VERSION 5.8 ;
BUSBITCHARS "[]" ;
DIVIDERCHAR "/" ;
UNITS
    DATABASE MICRONS 1000 ;
END UNITS

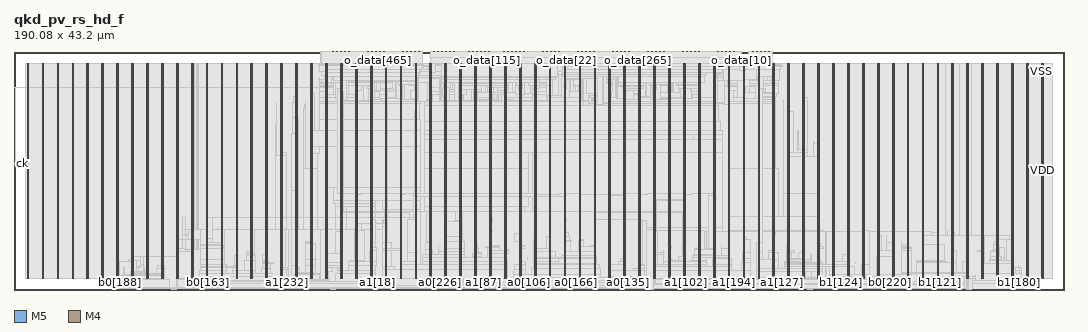
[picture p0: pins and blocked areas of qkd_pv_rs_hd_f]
MACRO qkd_pv_rs_hd_f
  FOREIGN qkd_pv_rs_hd_f 0 0 ;
  CLASS BLOCK ;
  SIZE 190.08 BY 43.2 ;
  PIN a0[0]
    DIRECTION INPUT ;
    USE SIGNAL ;
    PORT
      LAYER M5 ;
        RECT  96.336 0 96.36 0.084 ;
    END
  END a0[0]
  PIN a0[100]
    DIRECTION INPUT ;
    USE SIGNAL ;
    PORT
      LAYER M5 ;
        RECT  92.304 0 92.328 0.084 ;
    END
  END a0[100]
  PIN a0[101]
    DIRECTION INPUT ;
    USE SIGNAL ;
    PORT
      LAYER M5 ;
        RECT  92.448 0 92.472 0.084 ;
    END
  END a0[101]
  PIN a0[102]
    DIRECTION INPUT ;
    USE SIGNAL ;
    PORT
      LAYER M5 ;
        RECT  92.592 0 92.616 0.084 ;
    END
  END a0[102]
  PIN a0[103]
    DIRECTION INPUT ;
    USE SIGNAL ;
    PORT
      LAYER M5 ;
        RECT  92.736 0 92.76 0.084 ;
    END
  END a0[103]
  PIN a0[104]
    DIRECTION INPUT ;
    USE SIGNAL ;
    PORT
      LAYER M5 ;
        RECT  92.88 0 92.904 0.084 ;
    END
  END a0[104]
  PIN a0[105]
    DIRECTION INPUT ;
    USE SIGNAL ;
    PORT
      LAYER M5 ;
        RECT  93.024 0 93.048 0.084 ;
    END
  END a0[105]
  PIN a0[106]
    DIRECTION INPUT ;
    USE SIGNAL ;
    PORT
      LAYER M5 ;
        RECT  93.168 0 93.192 0.084 ;
    END
  END a0[106]
  PIN a0[107]
    DIRECTION INPUT ;
    USE SIGNAL ;
    PORT
      LAYER M5 ;
        RECT  93.312 0 93.336 0.084 ;
    END
  END a0[107]
  PIN a0[108]
    DIRECTION INPUT ;
    USE SIGNAL ;
    PORT
      LAYER M5 ;
        RECT  93.456 0 93.48 0.084 ;
    END
  END a0[108]
  PIN a0[109]
    DIRECTION INPUT ;
    USE SIGNAL ;
    PORT
      LAYER M5 ;
        RECT  93.6 0 93.624 0.084 ;
    END
  END a0[109]
  PIN a0[10]
    DIRECTION INPUT ;
    USE SIGNAL ;
    PORT
      LAYER M5 ;
        RECT  97.776 0 97.8 0.084 ;
    END
  END a0[10]
  PIN a0[110]
    DIRECTION INPUT ;
    USE SIGNAL ;
    PORT
      LAYER M5 ;
        RECT  93.744 0 93.768 0.084 ;
    END
  END a0[110]
  PIN a0[111]
    DIRECTION INPUT ;
    USE SIGNAL ;
    PORT
      LAYER M5 ;
        RECT  93.888 0 93.912 0.084 ;
    END
  END a0[111]
  PIN a0[112]
    DIRECTION INPUT ;
    USE SIGNAL ;
    PORT
      LAYER M5 ;
        RECT  94.032 0 94.056 0.084 ;
    END
  END a0[112]
  PIN a0[113]
    DIRECTION INPUT ;
    USE SIGNAL ;
    PORT
      LAYER M5 ;
        RECT  94.176 0 94.2 0.084 ;
    END
  END a0[113]
  PIN a0[114]
    DIRECTION INPUT ;
    USE SIGNAL ;
    PORT
      LAYER M5 ;
        RECT  94.32 0 94.344 0.084 ;
    END
  END a0[114]
  PIN a0[115]
    DIRECTION INPUT ;
    USE SIGNAL ;
    PORT
      LAYER M5 ;
        RECT  94.464 0 94.488 0.084 ;
    END
  END a0[115]
  PIN a0[116]
    DIRECTION INPUT ;
    USE SIGNAL ;
    PORT
      LAYER M5 ;
        RECT  94.608 0 94.632 0.084 ;
    END
  END a0[116]
  PIN a0[117]
    DIRECTION INPUT ;
    USE SIGNAL ;
    PORT
      LAYER M5 ;
        RECT  94.752 0 94.776 0.084 ;
    END
  END a0[117]
  PIN a0[118]
    DIRECTION INPUT ;
    USE SIGNAL ;
    PORT
      LAYER M5 ;
        RECT  94.896 0 94.92 0.084 ;
    END
  END a0[118]
  PIN a0[119]
    DIRECTION INPUT ;
    USE SIGNAL ;
    PORT
      LAYER M5 ;
        RECT  95.04 0 95.064 0.084 ;
    END
  END a0[119]
  PIN a0[11]
    DIRECTION INPUT ;
    USE SIGNAL ;
    PORT
      LAYER M5 ;
        RECT  97.92 0 97.944 0.084 ;
    END
  END a0[11]
  PIN a0[120]
    DIRECTION INPUT ;
    USE SIGNAL ;
    PORT
      LAYER M5 ;
        RECT  95.184 0 95.208 0.084 ;
    END
  END a0[120]
  PIN a0[121]
    DIRECTION INPUT ;
    USE SIGNAL ;
    PORT
      LAYER M5 ;
        RECT  95.328 0 95.352 0.084 ;
    END
  END a0[121]
  PIN a0[122]
    DIRECTION INPUT ;
    USE SIGNAL ;
    PORT
      LAYER M5 ;
        RECT  95.472 0 95.496 0.084 ;
    END
  END a0[122]
  PIN a0[123]
    DIRECTION INPUT ;
    USE SIGNAL ;
    PORT
      LAYER M5 ;
        RECT  95.616 0 95.64 0.084 ;
    END
  END a0[123]
  PIN a0[124]
    DIRECTION INPUT ;
    USE SIGNAL ;
    PORT
      LAYER M5 ;
        RECT  95.76 0 95.784 0.084 ;
    END
  END a0[124]
  PIN a0[125]
    DIRECTION INPUT ;
    USE SIGNAL ;
    PORT
      LAYER M5 ;
        RECT  95.904 0 95.928 0.084 ;
    END
  END a0[125]
  PIN a0[126]
    DIRECTION INPUT ;
    USE SIGNAL ;
    PORT
      LAYER M5 ;
        RECT  96.048 0 96.072 0.084 ;
    END
  END a0[126]
  PIN a0[127]
    DIRECTION INPUT ;
    USE SIGNAL ;
    PORT
      LAYER M5 ;
        RECT  96.192 0 96.216 0.084 ;
    END
  END a0[127]
  PIN a0[128]
    DIRECTION INPUT ;
    USE SIGNAL ;
    PORT
      LAYER M5 ;
        RECT  110.16 0 110.184 0.084 ;
    END
  END a0[128]
  PIN a0[129]
    DIRECTION INPUT ;
    USE SIGNAL ;
    PORT
      LAYER M5 ;
        RECT  110.304 0 110.328 0.084 ;
    END
  END a0[129]
  PIN a0[12]
    DIRECTION INPUT ;
    USE SIGNAL ;
    PORT
      LAYER M5 ;
        RECT  98.064 0 98.088 0.084 ;
    END
  END a0[12]
  PIN a0[130]
    DIRECTION INPUT ;
    USE SIGNAL ;
    PORT
      LAYER M5 ;
        RECT  110.448 0 110.472 0.084 ;
    END
  END a0[130]
  PIN a0[131]
    DIRECTION INPUT ;
    USE SIGNAL ;
    PORT
      LAYER M5 ;
        RECT  110.592 0 110.616 0.084 ;
    END
  END a0[131]
  PIN a0[132]
    DIRECTION INPUT ;
    USE SIGNAL ;
    PORT
      LAYER M5 ;
        RECT  110.736 0 110.76 0.084 ;
    END
  END a0[132]
  PIN a0[133]
    DIRECTION INPUT ;
    USE SIGNAL ;
    PORT
      LAYER M5 ;
        RECT  110.88 0 110.904 0.084 ;
    END
  END a0[133]
  PIN a0[134]
    DIRECTION INPUT ;
    USE SIGNAL ;
    PORT
      LAYER M5 ;
        RECT  111.024 0 111.048 0.084 ;
    END
  END a0[134]
  PIN a0[135]
    DIRECTION INPUT ;
    USE SIGNAL ;
    PORT
      LAYER M5 ;
        RECT  111.168 0 111.192 0.084 ;
    END
  END a0[135]
  PIN a0[136]
    DIRECTION INPUT ;
    USE SIGNAL ;
    PORT
      LAYER M5 ;
        RECT  111.312 0 111.336 0.084 ;
    END
  END a0[136]
  PIN a0[137]
    DIRECTION INPUT ;
    USE SIGNAL ;
    PORT
      LAYER M5 ;
        RECT  111.456 0 111.48 0.084 ;
    END
  END a0[137]
  PIN a0[138]
    DIRECTION INPUT ;
    USE SIGNAL ;
    PORT
      LAYER M5 ;
        RECT  111.6 0 111.624 0.084 ;
    END
  END a0[138]
  PIN a0[139]
    DIRECTION INPUT ;
    USE SIGNAL ;
    PORT
      LAYER M5 ;
        RECT  111.744 0 111.768 0.084 ;
    END
  END a0[139]
  PIN a0[13]
    DIRECTION INPUT ;
    USE SIGNAL ;
    PORT
      LAYER M5 ;
        RECT  98.208 0 98.232 0.084 ;
    END
  END a0[13]
  PIN a0[140]
    DIRECTION INPUT ;
    USE SIGNAL ;
    PORT
      LAYER M5 ;
        RECT  111.888 0 111.912 0.084 ;
    END
  END a0[140]
  PIN a0[141]
    DIRECTION INPUT ;
    USE SIGNAL ;
    PORT
      LAYER M5 ;
        RECT  112.032 0 112.056 0.084 ;
    END
  END a0[141]
  PIN a0[142]
    DIRECTION INPUT ;
    USE SIGNAL ;
    PORT
      LAYER M5 ;
        RECT  112.176 0 112.2 0.084 ;
    END
  END a0[142]
  PIN a0[143]
    DIRECTION INPUT ;
    USE SIGNAL ;
    PORT
      LAYER M5 ;
        RECT  112.32 0 112.344 0.084 ;
    END
  END a0[143]
  PIN a0[144]
    DIRECTION INPUT ;
    USE SIGNAL ;
    PORT
      LAYER M5 ;
        RECT  112.464 0 112.488 0.084 ;
    END
  END a0[144]
  PIN a0[145]
    DIRECTION INPUT ;
    USE SIGNAL ;
    PORT
      LAYER M5 ;
        RECT  112.608 0 112.632 0.084 ;
    END
  END a0[145]
  PIN a0[146]
    DIRECTION INPUT ;
    USE SIGNAL ;
    PORT
      LAYER M5 ;
        RECT  112.752 0 112.776 0.084 ;
    END
  END a0[146]
  PIN a0[147]
    DIRECTION INPUT ;
    USE SIGNAL ;
    PORT
      LAYER M5 ;
        RECT  112.896 0 112.92 0.084 ;
    END
  END a0[147]
  PIN a0[148]
    DIRECTION INPUT ;
    USE SIGNAL ;
    PORT
      LAYER M5 ;
        RECT  113.04 0 113.064 0.084 ;
    END
  END a0[148]
  PIN a0[149]
    DIRECTION INPUT ;
    USE SIGNAL ;
    PORT
      LAYER M5 ;
        RECT  113.184 0 113.208 0.084 ;
    END
  END a0[149]
  PIN a0[14]
    DIRECTION INPUT ;
    USE SIGNAL ;
    PORT
      LAYER M5 ;
        RECT  98.352 0 98.376 0.084 ;
    END
  END a0[14]
  PIN a0[150]
    DIRECTION INPUT ;
    USE SIGNAL ;
    PORT
      LAYER M5 ;
        RECT  113.328 0 113.352 0.084 ;
    END
  END a0[150]
  PIN a0[151]
    DIRECTION INPUT ;
    USE SIGNAL ;
    PORT
      LAYER M5 ;
        RECT  113.472 0 113.496 0.084 ;
    END
  END a0[151]
  PIN a0[152]
    DIRECTION INPUT ;
    USE SIGNAL ;
    PORT
      LAYER M5 ;
        RECT  113.616 0 113.64 0.084 ;
    END
  END a0[152]
  PIN a0[153]
    DIRECTION INPUT ;
    USE SIGNAL ;
    PORT
      LAYER M5 ;
        RECT  113.76 0 113.784 0.084 ;
    END
  END a0[153]
  PIN a0[154]
    DIRECTION INPUT ;
    USE SIGNAL ;
    PORT
      LAYER M5 ;
        RECT  113.904 0 113.928 0.084 ;
    END
  END a0[154]
  PIN a0[155]
    DIRECTION INPUT ;
    USE SIGNAL ;
    PORT
      LAYER M5 ;
        RECT  114.048 0 114.072 0.084 ;
    END
  END a0[155]
  PIN a0[156]
    DIRECTION INPUT ;
    USE SIGNAL ;
    PORT
      LAYER M5 ;
        RECT  114.192 0 114.216 0.084 ;
    END
  END a0[156]
  PIN a0[157]
    DIRECTION INPUT ;
    USE SIGNAL ;
    PORT
      LAYER M5 ;
        RECT  114.336 0 114.36 0.084 ;
    END
  END a0[157]
  PIN a0[158]
    DIRECTION INPUT ;
    USE SIGNAL ;
    PORT
      LAYER M5 ;
        RECT  114.48 0 114.504 0.084 ;
    END
  END a0[158]
  PIN a0[159]
    DIRECTION INPUT ;
    USE SIGNAL ;
    PORT
      LAYER M5 ;
        RECT  114.624 0 114.648 0.084 ;
    END
  END a0[159]
  PIN a0[15]
    DIRECTION INPUT ;
    USE SIGNAL ;
    PORT
      LAYER M5 ;
        RECT  98.496 0 98.52 0.084 ;
    END
  END a0[15]
  PIN a0[160]
    DIRECTION INPUT ;
    USE SIGNAL ;
    PORT
      LAYER M5 ;
        RECT  100.944 0 100.968 0.084 ;
    END
  END a0[160]
  PIN a0[161]
    DIRECTION INPUT ;
    USE SIGNAL ;
    PORT
      LAYER M5 ;
        RECT  101.088 0 101.112 0.084 ;
    END
  END a0[161]
  PIN a0[162]
    DIRECTION INPUT ;
    USE SIGNAL ;
    PORT
      LAYER M5 ;
        RECT  101.232 0 101.256 0.084 ;
    END
  END a0[162]
  PIN a0[163]
    DIRECTION INPUT ;
    USE SIGNAL ;
    PORT
      LAYER M5 ;
        RECT  101.376 0 101.4 0.084 ;
    END
  END a0[163]
  PIN a0[164]
    DIRECTION INPUT ;
    USE SIGNAL ;
    PORT
      LAYER M5 ;
        RECT  101.52 0 101.544 0.084 ;
    END
  END a0[164]
  PIN a0[165]
    DIRECTION INPUT ;
    USE SIGNAL ;
    PORT
      LAYER M5 ;
        RECT  101.664 0 101.688 0.084 ;
    END
  END a0[165]
  PIN a0[166]
    DIRECTION INPUT ;
    USE SIGNAL ;
    PORT
      LAYER M5 ;
        RECT  101.808 0 101.832 0.084 ;
    END
  END a0[166]
  PIN a0[167]
    DIRECTION INPUT ;
    USE SIGNAL ;
    PORT
      LAYER M5 ;
        RECT  101.952 0 101.976 0.084 ;
    END
  END a0[167]
  PIN a0[168]
    DIRECTION INPUT ;
    USE SIGNAL ;
    PORT
      LAYER M5 ;
        RECT  102.096 0 102.12 0.084 ;
    END
  END a0[168]
  PIN a0[169]
    DIRECTION INPUT ;
    USE SIGNAL ;
    PORT
      LAYER M5 ;
        RECT  102.24 0 102.264 0.084 ;
    END
  END a0[169]
  PIN a0[16]
    DIRECTION INPUT ;
    USE SIGNAL ;
    PORT
      LAYER M5 ;
        RECT  98.64 0 98.664 0.084 ;
    END
  END a0[16]
  PIN a0[170]
    DIRECTION INPUT ;
    USE SIGNAL ;
    PORT
      LAYER M5 ;
        RECT  102.384 0 102.408 0.084 ;
    END
  END a0[170]
  PIN a0[171]
    DIRECTION INPUT ;
    USE SIGNAL ;
    PORT
      LAYER M5 ;
        RECT  102.528 0 102.552 0.084 ;
    END
  END a0[171]
  PIN a0[172]
    DIRECTION INPUT ;
    USE SIGNAL ;
    PORT
      LAYER M5 ;
        RECT  102.672 0 102.696 0.084 ;
    END
  END a0[172]
  PIN a0[173]
    DIRECTION INPUT ;
    USE SIGNAL ;
    PORT
      LAYER M5 ;
        RECT  102.816 0 102.84 0.084 ;
    END
  END a0[173]
  PIN a0[174]
    DIRECTION INPUT ;
    USE SIGNAL ;
    PORT
      LAYER M5 ;
        RECT  102.96 0 102.984 0.084 ;
    END
  END a0[174]
  PIN a0[175]
    DIRECTION INPUT ;
    USE SIGNAL ;
    PORT
      LAYER M5 ;
        RECT  103.104 0 103.128 0.084 ;
    END
  END a0[175]
  PIN a0[176]
    DIRECTION INPUT ;
    USE SIGNAL ;
    PORT
      LAYER M5 ;
        RECT  103.248 0 103.272 0.084 ;
    END
  END a0[176]
  PIN a0[177]
    DIRECTION INPUT ;
    USE SIGNAL ;
    PORT
      LAYER M5 ;
        RECT  103.392 0 103.416 0.084 ;
    END
  END a0[177]
  PIN a0[178]
    DIRECTION INPUT ;
    USE SIGNAL ;
    PORT
      LAYER M5 ;
        RECT  103.536 0 103.56 0.084 ;
    END
  END a0[178]
  PIN a0[179]
    DIRECTION INPUT ;
    USE SIGNAL ;
    PORT
      LAYER M5 ;
        RECT  103.68 0 103.704 0.084 ;
    END
  END a0[179]
  PIN a0[17]
    DIRECTION INPUT ;
    USE SIGNAL ;
    PORT
      LAYER M5 ;
        RECT  98.784 0 98.808 0.084 ;
    END
  END a0[17]
  PIN a0[180]
    DIRECTION INPUT ;
    USE SIGNAL ;
    PORT
      LAYER M5 ;
        RECT  103.824 0 103.848 0.084 ;
    END
  END a0[180]
  PIN a0[181]
    DIRECTION INPUT ;
    USE SIGNAL ;
    PORT
      LAYER M5 ;
        RECT  103.968 0 103.992 0.084 ;
    END
  END a0[181]
  PIN a0[182]
    DIRECTION INPUT ;
    USE SIGNAL ;
    PORT
      LAYER M5 ;
        RECT  104.112 0 104.136 0.084 ;
    END
  END a0[182]
  PIN a0[183]
    DIRECTION INPUT ;
    USE SIGNAL ;
    PORT
      LAYER M5 ;
        RECT  104.256 0 104.28 0.084 ;
    END
  END a0[183]
  PIN a0[184]
    DIRECTION INPUT ;
    USE SIGNAL ;
    PORT
      LAYER M5 ;
        RECT  104.4 0 104.424 0.084 ;
    END
  END a0[184]
  PIN a0[185]
    DIRECTION INPUT ;
    USE SIGNAL ;
    PORT
      LAYER M5 ;
        RECT  104.544 0 104.568 0.084 ;
    END
  END a0[185]
  PIN a0[186]
    DIRECTION INPUT ;
    USE SIGNAL ;
    PORT
      LAYER M5 ;
        RECT  104.688 0 104.712 0.084 ;
    END
  END a0[186]
  PIN a0[187]
    DIRECTION INPUT ;
    USE SIGNAL ;
    PORT
      LAYER M5 ;
        RECT  104.832 0 104.856 0.084 ;
    END
  END a0[187]
  PIN a0[188]
    DIRECTION INPUT ;
    USE SIGNAL ;
    PORT
      LAYER M5 ;
        RECT  104.976 0 105 0.084 ;
    END
  END a0[188]
  PIN a0[189]
    DIRECTION INPUT ;
    USE SIGNAL ;
    PORT
      LAYER M5 ;
        RECT  105.12 0 105.144 0.084 ;
    END
  END a0[189]
  PIN a0[18]
    DIRECTION INPUT ;
    USE SIGNAL ;
    PORT
      LAYER M5 ;
        RECT  98.928 0 98.952 0.084 ;
    END
  END a0[18]
  PIN a0[190]
    DIRECTION INPUT ;
    USE SIGNAL ;
    PORT
      LAYER M5 ;
        RECT  105.264 0 105.288 0.084 ;
    END
  END a0[190]
  PIN a0[191]
    DIRECTION INPUT ;
    USE SIGNAL ;
    PORT
      LAYER M5 ;
        RECT  105.408 0 105.432 0.084 ;
    END
  END a0[191]
  PIN a0[192]
    DIRECTION INPUT ;
    USE SIGNAL ;
    PORT
      LAYER M5 ;
        RECT  58.32 0 58.344 0.084 ;
    END
  END a0[192]
  PIN a0[193]
    DIRECTION INPUT ;
    USE SIGNAL ;
    PORT
      LAYER M5 ;
        RECT  58.464 0 58.488 0.084 ;
    END
  END a0[193]
  PIN a0[194]
    DIRECTION INPUT ;
    USE SIGNAL ;
    PORT
      LAYER M5 ;
        RECT  58.608 0 58.632 0.084 ;
    END
  END a0[194]
  PIN a0[195]
    DIRECTION INPUT ;
    USE SIGNAL ;
    PORT
      LAYER M5 ;
        RECT  58.752 0 58.776 0.084 ;
    END
  END a0[195]
  PIN a0[196]
    DIRECTION INPUT ;
    USE SIGNAL ;
    PORT
      LAYER M5 ;
        RECT  58.896 0 58.92 0.084 ;
    END
  END a0[196]
  PIN a0[197]
    DIRECTION INPUT ;
    USE SIGNAL ;
    PORT
      LAYER M5 ;
        RECT  59.04 0 59.064 0.084 ;
    END
  END a0[197]
  PIN a0[198]
    DIRECTION INPUT ;
    USE SIGNAL ;
    PORT
      LAYER M5 ;
        RECT  59.184 0 59.208 0.084 ;
    END
  END a0[198]
  PIN a0[199]
    DIRECTION INPUT ;
    USE SIGNAL ;
    PORT
      LAYER M5 ;
        RECT  59.328 0 59.352 0.084 ;
    END
  END a0[199]
  PIN a0[19]
    DIRECTION INPUT ;
    USE SIGNAL ;
    PORT
      LAYER M5 ;
        RECT  99.072 0 99.096 0.084 ;
    END
  END a0[19]
  PIN a0[1]
    DIRECTION INPUT ;
    USE SIGNAL ;
    PORT
      LAYER M5 ;
        RECT  96.48 0 96.504 0.084 ;
    END
  END a0[1]
  PIN a0[200]
    DIRECTION INPUT ;
    USE SIGNAL ;
    PORT
      LAYER M5 ;
        RECT  59.472 0 59.496 0.084 ;
    END
  END a0[200]
  PIN a0[201]
    DIRECTION INPUT ;
    USE SIGNAL ;
    PORT
      LAYER M5 ;
        RECT  59.616 0 59.64 0.084 ;
    END
  END a0[201]
  PIN a0[202]
    DIRECTION INPUT ;
    USE SIGNAL ;
    PORT
      LAYER M5 ;
        RECT  59.76 0 59.784 0.084 ;
    END
  END a0[202]
  PIN a0[203]
    DIRECTION INPUT ;
    USE SIGNAL ;
    PORT
      LAYER M5 ;
        RECT  59.904 0 59.928 0.084 ;
    END
  END a0[203]
  PIN a0[204]
    DIRECTION INPUT ;
    USE SIGNAL ;
    PORT
      LAYER M5 ;
        RECT  60.048 0 60.072 0.084 ;
    END
  END a0[204]
  PIN a0[205]
    DIRECTION INPUT ;
    USE SIGNAL ;
    PORT
      LAYER M5 ;
        RECT  60.192 0 60.216 0.084 ;
    END
  END a0[205]
  PIN a0[206]
    DIRECTION INPUT ;
    USE SIGNAL ;
    PORT
      LAYER M5 ;
        RECT  60.336 0 60.36 0.084 ;
    END
  END a0[206]
  PIN a0[207]
    DIRECTION INPUT ;
    USE SIGNAL ;
    PORT
      LAYER M5 ;
        RECT  60.48 0 60.504 0.084 ;
    END
  END a0[207]
  PIN a0[208]
    DIRECTION INPUT ;
    USE SIGNAL ;
    PORT
      LAYER M5 ;
        RECT  60.624 0 60.648 0.084 ;
    END
  END a0[208]
  PIN a0[209]
    DIRECTION INPUT ;
    USE SIGNAL ;
    PORT
      LAYER M5 ;
        RECT  60.768 0 60.792 0.084 ;
    END
  END a0[209]
  PIN a0[20]
    DIRECTION INPUT ;
    USE SIGNAL ;
    PORT
      LAYER M5 ;
        RECT  99.216 0 99.24 0.084 ;
    END
  END a0[20]
  PIN a0[210]
    DIRECTION INPUT ;
    USE SIGNAL ;
    PORT
      LAYER M5 ;
        RECT  60.912 0 60.936 0.084 ;
    END
  END a0[210]
  PIN a0[211]
    DIRECTION INPUT ;
    USE SIGNAL ;
    PORT
      LAYER M5 ;
        RECT  61.056 0 61.08 0.084 ;
    END
  END a0[211]
  PIN a0[212]
    DIRECTION INPUT ;
    USE SIGNAL ;
    PORT
      LAYER M5 ;
        RECT  61.2 0 61.224 0.084 ;
    END
  END a0[212]
  PIN a0[213]
    DIRECTION INPUT ;
    USE SIGNAL ;
    PORT
      LAYER M5 ;
        RECT  61.344 0 61.368 0.084 ;
    END
  END a0[213]
  PIN a0[214]
    DIRECTION INPUT ;
    USE SIGNAL ;
    PORT
      LAYER M5 ;
        RECT  61.488 0 61.512 0.084 ;
    END
  END a0[214]
  PIN a0[215]
    DIRECTION INPUT ;
    USE SIGNAL ;
    PORT
      LAYER M5 ;
        RECT  61.632 0 61.656 0.084 ;
    END
  END a0[215]
  PIN a0[216]
    DIRECTION INPUT ;
    USE SIGNAL ;
    PORT
      LAYER M5 ;
        RECT  61.776 0 61.8 0.084 ;
    END
  END a0[216]
  PIN a0[217]
    DIRECTION INPUT ;
    USE SIGNAL ;
    PORT
      LAYER M5 ;
        RECT  61.92 0 61.944 0.084 ;
    END
  END a0[217]
  PIN a0[218]
    DIRECTION INPUT ;
    USE SIGNAL ;
    PORT
      LAYER M5 ;
        RECT  62.064 0 62.088 0.084 ;
    END
  END a0[218]
  PIN a0[219]
    DIRECTION INPUT ;
    USE SIGNAL ;
    PORT
      LAYER M5 ;
        RECT  62.208 0 62.232 0.084 ;
    END
  END a0[219]
  PIN a0[21]
    DIRECTION INPUT ;
    USE SIGNAL ;
    PORT
      LAYER M5 ;
        RECT  99.36 0 99.384 0.084 ;
    END
  END a0[21]
  PIN a0[220]
    DIRECTION INPUT ;
    USE SIGNAL ;
    PORT
      LAYER M5 ;
        RECT  62.352 0 62.376 0.084 ;
    END
  END a0[220]
  PIN a0[221]
    DIRECTION INPUT ;
    USE SIGNAL ;
    PORT
      LAYER M5 ;
        RECT  62.496 0 62.52 0.084 ;
    END
  END a0[221]
  PIN a0[222]
    DIRECTION INPUT ;
    USE SIGNAL ;
    PORT
      LAYER M5 ;
        RECT  62.64 0 62.664 0.084 ;
    END
  END a0[222]
  PIN a0[223]
    DIRECTION INPUT ;
    USE SIGNAL ;
    PORT
      LAYER M5 ;
        RECT  62.784 0 62.808 0.084 ;
    END
  END a0[223]
  PIN a0[224]
    DIRECTION INPUT ;
    USE SIGNAL ;
    PORT
      LAYER M5 ;
        RECT  76.752 0 76.776 0.084 ;
    END
  END a0[224]
  PIN a0[225]
    DIRECTION INPUT ;
    USE SIGNAL ;
    PORT
      LAYER M5 ;
        RECT  76.896 0 76.92 0.084 ;
    END
  END a0[225]
  PIN a0[226]
    DIRECTION INPUT ;
    USE SIGNAL ;
    PORT
      LAYER M5 ;
        RECT  77.04 0 77.064 0.084 ;
    END
  END a0[226]
  PIN a0[227]
    DIRECTION INPUT ;
    USE SIGNAL ;
    PORT
      LAYER M5 ;
        RECT  77.184 0 77.208 0.084 ;
    END
  END a0[227]
  PIN a0[228]
    DIRECTION INPUT ;
    USE SIGNAL ;
    PORT
      LAYER M5 ;
        RECT  77.328 0 77.352 0.084 ;
    END
  END a0[228]
  PIN a0[229]
    DIRECTION INPUT ;
    USE SIGNAL ;
    PORT
      LAYER M5 ;
        RECT  77.472 0 77.496 0.084 ;
    END
  END a0[229]
  PIN a0[22]
    DIRECTION INPUT ;
    USE SIGNAL ;
    PORT
      LAYER M5 ;
        RECT  99.504 0 99.528 0.084 ;
    END
  END a0[22]
  PIN a0[230]
    DIRECTION INPUT ;
    USE SIGNAL ;
    PORT
      LAYER M5 ;
        RECT  77.616 0 77.64 0.084 ;
    END
  END a0[230]
  PIN a0[231]
    DIRECTION INPUT ;
    USE SIGNAL ;
    PORT
      LAYER M5 ;
        RECT  77.76 0 77.784 0.084 ;
    END
  END a0[231]
  PIN a0[232]
    DIRECTION INPUT ;
    USE SIGNAL ;
    PORT
      LAYER M5 ;
        RECT  77.904 0 77.928 0.084 ;
    END
  END a0[232]
  PIN a0[233]
    DIRECTION INPUT ;
    USE SIGNAL ;
    PORT
      LAYER M5 ;
        RECT  78.048 0 78.072 0.084 ;
    END
  END a0[233]
  PIN a0[234]
    DIRECTION INPUT ;
    USE SIGNAL ;
    PORT
      LAYER M5 ;
        RECT  78.192 0 78.216 0.084 ;
    END
  END a0[234]
  PIN a0[235]
    DIRECTION INPUT ;
    USE SIGNAL ;
    PORT
      LAYER M5 ;
        RECT  78.336 0 78.36 0.084 ;
    END
  END a0[235]
  PIN a0[236]
    DIRECTION INPUT ;
    USE SIGNAL ;
    PORT
      LAYER M5 ;
        RECT  78.48 0 78.504 0.084 ;
    END
  END a0[236]
  PIN a0[237]
    DIRECTION INPUT ;
    USE SIGNAL ;
    PORT
      LAYER M5 ;
        RECT  78.624 0 78.648 0.084 ;
    END
  END a0[237]
  PIN a0[238]
    DIRECTION INPUT ;
    USE SIGNAL ;
    PORT
      LAYER M5 ;
        RECT  78.768 0 78.792 0.084 ;
    END
  END a0[238]
  PIN a0[239]
    DIRECTION INPUT ;
    USE SIGNAL ;
    PORT
      LAYER M5 ;
        RECT  78.912 0 78.936 0.084 ;
    END
  END a0[239]
  PIN a0[23]
    DIRECTION INPUT ;
    USE SIGNAL ;
    PORT
      LAYER M5 ;
        RECT  99.648 0 99.672 0.084 ;
    END
  END a0[23]
  PIN a0[240]
    DIRECTION INPUT ;
    USE SIGNAL ;
    PORT
      LAYER M5 ;
        RECT  79.056 0 79.08 0.084 ;
    END
  END a0[240]
  PIN a0[241]
    DIRECTION INPUT ;
    USE SIGNAL ;
    PORT
      LAYER M5 ;
        RECT  79.2 0 79.224 0.084 ;
    END
  END a0[241]
  PIN a0[242]
    DIRECTION INPUT ;
    USE SIGNAL ;
    PORT
      LAYER M5 ;
        RECT  79.344 0 79.368 0.084 ;
    END
  END a0[242]
  PIN a0[243]
    DIRECTION INPUT ;
    USE SIGNAL ;
    PORT
      LAYER M5 ;
        RECT  79.488 0 79.512 0.084 ;
    END
  END a0[243]
  PIN a0[244]
    DIRECTION INPUT ;
    USE SIGNAL ;
    PORT
      LAYER M5 ;
        RECT  79.632 0 79.656 0.084 ;
    END
  END a0[244]
  PIN a0[245]
    DIRECTION INPUT ;
    USE SIGNAL ;
    PORT
      LAYER M5 ;
        RECT  79.776 0 79.8 0.084 ;
    END
  END a0[245]
  PIN a0[246]
    DIRECTION INPUT ;
    USE SIGNAL ;
    PORT
      LAYER M5 ;
        RECT  79.92 0 79.944 0.084 ;
    END
  END a0[246]
  PIN a0[247]
    DIRECTION INPUT ;
    USE SIGNAL ;
    PORT
      LAYER M5 ;
        RECT  80.064 0 80.088 0.084 ;
    END
  END a0[247]
  PIN a0[248]
    DIRECTION INPUT ;
    USE SIGNAL ;
    PORT
      LAYER M5 ;
        RECT  80.208 0 80.232 0.084 ;
    END
  END a0[248]
  PIN a0[249]
    DIRECTION INPUT ;
    USE SIGNAL ;
    PORT
      LAYER M5 ;
        RECT  80.352 0 80.376 0.084 ;
    END
  END a0[249]
  PIN a0[24]
    DIRECTION INPUT ;
    USE SIGNAL ;
    PORT
      LAYER M5 ;
        RECT  99.792 0 99.816 0.084 ;
    END
  END a0[24]
  PIN a0[250]
    DIRECTION INPUT ;
    USE SIGNAL ;
    PORT
      LAYER M5 ;
        RECT  80.496 0 80.52 0.084 ;
    END
  END a0[250]
  PIN a0[251]
    DIRECTION INPUT ;
    USE SIGNAL ;
    PORT
      LAYER M5 ;
        RECT  80.64 0 80.664 0.084 ;
    END
  END a0[251]
  PIN a0[252]
    DIRECTION INPUT ;
    USE SIGNAL ;
    PORT
      LAYER M5 ;
        RECT  80.784 0 80.808 0.084 ;
    END
  END a0[252]
  PIN a0[253]
    DIRECTION INPUT ;
    USE SIGNAL ;
    PORT
      LAYER M5 ;
        RECT  80.928 0 80.952 0.084 ;
    END
  END a0[253]
  PIN a0[254]
    DIRECTION INPUT ;
    USE SIGNAL ;
    PORT
      LAYER M5 ;
        RECT  81.072 0 81.096 0.084 ;
    END
  END a0[254]
  PIN a0[255]
    DIRECTION INPUT ;
    USE SIGNAL ;
    PORT
      LAYER M5 ;
        RECT  81.216 0 81.24 0.084 ;
    END
  END a0[255]
  PIN a0[256]
    DIRECTION INPUT ;
    USE SIGNAL ;
    PORT
      LAYER M5 ;
        RECT  72.144 0 72.168 0.084 ;
    END
  END a0[256]
  PIN a0[257]
    DIRECTION INPUT ;
    USE SIGNAL ;
    PORT
      LAYER M5 ;
        RECT  72.288 0 72.312 0.084 ;
    END
  END a0[257]
  PIN a0[25]
    DIRECTION INPUT ;
    USE SIGNAL ;
    PORT
      LAYER M5 ;
        RECT  99.936 0 99.96 0.084 ;
    END
  END a0[25]
  PIN a0[26]
    DIRECTION INPUT ;
    USE SIGNAL ;
    PORT
      LAYER M5 ;
        RECT  100.08 0 100.104 0.084 ;
    END
  END a0[26]
  PIN a0[27]
    DIRECTION INPUT ;
    USE SIGNAL ;
    PORT
      LAYER M5 ;
        RECT  100.224 0 100.248 0.084 ;
    END
  END a0[27]
  PIN a0[28]
    DIRECTION INPUT ;
    USE SIGNAL ;
    PORT
      LAYER M5 ;
        RECT  100.368 0 100.392 0.084 ;
    END
  END a0[28]
  PIN a0[29]
    DIRECTION INPUT ;
    USE SIGNAL ;
    PORT
      LAYER M5 ;
        RECT  100.512 0 100.536 0.084 ;
    END
  END a0[29]
  PIN a0[2]
    DIRECTION INPUT ;
    USE SIGNAL ;
    PORT
      LAYER M5 ;
        RECT  96.624 0 96.648 0.084 ;
    END
  END a0[2]
  PIN a0[30]
    DIRECTION INPUT ;
    USE SIGNAL ;
    PORT
      LAYER M5 ;
        RECT  100.656 0 100.68 0.084 ;
    END
  END a0[30]
  PIN a0[31]
    DIRECTION INPUT ;
    USE SIGNAL ;
    PORT
      LAYER M5 ;
        RECT  100.8 0 100.824 0.084 ;
    END
  END a0[31]
  PIN a0[32]
    DIRECTION INPUT ;
    USE SIGNAL ;
    PORT
      LAYER M5 ;
        RECT  105.552 0 105.576 0.084 ;
    END
  END a0[32]
  PIN a0[33]
    DIRECTION INPUT ;
    USE SIGNAL ;
    PORT
      LAYER M5 ;
        RECT  105.696 0 105.72 0.084 ;
    END
  END a0[33]
  PIN a0[34]
    DIRECTION INPUT ;
    USE SIGNAL ;
    PORT
      LAYER M5 ;
        RECT  105.84 0 105.864 0.084 ;
    END
  END a0[34]
  PIN a0[35]
    DIRECTION INPUT ;
    USE SIGNAL ;
    PORT
      LAYER M5 ;
        RECT  105.984 0 106.008 0.084 ;
    END
  END a0[35]
  PIN a0[36]
    DIRECTION INPUT ;
    USE SIGNAL ;
    PORT
      LAYER M5 ;
        RECT  106.128 0 106.152 0.084 ;
    END
  END a0[36]
  PIN a0[37]
    DIRECTION INPUT ;
    USE SIGNAL ;
    PORT
      LAYER M5 ;
        RECT  106.272 0 106.296 0.084 ;
    END
  END a0[37]
  PIN a0[38]
    DIRECTION INPUT ;
    USE SIGNAL ;
    PORT
      LAYER M5 ;
        RECT  106.416 0 106.44 0.084 ;
    END
  END a0[38]
  PIN a0[39]
    DIRECTION INPUT ;
    USE SIGNAL ;
    PORT
      LAYER M5 ;
        RECT  106.56 0 106.584 0.084 ;
    END
  END a0[39]
  PIN a0[3]
    DIRECTION INPUT ;
    USE SIGNAL ;
    PORT
      LAYER M5 ;
        RECT  96.768 0 96.792 0.084 ;
    END
  END a0[3]
  PIN a0[40]
    DIRECTION INPUT ;
    USE SIGNAL ;
    PORT
      LAYER M5 ;
        RECT  106.704 0 106.728 0.084 ;
    END
  END a0[40]
  PIN a0[41]
    DIRECTION INPUT ;
    USE SIGNAL ;
    PORT
      LAYER M5 ;
        RECT  106.848 0 106.872 0.084 ;
    END
  END a0[41]
  PIN a0[42]
    DIRECTION INPUT ;
    USE SIGNAL ;
    PORT
      LAYER M5 ;
        RECT  106.992 0 107.016 0.084 ;
    END
  END a0[42]
  PIN a0[43]
    DIRECTION INPUT ;
    USE SIGNAL ;
    PORT
      LAYER M5 ;
        RECT  107.136 0 107.16 0.084 ;
    END
  END a0[43]
  PIN a0[44]
    DIRECTION INPUT ;
    USE SIGNAL ;
    PORT
      LAYER M5 ;
        RECT  107.28 0 107.304 0.084 ;
    END
  END a0[44]
  PIN a0[45]
    DIRECTION INPUT ;
    USE SIGNAL ;
    PORT
      LAYER M5 ;
        RECT  107.424 0 107.448 0.084 ;
    END
  END a0[45]
  PIN a0[46]
    DIRECTION INPUT ;
    USE SIGNAL ;
    PORT
      LAYER M5 ;
        RECT  107.568 0 107.592 0.084 ;
    END
  END a0[46]
  PIN a0[47]
    DIRECTION INPUT ;
    USE SIGNAL ;
    PORT
      LAYER M5 ;
        RECT  107.712 0 107.736 0.084 ;
    END
  END a0[47]
  PIN a0[48]
    DIRECTION INPUT ;
    USE SIGNAL ;
    PORT
      LAYER M5 ;
        RECT  107.856 0 107.88 0.084 ;
    END
  END a0[48]
  PIN a0[49]
    DIRECTION INPUT ;
    USE SIGNAL ;
    PORT
      LAYER M5 ;
        RECT  108 0 108.024 0.084 ;
    END
  END a0[49]
  PIN a0[4]
    DIRECTION INPUT ;
    USE SIGNAL ;
    PORT
      LAYER M5 ;
        RECT  96.912 0 96.936 0.084 ;
    END
  END a0[4]
  PIN a0[50]
    DIRECTION INPUT ;
    USE SIGNAL ;
    PORT
      LAYER M5 ;
        RECT  108.144 0 108.168 0.084 ;
    END
  END a0[50]
  PIN a0[51]
    DIRECTION INPUT ;
    USE SIGNAL ;
    PORT
      LAYER M5 ;
        RECT  108.288 0 108.312 0.084 ;
    END
  END a0[51]
  PIN a0[52]
    DIRECTION INPUT ;
    USE SIGNAL ;
    PORT
      LAYER M5 ;
        RECT  108.432 0 108.456 0.084 ;
    END
  END a0[52]
  PIN a0[53]
    DIRECTION INPUT ;
    USE SIGNAL ;
    PORT
      LAYER M5 ;
        RECT  108.576 0 108.6 0.084 ;
    END
  END a0[53]
  PIN a0[54]
    DIRECTION INPUT ;
    USE SIGNAL ;
    PORT
      LAYER M5 ;
        RECT  108.72 0 108.744 0.084 ;
    END
  END a0[54]
  PIN a0[55]
    DIRECTION INPUT ;
    USE SIGNAL ;
    PORT
      LAYER M5 ;
        RECT  108.864 0 108.888 0.084 ;
    END
  END a0[55]
  PIN a0[56]
    DIRECTION INPUT ;
    USE SIGNAL ;
    PORT
      LAYER M5 ;
        RECT  109.008 0 109.032 0.084 ;
    END
  END a0[56]
  PIN a0[57]
    DIRECTION INPUT ;
    USE SIGNAL ;
    PORT
      LAYER M5 ;
        RECT  109.152 0 109.176 0.084 ;
    END
  END a0[57]
  PIN a0[58]
    DIRECTION INPUT ;
    USE SIGNAL ;
    PORT
      LAYER M5 ;
        RECT  109.296 0 109.32 0.084 ;
    END
  END a0[58]
  PIN a0[59]
    DIRECTION INPUT ;
    USE SIGNAL ;
    PORT
      LAYER M5 ;
        RECT  109.44 0 109.464 0.084 ;
    END
  END a0[59]
  PIN a0[5]
    DIRECTION INPUT ;
    USE SIGNAL ;
    PORT
      LAYER M5 ;
        RECT  97.056 0 97.08 0.084 ;
    END
  END a0[5]
  PIN a0[60]
    DIRECTION INPUT ;
    USE SIGNAL ;
    PORT
      LAYER M5 ;
        RECT  109.584 0 109.608 0.084 ;
    END
  END a0[60]
  PIN a0[61]
    DIRECTION INPUT ;
    USE SIGNAL ;
    PORT
      LAYER M5 ;
        RECT  109.728 0 109.752 0.084 ;
    END
  END a0[61]
  PIN a0[62]
    DIRECTION INPUT ;
    USE SIGNAL ;
    PORT
      LAYER M5 ;
        RECT  109.872 0 109.896 0.084 ;
    END
  END a0[62]
  PIN a0[63]
    DIRECTION INPUT ;
    USE SIGNAL ;
    PORT
      LAYER M5 ;
        RECT  110.016 0 110.04 0.084 ;
    END
  END a0[63]
  PIN a0[64]
    DIRECTION INPUT ;
    USE SIGNAL ;
    PORT
      LAYER M5 ;
        RECT  87.12 0 87.144 0.084 ;
    END
  END a0[64]
  PIN a0[65]
    DIRECTION INPUT ;
    USE SIGNAL ;
    PORT
      LAYER M5 ;
        RECT  87.264 0 87.288 0.084 ;
    END
  END a0[65]
  PIN a0[66]
    DIRECTION INPUT ;
    USE SIGNAL ;
    PORT
      LAYER M5 ;
        RECT  87.408 0 87.432 0.084 ;
    END
  END a0[66]
  PIN a0[67]
    DIRECTION INPUT ;
    USE SIGNAL ;
    PORT
      LAYER M5 ;
        RECT  87.552 0 87.576 0.084 ;
    END
  END a0[67]
  PIN a0[68]
    DIRECTION INPUT ;
    USE SIGNAL ;
    PORT
      LAYER M5 ;
        RECT  87.696 0 87.72 0.084 ;
    END
  END a0[68]
  PIN a0[69]
    DIRECTION INPUT ;
    USE SIGNAL ;
    PORT
      LAYER M5 ;
        RECT  87.84 0 87.864 0.084 ;
    END
  END a0[69]
  PIN a0[6]
    DIRECTION INPUT ;
    USE SIGNAL ;
    PORT
      LAYER M5 ;
        RECT  97.2 0 97.224 0.084 ;
    END
  END a0[6]
  PIN a0[70]
    DIRECTION INPUT ;
    USE SIGNAL ;
    PORT
      LAYER M5 ;
        RECT  87.984 0 88.008 0.084 ;
    END
  END a0[70]
  PIN a0[71]
    DIRECTION INPUT ;
    USE SIGNAL ;
    PORT
      LAYER M5 ;
        RECT  88.128 0 88.152 0.084 ;
    END
  END a0[71]
  PIN a0[72]
    DIRECTION INPUT ;
    USE SIGNAL ;
    PORT
      LAYER M5 ;
        RECT  88.272 0 88.296 0.084 ;
    END
  END a0[72]
  PIN a0[73]
    DIRECTION INPUT ;
    USE SIGNAL ;
    PORT
      LAYER M5 ;
        RECT  88.416 0 88.44 0.084 ;
    END
  END a0[73]
  PIN a0[74]
    DIRECTION INPUT ;
    USE SIGNAL ;
    PORT
      LAYER M5 ;
        RECT  88.56 0 88.584 0.084 ;
    END
  END a0[74]
  PIN a0[75]
    DIRECTION INPUT ;
    USE SIGNAL ;
    PORT
      LAYER M5 ;
        RECT  88.704 0 88.728 0.084 ;
    END
  END a0[75]
  PIN a0[76]
    DIRECTION INPUT ;
    USE SIGNAL ;
    PORT
      LAYER M5 ;
        RECT  88.848 0 88.872 0.084 ;
    END
  END a0[76]
  PIN a0[77]
    DIRECTION INPUT ;
    USE SIGNAL ;
    PORT
      LAYER M5 ;
        RECT  88.992 0 89.016 0.084 ;
    END
  END a0[77]
  PIN a0[78]
    DIRECTION INPUT ;
    USE SIGNAL ;
    PORT
      LAYER M5 ;
        RECT  89.136 0 89.16 0.084 ;
    END
  END a0[78]
  PIN a0[79]
    DIRECTION INPUT ;
    USE SIGNAL ;
    PORT
      LAYER M5 ;
        RECT  89.28 0 89.304 0.084 ;
    END
  END a0[79]
  PIN a0[7]
    DIRECTION INPUT ;
    USE SIGNAL ;
    PORT
      LAYER M5 ;
        RECT  97.344 0 97.368 0.084 ;
    END
  END a0[7]
  PIN a0[80]
    DIRECTION INPUT ;
    USE SIGNAL ;
    PORT
      LAYER M5 ;
        RECT  89.424 0 89.448 0.084 ;
    END
  END a0[80]
  PIN a0[81]
    DIRECTION INPUT ;
    USE SIGNAL ;
    PORT
      LAYER M5 ;
        RECT  89.568 0 89.592 0.084 ;
    END
  END a0[81]
  PIN a0[82]
    DIRECTION INPUT ;
    USE SIGNAL ;
    PORT
      LAYER M5 ;
        RECT  89.712 0 89.736 0.084 ;
    END
  END a0[82]
  PIN a0[83]
    DIRECTION INPUT ;
    USE SIGNAL ;
    PORT
      LAYER M5 ;
        RECT  89.856 0 89.88 0.084 ;
    END
  END a0[83]
  PIN a0[84]
    DIRECTION INPUT ;
    USE SIGNAL ;
    PORT
      LAYER M5 ;
        RECT  90 0 90.024 0.084 ;
    END
  END a0[84]
  PIN a0[85]
    DIRECTION INPUT ;
    USE SIGNAL ;
    PORT
      LAYER M5 ;
        RECT  90.144 0 90.168 0.084 ;
    END
  END a0[85]
  PIN a0[86]
    DIRECTION INPUT ;
    USE SIGNAL ;
    PORT
      LAYER M5 ;
        RECT  90.288 0 90.312 0.084 ;
    END
  END a0[86]
  PIN a0[87]
    DIRECTION INPUT ;
    USE SIGNAL ;
    PORT
      LAYER M5 ;
        RECT  90.432 0 90.456 0.084 ;
    END
  END a0[87]
  PIN a0[88]
    DIRECTION INPUT ;
    USE SIGNAL ;
    PORT
      LAYER M5 ;
        RECT  90.576 0 90.6 0.084 ;
    END
  END a0[88]
  PIN a0[89]
    DIRECTION INPUT ;
    USE SIGNAL ;
    PORT
      LAYER M5 ;
        RECT  90.72 0 90.744 0.084 ;
    END
  END a0[89]
  PIN a0[8]
    DIRECTION INPUT ;
    USE SIGNAL ;
    PORT
      LAYER M5 ;
        RECT  97.488 0 97.512 0.084 ;
    END
  END a0[8]
  PIN a0[90]
    DIRECTION INPUT ;
    USE SIGNAL ;
    PORT
      LAYER M5 ;
        RECT  90.864 0 90.888 0.084 ;
    END
  END a0[90]
  PIN a0[91]
    DIRECTION INPUT ;
    USE SIGNAL ;
    PORT
      LAYER M5 ;
        RECT  91.008 0 91.032 0.084 ;
    END
  END a0[91]
  PIN a0[92]
    DIRECTION INPUT ;
    USE SIGNAL ;
    PORT
      LAYER M5 ;
        RECT  91.152 0 91.176 0.084 ;
    END
  END a0[92]
  PIN a0[93]
    DIRECTION INPUT ;
    USE SIGNAL ;
    PORT
      LAYER M5 ;
        RECT  91.296 0 91.32 0.084 ;
    END
  END a0[93]
  PIN a0[94]
    DIRECTION INPUT ;
    USE SIGNAL ;
    PORT
      LAYER M5 ;
        RECT  91.44 0 91.464 0.084 ;
    END
  END a0[94]
  PIN a0[95]
    DIRECTION INPUT ;
    USE SIGNAL ;
    PORT
      LAYER M5 ;
        RECT  91.584 0 91.608 0.084 ;
    END
  END a0[95]
  PIN a0[96]
    DIRECTION INPUT ;
    USE SIGNAL ;
    PORT
      LAYER M5 ;
        RECT  91.728 0 91.752 0.084 ;
    END
  END a0[96]
  PIN a0[97]
    DIRECTION INPUT ;
    USE SIGNAL ;
    PORT
      LAYER M5 ;
        RECT  91.872 0 91.896 0.084 ;
    END
  END a0[97]
  PIN a0[98]
    DIRECTION INPUT ;
    USE SIGNAL ;
    PORT
      LAYER M5 ;
        RECT  92.016 0 92.04 0.084 ;
    END
  END a0[98]
  PIN a0[99]
    DIRECTION INPUT ;
    USE SIGNAL ;
    PORT
      LAYER M5 ;
        RECT  92.16 0 92.184 0.084 ;
    END
  END a0[99]
  PIN a0[9]
    DIRECTION INPUT ;
    USE SIGNAL ;
    PORT
      LAYER M5 ;
        RECT  97.632 0 97.656 0.084 ;
    END
  END a0[9]
  PIN a0t
    DIRECTION INPUT ;
    USE SIGNAL ;
    PORT
      LAYER M5 ;
        RECT  72.432 0 72.456 0.084 ;
    END
  END a0t
  PIN a0v[0]
    DIRECTION INPUT ;
    USE SIGNAL ;
    PORT
      LAYER M5 ;
        RECT  72.576 0 72.6 0.084 ;
    END
  END a0v[0]
  PIN a0v[10]
    DIRECTION INPUT ;
    USE SIGNAL ;
    PORT
      LAYER M5 ;
        RECT  74.016 0 74.04 0.084 ;
    END
  END a0v[10]
  PIN a0v[11]
    DIRECTION INPUT ;
    USE SIGNAL ;
    PORT
      LAYER M5 ;
        RECT  74.16 0 74.184 0.084 ;
    END
  END a0v[11]
  PIN a0v[12]
    DIRECTION INPUT ;
    USE SIGNAL ;
    PORT
      LAYER M5 ;
        RECT  74.304 0 74.328 0.084 ;
    END
  END a0v[12]
  PIN a0v[13]
    DIRECTION INPUT ;
    USE SIGNAL ;
    PORT
      LAYER M5 ;
        RECT  74.448 0 74.472 0.084 ;
    END
  END a0v[13]
  PIN a0v[14]
    DIRECTION INPUT ;
    USE SIGNAL ;
    PORT
      LAYER M5 ;
        RECT  74.592 0 74.616 0.084 ;
    END
  END a0v[14]
  PIN a0v[15]
    DIRECTION INPUT ;
    USE SIGNAL ;
    PORT
      LAYER M5 ;
        RECT  74.736 0 74.76 0.084 ;
    END
  END a0v[15]
  PIN a0v[16]
    DIRECTION INPUT ;
    USE SIGNAL ;
    PORT
      LAYER M5 ;
        RECT  74.88 0 74.904 0.084 ;
    END
  END a0v[16]
  PIN a0v[17]
    DIRECTION INPUT ;
    USE SIGNAL ;
    PORT
      LAYER M5 ;
        RECT  75.024 0 75.048 0.084 ;
    END
  END a0v[17]
  PIN a0v[18]
    DIRECTION INPUT ;
    USE SIGNAL ;
    PORT
      LAYER M5 ;
        RECT  75.168 0 75.192 0.084 ;
    END
  END a0v[18]
  PIN a0v[19]
    DIRECTION INPUT ;
    USE SIGNAL ;
    PORT
      LAYER M5 ;
        RECT  75.312 0 75.336 0.084 ;
    END
  END a0v[19]
  PIN a0v[1]
    DIRECTION INPUT ;
    USE SIGNAL ;
    PORT
      LAYER M5 ;
        RECT  72.72 0 72.744 0.084 ;
    END
  END a0v[1]
  PIN a0v[20]
    DIRECTION INPUT ;
    USE SIGNAL ;
    PORT
      LAYER M5 ;
        RECT  75.456 0 75.48 0.084 ;
    END
  END a0v[20]
  PIN a0v[21]
    DIRECTION INPUT ;
    USE SIGNAL ;
    PORT
      LAYER M5 ;
        RECT  75.6 0 75.624 0.084 ;
    END
  END a0v[21]
  PIN a0v[22]
    DIRECTION INPUT ;
    USE SIGNAL ;
    PORT
      LAYER M5 ;
        RECT  75.744 0 75.768 0.084 ;
    END
  END a0v[22]
  PIN a0v[23]
    DIRECTION INPUT ;
    USE SIGNAL ;
    PORT
      LAYER M5 ;
        RECT  75.888 0 75.912 0.084 ;
    END
  END a0v[23]
  PIN a0v[24]
    DIRECTION INPUT ;
    USE SIGNAL ;
    PORT
      LAYER M5 ;
        RECT  76.032 0 76.056 0.084 ;
    END
  END a0v[24]
  PIN a0v[25]
    DIRECTION INPUT ;
    USE SIGNAL ;
    PORT
      LAYER M5 ;
        RECT  76.176 0 76.2 0.084 ;
    END
  END a0v[25]
  PIN a0v[26]
    DIRECTION INPUT ;
    USE SIGNAL ;
    PORT
      LAYER M5 ;
        RECT  76.32 0 76.344 0.084 ;
    END
  END a0v[26]
  PIN a0v[27]
    DIRECTION INPUT ;
    USE SIGNAL ;
    PORT
      LAYER M5 ;
        RECT  76.464 0 76.488 0.084 ;
    END
  END a0v[27]
  PIN a0v[28]
    DIRECTION INPUT ;
    USE SIGNAL ;
    PORT
      LAYER M5 ;
        RECT  76.608 0 76.632 0.084 ;
    END
  END a0v[28]
  PIN a0v[29]
    DIRECTION INPUT ;
    USE SIGNAL ;
    PORT
      LAYER M5 ;
        RECT  62.928 0 62.952 0.084 ;
    END
  END a0v[29]
  PIN a0v[2]
    DIRECTION INPUT ;
    USE SIGNAL ;
    PORT
      LAYER M5 ;
        RECT  72.864 0 72.888 0.084 ;
    END
  END a0v[2]
  PIN a0v[30]
    DIRECTION INPUT ;
    USE SIGNAL ;
    PORT
      LAYER M5 ;
        RECT  63.072 0 63.096 0.084 ;
    END
  END a0v[30]
  PIN a0v[3]
    DIRECTION INPUT ;
    USE SIGNAL ;
    PORT
      LAYER M5 ;
        RECT  73.008 0 73.032 0.084 ;
    END
  END a0v[3]
  PIN a0v[4]
    DIRECTION INPUT ;
    USE SIGNAL ;
    PORT
      LAYER M5 ;
        RECT  73.152 0 73.176 0.084 ;
    END
  END a0v[4]
  PIN a0v[5]
    DIRECTION INPUT ;
    USE SIGNAL ;
    PORT
      LAYER M5 ;
        RECT  73.296 0 73.32 0.084 ;
    END
  END a0v[5]
  PIN a0v[6]
    DIRECTION INPUT ;
    USE SIGNAL ;
    PORT
      LAYER M5 ;
        RECT  73.44 0 73.464 0.084 ;
    END
  END a0v[6]
  PIN a0v[7]
    DIRECTION INPUT ;
    USE SIGNAL ;
    PORT
      LAYER M5 ;
        RECT  73.584 0 73.608 0.084 ;
    END
  END a0v[7]
  PIN a0v[8]
    DIRECTION INPUT ;
    USE SIGNAL ;
    PORT
      LAYER M5 ;
        RECT  73.728 0 73.752 0.084 ;
    END
  END a0v[8]
  PIN a0v[9]
    DIRECTION INPUT ;
    USE SIGNAL ;
    PORT
      LAYER M5 ;
        RECT  73.872 0 73.896 0.084 ;
    END
  END a0v[9]
  PIN a1[0]
    DIRECTION INPUT ;
    USE SIGNAL ;
    PORT
      LAYER M5 ;
        RECT  63.216 0 63.24 0.084 ;
    END
  END a1[0]
  PIN a1[100]
    DIRECTION INPUT ;
    USE SIGNAL ;
    PORT
      LAYER M5 ;
        RECT  121.392 0 121.416 0.084 ;
    END
  END a1[100]
  PIN a1[101]
    DIRECTION INPUT ;
    USE SIGNAL ;
    PORT
      LAYER M5 ;
        RECT  121.536 0 121.56 0.084 ;
    END
  END a1[101]
  PIN a1[102]
    DIRECTION INPUT ;
    USE SIGNAL ;
    PORT
      LAYER M5 ;
        RECT  121.68 0 121.704 0.084 ;
    END
  END a1[102]
  PIN a1[103]
    DIRECTION INPUT ;
    USE SIGNAL ;
    PORT
      LAYER M5 ;
        RECT  121.824 0 121.848 0.084 ;
    END
  END a1[103]
  PIN a1[104]
    DIRECTION INPUT ;
    USE SIGNAL ;
    PORT
      LAYER M5 ;
        RECT  121.968 0 121.992 0.084 ;
    END
  END a1[104]
  PIN a1[105]
    DIRECTION INPUT ;
    USE SIGNAL ;
    PORT
      LAYER M5 ;
        RECT  122.112 0 122.136 0.084 ;
    END
  END a1[105]
  PIN a1[106]
    DIRECTION INPUT ;
    USE SIGNAL ;
    PORT
      LAYER M5 ;
        RECT  122.256 0 122.28 0.084 ;
    END
  END a1[106]
  PIN a1[107]
    DIRECTION INPUT ;
    USE SIGNAL ;
    PORT
      LAYER M5 ;
        RECT  122.4 0 122.424 0.084 ;
    END
  END a1[107]
  PIN a1[108]
    DIRECTION INPUT ;
    USE SIGNAL ;
    PORT
      LAYER M5 ;
        RECT  122.544 0 122.568 0.084 ;
    END
  END a1[108]
  PIN a1[109]
    DIRECTION INPUT ;
    USE SIGNAL ;
    PORT
      LAYER M5 ;
        RECT  122.688 0 122.712 0.084 ;
    END
  END a1[109]
  PIN a1[10]
    DIRECTION INPUT ;
    USE SIGNAL ;
    PORT
      LAYER M5 ;
        RECT  64.656 0 64.68 0.084 ;
    END
  END a1[10]
  PIN a1[110]
    DIRECTION INPUT ;
    USE SIGNAL ;
    PORT
      LAYER M5 ;
        RECT  122.832 0 122.856 0.084 ;
    END
  END a1[110]
  PIN a1[111]
    DIRECTION INPUT ;
    USE SIGNAL ;
    PORT
      LAYER M5 ;
        RECT  122.976 0 123 0.084 ;
    END
  END a1[111]
  PIN a1[112]
    DIRECTION INPUT ;
    USE SIGNAL ;
    PORT
      LAYER M5 ;
        RECT  123.12 0 123.144 0.084 ;
    END
  END a1[112]
  PIN a1[113]
    DIRECTION INPUT ;
    USE SIGNAL ;
    PORT
      LAYER M5 ;
        RECT  123.264 0 123.288 0.084 ;
    END
  END a1[113]
  PIN a1[114]
    DIRECTION INPUT ;
    USE SIGNAL ;
    PORT
      LAYER M5 ;
        RECT  123.408 0 123.432 0.084 ;
    END
  END a1[114]
  PIN a1[115]
    DIRECTION INPUT ;
    USE SIGNAL ;
    PORT
      LAYER M5 ;
        RECT  123.552 0 123.576 0.084 ;
    END
  END a1[115]
  PIN a1[116]
    DIRECTION INPUT ;
    USE SIGNAL ;
    PORT
      LAYER M5 ;
        RECT  123.696 0 123.72 0.084 ;
    END
  END a1[116]
  PIN a1[117]
    DIRECTION INPUT ;
    USE SIGNAL ;
    PORT
      LAYER M5 ;
        RECT  123.84 0 123.864 0.084 ;
    END
  END a1[117]
  PIN a1[118]
    DIRECTION INPUT ;
    USE SIGNAL ;
    PORT
      LAYER M5 ;
        RECT  123.984 0 124.008 0.084 ;
    END
  END a1[118]
  PIN a1[119]
    DIRECTION INPUT ;
    USE SIGNAL ;
    PORT
      LAYER M5 ;
        RECT  124.128 0 124.152 0.084 ;
    END
  END a1[119]
  PIN a1[11]
    DIRECTION INPUT ;
    USE SIGNAL ;
    PORT
      LAYER M5 ;
        RECT  64.8 0 64.824 0.084 ;
    END
  END a1[11]
  PIN a1[120]
    DIRECTION INPUT ;
    USE SIGNAL ;
    PORT
      LAYER M5 ;
        RECT  124.272 0 124.296 0.084 ;
    END
  END a1[120]
  PIN a1[121]
    DIRECTION INPUT ;
    USE SIGNAL ;
    PORT
      LAYER M5 ;
        RECT  124.416 0 124.44 0.084 ;
    END
  END a1[121]
  PIN a1[122]
    DIRECTION INPUT ;
    USE SIGNAL ;
    PORT
      LAYER M5 ;
        RECT  124.56 0 124.584 0.084 ;
    END
  END a1[122]
  PIN a1[123]
    DIRECTION INPUT ;
    USE SIGNAL ;
    PORT
      LAYER M5 ;
        RECT  124.704 0 124.728 0.084 ;
    END
  END a1[123]
  PIN a1[124]
    DIRECTION INPUT ;
    USE SIGNAL ;
    PORT
      LAYER M5 ;
        RECT  124.848 0 124.872 0.084 ;
    END
  END a1[124]
  PIN a1[125]
    DIRECTION INPUT ;
    USE SIGNAL ;
    PORT
      LAYER M5 ;
        RECT  124.992 0 125.016 0.084 ;
    END
  END a1[125]
  PIN a1[126]
    DIRECTION INPUT ;
    USE SIGNAL ;
    PORT
      LAYER M5 ;
        RECT  138.96 0 138.984 0.084 ;
    END
  END a1[126]
  PIN a1[127]
    DIRECTION INPUT ;
    USE SIGNAL ;
    PORT
      LAYER M5 ;
        RECT  139.104 0 139.128 0.084 ;
    END
  END a1[127]
  PIN a1[128]
    DIRECTION INPUT ;
    USE SIGNAL ;
    PORT
      LAYER M5 ;
        RECT  139.248 0 139.272 0.084 ;
    END
  END a1[128]
  PIN a1[129]
    DIRECTION INPUT ;
    USE SIGNAL ;
    PORT
      LAYER M5 ;
        RECT  139.392 0 139.416 0.084 ;
    END
  END a1[129]
  PIN a1[12]
    DIRECTION INPUT ;
    USE SIGNAL ;
    PORT
      LAYER M5 ;
        RECT  64.944 0 64.968 0.084 ;
    END
  END a1[12]
  PIN a1[130]
    DIRECTION INPUT ;
    USE SIGNAL ;
    PORT
      LAYER M5 ;
        RECT  139.536 0 139.56 0.084 ;
    END
  END a1[130]
  PIN a1[131]
    DIRECTION INPUT ;
    USE SIGNAL ;
    PORT
      LAYER M5 ;
        RECT  139.68 0 139.704 0.084 ;
    END
  END a1[131]
  PIN a1[132]
    DIRECTION INPUT ;
    USE SIGNAL ;
    PORT
      LAYER M5 ;
        RECT  139.824 0 139.848 0.084 ;
    END
  END a1[132]
  PIN a1[133]
    DIRECTION INPUT ;
    USE SIGNAL ;
    PORT
      LAYER M5 ;
        RECT  139.968 0 139.992 0.084 ;
    END
  END a1[133]
  PIN a1[134]
    DIRECTION INPUT ;
    USE SIGNAL ;
    PORT
      LAYER M5 ;
        RECT  140.112 0 140.136 0.084 ;
    END
  END a1[134]
  PIN a1[135]
    DIRECTION INPUT ;
    USE SIGNAL ;
    PORT
      LAYER M5 ;
        RECT  140.256 0 140.28 0.084 ;
    END
  END a1[135]
  PIN a1[136]
    DIRECTION INPUT ;
    USE SIGNAL ;
    PORT
      LAYER M5 ;
        RECT  140.4 0 140.424 0.084 ;
    END
  END a1[136]
  PIN a1[137]
    DIRECTION INPUT ;
    USE SIGNAL ;
    PORT
      LAYER M5 ;
        RECT  140.544 0 140.568 0.084 ;
    END
  END a1[137]
  PIN a1[138]
    DIRECTION INPUT ;
    USE SIGNAL ;
    PORT
      LAYER M5 ;
        RECT  140.688 0 140.712 0.084 ;
    END
  END a1[138]
  PIN a1[139]
    DIRECTION INPUT ;
    USE SIGNAL ;
    PORT
      LAYER M5 ;
        RECT  140.832 0 140.856 0.084 ;
    END
  END a1[139]
  PIN a1[13]
    DIRECTION INPUT ;
    USE SIGNAL ;
    PORT
      LAYER M5 ;
        RECT  65.088 0 65.112 0.084 ;
    END
  END a1[13]
  PIN a1[140]
    DIRECTION INPUT ;
    USE SIGNAL ;
    PORT
      LAYER M5 ;
        RECT  140.976 0 141 0.084 ;
    END
  END a1[140]
  PIN a1[141]
    DIRECTION INPUT ;
    USE SIGNAL ;
    PORT
      LAYER M5 ;
        RECT  141.12 0 141.144 0.084 ;
    END
  END a1[141]
  PIN a1[142]
    DIRECTION INPUT ;
    USE SIGNAL ;
    PORT
      LAYER M5 ;
        RECT  141.264 0 141.288 0.084 ;
    END
  END a1[142]
  PIN a1[143]
    DIRECTION INPUT ;
    USE SIGNAL ;
    PORT
      LAYER M5 ;
        RECT  141.408 0 141.432 0.084 ;
    END
  END a1[143]
  PIN a1[144]
    DIRECTION INPUT ;
    USE SIGNAL ;
    PORT
      LAYER M5 ;
        RECT  141.552 0 141.576 0.084 ;
    END
  END a1[144]
  PIN a1[145]
    DIRECTION INPUT ;
    USE SIGNAL ;
    PORT
      LAYER M5 ;
        RECT  141.696 0 141.72 0.084 ;
    END
  END a1[145]
  PIN a1[146]
    DIRECTION INPUT ;
    USE SIGNAL ;
    PORT
      LAYER M5 ;
        RECT  141.84 0 141.864 0.084 ;
    END
  END a1[146]
  PIN a1[147]
    DIRECTION INPUT ;
    USE SIGNAL ;
    PORT
      LAYER M5 ;
        RECT  141.984 0 142.008 0.084 ;
    END
  END a1[147]
  PIN a1[148]
    DIRECTION INPUT ;
    USE SIGNAL ;
    PORT
      LAYER M5 ;
        RECT  142.128 0 142.152 0.084 ;
    END
  END a1[148]
  PIN a1[149]
    DIRECTION INPUT ;
    USE SIGNAL ;
    PORT
      LAYER M5 ;
        RECT  142.272 0 142.296 0.084 ;
    END
  END a1[149]
  PIN a1[14]
    DIRECTION INPUT ;
    USE SIGNAL ;
    PORT
      LAYER M5 ;
        RECT  65.232 0 65.256 0.084 ;
    END
  END a1[14]
  PIN a1[150]
    DIRECTION INPUT ;
    USE SIGNAL ;
    PORT
      LAYER M5 ;
        RECT  142.416 0 142.44 0.084 ;
    END
  END a1[150]
  PIN a1[151]
    DIRECTION INPUT ;
    USE SIGNAL ;
    PORT
      LAYER M5 ;
        RECT  142.56 0 142.584 0.084 ;
    END
  END a1[151]
  PIN a1[152]
    DIRECTION INPUT ;
    USE SIGNAL ;
    PORT
      LAYER M5 ;
        RECT  142.704 0 142.728 0.084 ;
    END
  END a1[152]
  PIN a1[153]
    DIRECTION INPUT ;
    USE SIGNAL ;
    PORT
      LAYER M5 ;
        RECT  142.848 0 142.872 0.084 ;
    END
  END a1[153]
  PIN a1[154]
    DIRECTION INPUT ;
    USE SIGNAL ;
    PORT
      LAYER M5 ;
        RECT  142.992 0 143.016 0.084 ;
    END
  END a1[154]
  PIN a1[155]
    DIRECTION INPUT ;
    USE SIGNAL ;
    PORT
      LAYER M5 ;
        RECT  143.136 0 143.16 0.084 ;
    END
  END a1[155]
  PIN a1[156]
    DIRECTION INPUT ;
    USE SIGNAL ;
    PORT
      LAYER M5 ;
        RECT  143.28 0 143.304 0.084 ;
    END
  END a1[156]
  PIN a1[157]
    DIRECTION INPUT ;
    USE SIGNAL ;
    PORT
      LAYER M5 ;
        RECT  143.424 0 143.448 0.084 ;
    END
  END a1[157]
  PIN a1[158]
    DIRECTION INPUT ;
    USE SIGNAL ;
    PORT
      LAYER M5 ;
        RECT  125.136 0 125.16 0.084 ;
    END
  END a1[158]
  PIN a1[159]
    DIRECTION INPUT ;
    USE SIGNAL ;
    PORT
      LAYER M5 ;
        RECT  125.28 0 125.304 0.084 ;
    END
  END a1[159]
  PIN a1[15]
    DIRECTION INPUT ;
    USE SIGNAL ;
    PORT
      LAYER M5 ;
        RECT  65.376 0 65.4 0.084 ;
    END
  END a1[15]
  PIN a1[160]
    DIRECTION INPUT ;
    USE SIGNAL ;
    PORT
      LAYER M5 ;
        RECT  125.424 0 125.448 0.084 ;
    END
  END a1[160]
  PIN a1[161]
    DIRECTION INPUT ;
    USE SIGNAL ;
    PORT
      LAYER M5 ;
        RECT  125.568 0 125.592 0.084 ;
    END
  END a1[161]
  PIN a1[162]
    DIRECTION INPUT ;
    USE SIGNAL ;
    PORT
      LAYER M5 ;
        RECT  125.712 0 125.736 0.084 ;
    END
  END a1[162]
  PIN a1[163]
    DIRECTION INPUT ;
    USE SIGNAL ;
    PORT
      LAYER M5 ;
        RECT  125.856 0 125.88 0.084 ;
    END
  END a1[163]
  PIN a1[164]
    DIRECTION INPUT ;
    USE SIGNAL ;
    PORT
      LAYER M5 ;
        RECT  126 0 126.024 0.084 ;
    END
  END a1[164]
  PIN a1[165]
    DIRECTION INPUT ;
    USE SIGNAL ;
    PORT
      LAYER M5 ;
        RECT  126.144 0 126.168 0.084 ;
    END
  END a1[165]
  PIN a1[166]
    DIRECTION INPUT ;
    USE SIGNAL ;
    PORT
      LAYER M5 ;
        RECT  126.288 0 126.312 0.084 ;
    END
  END a1[166]
  PIN a1[167]
    DIRECTION INPUT ;
    USE SIGNAL ;
    PORT
      LAYER M5 ;
        RECT  126.432 0 126.456 0.084 ;
    END
  END a1[167]
  PIN a1[168]
    DIRECTION INPUT ;
    USE SIGNAL ;
    PORT
      LAYER M5 ;
        RECT  126.576 0 126.6 0.084 ;
    END
  END a1[168]
  PIN a1[169]
    DIRECTION INPUT ;
    USE SIGNAL ;
    PORT
      LAYER M5 ;
        RECT  126.72 0 126.744 0.084 ;
    END
  END a1[169]
  PIN a1[16]
    DIRECTION INPUT ;
    USE SIGNAL ;
    PORT
      LAYER M5 ;
        RECT  65.52 0 65.544 0.084 ;
    END
  END a1[16]
  PIN a1[170]
    DIRECTION INPUT ;
    USE SIGNAL ;
    PORT
      LAYER M5 ;
        RECT  126.864 0 126.888 0.084 ;
    END
  END a1[170]
  PIN a1[171]
    DIRECTION INPUT ;
    USE SIGNAL ;
    PORT
      LAYER M5 ;
        RECT  127.008 0 127.032 0.084 ;
    END
  END a1[171]
  PIN a1[172]
    DIRECTION INPUT ;
    USE SIGNAL ;
    PORT
      LAYER M5 ;
        RECT  127.152 0 127.176 0.084 ;
    END
  END a1[172]
  PIN a1[173]
    DIRECTION INPUT ;
    USE SIGNAL ;
    PORT
      LAYER M5 ;
        RECT  127.296 0 127.32 0.084 ;
    END
  END a1[173]
  PIN a1[174]
    DIRECTION INPUT ;
    USE SIGNAL ;
    PORT
      LAYER M5 ;
        RECT  127.44 0 127.464 0.084 ;
    END
  END a1[174]
  PIN a1[175]
    DIRECTION INPUT ;
    USE SIGNAL ;
    PORT
      LAYER M5 ;
        RECT  127.584 0 127.608 0.084 ;
    END
  END a1[175]
  PIN a1[176]
    DIRECTION INPUT ;
    USE SIGNAL ;
    PORT
      LAYER M5 ;
        RECT  127.728 0 127.752 0.084 ;
    END
  END a1[176]
  PIN a1[177]
    DIRECTION INPUT ;
    USE SIGNAL ;
    PORT
      LAYER M5 ;
        RECT  127.872 0 127.896 0.084 ;
    END
  END a1[177]
  PIN a1[178]
    DIRECTION INPUT ;
    USE SIGNAL ;
    PORT
      LAYER M5 ;
        RECT  128.016 0 128.04 0.084 ;
    END
  END a1[178]
  PIN a1[179]
    DIRECTION INPUT ;
    USE SIGNAL ;
    PORT
      LAYER M5 ;
        RECT  128.16 0 128.184 0.084 ;
    END
  END a1[179]
  PIN a1[17]
    DIRECTION INPUT ;
    USE SIGNAL ;
    PORT
      LAYER M5 ;
        RECT  65.664 0 65.688 0.084 ;
    END
  END a1[17]
  PIN a1[180]
    DIRECTION INPUT ;
    USE SIGNAL ;
    PORT
      LAYER M5 ;
        RECT  128.304 0 128.328 0.084 ;
    END
  END a1[180]
  PIN a1[181]
    DIRECTION INPUT ;
    USE SIGNAL ;
    PORT
      LAYER M5 ;
        RECT  128.448 0 128.472 0.084 ;
    END
  END a1[181]
  PIN a1[182]
    DIRECTION INPUT ;
    USE SIGNAL ;
    PORT
      LAYER M5 ;
        RECT  128.592 0 128.616 0.084 ;
    END
  END a1[182]
  PIN a1[183]
    DIRECTION INPUT ;
    USE SIGNAL ;
    PORT
      LAYER M5 ;
        RECT  128.736 0 128.76 0.084 ;
    END
  END a1[183]
  PIN a1[184]
    DIRECTION INPUT ;
    USE SIGNAL ;
    PORT
      LAYER M5 ;
        RECT  128.88 0 128.904 0.084 ;
    END
  END a1[184]
  PIN a1[185]
    DIRECTION INPUT ;
    USE SIGNAL ;
    PORT
      LAYER M5 ;
        RECT  129.024 0 129.048 0.084 ;
    END
  END a1[185]
  PIN a1[186]
    DIRECTION INPUT ;
    USE SIGNAL ;
    PORT
      LAYER M5 ;
        RECT  129.168 0 129.192 0.084 ;
    END
  END a1[186]
  PIN a1[187]
    DIRECTION INPUT ;
    USE SIGNAL ;
    PORT
      LAYER M5 ;
        RECT  129.312 0 129.336 0.084 ;
    END
  END a1[187]
  PIN a1[188]
    DIRECTION INPUT ;
    USE SIGNAL ;
    PORT
      LAYER M5 ;
        RECT  129.456 0 129.48 0.084 ;
    END
  END a1[188]
  PIN a1[189]
    DIRECTION INPUT ;
    USE SIGNAL ;
    PORT
      LAYER M5 ;
        RECT  129.6 0 129.624 0.084 ;
    END
  END a1[189]
  PIN a1[18]
    DIRECTION INPUT ;
    USE SIGNAL ;
    PORT
      LAYER M5 ;
        RECT  65.808 0 65.832 0.084 ;
    END
  END a1[18]
  PIN a1[190]
    DIRECTION INPUT ;
    USE SIGNAL ;
    PORT
      LAYER M5 ;
        RECT  129.744 0 129.768 0.084 ;
    END
  END a1[190]
  PIN a1[191]
    DIRECTION INPUT ;
    USE SIGNAL ;
    PORT
      LAYER M5 ;
        RECT  129.888 0 129.912 0.084 ;
    END
  END a1[191]
  PIN a1[192]
    DIRECTION INPUT ;
    USE SIGNAL ;
    PORT
      LAYER M5 ;
        RECT  130.032 0 130.056 0.084 ;
    END
  END a1[192]
  PIN a1[193]
    DIRECTION INPUT ;
    USE SIGNAL ;
    PORT
      LAYER M5 ;
        RECT  130.176 0 130.2 0.084 ;
    END
  END a1[193]
  PIN a1[194]
    DIRECTION INPUT ;
    USE SIGNAL ;
    PORT
      LAYER M5 ;
        RECT  130.32 0 130.344 0.084 ;
    END
  END a1[194]
  PIN a1[195]
    DIRECTION INPUT ;
    USE SIGNAL ;
    PORT
      LAYER M5 ;
        RECT  130.464 0 130.488 0.084 ;
    END
  END a1[195]
  PIN a1[196]
    DIRECTION INPUT ;
    USE SIGNAL ;
    PORT
      LAYER M5 ;
        RECT  130.608 0 130.632 0.084 ;
    END
  END a1[196]
  PIN a1[197]
    DIRECTION INPUT ;
    USE SIGNAL ;
    PORT
      LAYER M5 ;
        RECT  130.752 0 130.776 0.084 ;
    END
  END a1[197]
  PIN a1[198]
    DIRECTION INPUT ;
    USE SIGNAL ;
    PORT
      LAYER M5 ;
        RECT  130.896 0 130.92 0.084 ;
    END
  END a1[198]
  PIN a1[199]
    DIRECTION INPUT ;
    USE SIGNAL ;
    PORT
      LAYER M5 ;
        RECT  131.04 0 131.064 0.084 ;
    END
  END a1[199]
  PIN a1[19]
    DIRECTION INPUT ;
    USE SIGNAL ;
    PORT
      LAYER M5 ;
        RECT  65.952 0 65.976 0.084 ;
    END
  END a1[19]
  PIN a1[1]
    DIRECTION INPUT ;
    USE SIGNAL ;
    PORT
      LAYER M5 ;
        RECT  63.36 0 63.384 0.084 ;
    END
  END a1[1]
  PIN a1[200]
    DIRECTION INPUT ;
    USE SIGNAL ;
    PORT
      LAYER M5 ;
        RECT  131.184 0 131.208 0.084 ;
    END
  END a1[200]
  PIN a1[201]
    DIRECTION INPUT ;
    USE SIGNAL ;
    PORT
      LAYER M5 ;
        RECT  131.328 0 131.352 0.084 ;
    END
  END a1[201]
  PIN a1[202]
    DIRECTION INPUT ;
    USE SIGNAL ;
    PORT
      LAYER M5 ;
        RECT  131.472 0 131.496 0.084 ;
    END
  END a1[202]
  PIN a1[203]
    DIRECTION INPUT ;
    USE SIGNAL ;
    PORT
      LAYER M5 ;
        RECT  131.616 0 131.64 0.084 ;
    END
  END a1[203]
  PIN a1[204]
    DIRECTION INPUT ;
    USE SIGNAL ;
    PORT
      LAYER M5 ;
        RECT  131.76 0 131.784 0.084 ;
    END
  END a1[204]
  PIN a1[205]
    DIRECTION INPUT ;
    USE SIGNAL ;
    PORT
      LAYER M5 ;
        RECT  131.904 0 131.928 0.084 ;
    END
  END a1[205]
  PIN a1[206]
    DIRECTION INPUT ;
    USE SIGNAL ;
    PORT
      LAYER M5 ;
        RECT  132.048 0 132.072 0.084 ;
    END
  END a1[206]
  PIN a1[207]
    DIRECTION INPUT ;
    USE SIGNAL ;
    PORT
      LAYER M5 ;
        RECT  132.192 0 132.216 0.084 ;
    END
  END a1[207]
  PIN a1[208]
    DIRECTION INPUT ;
    USE SIGNAL ;
    PORT
      LAYER M5 ;
        RECT  132.336 0 132.36 0.084 ;
    END
  END a1[208]
  PIN a1[209]
    DIRECTION INPUT ;
    USE SIGNAL ;
    PORT
      LAYER M5 ;
        RECT  132.48 0 132.504 0.084 ;
    END
  END a1[209]
  PIN a1[20]
    DIRECTION INPUT ;
    USE SIGNAL ;
    PORT
      LAYER M5 ;
        RECT  66.096 0 66.12 0.084 ;
    END
  END a1[20]
  PIN a1[210]
    DIRECTION INPUT ;
    USE SIGNAL ;
    PORT
      LAYER M5 ;
        RECT  132.624 0 132.648 0.084 ;
    END
  END a1[210]
  PIN a1[211]
    DIRECTION INPUT ;
    USE SIGNAL ;
    PORT
      LAYER M5 ;
        RECT  132.768 0 132.792 0.084 ;
    END
  END a1[211]
  PIN a1[212]
    DIRECTION INPUT ;
    USE SIGNAL ;
    PORT
      LAYER M5 ;
        RECT  132.912 0 132.936 0.084 ;
    END
  END a1[212]
  PIN a1[213]
    DIRECTION INPUT ;
    USE SIGNAL ;
    PORT
      LAYER M5 ;
        RECT  133.056 0 133.08 0.084 ;
    END
  END a1[213]
  PIN a1[214]
    DIRECTION INPUT ;
    USE SIGNAL ;
    PORT
      LAYER M5 ;
        RECT  133.2 0 133.224 0.084 ;
    END
  END a1[214]
  PIN a1[215]
    DIRECTION INPUT ;
    USE SIGNAL ;
    PORT
      LAYER M5 ;
        RECT  133.344 0 133.368 0.084 ;
    END
  END a1[215]
  PIN a1[216]
    DIRECTION INPUT ;
    USE SIGNAL ;
    PORT
      LAYER M5 ;
        RECT  133.488 0 133.512 0.084 ;
    END
  END a1[216]
  PIN a1[217]
    DIRECTION INPUT ;
    USE SIGNAL ;
    PORT
      LAYER M5 ;
        RECT  133.632 0 133.656 0.084 ;
    END
  END a1[217]
  PIN a1[218]
    DIRECTION INPUT ;
    USE SIGNAL ;
    PORT
      LAYER M5 ;
        RECT  133.776 0 133.8 0.084 ;
    END
  END a1[218]
  PIN a1[219]
    DIRECTION INPUT ;
    USE SIGNAL ;
    PORT
      LAYER M5 ;
        RECT  133.92 0 133.944 0.084 ;
    END
  END a1[219]
  PIN a1[21]
    DIRECTION INPUT ;
    USE SIGNAL ;
    PORT
      LAYER M5 ;
        RECT  66.24 0 66.264 0.084 ;
    END
  END a1[21]
  PIN a1[220]
    DIRECTION INPUT ;
    USE SIGNAL ;
    PORT
      LAYER M5 ;
        RECT  134.064 0 134.088 0.084 ;
    END
  END a1[220]
  PIN a1[221]
    DIRECTION INPUT ;
    USE SIGNAL ;
    PORT
      LAYER M5 ;
        RECT  134.208 0 134.232 0.084 ;
    END
  END a1[221]
  PIN a1[222]
    DIRECTION INPUT ;
    USE SIGNAL ;
    PORT
      LAYER M5 ;
        RECT  47.952 0 47.976 0.084 ;
    END
  END a1[222]
  PIN a1[223]
    DIRECTION INPUT ;
    USE SIGNAL ;
    PORT
      LAYER M5 ;
        RECT  48.096 0 48.12 0.084 ;
    END
  END a1[223]
  PIN a1[224]
    DIRECTION INPUT ;
    USE SIGNAL ;
    PORT
      LAYER M5 ;
        RECT  48.24 0 48.264 0.084 ;
    END
  END a1[224]
  PIN a1[225]
    DIRECTION INPUT ;
    USE SIGNAL ;
    PORT
      LAYER M5 ;
        RECT  48.384 0 48.408 0.084 ;
    END
  END a1[225]
  PIN a1[226]
    DIRECTION INPUT ;
    USE SIGNAL ;
    PORT
      LAYER M5 ;
        RECT  48.528 0 48.552 0.084 ;
    END
  END a1[226]
  PIN a1[227]
    DIRECTION INPUT ;
    USE SIGNAL ;
    PORT
      LAYER M5 ;
        RECT  48.672 0 48.696 0.084 ;
    END
  END a1[227]
  PIN a1[228]
    DIRECTION INPUT ;
    USE SIGNAL ;
    PORT
      LAYER M5 ;
        RECT  48.816 0 48.84 0.084 ;
    END
  END a1[228]
  PIN a1[229]
    DIRECTION INPUT ;
    USE SIGNAL ;
    PORT
      LAYER M5 ;
        RECT  48.96 0 48.984 0.084 ;
    END
  END a1[229]
  PIN a1[22]
    DIRECTION INPUT ;
    USE SIGNAL ;
    PORT
      LAYER M5 ;
        RECT  66.384 0 66.408 0.084 ;
    END
  END a1[22]
  PIN a1[230]
    DIRECTION INPUT ;
    USE SIGNAL ;
    PORT
      LAYER M5 ;
        RECT  49.104 0 49.128 0.084 ;
    END
  END a1[230]
  PIN a1[231]
    DIRECTION INPUT ;
    USE SIGNAL ;
    PORT
      LAYER M5 ;
        RECT  49.248 0 49.272 0.084 ;
    END
  END a1[231]
  PIN a1[232]
    DIRECTION INPUT ;
    USE SIGNAL ;
    PORT
      LAYER M5 ;
        RECT  49.392 0 49.416 0.084 ;
    END
  END a1[232]
  PIN a1[233]
    DIRECTION INPUT ;
    USE SIGNAL ;
    PORT
      LAYER M5 ;
        RECT  49.536 0 49.56 0.084 ;
    END
  END a1[233]
  PIN a1[234]
    DIRECTION INPUT ;
    USE SIGNAL ;
    PORT
      LAYER M5 ;
        RECT  49.68 0 49.704 0.084 ;
    END
  END a1[234]
  PIN a1[235]
    DIRECTION INPUT ;
    USE SIGNAL ;
    PORT
      LAYER M5 ;
        RECT  49.824 0 49.848 0.084 ;
    END
  END a1[235]
  PIN a1[236]
    DIRECTION INPUT ;
    USE SIGNAL ;
    PORT
      LAYER M5 ;
        RECT  49.968 0 49.992 0.084 ;
    END
  END a1[236]
  PIN a1[237]
    DIRECTION INPUT ;
    USE SIGNAL ;
    PORT
      LAYER M5 ;
        RECT  50.112 0 50.136 0.084 ;
    END
  END a1[237]
  PIN a1[238]
    DIRECTION INPUT ;
    USE SIGNAL ;
    PORT
      LAYER M5 ;
        RECT  50.256 0 50.28 0.084 ;
    END
  END a1[238]
  PIN a1[239]
    DIRECTION INPUT ;
    USE SIGNAL ;
    PORT
      LAYER M5 ;
        RECT  50.4 0 50.424 0.084 ;
    END
  END a1[239]
  PIN a1[23]
    DIRECTION INPUT ;
    USE SIGNAL ;
    PORT
      LAYER M5 ;
        RECT  66.528 0 66.552 0.084 ;
    END
  END a1[23]
  PIN a1[240]
    DIRECTION INPUT ;
    USE SIGNAL ;
    PORT
      LAYER M5 ;
        RECT  50.544 0 50.568 0.084 ;
    END
  END a1[240]
  PIN a1[241]
    DIRECTION INPUT ;
    USE SIGNAL ;
    PORT
      LAYER M5 ;
        RECT  50.688 0 50.712 0.084 ;
    END
  END a1[241]
  PIN a1[242]
    DIRECTION INPUT ;
    USE SIGNAL ;
    PORT
      LAYER M5 ;
        RECT  50.832 0 50.856 0.084 ;
    END
  END a1[242]
  PIN a1[243]
    DIRECTION INPUT ;
    USE SIGNAL ;
    PORT
      LAYER M5 ;
        RECT  50.976 0 51 0.084 ;
    END
  END a1[243]
  PIN a1[244]
    DIRECTION INPUT ;
    USE SIGNAL ;
    PORT
      LAYER M5 ;
        RECT  51.12 0 51.144 0.084 ;
    END
  END a1[244]
  PIN a1[245]
    DIRECTION INPUT ;
    USE SIGNAL ;
    PORT
      LAYER M5 ;
        RECT  51.264 0 51.288 0.084 ;
    END
  END a1[245]
  PIN a1[246]
    DIRECTION INPUT ;
    USE SIGNAL ;
    PORT
      LAYER M5 ;
        RECT  51.408 0 51.432 0.084 ;
    END
  END a1[246]
  PIN a1[247]
    DIRECTION INPUT ;
    USE SIGNAL ;
    PORT
      LAYER M5 ;
        RECT  51.552 0 51.576 0.084 ;
    END
  END a1[247]
  PIN a1[248]
    DIRECTION INPUT ;
    USE SIGNAL ;
    PORT
      LAYER M5 ;
        RECT  51.696 0 51.72 0.084 ;
    END
  END a1[248]
  PIN a1[249]
    DIRECTION INPUT ;
    USE SIGNAL ;
    PORT
      LAYER M5 ;
        RECT  51.84 0 51.864 0.084 ;
    END
  END a1[249]
  PIN a1[24]
    DIRECTION INPUT ;
    USE SIGNAL ;
    PORT
      LAYER M5 ;
        RECT  66.672 0 66.696 0.084 ;
    END
  END a1[24]
  PIN a1[250]
    DIRECTION INPUT ;
    USE SIGNAL ;
    PORT
      LAYER M5 ;
        RECT  51.984 0 52.008 0.084 ;
    END
  END a1[250]
  PIN a1[251]
    DIRECTION INPUT ;
    USE SIGNAL ;
    PORT
      LAYER M5 ;
        RECT  52.128 0 52.152 0.084 ;
    END
  END a1[251]
  PIN a1[252]
    DIRECTION INPUT ;
    USE SIGNAL ;
    PORT
      LAYER M5 ;
        RECT  52.272 0 52.296 0.084 ;
    END
  END a1[252]
  PIN a1[253]
    DIRECTION INPUT ;
    USE SIGNAL ;
    PORT
      LAYER M5 ;
        RECT  52.416 0 52.44 0.084 ;
    END
  END a1[253]
  PIN a1[254]
    DIRECTION INPUT ;
    USE SIGNAL ;
    PORT
      LAYER M5 ;
        RECT  115.92 0 115.944 0.084 ;
    END
  END a1[254]
  PIN a1[255]
    DIRECTION INPUT ;
    USE SIGNAL ;
    PORT
      LAYER M5 ;
        RECT  116.064 0 116.088 0.084 ;
    END
  END a1[255]
  PIN a1[256]
    DIRECTION INPUT ;
    USE SIGNAL ;
    PORT
      LAYER M5 ;
        RECT  116.208 0 116.232 0.084 ;
    END
  END a1[256]
  PIN a1[257]
    DIRECTION INPUT ;
    USE SIGNAL ;
    PORT
      LAYER M5 ;
        RECT  116.352 0 116.376 0.084 ;
    END
  END a1[257]
  PIN a1[25]
    DIRECTION INPUT ;
    USE SIGNAL ;
    PORT
      LAYER M5 ;
        RECT  66.816 0 66.84 0.084 ;
    END
  END a1[25]
  PIN a1[26]
    DIRECTION INPUT ;
    USE SIGNAL ;
    PORT
      LAYER M5 ;
        RECT  66.96 0 66.984 0.084 ;
    END
  END a1[26]
  PIN a1[27]
    DIRECTION INPUT ;
    USE SIGNAL ;
    PORT
      LAYER M5 ;
        RECT  67.104 0 67.128 0.084 ;
    END
  END a1[27]
  PIN a1[28]
    DIRECTION INPUT ;
    USE SIGNAL ;
    PORT
      LAYER M5 ;
        RECT  67.248 0 67.272 0.084 ;
    END
  END a1[28]
  PIN a1[29]
    DIRECTION INPUT ;
    USE SIGNAL ;
    PORT
      LAYER M5 ;
        RECT  67.392 0 67.416 0.084 ;
    END
  END a1[29]
  PIN a1[2]
    DIRECTION INPUT ;
    USE SIGNAL ;
    PORT
      LAYER M5 ;
        RECT  63.504 0 63.528 0.084 ;
    END
  END a1[2]
  PIN a1[30]
    DIRECTION INPUT ;
    USE SIGNAL ;
    PORT
      LAYER M5 ;
        RECT  67.536 0 67.56 0.084 ;
    END
  END a1[30]
  PIN a1[31]
    DIRECTION INPUT ;
    USE SIGNAL ;
    PORT
      LAYER M5 ;
        RECT  67.68 0 67.704 0.084 ;
    END
  END a1[31]
  PIN a1[32]
    DIRECTION INPUT ;
    USE SIGNAL ;
    PORT
      LAYER M5 ;
        RECT  67.824 0 67.848 0.084 ;
    END
  END a1[32]
  PIN a1[33]
    DIRECTION INPUT ;
    USE SIGNAL ;
    PORT
      LAYER M5 ;
        RECT  67.968 0 67.992 0.084 ;
    END
  END a1[33]
  PIN a1[34]
    DIRECTION INPUT ;
    USE SIGNAL ;
    PORT
      LAYER M5 ;
        RECT  68.112 0 68.136 0.084 ;
    END
  END a1[34]
  PIN a1[35]
    DIRECTION INPUT ;
    USE SIGNAL ;
    PORT
      LAYER M5 ;
        RECT  68.256 0 68.28 0.084 ;
    END
  END a1[35]
  PIN a1[36]
    DIRECTION INPUT ;
    USE SIGNAL ;
    PORT
      LAYER M5 ;
        RECT  68.4 0 68.424 0.084 ;
    END
  END a1[36]
  PIN a1[37]
    DIRECTION INPUT ;
    USE SIGNAL ;
    PORT
      LAYER M5 ;
        RECT  68.544 0 68.568 0.084 ;
    END
  END a1[37]
  PIN a1[38]
    DIRECTION INPUT ;
    USE SIGNAL ;
    PORT
      LAYER M5 ;
        RECT  68.688 0 68.712 0.084 ;
    END
  END a1[38]
  PIN a1[39]
    DIRECTION INPUT ;
    USE SIGNAL ;
    PORT
      LAYER M5 ;
        RECT  68.832 0 68.856 0.084 ;
    END
  END a1[39]
  PIN a1[3]
    DIRECTION INPUT ;
    USE SIGNAL ;
    PORT
      LAYER M5 ;
        RECT  63.648 0 63.672 0.084 ;
    END
  END a1[3]
  PIN a1[40]
    DIRECTION INPUT ;
    USE SIGNAL ;
    PORT
      LAYER M5 ;
        RECT  68.976 0 69 0.084 ;
    END
  END a1[40]
  PIN a1[41]
    DIRECTION INPUT ;
    USE SIGNAL ;
    PORT
      LAYER M5 ;
        RECT  69.12 0 69.144 0.084 ;
    END
  END a1[41]
  PIN a1[42]
    DIRECTION INPUT ;
    USE SIGNAL ;
    PORT
      LAYER M5 ;
        RECT  69.264 0 69.288 0.084 ;
    END
  END a1[42]
  PIN a1[43]
    DIRECTION INPUT ;
    USE SIGNAL ;
    PORT
      LAYER M5 ;
        RECT  69.408 0 69.432 0.084 ;
    END
  END a1[43]
  PIN a1[44]
    DIRECTION INPUT ;
    USE SIGNAL ;
    PORT
      LAYER M5 ;
        RECT  69.552 0 69.576 0.084 ;
    END
  END a1[44]
  PIN a1[45]
    DIRECTION INPUT ;
    USE SIGNAL ;
    PORT
      LAYER M5 ;
        RECT  69.696 0 69.72 0.084 ;
    END
  END a1[45]
  PIN a1[46]
    DIRECTION INPUT ;
    USE SIGNAL ;
    PORT
      LAYER M5 ;
        RECT  69.84 0 69.864 0.084 ;
    END
  END a1[46]
  PIN a1[47]
    DIRECTION INPUT ;
    USE SIGNAL ;
    PORT
      LAYER M5 ;
        RECT  69.984 0 70.008 0.084 ;
    END
  END a1[47]
  PIN a1[48]
    DIRECTION INPUT ;
    USE SIGNAL ;
    PORT
      LAYER M5 ;
        RECT  70.128 0 70.152 0.084 ;
    END
  END a1[48]
  PIN a1[49]
    DIRECTION INPUT ;
    USE SIGNAL ;
    PORT
      LAYER M5 ;
        RECT  70.272 0 70.296 0.084 ;
    END
  END a1[49]
  PIN a1[4]
    DIRECTION INPUT ;
    USE SIGNAL ;
    PORT
      LAYER M5 ;
        RECT  63.792 0 63.816 0.084 ;
    END
  END a1[4]
  PIN a1[50]
    DIRECTION INPUT ;
    USE SIGNAL ;
    PORT
      LAYER M5 ;
        RECT  70.416 0 70.44 0.084 ;
    END
  END a1[50]
  PIN a1[51]
    DIRECTION INPUT ;
    USE SIGNAL ;
    PORT
      LAYER M5 ;
        RECT  70.56 0 70.584 0.084 ;
    END
  END a1[51]
  PIN a1[52]
    DIRECTION INPUT ;
    USE SIGNAL ;
    PORT
      LAYER M5 ;
        RECT  70.704 0 70.728 0.084 ;
    END
  END a1[52]
  PIN a1[53]
    DIRECTION INPUT ;
    USE SIGNAL ;
    PORT
      LAYER M5 ;
        RECT  70.848 0 70.872 0.084 ;
    END
  END a1[53]
  PIN a1[54]
    DIRECTION INPUT ;
    USE SIGNAL ;
    PORT
      LAYER M5 ;
        RECT  70.992 0 71.016 0.084 ;
    END
  END a1[54]
  PIN a1[55]
    DIRECTION INPUT ;
    USE SIGNAL ;
    PORT
      LAYER M5 ;
        RECT  71.136 0 71.16 0.084 ;
    END
  END a1[55]
  PIN a1[56]
    DIRECTION INPUT ;
    USE SIGNAL ;
    PORT
      LAYER M5 ;
        RECT  71.28 0 71.304 0.084 ;
    END
  END a1[56]
  PIN a1[57]
    DIRECTION INPUT ;
    USE SIGNAL ;
    PORT
      LAYER M5 ;
        RECT  71.424 0 71.448 0.084 ;
    END
  END a1[57]
  PIN a1[58]
    DIRECTION INPUT ;
    USE SIGNAL ;
    PORT
      LAYER M5 ;
        RECT  71.568 0 71.592 0.084 ;
    END
  END a1[58]
  PIN a1[59]
    DIRECTION INPUT ;
    USE SIGNAL ;
    PORT
      LAYER M5 ;
        RECT  71.712 0 71.736 0.084 ;
    END
  END a1[59]
  PIN a1[5]
    DIRECTION INPUT ;
    USE SIGNAL ;
    PORT
      LAYER M5 ;
        RECT  63.936 0 63.96 0.084 ;
    END
  END a1[5]
  PIN a1[60]
    DIRECTION INPUT ;
    USE SIGNAL ;
    PORT
      LAYER M5 ;
        RECT  71.856 0 71.88 0.084 ;
    END
  END a1[60]
  PIN a1[61]
    DIRECTION INPUT ;
    USE SIGNAL ;
    PORT
      LAYER M5 ;
        RECT  72 0 72.024 0.084 ;
    END
  END a1[61]
  PIN a1[62]
    DIRECTION INPUT ;
    USE SIGNAL ;
    PORT
      LAYER M5 ;
        RECT  81.36 0 81.384 0.084 ;
    END
  END a1[62]
  PIN a1[63]
    DIRECTION INPUT ;
    USE SIGNAL ;
    PORT
      LAYER M5 ;
        RECT  81.504 0 81.528 0.084 ;
    END
  END a1[63]
  PIN a1[64]
    DIRECTION INPUT ;
    USE SIGNAL ;
    PORT
      LAYER M5 ;
        RECT  81.648 0 81.672 0.084 ;
    END
  END a1[64]
  PIN a1[65]
    DIRECTION INPUT ;
    USE SIGNAL ;
    PORT
      LAYER M5 ;
        RECT  81.792 0 81.816 0.084 ;
    END
  END a1[65]
  PIN a1[66]
    DIRECTION INPUT ;
    USE SIGNAL ;
    PORT
      LAYER M5 ;
        RECT  81.936 0 81.96 0.084 ;
    END
  END a1[66]
  PIN a1[67]
    DIRECTION INPUT ;
    USE SIGNAL ;
    PORT
      LAYER M5 ;
        RECT  82.08 0 82.104 0.084 ;
    END
  END a1[67]
  PIN a1[68]
    DIRECTION INPUT ;
    USE SIGNAL ;
    PORT
      LAYER M5 ;
        RECT  82.224 0 82.248 0.084 ;
    END
  END a1[68]
  PIN a1[69]
    DIRECTION INPUT ;
    USE SIGNAL ;
    PORT
      LAYER M5 ;
        RECT  82.368 0 82.392 0.084 ;
    END
  END a1[69]
  PIN a1[6]
    DIRECTION INPUT ;
    USE SIGNAL ;
    PORT
      LAYER M5 ;
        RECT  64.08 0 64.104 0.084 ;
    END
  END a1[6]
  PIN a1[70]
    DIRECTION INPUT ;
    USE SIGNAL ;
    PORT
      LAYER M5 ;
        RECT  82.512 0 82.536 0.084 ;
    END
  END a1[70]
  PIN a1[71]
    DIRECTION INPUT ;
    USE SIGNAL ;
    PORT
      LAYER M5 ;
        RECT  82.656 0 82.68 0.084 ;
    END
  END a1[71]
  PIN a1[72]
    DIRECTION INPUT ;
    USE SIGNAL ;
    PORT
      LAYER M5 ;
        RECT  82.8 0 82.824 0.084 ;
    END
  END a1[72]
  PIN a1[73]
    DIRECTION INPUT ;
    USE SIGNAL ;
    PORT
      LAYER M5 ;
        RECT  82.944 0 82.968 0.084 ;
    END
  END a1[73]
  PIN a1[74]
    DIRECTION INPUT ;
    USE SIGNAL ;
    PORT
      LAYER M5 ;
        RECT  83.088 0 83.112 0.084 ;
    END
  END a1[74]
  PIN a1[75]
    DIRECTION INPUT ;
    USE SIGNAL ;
    PORT
      LAYER M5 ;
        RECT  83.232 0 83.256 0.084 ;
    END
  END a1[75]
  PIN a1[76]
    DIRECTION INPUT ;
    USE SIGNAL ;
    PORT
      LAYER M5 ;
        RECT  83.376 0 83.4 0.084 ;
    END
  END a1[76]
  PIN a1[77]
    DIRECTION INPUT ;
    USE SIGNAL ;
    PORT
      LAYER M5 ;
        RECT  83.52 0 83.544 0.084 ;
    END
  END a1[77]
  PIN a1[78]
    DIRECTION INPUT ;
    USE SIGNAL ;
    PORT
      LAYER M5 ;
        RECT  83.664 0 83.688 0.084 ;
    END
  END a1[78]
  PIN a1[79]
    DIRECTION INPUT ;
    USE SIGNAL ;
    PORT
      LAYER M5 ;
        RECT  83.808 0 83.832 0.084 ;
    END
  END a1[79]
  PIN a1[7]
    DIRECTION INPUT ;
    USE SIGNAL ;
    PORT
      LAYER M5 ;
        RECT  64.224 0 64.248 0.084 ;
    END
  END a1[7]
  PIN a1[80]
    DIRECTION INPUT ;
    USE SIGNAL ;
    PORT
      LAYER M5 ;
        RECT  83.952 0 83.976 0.084 ;
    END
  END a1[80]
  PIN a1[81]
    DIRECTION INPUT ;
    USE SIGNAL ;
    PORT
      LAYER M5 ;
        RECT  84.096 0 84.12 0.084 ;
    END
  END a1[81]
  PIN a1[82]
    DIRECTION INPUT ;
    USE SIGNAL ;
    PORT
      LAYER M5 ;
        RECT  84.24 0 84.264 0.084 ;
    END
  END a1[82]
  PIN a1[83]
    DIRECTION INPUT ;
    USE SIGNAL ;
    PORT
      LAYER M5 ;
        RECT  84.384 0 84.408 0.084 ;
    END
  END a1[83]
  PIN a1[84]
    DIRECTION INPUT ;
    USE SIGNAL ;
    PORT
      LAYER M5 ;
        RECT  84.528 0 84.552 0.084 ;
    END
  END a1[84]
  PIN a1[85]
    DIRECTION INPUT ;
    USE SIGNAL ;
    PORT
      LAYER M5 ;
        RECT  84.672 0 84.696 0.084 ;
    END
  END a1[85]
  PIN a1[86]
    DIRECTION INPUT ;
    USE SIGNAL ;
    PORT
      LAYER M5 ;
        RECT  84.816 0 84.84 0.084 ;
    END
  END a1[86]
  PIN a1[87]
    DIRECTION INPUT ;
    USE SIGNAL ;
    PORT
      LAYER M5 ;
        RECT  84.96 0 84.984 0.084 ;
    END
  END a1[87]
  PIN a1[88]
    DIRECTION INPUT ;
    USE SIGNAL ;
    PORT
      LAYER M5 ;
        RECT  85.104 0 85.128 0.084 ;
    END
  END a1[88]
  PIN a1[89]
    DIRECTION INPUT ;
    USE SIGNAL ;
    PORT
      LAYER M5 ;
        RECT  85.248 0 85.272 0.084 ;
    END
  END a1[89]
  PIN a1[8]
    DIRECTION INPUT ;
    USE SIGNAL ;
    PORT
      LAYER M5 ;
        RECT  64.368 0 64.392 0.084 ;
    END
  END a1[8]
  PIN a1[90]
    DIRECTION INPUT ;
    USE SIGNAL ;
    PORT
      LAYER M5 ;
        RECT  85.392 0 85.416 0.084 ;
    END
  END a1[90]
  PIN a1[91]
    DIRECTION INPUT ;
    USE SIGNAL ;
    PORT
      LAYER M5 ;
        RECT  85.536 0 85.56 0.084 ;
    END
  END a1[91]
  PIN a1[92]
    DIRECTION INPUT ;
    USE SIGNAL ;
    PORT
      LAYER M5 ;
        RECT  85.68 0 85.704 0.084 ;
    END
  END a1[92]
  PIN a1[93]
    DIRECTION INPUT ;
    USE SIGNAL ;
    PORT
      LAYER M5 ;
        RECT  85.824 0 85.848 0.084 ;
    END
  END a1[93]
  PIN a1[94]
    DIRECTION INPUT ;
    USE SIGNAL ;
    PORT
      LAYER M5 ;
        RECT  120.528 0 120.552 0.084 ;
    END
  END a1[94]
  PIN a1[95]
    DIRECTION INPUT ;
    USE SIGNAL ;
    PORT
      LAYER M5 ;
        RECT  120.672 0 120.696 0.084 ;
    END
  END a1[95]
  PIN a1[96]
    DIRECTION INPUT ;
    USE SIGNAL ;
    PORT
      LAYER M5 ;
        RECT  120.816 0 120.84 0.084 ;
    END
  END a1[96]
  PIN a1[97]
    DIRECTION INPUT ;
    USE SIGNAL ;
    PORT
      LAYER M5 ;
        RECT  120.96 0 120.984 0.084 ;
    END
  END a1[97]
  PIN a1[98]
    DIRECTION INPUT ;
    USE SIGNAL ;
    PORT
      LAYER M5 ;
        RECT  121.104 0 121.128 0.084 ;
    END
  END a1[98]
  PIN a1[99]
    DIRECTION INPUT ;
    USE SIGNAL ;
    PORT
      LAYER M5 ;
        RECT  121.248 0 121.272 0.084 ;
    END
  END a1[99]
  PIN a1[9]
    DIRECTION INPUT ;
    USE SIGNAL ;
    PORT
      LAYER M5 ;
        RECT  64.512 0 64.536 0.084 ;
    END
  END a1[9]
  PIN a1t
    DIRECTION INPUT ;
    USE SIGNAL ;
    PORT
      LAYER M5 ;
        RECT  116.496 0 116.52 0.084 ;
    END
  END a1t
  PIN a1v[0]
    DIRECTION INPUT ;
    USE SIGNAL ;
    PORT
      LAYER M5 ;
        RECT  116.64 0 116.664 0.084 ;
    END
  END a1v[0]
  PIN a1v[10]
    DIRECTION INPUT ;
    USE SIGNAL ;
    PORT
      LAYER M5 ;
        RECT  118.08 0 118.104 0.084 ;
    END
  END a1v[10]
  PIN a1v[11]
    DIRECTION INPUT ;
    USE SIGNAL ;
    PORT
      LAYER M5 ;
        RECT  118.224 0 118.248 0.084 ;
    END
  END a1v[11]
  PIN a1v[12]
    DIRECTION INPUT ;
    USE SIGNAL ;
    PORT
      LAYER M5 ;
        RECT  118.368 0 118.392 0.084 ;
    END
  END a1v[12]
  PIN a1v[13]
    DIRECTION INPUT ;
    USE SIGNAL ;
    PORT
      LAYER M5 ;
        RECT  118.512 0 118.536 0.084 ;
    END
  END a1v[13]
  PIN a1v[14]
    DIRECTION INPUT ;
    USE SIGNAL ;
    PORT
      LAYER M5 ;
        RECT  118.656 0 118.68 0.084 ;
    END
  END a1v[14]
  PIN a1v[15]
    DIRECTION INPUT ;
    USE SIGNAL ;
    PORT
      LAYER M5 ;
        RECT  118.8 0 118.824 0.084 ;
    END
  END a1v[15]
  PIN a1v[16]
    DIRECTION INPUT ;
    USE SIGNAL ;
    PORT
      LAYER M5 ;
        RECT  118.944 0 118.968 0.084 ;
    END
  END a1v[16]
  PIN a1v[17]
    DIRECTION INPUT ;
    USE SIGNAL ;
    PORT
      LAYER M5 ;
        RECT  119.088 0 119.112 0.084 ;
    END
  END a1v[17]
  PIN a1v[18]
    DIRECTION INPUT ;
    USE SIGNAL ;
    PORT
      LAYER M5 ;
        RECT  119.232 0 119.256 0.084 ;
    END
  END a1v[18]
  PIN a1v[19]
    DIRECTION INPUT ;
    USE SIGNAL ;
    PORT
      LAYER M5 ;
        RECT  119.376 0 119.4 0.084 ;
    END
  END a1v[19]
  PIN a1v[1]
    DIRECTION INPUT ;
    USE SIGNAL ;
    PORT
      LAYER M5 ;
        RECT  116.784 0 116.808 0.084 ;
    END
  END a1v[1]
  PIN a1v[20]
    DIRECTION INPUT ;
    USE SIGNAL ;
    PORT
      LAYER M5 ;
        RECT  119.52 0 119.544 0.084 ;
    END
  END a1v[20]
  PIN a1v[21]
    DIRECTION INPUT ;
    USE SIGNAL ;
    PORT
      LAYER M5 ;
        RECT  119.664 0 119.688 0.084 ;
    END
  END a1v[21]
  PIN a1v[22]
    DIRECTION INPUT ;
    USE SIGNAL ;
    PORT
      LAYER M5 ;
        RECT  119.808 0 119.832 0.084 ;
    END
  END a1v[22]
  PIN a1v[23]
    DIRECTION INPUT ;
    USE SIGNAL ;
    PORT
      LAYER M5 ;
        RECT  119.952 0 119.976 0.084 ;
    END
  END a1v[23]
  PIN a1v[24]
    DIRECTION INPUT ;
    USE SIGNAL ;
    PORT
      LAYER M5 ;
        RECT  120.096 0 120.12 0.084 ;
    END
  END a1v[24]
  PIN a1v[25]
    DIRECTION INPUT ;
    USE SIGNAL ;
    PORT
      LAYER M5 ;
        RECT  120.24 0 120.264 0.084 ;
    END
  END a1v[25]
  PIN a1v[26]
    DIRECTION INPUT ;
    USE SIGNAL ;
    PORT
      LAYER M5 ;
        RECT  120.384 0 120.408 0.084 ;
    END
  END a1v[26]
  PIN a1v[27]
    DIRECTION INPUT ;
    USE SIGNAL ;
    PORT
      LAYER M5 ;
        RECT  134.352 0 134.376 0.084 ;
    END
  END a1v[27]
  PIN a1v[28]
    DIRECTION INPUT ;
    USE SIGNAL ;
    PORT
      LAYER M5 ;
        RECT  134.496 0 134.52 0.084 ;
    END
  END a1v[28]
  PIN a1v[29]
    DIRECTION INPUT ;
    USE SIGNAL ;
    PORT
      LAYER M5 ;
        RECT  134.64 0 134.664 0.084 ;
    END
  END a1v[29]
  PIN a1v[2]
    DIRECTION INPUT ;
    USE SIGNAL ;
    PORT
      LAYER M5 ;
        RECT  116.928 0 116.952 0.084 ;
    END
  END a1v[2]
  PIN a1v[30]
    DIRECTION INPUT ;
    USE SIGNAL ;
    PORT
      LAYER M5 ;
        RECT  134.784 0 134.808 0.084 ;
    END
  END a1v[30]
  PIN a1v[3]
    DIRECTION INPUT ;
    USE SIGNAL ;
    PORT
      LAYER M5 ;
        RECT  117.072 0 117.096 0.084 ;
    END
  END a1v[3]
  PIN a1v[4]
    DIRECTION INPUT ;
    USE SIGNAL ;
    PORT
      LAYER M5 ;
        RECT  117.216 0 117.24 0.084 ;
    END
  END a1v[4]
  PIN a1v[5]
    DIRECTION INPUT ;
    USE SIGNAL ;
    PORT
      LAYER M5 ;
        RECT  117.36 0 117.384 0.084 ;
    END
  END a1v[5]
  PIN a1v[6]
    DIRECTION INPUT ;
    USE SIGNAL ;
    PORT
      LAYER M5 ;
        RECT  117.504 0 117.528 0.084 ;
    END
  END a1v[6]
  PIN a1v[7]
    DIRECTION INPUT ;
    USE SIGNAL ;
    PORT
      LAYER M5 ;
        RECT  117.648 0 117.672 0.084 ;
    END
  END a1v[7]
  PIN a1v[8]
    DIRECTION INPUT ;
    USE SIGNAL ;
    PORT
      LAYER M5 ;
        RECT  117.792 0 117.816 0.084 ;
    END
  END a1v[8]
  PIN a1v[9]
    DIRECTION INPUT ;
    USE SIGNAL ;
    PORT
      LAYER M5 ;
        RECT  117.936 0 117.96 0.084 ;
    END
  END a1v[9]
  PIN b0[0]
    DIRECTION INPUT ;
    USE SIGNAL ;
    PORT
      LAYER M5 ;
        RECT  134.928 0 134.952 0.084 ;
    END
  END b0[0]
  PIN b0[100]
    DIRECTION INPUT ;
    USE SIGNAL ;
    PORT
      LAYER M5 ;
        RECT  39.888 0 39.912 0.084 ;
    END
  END b0[100]
  PIN b0[101]
    DIRECTION INPUT ;
    USE SIGNAL ;
    PORT
      LAYER M5 ;
        RECT  40.032 0 40.056 0.084 ;
    END
  END b0[101]
  PIN b0[102]
    DIRECTION INPUT ;
    USE SIGNAL ;
    PORT
      LAYER M5 ;
        RECT  40.176 0 40.2 0.084 ;
    END
  END b0[102]
  PIN b0[103]
    DIRECTION INPUT ;
    USE SIGNAL ;
    PORT
      LAYER M5 ;
        RECT  40.32 0 40.344 0.084 ;
    END
  END b0[103]
  PIN b0[104]
    DIRECTION INPUT ;
    USE SIGNAL ;
    PORT
      LAYER M5 ;
        RECT  40.464 0 40.488 0.084 ;
    END
  END b0[104]
  PIN b0[105]
    DIRECTION INPUT ;
    USE SIGNAL ;
    PORT
      LAYER M5 ;
        RECT  40.608 0 40.632 0.084 ;
    END
  END b0[105]
  PIN b0[106]
    DIRECTION INPUT ;
    USE SIGNAL ;
    PORT
      LAYER M5 ;
        RECT  40.752 0 40.776 0.084 ;
    END
  END b0[106]
  PIN b0[107]
    DIRECTION INPUT ;
    USE SIGNAL ;
    PORT
      LAYER M5 ;
        RECT  40.896 0 40.92 0.084 ;
    END
  END b0[107]
  PIN b0[108]
    DIRECTION INPUT ;
    USE SIGNAL ;
    PORT
      LAYER M5 ;
        RECT  41.04 0 41.064 0.084 ;
    END
  END b0[108]
  PIN b0[109]
    DIRECTION INPUT ;
    USE SIGNAL ;
    PORT
      LAYER M5 ;
        RECT  41.184 0 41.208 0.084 ;
    END
  END b0[109]
  PIN b0[10]
    DIRECTION INPUT ;
    USE SIGNAL ;
    PORT
      LAYER M5 ;
        RECT  136.368 0 136.392 0.084 ;
    END
  END b0[10]
  PIN b0[110]
    DIRECTION INPUT ;
    USE SIGNAL ;
    PORT
      LAYER M5 ;
        RECT  41.328 0 41.352 0.084 ;
    END
  END b0[110]
  PIN b0[111]
    DIRECTION INPUT ;
    USE SIGNAL ;
    PORT
      LAYER M5 ;
        RECT  41.472 0 41.496 0.084 ;
    END
  END b0[111]
  PIN b0[112]
    DIRECTION INPUT ;
    USE SIGNAL ;
    PORT
      LAYER M5 ;
        RECT  41.616 0 41.64 0.084 ;
    END
  END b0[112]
  PIN b0[113]
    DIRECTION INPUT ;
    USE SIGNAL ;
    PORT
      LAYER M5 ;
        RECT  41.76 0 41.784 0.084 ;
    END
  END b0[113]
  PIN b0[114]
    DIRECTION INPUT ;
    USE SIGNAL ;
    PORT
      LAYER M5 ;
        RECT  41.904 0 41.928 0.084 ;
    END
  END b0[114]
  PIN b0[115]
    DIRECTION INPUT ;
    USE SIGNAL ;
    PORT
      LAYER M5 ;
        RECT  42.048 0 42.072 0.084 ;
    END
  END b0[115]
  PIN b0[116]
    DIRECTION INPUT ;
    USE SIGNAL ;
    PORT
      LAYER M5 ;
        RECT  42.192 0 42.216 0.084 ;
    END
  END b0[116]
  PIN b0[117]
    DIRECTION INPUT ;
    USE SIGNAL ;
    PORT
      LAYER M5 ;
        RECT  42.336 0 42.36 0.084 ;
    END
  END b0[117]
  PIN b0[118]
    DIRECTION INPUT ;
    USE SIGNAL ;
    PORT
      LAYER M5 ;
        RECT  42.48 0 42.504 0.084 ;
    END
  END b0[118]
  PIN b0[119]
    DIRECTION INPUT ;
    USE SIGNAL ;
    PORT
      LAYER M5 ;
        RECT  42.624 0 42.648 0.084 ;
    END
  END b0[119]
  PIN b0[11]
    DIRECTION INPUT ;
    USE SIGNAL ;
    PORT
      LAYER M5 ;
        RECT  136.512 0 136.536 0.084 ;
    END
  END b0[11]
  PIN b0[120]
    DIRECTION INPUT ;
    USE SIGNAL ;
    PORT
      LAYER M5 ;
        RECT  42.768 0 42.792 0.084 ;
    END
  END b0[120]
  PIN b0[121]
    DIRECTION INPUT ;
    USE SIGNAL ;
    PORT
      LAYER M5 ;
        RECT  42.912 0 42.936 0.084 ;
    END
  END b0[121]
  PIN b0[122]
    DIRECTION INPUT ;
    USE SIGNAL ;
    PORT
      LAYER M5 ;
        RECT  43.056 0 43.08 0.084 ;
    END
  END b0[122]
  PIN b0[123]
    DIRECTION INPUT ;
    USE SIGNAL ;
    PORT
      LAYER M5 ;
        RECT  43.2 0 43.224 0.084 ;
    END
  END b0[123]
  PIN b0[124]
    DIRECTION INPUT ;
    USE SIGNAL ;
    PORT
      LAYER M5 ;
        RECT  52.56 0 52.584 0.084 ;
    END
  END b0[124]
  PIN b0[125]
    DIRECTION INPUT ;
    USE SIGNAL ;
    PORT
      LAYER M5 ;
        RECT  52.704 0 52.728 0.084 ;
    END
  END b0[125]
  PIN b0[126]
    DIRECTION INPUT ;
    USE SIGNAL ;
    PORT
      LAYER M5 ;
        RECT  52.848 0 52.872 0.084 ;
    END
  END b0[126]
  PIN b0[127]
    DIRECTION INPUT ;
    USE SIGNAL ;
    PORT
      LAYER M5 ;
        RECT  52.992 0 53.016 0.084 ;
    END
  END b0[127]
  PIN b0[128]
    DIRECTION INPUT ;
    USE SIGNAL ;
    PORT
      LAYER M5 ;
        RECT  53.136 0 53.16 0.084 ;
    END
  END b0[128]
  PIN b0[129]
    DIRECTION INPUT ;
    USE SIGNAL ;
    PORT
      LAYER M5 ;
        RECT  53.28 0 53.304 0.084 ;
    END
  END b0[129]
  PIN b0[12]
    DIRECTION INPUT ;
    USE SIGNAL ;
    PORT
      LAYER M5 ;
        RECT  136.656 0 136.68 0.084 ;
    END
  END b0[12]
  PIN b0[130]
    DIRECTION INPUT ;
    USE SIGNAL ;
    PORT
      LAYER M5 ;
        RECT  53.424 0 53.448 0.084 ;
    END
  END b0[130]
  PIN b0[131]
    DIRECTION INPUT ;
    USE SIGNAL ;
    PORT
      LAYER M5 ;
        RECT  53.568 0 53.592 0.084 ;
    END
  END b0[131]
  PIN b0[132]
    DIRECTION INPUT ;
    USE SIGNAL ;
    PORT
      LAYER M5 ;
        RECT  53.712 0 53.736 0.084 ;
    END
  END b0[132]
  PIN b0[133]
    DIRECTION INPUT ;
    USE SIGNAL ;
    PORT
      LAYER M5 ;
        RECT  53.856 0 53.88 0.084 ;
    END
  END b0[133]
  PIN b0[134]
    DIRECTION INPUT ;
    USE SIGNAL ;
    PORT
      LAYER M5 ;
        RECT  54 0 54.024 0.084 ;
    END
  END b0[134]
  PIN b0[135]
    DIRECTION INPUT ;
    USE SIGNAL ;
    PORT
      LAYER M5 ;
        RECT  54.144 0 54.168 0.084 ;
    END
  END b0[135]
  PIN b0[136]
    DIRECTION INPUT ;
    USE SIGNAL ;
    PORT
      LAYER M5 ;
        RECT  54.288 0 54.312 0.084 ;
    END
  END b0[136]
  PIN b0[137]
    DIRECTION INPUT ;
    USE SIGNAL ;
    PORT
      LAYER M5 ;
        RECT  54.432 0 54.456 0.084 ;
    END
  END b0[137]
  PIN b0[138]
    DIRECTION INPUT ;
    USE SIGNAL ;
    PORT
      LAYER M5 ;
        RECT  54.576 0 54.6 0.084 ;
    END
  END b0[138]
  PIN b0[139]
    DIRECTION INPUT ;
    USE SIGNAL ;
    PORT
      LAYER M5 ;
        RECT  54.72 0 54.744 0.084 ;
    END
  END b0[139]
  PIN b0[13]
    DIRECTION INPUT ;
    USE SIGNAL ;
    PORT
      LAYER M5 ;
        RECT  136.8 0 136.824 0.084 ;
    END
  END b0[13]
  PIN b0[140]
    DIRECTION INPUT ;
    USE SIGNAL ;
    PORT
      LAYER M5 ;
        RECT  54.864 0 54.888 0.084 ;
    END
  END b0[140]
  PIN b0[141]
    DIRECTION INPUT ;
    USE SIGNAL ;
    PORT
      LAYER M5 ;
        RECT  55.008 0 55.032 0.084 ;
    END
  END b0[141]
  PIN b0[142]
    DIRECTION INPUT ;
    USE SIGNAL ;
    PORT
      LAYER M5 ;
        RECT  55.152 0 55.176 0.084 ;
    END
  END b0[142]
  PIN b0[143]
    DIRECTION INPUT ;
    USE SIGNAL ;
    PORT
      LAYER M5 ;
        RECT  55.296 0 55.32 0.084 ;
    END
  END b0[143]
  PIN b0[144]
    DIRECTION INPUT ;
    USE SIGNAL ;
    PORT
      LAYER M5 ;
        RECT  55.44 0 55.464 0.084 ;
    END
  END b0[144]
  PIN b0[145]
    DIRECTION INPUT ;
    USE SIGNAL ;
    PORT
      LAYER M5 ;
        RECT  55.584 0 55.608 0.084 ;
    END
  END b0[145]
  PIN b0[146]
    DIRECTION INPUT ;
    USE SIGNAL ;
    PORT
      LAYER M5 ;
        RECT  55.728 0 55.752 0.084 ;
    END
  END b0[146]
  PIN b0[147]
    DIRECTION INPUT ;
    USE SIGNAL ;
    PORT
      LAYER M5 ;
        RECT  55.872 0 55.896 0.084 ;
    END
  END b0[147]
  PIN b0[148]
    DIRECTION INPUT ;
    USE SIGNAL ;
    PORT
      LAYER M5 ;
        RECT  56.016 0 56.04 0.084 ;
    END
  END b0[148]
  PIN b0[149]
    DIRECTION INPUT ;
    USE SIGNAL ;
    PORT
      LAYER M5 ;
        RECT  56.16 0 56.184 0.084 ;
    END
  END b0[149]
  PIN b0[14]
    DIRECTION INPUT ;
    USE SIGNAL ;
    PORT
      LAYER M5 ;
        RECT  136.944 0 136.968 0.084 ;
    END
  END b0[14]
  PIN b0[150]
    DIRECTION INPUT ;
    USE SIGNAL ;
    PORT
      LAYER M5 ;
        RECT  56.304 0 56.328 0.084 ;
    END
  END b0[150]
  PIN b0[151]
    DIRECTION INPUT ;
    USE SIGNAL ;
    PORT
      LAYER M5 ;
        RECT  56.448 0 56.472 0.084 ;
    END
  END b0[151]
  PIN b0[152]
    DIRECTION INPUT ;
    USE SIGNAL ;
    PORT
      LAYER M5 ;
        RECT  56.592 0 56.616 0.084 ;
    END
  END b0[152]
  PIN b0[153]
    DIRECTION INPUT ;
    USE SIGNAL ;
    PORT
      LAYER M5 ;
        RECT  56.736 0 56.76 0.084 ;
    END
  END b0[153]
  PIN b0[154]
    DIRECTION INPUT ;
    USE SIGNAL ;
    PORT
      LAYER M5 ;
        RECT  56.88 0 56.904 0.084 ;
    END
  END b0[154]
  PIN b0[155]
    DIRECTION INPUT ;
    USE SIGNAL ;
    PORT
      LAYER M5 ;
        RECT  57.024 0 57.048 0.084 ;
    END
  END b0[155]
  PIN b0[156]
    DIRECTION INPUT ;
    USE SIGNAL ;
    PORT
      LAYER M5 ;
        RECT  34.128 0 34.152 0.084 ;
    END
  END b0[156]
  PIN b0[157]
    DIRECTION INPUT ;
    USE SIGNAL ;
    PORT
      LAYER M5 ;
        RECT  34.272 0 34.296 0.084 ;
    END
  END b0[157]
  PIN b0[158]
    DIRECTION INPUT ;
    USE SIGNAL ;
    PORT
      LAYER M5 ;
        RECT  34.416 0 34.44 0.084 ;
    END
  END b0[158]
  PIN b0[159]
    DIRECTION INPUT ;
    USE SIGNAL ;
    PORT
      LAYER M5 ;
        RECT  34.56 0 34.584 0.084 ;
    END
  END b0[159]
  PIN b0[15]
    DIRECTION INPUT ;
    USE SIGNAL ;
    PORT
      LAYER M5 ;
        RECT  137.088 0 137.112 0.084 ;
    END
  END b0[15]
  PIN b0[160]
    DIRECTION INPUT ;
    USE SIGNAL ;
    PORT
      LAYER M5 ;
        RECT  34.704 0 34.728 0.084 ;
    END
  END b0[160]
  PIN b0[161]
    DIRECTION INPUT ;
    USE SIGNAL ;
    PORT
      LAYER M5 ;
        RECT  34.848 0 34.872 0.084 ;
    END
  END b0[161]
  PIN b0[162]
    DIRECTION INPUT ;
    USE SIGNAL ;
    PORT
      LAYER M5 ;
        RECT  34.992 0 35.016 0.084 ;
    END
  END b0[162]
  PIN b0[163]
    DIRECTION INPUT ;
    USE SIGNAL ;
    PORT
      LAYER M5 ;
        RECT  35.136 0 35.16 0.084 ;
    END
  END b0[163]
  PIN b0[164]
    DIRECTION INPUT ;
    USE SIGNAL ;
    PORT
      LAYER M5 ;
        RECT  35.28 0 35.304 0.084 ;
    END
  END b0[164]
  PIN b0[165]
    DIRECTION INPUT ;
    USE SIGNAL ;
    PORT
      LAYER M5 ;
        RECT  35.424 0 35.448 0.084 ;
    END
  END b0[165]
  PIN b0[166]
    DIRECTION INPUT ;
    USE SIGNAL ;
    PORT
      LAYER M5 ;
        RECT  35.568 0 35.592 0.084 ;
    END
  END b0[166]
  PIN b0[167]
    DIRECTION INPUT ;
    USE SIGNAL ;
    PORT
      LAYER M5 ;
        RECT  35.712 0 35.736 0.084 ;
    END
  END b0[167]
  PIN b0[168]
    DIRECTION INPUT ;
    USE SIGNAL ;
    PORT
      LAYER M5 ;
        RECT  35.856 0 35.88 0.084 ;
    END
  END b0[168]
  PIN b0[169]
    DIRECTION INPUT ;
    USE SIGNAL ;
    PORT
      LAYER M5 ;
        RECT  36 0 36.024 0.084 ;
    END
  END b0[169]
  PIN b0[16]
    DIRECTION INPUT ;
    USE SIGNAL ;
    PORT
      LAYER M5 ;
        RECT  137.232 0 137.256 0.084 ;
    END
  END b0[16]
  PIN b0[170]
    DIRECTION INPUT ;
    USE SIGNAL ;
    PORT
      LAYER M5 ;
        RECT  36.144 0 36.168 0.084 ;
    END
  END b0[170]
  PIN b0[171]
    DIRECTION INPUT ;
    USE SIGNAL ;
    PORT
      LAYER M5 ;
        RECT  36.288 0 36.312 0.084 ;
    END
  END b0[171]
  PIN b0[172]
    DIRECTION INPUT ;
    USE SIGNAL ;
    PORT
      LAYER M5 ;
        RECT  36.432 0 36.456 0.084 ;
    END
  END b0[172]
  PIN b0[173]
    DIRECTION INPUT ;
    USE SIGNAL ;
    PORT
      LAYER M5 ;
        RECT  36.576 0 36.6 0.084 ;
    END
  END b0[173]
  PIN b0[174]
    DIRECTION INPUT ;
    USE SIGNAL ;
    PORT
      LAYER M5 ;
        RECT  36.72 0 36.744 0.084 ;
    END
  END b0[174]
  PIN b0[175]
    DIRECTION INPUT ;
    USE SIGNAL ;
    PORT
      LAYER M5 ;
        RECT  36.864 0 36.888 0.084 ;
    END
  END b0[175]
  PIN b0[176]
    DIRECTION INPUT ;
    USE SIGNAL ;
    PORT
      LAYER M5 ;
        RECT  37.008 0 37.032 0.084 ;
    END
  END b0[176]
  PIN b0[177]
    DIRECTION INPUT ;
    USE SIGNAL ;
    PORT
      LAYER M5 ;
        RECT  37.152 0 37.176 0.084 ;
    END
  END b0[177]
  PIN b0[178]
    DIRECTION INPUT ;
    USE SIGNAL ;
    PORT
      LAYER M5 ;
        RECT  37.296 0 37.32 0.084 ;
    END
  END b0[178]
  PIN b0[179]
    DIRECTION INPUT ;
    USE SIGNAL ;
    PORT
      LAYER M5 ;
        RECT  37.44 0 37.464 0.084 ;
    END
  END b0[179]
  PIN b0[17]
    DIRECTION INPUT ;
    USE SIGNAL ;
    PORT
      LAYER M5 ;
        RECT  137.376 0 137.4 0.084 ;
    END
  END b0[17]
  PIN b0[180]
    DIRECTION INPUT ;
    USE SIGNAL ;
    PORT
      LAYER M5 ;
        RECT  37.584 0 37.608 0.084 ;
    END
  END b0[180]
  PIN b0[181]
    DIRECTION INPUT ;
    USE SIGNAL ;
    PORT
      LAYER M5 ;
        RECT  37.728 0 37.752 0.084 ;
    END
  END b0[181]
  PIN b0[182]
    DIRECTION INPUT ;
    USE SIGNAL ;
    PORT
      LAYER M5 ;
        RECT  37.872 0 37.896 0.084 ;
    END
  END b0[182]
  PIN b0[183]
    DIRECTION INPUT ;
    USE SIGNAL ;
    PORT
      LAYER M5 ;
        RECT  38.016 0 38.04 0.084 ;
    END
  END b0[183]
  PIN b0[184]
    DIRECTION INPUT ;
    USE SIGNAL ;
    PORT
      LAYER M5 ;
        RECT  38.16 0 38.184 0.084 ;
    END
  END b0[184]
  PIN b0[185]
    DIRECTION INPUT ;
    USE SIGNAL ;
    PORT
      LAYER M5 ;
        RECT  38.304 0 38.328 0.084 ;
    END
  END b0[185]
  PIN b0[186]
    DIRECTION INPUT ;
    USE SIGNAL ;
    PORT
      LAYER M5 ;
        RECT  38.448 0 38.472 0.084 ;
    END
  END b0[186]
  PIN b0[187]
    DIRECTION INPUT ;
    USE SIGNAL ;
    PORT
      LAYER M5 ;
        RECT  38.592 0 38.616 0.084 ;
    END
  END b0[187]
  PIN b0[188]
    DIRECTION INPUT ;
    USE SIGNAL ;
    PORT
      LAYER M5 ;
        RECT  19.152 0 19.176 0.084 ;
    END
  END b0[188]
  PIN b0[189]
    DIRECTION INPUT ;
    USE SIGNAL ;
    PORT
      LAYER M5 ;
        RECT  19.296 0 19.32 0.084 ;
    END
  END b0[189]
  PIN b0[18]
    DIRECTION INPUT ;
    USE SIGNAL ;
    PORT
      LAYER M5 ;
        RECT  137.52 0 137.544 0.084 ;
    END
  END b0[18]
  PIN b0[190]
    DIRECTION INPUT ;
    USE SIGNAL ;
    PORT
      LAYER M5 ;
        RECT  19.44 0 19.464 0.084 ;
    END
  END b0[190]
  PIN b0[191]
    DIRECTION INPUT ;
    USE SIGNAL ;
    PORT
      LAYER M5 ;
        RECT  19.584 0 19.608 0.084 ;
    END
  END b0[191]
  PIN b0[192]
    DIRECTION INPUT ;
    USE SIGNAL ;
    PORT
      LAYER M5 ;
        RECT  19.728 0 19.752 0.084 ;
    END
  END b0[192]
  PIN b0[193]
    DIRECTION INPUT ;
    USE SIGNAL ;
    PORT
      LAYER M5 ;
        RECT  19.872 0 19.896 0.084 ;
    END
  END b0[193]
  PIN b0[194]
    DIRECTION INPUT ;
    USE SIGNAL ;
    PORT
      LAYER M5 ;
        RECT  20.016 0 20.04 0.084 ;
    END
  END b0[194]
  PIN b0[195]
    DIRECTION INPUT ;
    USE SIGNAL ;
    PORT
      LAYER M5 ;
        RECT  20.16 0 20.184 0.084 ;
    END
  END b0[195]
  PIN b0[196]
    DIRECTION INPUT ;
    USE SIGNAL ;
    PORT
      LAYER M5 ;
        RECT  20.304 0 20.328 0.084 ;
    END
  END b0[196]
  PIN b0[197]
    DIRECTION INPUT ;
    USE SIGNAL ;
    PORT
      LAYER M5 ;
        RECT  20.448 0 20.472 0.084 ;
    END
  END b0[197]
  PIN b0[198]
    DIRECTION INPUT ;
    USE SIGNAL ;
    PORT
      LAYER M5 ;
        RECT  20.592 0 20.616 0.084 ;
    END
  END b0[198]
  PIN b0[199]
    DIRECTION INPUT ;
    USE SIGNAL ;
    PORT
      LAYER M5 ;
        RECT  20.736 0 20.76 0.084 ;
    END
  END b0[199]
  PIN b0[19]
    DIRECTION INPUT ;
    USE SIGNAL ;
    PORT
      LAYER M5 ;
        RECT  137.664 0 137.688 0.084 ;
    END
  END b0[19]
  PIN b0[1]
    DIRECTION INPUT ;
    USE SIGNAL ;
    PORT
      LAYER M5 ;
        RECT  135.072 0 135.096 0.084 ;
    END
  END b0[1]
  PIN b0[200]
    DIRECTION INPUT ;
    USE SIGNAL ;
    PORT
      LAYER M5 ;
        RECT  20.88 0 20.904 0.084 ;
    END
  END b0[200]
  PIN b0[201]
    DIRECTION INPUT ;
    USE SIGNAL ;
    PORT
      LAYER M5 ;
        RECT  21.024 0 21.048 0.084 ;
    END
  END b0[201]
  PIN b0[202]
    DIRECTION INPUT ;
    USE SIGNAL ;
    PORT
      LAYER M5 ;
        RECT  21.168 0 21.192 0.084 ;
    END
  END b0[202]
  PIN b0[203]
    DIRECTION INPUT ;
    USE SIGNAL ;
    PORT
      LAYER M5 ;
        RECT  21.312 0 21.336 0.084 ;
    END
  END b0[203]
  PIN b0[204]
    DIRECTION INPUT ;
    USE SIGNAL ;
    PORT
      LAYER M5 ;
        RECT  21.456 0 21.48 0.084 ;
    END
  END b0[204]
  PIN b0[205]
    DIRECTION INPUT ;
    USE SIGNAL ;
    PORT
      LAYER M5 ;
        RECT  21.6 0 21.624 0.084 ;
    END
  END b0[205]
  PIN b0[206]
    DIRECTION INPUT ;
    USE SIGNAL ;
    PORT
      LAYER M5 ;
        RECT  21.744 0 21.768 0.084 ;
    END
  END b0[206]
  PIN b0[207]
    DIRECTION INPUT ;
    USE SIGNAL ;
    PORT
      LAYER M5 ;
        RECT  21.888 0 21.912 0.084 ;
    END
  END b0[207]
  PIN b0[208]
    DIRECTION INPUT ;
    USE SIGNAL ;
    PORT
      LAYER M5 ;
        RECT  22.032 0 22.056 0.084 ;
    END
  END b0[208]
  PIN b0[209]
    DIRECTION INPUT ;
    USE SIGNAL ;
    PORT
      LAYER M5 ;
        RECT  22.176 0 22.2 0.084 ;
    END
  END b0[209]
  PIN b0[20]
    DIRECTION INPUT ;
    USE SIGNAL ;
    PORT
      LAYER M5 ;
        RECT  137.808 0 137.832 0.084 ;
    END
  END b0[20]
  PIN b0[210]
    DIRECTION INPUT ;
    USE SIGNAL ;
    PORT
      LAYER M5 ;
        RECT  22.32 0 22.344 0.084 ;
    END
  END b0[210]
  PIN b0[211]
    DIRECTION INPUT ;
    USE SIGNAL ;
    PORT
      LAYER M5 ;
        RECT  22.464 0 22.488 0.084 ;
    END
  END b0[211]
  PIN b0[212]
    DIRECTION INPUT ;
    USE SIGNAL ;
    PORT
      LAYER M5 ;
        RECT  22.608 0 22.632 0.084 ;
    END
  END b0[212]
  PIN b0[213]
    DIRECTION INPUT ;
    USE SIGNAL ;
    PORT
      LAYER M5 ;
        RECT  22.752 0 22.776 0.084 ;
    END
  END b0[213]
  PIN b0[214]
    DIRECTION INPUT ;
    USE SIGNAL ;
    PORT
      LAYER M5 ;
        RECT  22.896 0 22.92 0.084 ;
    END
  END b0[214]
  PIN b0[215]
    DIRECTION INPUT ;
    USE SIGNAL ;
    PORT
      LAYER M5 ;
        RECT  23.04 0 23.064 0.084 ;
    END
  END b0[215]
  PIN b0[216]
    DIRECTION INPUT ;
    USE SIGNAL ;
    PORT
      LAYER M5 ;
        RECT  23.184 0 23.208 0.084 ;
    END
  END b0[216]
  PIN b0[217]
    DIRECTION INPUT ;
    USE SIGNAL ;
    PORT
      LAYER M5 ;
        RECT  23.328 0 23.352 0.084 ;
    END
  END b0[217]
  PIN b0[218]
    DIRECTION INPUT ;
    USE SIGNAL ;
    PORT
      LAYER M5 ;
        RECT  23.472 0 23.496 0.084 ;
    END
  END b0[218]
  PIN b0[219]
    DIRECTION INPUT ;
    USE SIGNAL ;
    PORT
      LAYER M5 ;
        RECT  23.616 0 23.64 0.084 ;
    END
  END b0[219]
  PIN b0[21]
    DIRECTION INPUT ;
    USE SIGNAL ;
    PORT
      LAYER M5 ;
        RECT  137.952 0 137.976 0.084 ;
    END
  END b0[21]
  PIN b0[220]
    DIRECTION INPUT ;
    USE SIGNAL ;
    PORT
      LAYER M5 ;
        RECT  158.544 0 158.568 0.084 ;
    END
  END b0[220]
  PIN b0[221]
    DIRECTION INPUT ;
    USE SIGNAL ;
    PORT
      LAYER M5 ;
        RECT  158.688 0 158.712 0.084 ;
    END
  END b0[221]
  PIN b0[222]
    DIRECTION INPUT ;
    USE SIGNAL ;
    PORT
      LAYER M5 ;
        RECT  158.832 0 158.856 0.084 ;
    END
  END b0[222]
  PIN b0[223]
    DIRECTION INPUT ;
    USE SIGNAL ;
    PORT
      LAYER M5 ;
        RECT  158.976 0 159 0.084 ;
    END
  END b0[223]
  PIN b0[224]
    DIRECTION INPUT ;
    USE SIGNAL ;
    PORT
      LAYER M5 ;
        RECT  159.12 0 159.144 0.084 ;
    END
  END b0[224]
  PIN b0[225]
    DIRECTION INPUT ;
    USE SIGNAL ;
    PORT
      LAYER M5 ;
        RECT  159.264 0 159.288 0.084 ;
    END
  END b0[225]
  PIN b0[226]
    DIRECTION INPUT ;
    USE SIGNAL ;
    PORT
      LAYER M5 ;
        RECT  159.408 0 159.432 0.084 ;
    END
  END b0[226]
  PIN b0[227]
    DIRECTION INPUT ;
    USE SIGNAL ;
    PORT
      LAYER M5 ;
        RECT  159.552 0 159.576 0.084 ;
    END
  END b0[227]
  PIN b0[228]
    DIRECTION INPUT ;
    USE SIGNAL ;
    PORT
      LAYER M5 ;
        RECT  159.696 0 159.72 0.084 ;
    END
  END b0[228]
  PIN b0[229]
    DIRECTION INPUT ;
    USE SIGNAL ;
    PORT
      LAYER M5 ;
        RECT  159.84 0 159.864 0.084 ;
    END
  END b0[229]
  PIN b0[22]
    DIRECTION INPUT ;
    USE SIGNAL ;
    PORT
      LAYER M5 ;
        RECT  138.096 0 138.12 0.084 ;
    END
  END b0[22]
  PIN b0[230]
    DIRECTION INPUT ;
    USE SIGNAL ;
    PORT
      LAYER M5 ;
        RECT  159.984 0 160.008 0.084 ;
    END
  END b0[230]
  PIN b0[231]
    DIRECTION INPUT ;
    USE SIGNAL ;
    PORT
      LAYER M5 ;
        RECT  160.128 0 160.152 0.084 ;
    END
  END b0[231]
  PIN b0[232]
    DIRECTION INPUT ;
    USE SIGNAL ;
    PORT
      LAYER M5 ;
        RECT  160.272 0 160.296 0.084 ;
    END
  END b0[232]
  PIN b0[233]
    DIRECTION INPUT ;
    USE SIGNAL ;
    PORT
      LAYER M5 ;
        RECT  160.416 0 160.44 0.084 ;
    END
  END b0[233]
  PIN b0[234]
    DIRECTION INPUT ;
    USE SIGNAL ;
    PORT
      LAYER M5 ;
        RECT  160.56 0 160.584 0.084 ;
    END
  END b0[234]
  PIN b0[235]
    DIRECTION INPUT ;
    USE SIGNAL ;
    PORT
      LAYER M5 ;
        RECT  160.704 0 160.728 0.084 ;
    END
  END b0[235]
  PIN b0[236]
    DIRECTION INPUT ;
    USE SIGNAL ;
    PORT
      LAYER M5 ;
        RECT  160.848 0 160.872 0.084 ;
    END
  END b0[236]
  PIN b0[237]
    DIRECTION INPUT ;
    USE SIGNAL ;
    PORT
      LAYER M5 ;
        RECT  160.992 0 161.016 0.084 ;
    END
  END b0[237]
  PIN b0[238]
    DIRECTION INPUT ;
    USE SIGNAL ;
    PORT
      LAYER M5 ;
        RECT  161.136 0 161.16 0.084 ;
    END
  END b0[238]
  PIN b0[239]
    DIRECTION INPUT ;
    USE SIGNAL ;
    PORT
      LAYER M5 ;
        RECT  161.28 0 161.304 0.084 ;
    END
  END b0[239]
  PIN b0[23]
    DIRECTION INPUT ;
    USE SIGNAL ;
    PORT
      LAYER M5 ;
        RECT  138.24 0 138.264 0.084 ;
    END
  END b0[23]
  PIN b0[240]
    DIRECTION INPUT ;
    USE SIGNAL ;
    PORT
      LAYER M5 ;
        RECT  161.424 0 161.448 0.084 ;
    END
  END b0[240]
  PIN b0[241]
    DIRECTION INPUT ;
    USE SIGNAL ;
    PORT
      LAYER M5 ;
        RECT  161.568 0 161.592 0.084 ;
    END
  END b0[241]
  PIN b0[242]
    DIRECTION INPUT ;
    USE SIGNAL ;
    PORT
      LAYER M5 ;
        RECT  161.712 0 161.736 0.084 ;
    END
  END b0[242]
  PIN b0[243]
    DIRECTION INPUT ;
    USE SIGNAL ;
    PORT
      LAYER M5 ;
        RECT  161.856 0 161.88 0.084 ;
    END
  END b0[243]
  PIN b0[244]
    DIRECTION INPUT ;
    USE SIGNAL ;
    PORT
      LAYER M5 ;
        RECT  162 0 162.024 0.084 ;
    END
  END b0[244]
  PIN b0[245]
    DIRECTION INPUT ;
    USE SIGNAL ;
    PORT
      LAYER M5 ;
        RECT  162.144 0 162.168 0.084 ;
    END
  END b0[245]
  PIN b0[246]
    DIRECTION INPUT ;
    USE SIGNAL ;
    PORT
      LAYER M5 ;
        RECT  162.288 0 162.312 0.084 ;
    END
  END b0[246]
  PIN b0[247]
    DIRECTION INPUT ;
    USE SIGNAL ;
    PORT
      LAYER M5 ;
        RECT  162.432 0 162.456 0.084 ;
    END
  END b0[247]
  PIN b0[248]
    DIRECTION INPUT ;
    USE SIGNAL ;
    PORT
      LAYER M5 ;
        RECT  162.576 0 162.6 0.084 ;
    END
  END b0[248]
  PIN b0[249]
    DIRECTION INPUT ;
    USE SIGNAL ;
    PORT
      LAYER M5 ;
        RECT  162.72 0 162.744 0.084 ;
    END
  END b0[249]
  PIN b0[24]
    DIRECTION INPUT ;
    USE SIGNAL ;
    PORT
      LAYER M5 ;
        RECT  138.384 0 138.408 0.084 ;
    END
  END b0[24]
  PIN b0[250]
    DIRECTION INPUT ;
    USE SIGNAL ;
    PORT
      LAYER M5 ;
        RECT  162.864 0 162.888 0.084 ;
    END
  END b0[250]
  PIN b0[251]
    DIRECTION INPUT ;
    USE SIGNAL ;
    PORT
      LAYER M5 ;
        RECT  163.008 0 163.032 0.084 ;
    END
  END b0[251]
  PIN b0[252]
    DIRECTION INPUT ;
    USE SIGNAL ;
    PORT
      LAYER M5 ;
        RECT  167.76 0 167.784 0.084 ;
    END
  END b0[252]
  PIN b0[253]
    DIRECTION INPUT ;
    USE SIGNAL ;
    PORT
      LAYER M5 ;
        RECT  167.904 0 167.928 0.084 ;
    END
  END b0[253]
  PIN b0[254]
    DIRECTION INPUT ;
    USE SIGNAL ;
    PORT
      LAYER M5 ;
        RECT  168.048 0 168.072 0.084 ;
    END
  END b0[254]
  PIN b0[255]
    DIRECTION INPUT ;
    USE SIGNAL ;
    PORT
      LAYER M5 ;
        RECT  168.192 0 168.216 0.084 ;
    END
  END b0[255]
  PIN b0[256]
    DIRECTION INPUT ;
    USE SIGNAL ;
    PORT
      LAYER M5 ;
        RECT  168.336 0 168.36 0.084 ;
    END
  END b0[256]
  PIN b0[257]
    DIRECTION INPUT ;
    USE SIGNAL ;
    PORT
      LAYER M5 ;
        RECT  168.48 0 168.504 0.084 ;
    END
  END b0[257]
  PIN b0[25]
    DIRECTION INPUT ;
    USE SIGNAL ;
    PORT
      LAYER M5 ;
        RECT  138.528 0 138.552 0.084 ;
    END
  END b0[25]
  PIN b0[26]
    DIRECTION INPUT ;
    USE SIGNAL ;
    PORT
      LAYER M5 ;
        RECT  138.672 0 138.696 0.084 ;
    END
  END b0[26]
  PIN b0[27]
    DIRECTION INPUT ;
    USE SIGNAL ;
    PORT
      LAYER M5 ;
        RECT  138.816 0 138.84 0.084 ;
    END
  END b0[27]
  PIN b0[28]
    DIRECTION INPUT ;
    USE SIGNAL ;
    PORT
      LAYER M5 ;
        RECT  29.52 0 29.544 0.084 ;
    END
  END b0[28]
  PIN b0[29]
    DIRECTION INPUT ;
    USE SIGNAL ;
    PORT
      LAYER M5 ;
        RECT  29.664 0 29.688 0.084 ;
    END
  END b0[29]
  PIN b0[2]
    DIRECTION INPUT ;
    USE SIGNAL ;
    PORT
      LAYER M5 ;
        RECT  135.216 0 135.24 0.084 ;
    END
  END b0[2]
  PIN b0[30]
    DIRECTION INPUT ;
    USE SIGNAL ;
    PORT
      LAYER M5 ;
        RECT  29.808 0 29.832 0.084 ;
    END
  END b0[30]
  PIN b0[31]
    DIRECTION INPUT ;
    USE SIGNAL ;
    PORT
      LAYER M5 ;
        RECT  29.952 0 29.976 0.084 ;
    END
  END b0[31]
  PIN b0[32]
    DIRECTION INPUT ;
    USE SIGNAL ;
    PORT
      LAYER M5 ;
        RECT  30.096 0 30.12 0.084 ;
    END
  END b0[32]
  PIN b0[33]
    DIRECTION INPUT ;
    USE SIGNAL ;
    PORT
      LAYER M5 ;
        RECT  30.24 0 30.264 0.084 ;
    END
  END b0[33]
  PIN b0[34]
    DIRECTION INPUT ;
    USE SIGNAL ;
    PORT
      LAYER M5 ;
        RECT  30.384 0 30.408 0.084 ;
    END
  END b0[34]
  PIN b0[35]
    DIRECTION INPUT ;
    USE SIGNAL ;
    PORT
      LAYER M5 ;
        RECT  30.528 0 30.552 0.084 ;
    END
  END b0[35]
  PIN b0[36]
    DIRECTION INPUT ;
    USE SIGNAL ;
    PORT
      LAYER M5 ;
        RECT  30.672 0 30.696 0.084 ;
    END
  END b0[36]
  PIN b0[37]
    DIRECTION INPUT ;
    USE SIGNAL ;
    PORT
      LAYER M5 ;
        RECT  30.816 0 30.84 0.084 ;
    END
  END b0[37]
  PIN b0[38]
    DIRECTION INPUT ;
    USE SIGNAL ;
    PORT
      LAYER M5 ;
        RECT  30.96 0 30.984 0.084 ;
    END
  END b0[38]
  PIN b0[39]
    DIRECTION INPUT ;
    USE SIGNAL ;
    PORT
      LAYER M5 ;
        RECT  31.104 0 31.128 0.084 ;
    END
  END b0[39]
  PIN b0[3]
    DIRECTION INPUT ;
    USE SIGNAL ;
    PORT
      LAYER M5 ;
        RECT  135.36 0 135.384 0.084 ;
    END
  END b0[3]
  PIN b0[40]
    DIRECTION INPUT ;
    USE SIGNAL ;
    PORT
      LAYER M5 ;
        RECT  31.248 0 31.272 0.084 ;
    END
  END b0[40]
  PIN b0[41]
    DIRECTION INPUT ;
    USE SIGNAL ;
    PORT
      LAYER M5 ;
        RECT  31.392 0 31.416 0.084 ;
    END
  END b0[41]
  PIN b0[42]
    DIRECTION INPUT ;
    USE SIGNAL ;
    PORT
      LAYER M5 ;
        RECT  31.536 0 31.56 0.084 ;
    END
  END b0[42]
  PIN b0[43]
    DIRECTION INPUT ;
    USE SIGNAL ;
    PORT
      LAYER M5 ;
        RECT  31.68 0 31.704 0.084 ;
    END
  END b0[43]
  PIN b0[44]
    DIRECTION INPUT ;
    USE SIGNAL ;
    PORT
      LAYER M5 ;
        RECT  31.824 0 31.848 0.084 ;
    END
  END b0[44]
  PIN b0[45]
    DIRECTION INPUT ;
    USE SIGNAL ;
    PORT
      LAYER M5 ;
        RECT  31.968 0 31.992 0.084 ;
    END
  END b0[45]
  PIN b0[46]
    DIRECTION INPUT ;
    USE SIGNAL ;
    PORT
      LAYER M5 ;
        RECT  32.112 0 32.136 0.084 ;
    END
  END b0[46]
  PIN b0[47]
    DIRECTION INPUT ;
    USE SIGNAL ;
    PORT
      LAYER M5 ;
        RECT  32.256 0 32.28 0.084 ;
    END
  END b0[47]
  PIN b0[48]
    DIRECTION INPUT ;
    USE SIGNAL ;
    PORT
      LAYER M5 ;
        RECT  32.4 0 32.424 0.084 ;
    END
  END b0[48]
  PIN b0[49]
    DIRECTION INPUT ;
    USE SIGNAL ;
    PORT
      LAYER M5 ;
        RECT  32.544 0 32.568 0.084 ;
    END
  END b0[49]
  PIN b0[4]
    DIRECTION INPUT ;
    USE SIGNAL ;
    PORT
      LAYER M5 ;
        RECT  135.504 0 135.528 0.084 ;
    END
  END b0[4]
  PIN b0[50]
    DIRECTION INPUT ;
    USE SIGNAL ;
    PORT
      LAYER M5 ;
        RECT  32.688 0 32.712 0.084 ;
    END
  END b0[50]
  PIN b0[51]
    DIRECTION INPUT ;
    USE SIGNAL ;
    PORT
      LAYER M5 ;
        RECT  32.832 0 32.856 0.084 ;
    END
  END b0[51]
  PIN b0[52]
    DIRECTION INPUT ;
    USE SIGNAL ;
    PORT
      LAYER M5 ;
        RECT  32.976 0 33 0.084 ;
    END
  END b0[52]
  PIN b0[53]
    DIRECTION INPUT ;
    USE SIGNAL ;
    PORT
      LAYER M5 ;
        RECT  33.12 0 33.144 0.084 ;
    END
  END b0[53]
  PIN b0[54]
    DIRECTION INPUT ;
    USE SIGNAL ;
    PORT
      LAYER M5 ;
        RECT  33.264 0 33.288 0.084 ;
    END
  END b0[54]
  PIN b0[55]
    DIRECTION INPUT ;
    USE SIGNAL ;
    PORT
      LAYER M5 ;
        RECT  33.408 0 33.432 0.084 ;
    END
  END b0[55]
  PIN b0[56]
    DIRECTION INPUT ;
    USE SIGNAL ;
    PORT
      LAYER M5 ;
        RECT  33.552 0 33.576 0.084 ;
    END
  END b0[56]
  PIN b0[57]
    DIRECTION INPUT ;
    USE SIGNAL ;
    PORT
      LAYER M5 ;
        RECT  33.696 0 33.72 0.084 ;
    END
  END b0[57]
  PIN b0[58]
    DIRECTION INPUT ;
    USE SIGNAL ;
    PORT
      LAYER M5 ;
        RECT  33.84 0 33.864 0.084 ;
    END
  END b0[58]
  PIN b0[59]
    DIRECTION INPUT ;
    USE SIGNAL ;
    PORT
      LAYER M5 ;
        RECT  33.984 0 34.008 0.084 ;
    END
  END b0[59]
  PIN b0[5]
    DIRECTION INPUT ;
    USE SIGNAL ;
    PORT
      LAYER M5 ;
        RECT  135.648 0 135.672 0.084 ;
    END
  END b0[5]
  PIN b0[60]
    DIRECTION INPUT ;
    USE SIGNAL ;
    PORT
      LAYER M5 ;
        RECT  43.344 0 43.368 0.084 ;
    END
  END b0[60]
  PIN b0[61]
    DIRECTION INPUT ;
    USE SIGNAL ;
    PORT
      LAYER M5 ;
        RECT  43.488 0 43.512 0.084 ;
    END
  END b0[61]
  PIN b0[62]
    DIRECTION INPUT ;
    USE SIGNAL ;
    PORT
      LAYER M5 ;
        RECT  43.632 0 43.656 0.084 ;
    END
  END b0[62]
  PIN b0[63]
    DIRECTION INPUT ;
    USE SIGNAL ;
    PORT
      LAYER M5 ;
        RECT  43.776 0 43.8 0.084 ;
    END
  END b0[63]
  PIN b0[64]
    DIRECTION INPUT ;
    USE SIGNAL ;
    PORT
      LAYER M5 ;
        RECT  43.92 0 43.944 0.084 ;
    END
  END b0[64]
  PIN b0[65]
    DIRECTION INPUT ;
    USE SIGNAL ;
    PORT
      LAYER M5 ;
        RECT  44.064 0 44.088 0.084 ;
    END
  END b0[65]
  PIN b0[66]
    DIRECTION INPUT ;
    USE SIGNAL ;
    PORT
      LAYER M5 ;
        RECT  44.208 0 44.232 0.084 ;
    END
  END b0[66]
  PIN b0[67]
    DIRECTION INPUT ;
    USE SIGNAL ;
    PORT
      LAYER M5 ;
        RECT  44.352 0 44.376 0.084 ;
    END
  END b0[67]
  PIN b0[68]
    DIRECTION INPUT ;
    USE SIGNAL ;
    PORT
      LAYER M5 ;
        RECT  44.496 0 44.52 0.084 ;
    END
  END b0[68]
  PIN b0[69]
    DIRECTION INPUT ;
    USE SIGNAL ;
    PORT
      LAYER M5 ;
        RECT  44.64 0 44.664 0.084 ;
    END
  END b0[69]
  PIN b0[6]
    DIRECTION INPUT ;
    USE SIGNAL ;
    PORT
      LAYER M5 ;
        RECT  135.792 0 135.816 0.084 ;
    END
  END b0[6]
  PIN b0[70]
    DIRECTION INPUT ;
    USE SIGNAL ;
    PORT
      LAYER M5 ;
        RECT  44.784 0 44.808 0.084 ;
    END
  END b0[70]
  PIN b0[71]
    DIRECTION INPUT ;
    USE SIGNAL ;
    PORT
      LAYER M5 ;
        RECT  44.928 0 44.952 0.084 ;
    END
  END b0[71]
  PIN b0[72]
    DIRECTION INPUT ;
    USE SIGNAL ;
    PORT
      LAYER M5 ;
        RECT  45.072 0 45.096 0.084 ;
    END
  END b0[72]
  PIN b0[73]
    DIRECTION INPUT ;
    USE SIGNAL ;
    PORT
      LAYER M5 ;
        RECT  45.216 0 45.24 0.084 ;
    END
  END b0[73]
  PIN b0[74]
    DIRECTION INPUT ;
    USE SIGNAL ;
    PORT
      LAYER M5 ;
        RECT  45.36 0 45.384 0.084 ;
    END
  END b0[74]
  PIN b0[75]
    DIRECTION INPUT ;
    USE SIGNAL ;
    PORT
      LAYER M5 ;
        RECT  45.504 0 45.528 0.084 ;
    END
  END b0[75]
  PIN b0[76]
    DIRECTION INPUT ;
    USE SIGNAL ;
    PORT
      LAYER M5 ;
        RECT  45.648 0 45.672 0.084 ;
    END
  END b0[76]
  PIN b0[77]
    DIRECTION INPUT ;
    USE SIGNAL ;
    PORT
      LAYER M5 ;
        RECT  45.792 0 45.816 0.084 ;
    END
  END b0[77]
  PIN b0[78]
    DIRECTION INPUT ;
    USE SIGNAL ;
    PORT
      LAYER M5 ;
        RECT  45.936 0 45.96 0.084 ;
    END
  END b0[78]
  PIN b0[79]
    DIRECTION INPUT ;
    USE SIGNAL ;
    PORT
      LAYER M5 ;
        RECT  46.08 0 46.104 0.084 ;
    END
  END b0[79]
  PIN b0[7]
    DIRECTION INPUT ;
    USE SIGNAL ;
    PORT
      LAYER M5 ;
        RECT  135.936 0 135.96 0.084 ;
    END
  END b0[7]
  PIN b0[80]
    DIRECTION INPUT ;
    USE SIGNAL ;
    PORT
      LAYER M5 ;
        RECT  46.224 0 46.248 0.084 ;
    END
  END b0[80]
  PIN b0[81]
    DIRECTION INPUT ;
    USE SIGNAL ;
    PORT
      LAYER M5 ;
        RECT  46.368 0 46.392 0.084 ;
    END
  END b0[81]
  PIN b0[82]
    DIRECTION INPUT ;
    USE SIGNAL ;
    PORT
      LAYER M5 ;
        RECT  46.512 0 46.536 0.084 ;
    END
  END b0[82]
  PIN b0[83]
    DIRECTION INPUT ;
    USE SIGNAL ;
    PORT
      LAYER M5 ;
        RECT  46.656 0 46.68 0.084 ;
    END
  END b0[83]
  PIN b0[84]
    DIRECTION INPUT ;
    USE SIGNAL ;
    PORT
      LAYER M5 ;
        RECT  46.8 0 46.824 0.084 ;
    END
  END b0[84]
  PIN b0[85]
    DIRECTION INPUT ;
    USE SIGNAL ;
    PORT
      LAYER M5 ;
        RECT  46.944 0 46.968 0.084 ;
    END
  END b0[85]
  PIN b0[86]
    DIRECTION INPUT ;
    USE SIGNAL ;
    PORT
      LAYER M5 ;
        RECT  47.088 0 47.112 0.084 ;
    END
  END b0[86]
  PIN b0[87]
    DIRECTION INPUT ;
    USE SIGNAL ;
    PORT
      LAYER M5 ;
        RECT  47.232 0 47.256 0.084 ;
    END
  END b0[87]
  PIN b0[88]
    DIRECTION INPUT ;
    USE SIGNAL ;
    PORT
      LAYER M5 ;
        RECT  47.376 0 47.4 0.084 ;
    END
  END b0[88]
  PIN b0[89]
    DIRECTION INPUT ;
    USE SIGNAL ;
    PORT
      LAYER M5 ;
        RECT  47.52 0 47.544 0.084 ;
    END
  END b0[89]
  PIN b0[8]
    DIRECTION INPUT ;
    USE SIGNAL ;
    PORT
      LAYER M5 ;
        RECT  136.08 0 136.104 0.084 ;
    END
  END b0[8]
  PIN b0[90]
    DIRECTION INPUT ;
    USE SIGNAL ;
    PORT
      LAYER M5 ;
        RECT  47.664 0 47.688 0.084 ;
    END
  END b0[90]
  PIN b0[91]
    DIRECTION INPUT ;
    USE SIGNAL ;
    PORT
      LAYER M5 ;
        RECT  47.808 0 47.832 0.084 ;
    END
  END b0[91]
  PIN b0[92]
    DIRECTION INPUT ;
    USE SIGNAL ;
    PORT
      LAYER M5 ;
        RECT  38.736 0 38.76 0.084 ;
    END
  END b0[92]
  PIN b0[93]
    DIRECTION INPUT ;
    USE SIGNAL ;
    PORT
      LAYER M5 ;
        RECT  38.88 0 38.904 0.084 ;
    END
  END b0[93]
  PIN b0[94]
    DIRECTION INPUT ;
    USE SIGNAL ;
    PORT
      LAYER M5 ;
        RECT  39.024 0 39.048 0.084 ;
    END
  END b0[94]
  PIN b0[95]
    DIRECTION INPUT ;
    USE SIGNAL ;
    PORT
      LAYER M5 ;
        RECT  39.168 0 39.192 0.084 ;
    END
  END b0[95]
  PIN b0[96]
    DIRECTION INPUT ;
    USE SIGNAL ;
    PORT
      LAYER M5 ;
        RECT  39.312 0 39.336 0.084 ;
    END
  END b0[96]
  PIN b0[97]
    DIRECTION INPUT ;
    USE SIGNAL ;
    PORT
      LAYER M5 ;
        RECT  39.456 0 39.48 0.084 ;
    END
  END b0[97]
  PIN b0[98]
    DIRECTION INPUT ;
    USE SIGNAL ;
    PORT
      LAYER M5 ;
        RECT  39.6 0 39.624 0.084 ;
    END
  END b0[98]
  PIN b0[99]
    DIRECTION INPUT ;
    USE SIGNAL ;
    PORT
      LAYER M5 ;
        RECT  39.744 0 39.768 0.084 ;
    END
  END b0[99]
  PIN b0[9]
    DIRECTION INPUT ;
    USE SIGNAL ;
    PORT
      LAYER M5 ;
        RECT  136.224 0 136.248 0.084 ;
    END
  END b0[9]
  PIN b1[0]
    DIRECTION INPUT ;
    USE SIGNAL ;
    PORT
      LAYER M5 ;
        RECT  168.624 0 168.648 0.084 ;
    END
  END b1[0]
  PIN b1[100]
    DIRECTION INPUT ;
    USE SIGNAL ;
    PORT
      LAYER M5 ;
        RECT  164.592 0 164.616 0.084 ;
    END
  END b1[100]
  PIN b1[101]
    DIRECTION INPUT ;
    USE SIGNAL ;
    PORT
      LAYER M5 ;
        RECT  164.736 0 164.76 0.084 ;
    END
  END b1[101]
  PIN b1[102]
    DIRECTION INPUT ;
    USE SIGNAL ;
    PORT
      LAYER M5 ;
        RECT  164.88 0 164.904 0.084 ;
    END
  END b1[102]
  PIN b1[103]
    DIRECTION INPUT ;
    USE SIGNAL ;
    PORT
      LAYER M5 ;
        RECT  165.024 0 165.048 0.084 ;
    END
  END b1[103]
  PIN b1[104]
    DIRECTION INPUT ;
    USE SIGNAL ;
    PORT
      LAYER M5 ;
        RECT  165.168 0 165.192 0.084 ;
    END
  END b1[104]
  PIN b1[105]
    DIRECTION INPUT ;
    USE SIGNAL ;
    PORT
      LAYER M5 ;
        RECT  165.312 0 165.336 0.084 ;
    END
  END b1[105]
  PIN b1[106]
    DIRECTION INPUT ;
    USE SIGNAL ;
    PORT
      LAYER M5 ;
        RECT  165.456 0 165.48 0.084 ;
    END
  END b1[106]
  PIN b1[107]
    DIRECTION INPUT ;
    USE SIGNAL ;
    PORT
      LAYER M5 ;
        RECT  165.6 0 165.624 0.084 ;
    END
  END b1[107]
  PIN b1[108]
    DIRECTION INPUT ;
    USE SIGNAL ;
    PORT
      LAYER M5 ;
        RECT  165.744 0 165.768 0.084 ;
    END
  END b1[108]
  PIN b1[109]
    DIRECTION INPUT ;
    USE SIGNAL ;
    PORT
      LAYER M5 ;
        RECT  165.888 0 165.912 0.084 ;
    END
  END b1[109]
  PIN b1[10]
    DIRECTION INPUT ;
    USE SIGNAL ;
    PORT
      LAYER M5 ;
        RECT  170.064 0 170.088 0.084 ;
    END
  END b1[10]
  PIN b1[110]
    DIRECTION INPUT ;
    USE SIGNAL ;
    PORT
      LAYER M5 ;
        RECT  166.032 0 166.056 0.084 ;
    END
  END b1[110]
  PIN b1[111]
    DIRECTION INPUT ;
    USE SIGNAL ;
    PORT
      LAYER M5 ;
        RECT  166.176 0 166.2 0.084 ;
    END
  END b1[111]
  PIN b1[112]
    DIRECTION INPUT ;
    USE SIGNAL ;
    PORT
      LAYER M5 ;
        RECT  166.32 0 166.344 0.084 ;
    END
  END b1[112]
  PIN b1[113]
    DIRECTION INPUT ;
    USE SIGNAL ;
    PORT
      LAYER M5 ;
        RECT  166.464 0 166.488 0.084 ;
    END
  END b1[113]
  PIN b1[114]
    DIRECTION INPUT ;
    USE SIGNAL ;
    PORT
      LAYER M5 ;
        RECT  166.608 0 166.632 0.084 ;
    END
  END b1[114]
  PIN b1[115]
    DIRECTION INPUT ;
    USE SIGNAL ;
    PORT
      LAYER M5 ;
        RECT  166.752 0 166.776 0.084 ;
    END
  END b1[115]
  PIN b1[116]
    DIRECTION INPUT ;
    USE SIGNAL ;
    PORT
      LAYER M5 ;
        RECT  166.896 0 166.92 0.084 ;
    END
  END b1[116]
  PIN b1[117]
    DIRECTION INPUT ;
    USE SIGNAL ;
    PORT
      LAYER M5 ;
        RECT  167.04 0 167.064 0.084 ;
    END
  END b1[117]
  PIN b1[118]
    DIRECTION INPUT ;
    USE SIGNAL ;
    PORT
      LAYER M5 ;
        RECT  167.184 0 167.208 0.084 ;
    END
  END b1[118]
  PIN b1[119]
    DIRECTION INPUT ;
    USE SIGNAL ;
    PORT
      LAYER M5 ;
        RECT  167.328 0 167.352 0.084 ;
    END
  END b1[119]
  PIN b1[11]
    DIRECTION INPUT ;
    USE SIGNAL ;
    PORT
      LAYER M5 ;
        RECT  170.208 0 170.232 0.084 ;
    END
  END b1[11]
  PIN b1[120]
    DIRECTION INPUT ;
    USE SIGNAL ;
    PORT
      LAYER M5 ;
        RECT  167.472 0 167.496 0.084 ;
    END
  END b1[120]
  PIN b1[121]
    DIRECTION INPUT ;
    USE SIGNAL ;
    PORT
      LAYER M5 ;
        RECT  167.616 0 167.64 0.084 ;
    END
  END b1[121]
  PIN b1[122]
    DIRECTION INPUT ;
    USE SIGNAL ;
    PORT
      LAYER M5 ;
        RECT  149.328 0 149.352 0.084 ;
    END
  END b1[122]
  PIN b1[123]
    DIRECTION INPUT ;
    USE SIGNAL ;
    PORT
      LAYER M5 ;
        RECT  149.472 0 149.496 0.084 ;
    END
  END b1[123]
  PIN b1[124]
    DIRECTION INPUT ;
    USE SIGNAL ;
    PORT
      LAYER M5 ;
        RECT  149.616 0 149.64 0.084 ;
    END
  END b1[124]
  PIN b1[125]
    DIRECTION INPUT ;
    USE SIGNAL ;
    PORT
      LAYER M5 ;
        RECT  149.76 0 149.784 0.084 ;
    END
  END b1[125]
  PIN b1[126]
    DIRECTION INPUT ;
    USE SIGNAL ;
    PORT
      LAYER M5 ;
        RECT  149.904 0 149.928 0.084 ;
    END
  END b1[126]
  PIN b1[127]
    DIRECTION INPUT ;
    USE SIGNAL ;
    PORT
      LAYER M5 ;
        RECT  150.048 0 150.072 0.084 ;
    END
  END b1[127]
  PIN b1[128]
    DIRECTION INPUT ;
    USE SIGNAL ;
    PORT
      LAYER M5 ;
        RECT  150.192 0 150.216 0.084 ;
    END
  END b1[128]
  PIN b1[129]
    DIRECTION INPUT ;
    USE SIGNAL ;
    PORT
      LAYER M5 ;
        RECT  150.336 0 150.36 0.084 ;
    END
  END b1[129]
  PIN b1[12]
    DIRECTION INPUT ;
    USE SIGNAL ;
    PORT
      LAYER M5 ;
        RECT  170.352 0 170.376 0.084 ;
    END
  END b1[12]
  PIN b1[130]
    DIRECTION INPUT ;
    USE SIGNAL ;
    PORT
      LAYER M5 ;
        RECT  150.48 0 150.504 0.084 ;
    END
  END b1[130]
  PIN b1[131]
    DIRECTION INPUT ;
    USE SIGNAL ;
    PORT
      LAYER M5 ;
        RECT  150.624 0 150.648 0.084 ;
    END
  END b1[131]
  PIN b1[132]
    DIRECTION INPUT ;
    USE SIGNAL ;
    PORT
      LAYER M5 ;
        RECT  150.768 0 150.792 0.084 ;
    END
  END b1[132]
  PIN b1[133]
    DIRECTION INPUT ;
    USE SIGNAL ;
    PORT
      LAYER M5 ;
        RECT  150.912 0 150.936 0.084 ;
    END
  END b1[133]
  PIN b1[134]
    DIRECTION INPUT ;
    USE SIGNAL ;
    PORT
      LAYER M5 ;
        RECT  151.056 0 151.08 0.084 ;
    END
  END b1[134]
  PIN b1[135]
    DIRECTION INPUT ;
    USE SIGNAL ;
    PORT
      LAYER M5 ;
        RECT  151.2 0 151.224 0.084 ;
    END
  END b1[135]
  PIN b1[136]
    DIRECTION INPUT ;
    USE SIGNAL ;
    PORT
      LAYER M5 ;
        RECT  151.344 0 151.368 0.084 ;
    END
  END b1[136]
  PIN b1[137]
    DIRECTION INPUT ;
    USE SIGNAL ;
    PORT
      LAYER M5 ;
        RECT  151.488 0 151.512 0.084 ;
    END
  END b1[137]
  PIN b1[138]
    DIRECTION INPUT ;
    USE SIGNAL ;
    PORT
      LAYER M5 ;
        RECT  151.632 0 151.656 0.084 ;
    END
  END b1[138]
  PIN b1[139]
    DIRECTION INPUT ;
    USE SIGNAL ;
    PORT
      LAYER M5 ;
        RECT  151.776 0 151.8 0.084 ;
    END
  END b1[139]
  PIN b1[13]
    DIRECTION INPUT ;
    USE SIGNAL ;
    PORT
      LAYER M5 ;
        RECT  170.496 0 170.52 0.084 ;
    END
  END b1[13]
  PIN b1[140]
    DIRECTION INPUT ;
    USE SIGNAL ;
    PORT
      LAYER M5 ;
        RECT  151.92 0 151.944 0.084 ;
    END
  END b1[140]
  PIN b1[141]
    DIRECTION INPUT ;
    USE SIGNAL ;
    PORT
      LAYER M5 ;
        RECT  152.064 0 152.088 0.084 ;
    END
  END b1[141]
  PIN b1[142]
    DIRECTION INPUT ;
    USE SIGNAL ;
    PORT
      LAYER M5 ;
        RECT  152.208 0 152.232 0.084 ;
    END
  END b1[142]
  PIN b1[143]
    DIRECTION INPUT ;
    USE SIGNAL ;
    PORT
      LAYER M5 ;
        RECT  152.352 0 152.376 0.084 ;
    END
  END b1[143]
  PIN b1[144]
    DIRECTION INPUT ;
    USE SIGNAL ;
    PORT
      LAYER M5 ;
        RECT  152.496 0 152.52 0.084 ;
    END
  END b1[144]
  PIN b1[145]
    DIRECTION INPUT ;
    USE SIGNAL ;
    PORT
      LAYER M5 ;
        RECT  152.64 0 152.664 0.084 ;
    END
  END b1[145]
  PIN b1[146]
    DIRECTION INPUT ;
    USE SIGNAL ;
    PORT
      LAYER M5 ;
        RECT  152.784 0 152.808 0.084 ;
    END
  END b1[146]
  PIN b1[147]
    DIRECTION INPUT ;
    USE SIGNAL ;
    PORT
      LAYER M5 ;
        RECT  152.928 0 152.952 0.084 ;
    END
  END b1[147]
  PIN b1[148]
    DIRECTION INPUT ;
    USE SIGNAL ;
    PORT
      LAYER M5 ;
        RECT  153.072 0 153.096 0.084 ;
    END
  END b1[148]
  PIN b1[149]
    DIRECTION INPUT ;
    USE SIGNAL ;
    PORT
      LAYER M5 ;
        RECT  153.216 0 153.24 0.084 ;
    END
  END b1[149]
  PIN b1[14]
    DIRECTION INPUT ;
    USE SIGNAL ;
    PORT
      LAYER M5 ;
        RECT  170.64 0 170.664 0.084 ;
    END
  END b1[14]
  PIN b1[150]
    DIRECTION INPUT ;
    USE SIGNAL ;
    PORT
      LAYER M5 ;
        RECT  153.36 0 153.384 0.084 ;
    END
  END b1[150]
  PIN b1[151]
    DIRECTION INPUT ;
    USE SIGNAL ;
    PORT
      LAYER M5 ;
        RECT  153.504 0 153.528 0.084 ;
    END
  END b1[151]
  PIN b1[152]
    DIRECTION INPUT ;
    USE SIGNAL ;
    PORT
      LAYER M5 ;
        RECT  153.648 0 153.672 0.084 ;
    END
  END b1[152]
  PIN b1[153]
    DIRECTION INPUT ;
    USE SIGNAL ;
    PORT
      LAYER M5 ;
        RECT  153.792 0 153.816 0.084 ;
    END
  END b1[153]
  PIN b1[154]
    DIRECTION INPUT ;
    USE SIGNAL ;
    PORT
      LAYER M5 ;
        RECT  178.128 0 178.152 0.084 ;
    END
  END b1[154]
  PIN b1[155]
    DIRECTION INPUT ;
    USE SIGNAL ;
    PORT
      LAYER M5 ;
        RECT  178.272 0 178.296 0.084 ;
    END
  END b1[155]
  PIN b1[156]
    DIRECTION INPUT ;
    USE SIGNAL ;
    PORT
      LAYER M5 ;
        RECT  178.416 0 178.44 0.084 ;
    END
  END b1[156]
  PIN b1[157]
    DIRECTION INPUT ;
    USE SIGNAL ;
    PORT
      LAYER M5 ;
        RECT  178.56 0 178.584 0.084 ;
    END
  END b1[157]
  PIN b1[158]
    DIRECTION INPUT ;
    USE SIGNAL ;
    PORT
      LAYER M5 ;
        RECT  178.704 0 178.728 0.084 ;
    END
  END b1[158]
  PIN b1[159]
    DIRECTION INPUT ;
    USE SIGNAL ;
    PORT
      LAYER M5 ;
        RECT  178.848 0 178.872 0.084 ;
    END
  END b1[159]
  PIN b1[15]
    DIRECTION INPUT ;
    USE SIGNAL ;
    PORT
      LAYER M5 ;
        RECT  170.784 0 170.808 0.084 ;
    END
  END b1[15]
  PIN b1[160]
    DIRECTION INPUT ;
    USE SIGNAL ;
    PORT
      LAYER M5 ;
        RECT  178.992 0 179.016 0.084 ;
    END
  END b1[160]
  PIN b1[161]
    DIRECTION INPUT ;
    USE SIGNAL ;
    PORT
      LAYER M5 ;
        RECT  179.136 0 179.16 0.084 ;
    END
  END b1[161]
  PIN b1[162]
    DIRECTION INPUT ;
    USE SIGNAL ;
    PORT
      LAYER M5 ;
        RECT  179.28 0 179.304 0.084 ;
    END
  END b1[162]
  PIN b1[163]
    DIRECTION INPUT ;
    USE SIGNAL ;
    PORT
      LAYER M5 ;
        RECT  179.424 0 179.448 0.084 ;
    END
  END b1[163]
  PIN b1[164]
    DIRECTION INPUT ;
    USE SIGNAL ;
    PORT
      LAYER M5 ;
        RECT  179.568 0 179.592 0.084 ;
    END
  END b1[164]
  PIN b1[165]
    DIRECTION INPUT ;
    USE SIGNAL ;
    PORT
      LAYER M5 ;
        RECT  179.712 0 179.736 0.084 ;
    END
  END b1[165]
  PIN b1[166]
    DIRECTION INPUT ;
    USE SIGNAL ;
    PORT
      LAYER M5 ;
        RECT  179.856 0 179.88 0.084 ;
    END
  END b1[166]
  PIN b1[167]
    DIRECTION INPUT ;
    USE SIGNAL ;
    PORT
      LAYER M5 ;
        RECT  180 0 180.024 0.084 ;
    END
  END b1[167]
  PIN b1[168]
    DIRECTION INPUT ;
    USE SIGNAL ;
    PORT
      LAYER M5 ;
        RECT  180.144 0 180.168 0.084 ;
    END
  END b1[168]
  PIN b1[169]
    DIRECTION INPUT ;
    USE SIGNAL ;
    PORT
      LAYER M5 ;
        RECT  180.288 0 180.312 0.084 ;
    END
  END b1[169]
  PIN b1[16]
    DIRECTION INPUT ;
    USE SIGNAL ;
    PORT
      LAYER M5 ;
        RECT  170.928 0 170.952 0.084 ;
    END
  END b1[16]
  PIN b1[170]
    DIRECTION INPUT ;
    USE SIGNAL ;
    PORT
      LAYER M5 ;
        RECT  180.432 0 180.456 0.084 ;
    END
  END b1[170]
  PIN b1[171]
    DIRECTION INPUT ;
    USE SIGNAL ;
    PORT
      LAYER M5 ;
        RECT  180.576 0 180.6 0.084 ;
    END
  END b1[171]
  PIN b1[172]
    DIRECTION INPUT ;
    USE SIGNAL ;
    PORT
      LAYER M5 ;
        RECT  180.72 0 180.744 0.084 ;
    END
  END b1[172]
  PIN b1[173]
    DIRECTION INPUT ;
    USE SIGNAL ;
    PORT
      LAYER M5 ;
        RECT  180.864 0 180.888 0.084 ;
    END
  END b1[173]
  PIN b1[174]
    DIRECTION INPUT ;
    USE SIGNAL ;
    PORT
      LAYER M5 ;
        RECT  181.008 0 181.032 0.084 ;
    END
  END b1[174]
  PIN b1[175]
    DIRECTION INPUT ;
    USE SIGNAL ;
    PORT
      LAYER M5 ;
        RECT  181.152 0 181.176 0.084 ;
    END
  END b1[175]
  PIN b1[176]
    DIRECTION INPUT ;
    USE SIGNAL ;
    PORT
      LAYER M5 ;
        RECT  181.296 0 181.32 0.084 ;
    END
  END b1[176]
  PIN b1[177]
    DIRECTION INPUT ;
    USE SIGNAL ;
    PORT
      LAYER M5 ;
        RECT  181.44 0 181.464 0.084 ;
    END
  END b1[177]
  PIN b1[178]
    DIRECTION INPUT ;
    USE SIGNAL ;
    PORT
      LAYER M5 ;
        RECT  181.584 0 181.608 0.084 ;
    END
  END b1[178]
  PIN b1[179]
    DIRECTION INPUT ;
    USE SIGNAL ;
    PORT
      LAYER M5 ;
        RECT  181.728 0 181.752 0.084 ;
    END
  END b1[179]
  PIN b1[17]
    DIRECTION INPUT ;
    USE SIGNAL ;
    PORT
      LAYER M5 ;
        RECT  171.072 0 171.096 0.084 ;
    END
  END b1[17]
  PIN b1[180]
    DIRECTION INPUT ;
    USE SIGNAL ;
    PORT
      LAYER M5 ;
        RECT  181.872 0 181.896 0.084 ;
    END
  END b1[180]
  PIN b1[181]
    DIRECTION INPUT ;
    USE SIGNAL ;
    PORT
      LAYER M5 ;
        RECT  182.016 0 182.04 0.084 ;
    END
  END b1[181]
  PIN b1[182]
    DIRECTION INPUT ;
    USE SIGNAL ;
    PORT
      LAYER M5 ;
        RECT  182.16 0 182.184 0.084 ;
    END
  END b1[182]
  PIN b1[183]
    DIRECTION INPUT ;
    USE SIGNAL ;
    PORT
      LAYER M5 ;
        RECT  182.304 0 182.328 0.084 ;
    END
  END b1[183]
  PIN b1[184]
    DIRECTION INPUT ;
    USE SIGNAL ;
    PORT
      LAYER M5 ;
        RECT  182.448 0 182.472 0.084 ;
    END
  END b1[184]
  PIN b1[185]
    DIRECTION INPUT ;
    USE SIGNAL ;
    PORT
      LAYER M5 ;
        RECT  182.592 0 182.616 0.084 ;
    END
  END b1[185]
  PIN b1[186]
    DIRECTION INPUT ;
    USE SIGNAL ;
    PORT
      LAYER M5 ;
        RECT  173.52 0 173.544 0.084 ;
    END
  END b1[186]
  PIN b1[187]
    DIRECTION INPUT ;
    USE SIGNAL ;
    PORT
      LAYER M5 ;
        RECT  173.664 0 173.688 0.084 ;
    END
  END b1[187]
  PIN b1[188]
    DIRECTION INPUT ;
    USE SIGNAL ;
    PORT
      LAYER M5 ;
        RECT  173.808 0 173.832 0.084 ;
    END
  END b1[188]
  PIN b1[189]
    DIRECTION INPUT ;
    USE SIGNAL ;
    PORT
      LAYER M5 ;
        RECT  173.952 0 173.976 0.084 ;
    END
  END b1[189]
  PIN b1[18]
    DIRECTION INPUT ;
    USE SIGNAL ;
    PORT
      LAYER M5 ;
        RECT  171.216 0 171.24 0.084 ;
    END
  END b1[18]
  PIN b1[190]
    DIRECTION INPUT ;
    USE SIGNAL ;
    PORT
      LAYER M5 ;
        RECT  174.096 0 174.12 0.084 ;
    END
  END b1[190]
  PIN b1[191]
    DIRECTION INPUT ;
    USE SIGNAL ;
    PORT
      LAYER M5 ;
        RECT  174.24 0 174.264 0.084 ;
    END
  END b1[191]
  PIN b1[192]
    DIRECTION INPUT ;
    USE SIGNAL ;
    PORT
      LAYER M5 ;
        RECT  174.384 0 174.408 0.084 ;
    END
  END b1[192]
  PIN b1[193]
    DIRECTION INPUT ;
    USE SIGNAL ;
    PORT
      LAYER M5 ;
        RECT  174.528 0 174.552 0.084 ;
    END
  END b1[193]
  PIN b1[194]
    DIRECTION INPUT ;
    USE SIGNAL ;
    PORT
      LAYER M5 ;
        RECT  174.672 0 174.696 0.084 ;
    END
  END b1[194]
  PIN b1[195]
    DIRECTION INPUT ;
    USE SIGNAL ;
    PORT
      LAYER M5 ;
        RECT  174.816 0 174.84 0.084 ;
    END
  END b1[195]
  PIN b1[196]
    DIRECTION INPUT ;
    USE SIGNAL ;
    PORT
      LAYER M5 ;
        RECT  174.96 0 174.984 0.084 ;
    END
  END b1[196]
  PIN b1[197]
    DIRECTION INPUT ;
    USE SIGNAL ;
    PORT
      LAYER M5 ;
        RECT  175.104 0 175.128 0.084 ;
    END
  END b1[197]
  PIN b1[198]
    DIRECTION INPUT ;
    USE SIGNAL ;
    PORT
      LAYER M5 ;
        RECT  175.248 0 175.272 0.084 ;
    END
  END b1[198]
  PIN b1[199]
    DIRECTION INPUT ;
    USE SIGNAL ;
    PORT
      LAYER M5 ;
        RECT  175.392 0 175.416 0.084 ;
    END
  END b1[199]
  PIN b1[19]
    DIRECTION INPUT ;
    USE SIGNAL ;
    PORT
      LAYER M5 ;
        RECT  171.36 0 171.384 0.084 ;
    END
  END b1[19]
  PIN b1[1]
    DIRECTION INPUT ;
    USE SIGNAL ;
    PORT
      LAYER M5 ;
        RECT  168.768 0 168.792 0.084 ;
    END
  END b1[1]
  PIN b1[200]
    DIRECTION INPUT ;
    USE SIGNAL ;
    PORT
      LAYER M5 ;
        RECT  175.536 0 175.56 0.084 ;
    END
  END b1[200]
  PIN b1[201]
    DIRECTION INPUT ;
    USE SIGNAL ;
    PORT
      LAYER M5 ;
        RECT  175.68 0 175.704 0.084 ;
    END
  END b1[201]
  PIN b1[202]
    DIRECTION INPUT ;
    USE SIGNAL ;
    PORT
      LAYER M5 ;
        RECT  175.824 0 175.848 0.084 ;
    END
  END b1[202]
  PIN b1[203]
    DIRECTION INPUT ;
    USE SIGNAL ;
    PORT
      LAYER M5 ;
        RECT  175.968 0 175.992 0.084 ;
    END
  END b1[203]
  PIN b1[204]
    DIRECTION INPUT ;
    USE SIGNAL ;
    PORT
      LAYER M5 ;
        RECT  176.112 0 176.136 0.084 ;
    END
  END b1[204]
  PIN b1[205]
    DIRECTION INPUT ;
    USE SIGNAL ;
    PORT
      LAYER M5 ;
        RECT  176.256 0 176.28 0.084 ;
    END
  END b1[205]
  PIN b1[206]
    DIRECTION INPUT ;
    USE SIGNAL ;
    PORT
      LAYER M5 ;
        RECT  176.4 0 176.424 0.084 ;
    END
  END b1[206]
  PIN b1[207]
    DIRECTION INPUT ;
    USE SIGNAL ;
    PORT
      LAYER M5 ;
        RECT  176.544 0 176.568 0.084 ;
    END
  END b1[207]
  PIN b1[208]
    DIRECTION INPUT ;
    USE SIGNAL ;
    PORT
      LAYER M5 ;
        RECT  176.688 0 176.712 0.084 ;
    END
  END b1[208]
  PIN b1[209]
    DIRECTION INPUT ;
    USE SIGNAL ;
    PORT
      LAYER M5 ;
        RECT  176.832 0 176.856 0.084 ;
    END
  END b1[209]
  PIN b1[20]
    DIRECTION INPUT ;
    USE SIGNAL ;
    PORT
      LAYER M5 ;
        RECT  171.504 0 171.528 0.084 ;
    END
  END b1[20]
  PIN b1[210]
    DIRECTION INPUT ;
    USE SIGNAL ;
    PORT
      LAYER M5 ;
        RECT  176.976 0 177 0.084 ;
    END
  END b1[210]
  PIN b1[211]
    DIRECTION INPUT ;
    USE SIGNAL ;
    PORT
      LAYER M5 ;
        RECT  177.12 0 177.144 0.084 ;
    END
  END b1[211]
  PIN b1[212]
    DIRECTION INPUT ;
    USE SIGNAL ;
    PORT
      LAYER M5 ;
        RECT  177.264 0 177.288 0.084 ;
    END
  END b1[212]
  PIN b1[213]
    DIRECTION INPUT ;
    USE SIGNAL ;
    PORT
      LAYER M5 ;
        RECT  177.408 0 177.432 0.084 ;
    END
  END b1[213]
  PIN b1[214]
    DIRECTION INPUT ;
    USE SIGNAL ;
    PORT
      LAYER M5 ;
        RECT  177.552 0 177.576 0.084 ;
    END
  END b1[214]
  PIN b1[215]
    DIRECTION INPUT ;
    USE SIGNAL ;
    PORT
      LAYER M5 ;
        RECT  177.696 0 177.72 0.084 ;
    END
  END b1[215]
  PIN b1[216]
    DIRECTION INPUT ;
    USE SIGNAL ;
    PORT
      LAYER M5 ;
        RECT  177.84 0 177.864 0.084 ;
    END
  END b1[216]
  PIN b1[217]
    DIRECTION INPUT ;
    USE SIGNAL ;
    PORT
      LAYER M5 ;
        RECT  177.984 0 178.008 0.084 ;
    END
  END b1[217]
  PIN b1[218]
    DIRECTION INPUT ;
    USE SIGNAL ;
    PORT
      LAYER M5 ;
        RECT  23.76 0 23.784 0.084 ;
    END
  END b1[218]
  PIN b1[219]
    DIRECTION INPUT ;
    USE SIGNAL ;
    PORT
      LAYER M5 ;
        RECT  23.904 0 23.928 0.084 ;
    END
  END b1[219]
  PIN b1[21]
    DIRECTION INPUT ;
    USE SIGNAL ;
    PORT
      LAYER M5 ;
        RECT  171.648 0 171.672 0.084 ;
    END
  END b1[21]
  PIN b1[220]
    DIRECTION INPUT ;
    USE SIGNAL ;
    PORT
      LAYER M5 ;
        RECT  24.048 0 24.072 0.084 ;
    END
  END b1[220]
  PIN b1[221]
    DIRECTION INPUT ;
    USE SIGNAL ;
    PORT
      LAYER M5 ;
        RECT  24.192 0 24.216 0.084 ;
    END
  END b1[221]
  PIN b1[222]
    DIRECTION INPUT ;
    USE SIGNAL ;
    PORT
      LAYER M5 ;
        RECT  24.336 0 24.36 0.084 ;
    END
  END b1[222]
  PIN b1[223]
    DIRECTION INPUT ;
    USE SIGNAL ;
    PORT
      LAYER M5 ;
        RECT  24.48 0 24.504 0.084 ;
    END
  END b1[223]
  PIN b1[224]
    DIRECTION INPUT ;
    USE SIGNAL ;
    PORT
      LAYER M5 ;
        RECT  24.624 0 24.648 0.084 ;
    END
  END b1[224]
  PIN b1[225]
    DIRECTION INPUT ;
    USE SIGNAL ;
    PORT
      LAYER M5 ;
        RECT  24.768 0 24.792 0.084 ;
    END
  END b1[225]
  PIN b1[226]
    DIRECTION INPUT ;
    USE SIGNAL ;
    PORT
      LAYER M5 ;
        RECT  24.912 0 24.936 0.084 ;
    END
  END b1[226]
  PIN b1[227]
    DIRECTION INPUT ;
    USE SIGNAL ;
    PORT
      LAYER M5 ;
        RECT  25.056 0 25.08 0.084 ;
    END
  END b1[227]
  PIN b1[228]
    DIRECTION INPUT ;
    USE SIGNAL ;
    PORT
      LAYER M5 ;
        RECT  25.2 0 25.224 0.084 ;
    END
  END b1[228]
  PIN b1[229]
    DIRECTION INPUT ;
    USE SIGNAL ;
    PORT
      LAYER M5 ;
        RECT  25.344 0 25.368 0.084 ;
    END
  END b1[229]
  PIN b1[22]
    DIRECTION INPUT ;
    USE SIGNAL ;
    PORT
      LAYER M5 ;
        RECT  171.792 0 171.816 0.084 ;
    END
  END b1[22]
  PIN b1[230]
    DIRECTION INPUT ;
    USE SIGNAL ;
    PORT
      LAYER M5 ;
        RECT  25.488 0 25.512 0.084 ;
    END
  END b1[230]
  PIN b1[231]
    DIRECTION INPUT ;
    USE SIGNAL ;
    PORT
      LAYER M5 ;
        RECT  25.632 0 25.656 0.084 ;
    END
  END b1[231]
  PIN b1[232]
    DIRECTION INPUT ;
    USE SIGNAL ;
    PORT
      LAYER M5 ;
        RECT  25.776 0 25.8 0.084 ;
    END
  END b1[232]
  PIN b1[233]
    DIRECTION INPUT ;
    USE SIGNAL ;
    PORT
      LAYER M5 ;
        RECT  25.92 0 25.944 0.084 ;
    END
  END b1[233]
  PIN b1[234]
    DIRECTION INPUT ;
    USE SIGNAL ;
    PORT
      LAYER M5 ;
        RECT  26.064 0 26.088 0.084 ;
    END
  END b1[234]
  PIN b1[235]
    DIRECTION INPUT ;
    USE SIGNAL ;
    PORT
      LAYER M5 ;
        RECT  26.208 0 26.232 0.084 ;
    END
  END b1[235]
  PIN b1[236]
    DIRECTION INPUT ;
    USE SIGNAL ;
    PORT
      LAYER M5 ;
        RECT  26.352 0 26.376 0.084 ;
    END
  END b1[236]
  PIN b1[237]
    DIRECTION INPUT ;
    USE SIGNAL ;
    PORT
      LAYER M5 ;
        RECT  26.496 0 26.52 0.084 ;
    END
  END b1[237]
  PIN b1[238]
    DIRECTION INPUT ;
    USE SIGNAL ;
    PORT
      LAYER M5 ;
        RECT  26.64 0 26.664 0.084 ;
    END
  END b1[238]
  PIN b1[239]
    DIRECTION INPUT ;
    USE SIGNAL ;
    PORT
      LAYER M5 ;
        RECT  26.784 0 26.808 0.084 ;
    END
  END b1[239]
  PIN b1[23]
    DIRECTION INPUT ;
    USE SIGNAL ;
    PORT
      LAYER M5 ;
        RECT  171.936 0 171.96 0.084 ;
    END
  END b1[23]
  PIN b1[240]
    DIRECTION INPUT ;
    USE SIGNAL ;
    PORT
      LAYER M5 ;
        RECT  26.928 0 26.952 0.084 ;
    END
  END b1[240]
  PIN b1[241]
    DIRECTION INPUT ;
    USE SIGNAL ;
    PORT
      LAYER M5 ;
        RECT  27.072 0 27.096 0.084 ;
    END
  END b1[241]
  PIN b1[242]
    DIRECTION INPUT ;
    USE SIGNAL ;
    PORT
      LAYER M5 ;
        RECT  27.216 0 27.24 0.084 ;
    END
  END b1[242]
  PIN b1[243]
    DIRECTION INPUT ;
    USE SIGNAL ;
    PORT
      LAYER M5 ;
        RECT  27.36 0 27.384 0.084 ;
    END
  END b1[243]
  PIN b1[244]
    DIRECTION INPUT ;
    USE SIGNAL ;
    PORT
      LAYER M5 ;
        RECT  27.504 0 27.528 0.084 ;
    END
  END b1[244]
  PIN b1[245]
    DIRECTION INPUT ;
    USE SIGNAL ;
    PORT
      LAYER M5 ;
        RECT  27.648 0 27.672 0.084 ;
    END
  END b1[245]
  PIN b1[246]
    DIRECTION INPUT ;
    USE SIGNAL ;
    PORT
      LAYER M5 ;
        RECT  27.792 0 27.816 0.084 ;
    END
  END b1[246]
  PIN b1[247]
    DIRECTION INPUT ;
    USE SIGNAL ;
    PORT
      LAYER M5 ;
        RECT  27.936 0 27.96 0.084 ;
    END
  END b1[247]
  PIN b1[248]
    DIRECTION INPUT ;
    USE SIGNAL ;
    PORT
      LAYER M5 ;
        RECT  28.08 0 28.104 0.084 ;
    END
  END b1[248]
  PIN b1[249]
    DIRECTION INPUT ;
    USE SIGNAL ;
    PORT
      LAYER M5 ;
        RECT  28.224 0 28.248 0.084 ;
    END
  END b1[249]
  PIN b1[24]
    DIRECTION INPUT ;
    USE SIGNAL ;
    PORT
      LAYER M5 ;
        RECT  172.08 0 172.104 0.084 ;
    END
  END b1[24]
  PIN b1[250]
    DIRECTION INPUT ;
    USE SIGNAL ;
    PORT
      LAYER M5 ;
        RECT  85.968 0 85.992 0.084 ;
    END
  END b1[250]
  PIN b1[251]
    DIRECTION INPUT ;
    USE SIGNAL ;
    PORT
      LAYER M5 ;
        RECT  86.112 0 86.136 0.084 ;
    END
  END b1[251]
  PIN b1[252]
    DIRECTION INPUT ;
    USE SIGNAL ;
    PORT
      LAYER M5 ;
        RECT  86.256 0 86.28 0.084 ;
    END
  END b1[252]
  PIN b1[253]
    DIRECTION INPUT ;
    USE SIGNAL ;
    PORT
      LAYER M5 ;
        RECT  86.4 0 86.424 0.084 ;
    END
  END b1[253]
  PIN b1[254]
    DIRECTION INPUT ;
    USE SIGNAL ;
    PORT
      LAYER M5 ;
        RECT  86.544 0 86.568 0.084 ;
    END
  END b1[254]
  PIN b1[255]
    DIRECTION INPUT ;
    USE SIGNAL ;
    PORT
      LAYER M5 ;
        RECT  86.688 0 86.712 0.084 ;
    END
  END b1[255]
  PIN b1[256]
    DIRECTION INPUT ;
    USE SIGNAL ;
    PORT
      LAYER M5 ;
        RECT  86.832 0 86.856 0.084 ;
    END
  END b1[256]
  PIN b1[257]
    DIRECTION INPUT ;
    USE SIGNAL ;
    PORT
      LAYER M5 ;
        RECT  86.976 0 87 0.084 ;
    END
  END b1[257]
  PIN b1[25]
    DIRECTION INPUT ;
    USE SIGNAL ;
    PORT
      LAYER M5 ;
        RECT  172.224 0 172.248 0.084 ;
    END
  END b1[25]
  PIN b1[26]
    DIRECTION INPUT ;
    USE SIGNAL ;
    PORT
      LAYER M5 ;
        RECT  153.936 0 153.96 0.084 ;
    END
  END b1[26]
  PIN b1[27]
    DIRECTION INPUT ;
    USE SIGNAL ;
    PORT
      LAYER M5 ;
        RECT  154.08 0 154.104 0.084 ;
    END
  END b1[27]
  PIN b1[28]
    DIRECTION INPUT ;
    USE SIGNAL ;
    PORT
      LAYER M5 ;
        RECT  154.224 0 154.248 0.084 ;
    END
  END b1[28]
  PIN b1[29]
    DIRECTION INPUT ;
    USE SIGNAL ;
    PORT
      LAYER M5 ;
        RECT  154.368 0 154.392 0.084 ;
    END
  END b1[29]
  PIN b1[2]
    DIRECTION INPUT ;
    USE SIGNAL ;
    PORT
      LAYER M5 ;
        RECT  168.912 0 168.936 0.084 ;
    END
  END b1[2]
  PIN b1[30]
    DIRECTION INPUT ;
    USE SIGNAL ;
    PORT
      LAYER M5 ;
        RECT  154.512 0 154.536 0.084 ;
    END
  END b1[30]
  PIN b1[31]
    DIRECTION INPUT ;
    USE SIGNAL ;
    PORT
      LAYER M5 ;
        RECT  154.656 0 154.68 0.084 ;
    END
  END b1[31]
  PIN b1[32]
    DIRECTION INPUT ;
    USE SIGNAL ;
    PORT
      LAYER M5 ;
        RECT  154.8 0 154.824 0.084 ;
    END
  END b1[32]
  PIN b1[33]
    DIRECTION INPUT ;
    USE SIGNAL ;
    PORT
      LAYER M5 ;
        RECT  154.944 0 154.968 0.084 ;
    END
  END b1[33]
  PIN b1[34]
    DIRECTION INPUT ;
    USE SIGNAL ;
    PORT
      LAYER M5 ;
        RECT  155.088 0 155.112 0.084 ;
    END
  END b1[34]
  PIN b1[35]
    DIRECTION INPUT ;
    USE SIGNAL ;
    PORT
      LAYER M5 ;
        RECT  155.232 0 155.256 0.084 ;
    END
  END b1[35]
  PIN b1[36]
    DIRECTION INPUT ;
    USE SIGNAL ;
    PORT
      LAYER M5 ;
        RECT  155.376 0 155.4 0.084 ;
    END
  END b1[36]
  PIN b1[37]
    DIRECTION INPUT ;
    USE SIGNAL ;
    PORT
      LAYER M5 ;
        RECT  155.52 0 155.544 0.084 ;
    END
  END b1[37]
  PIN b1[38]
    DIRECTION INPUT ;
    USE SIGNAL ;
    PORT
      LAYER M5 ;
        RECT  155.664 0 155.688 0.084 ;
    END
  END b1[38]
  PIN b1[39]
    DIRECTION INPUT ;
    USE SIGNAL ;
    PORT
      LAYER M5 ;
        RECT  155.808 0 155.832 0.084 ;
    END
  END b1[39]
  PIN b1[3]
    DIRECTION INPUT ;
    USE SIGNAL ;
    PORT
      LAYER M5 ;
        RECT  169.056 0 169.08 0.084 ;
    END
  END b1[3]
  PIN b1[40]
    DIRECTION INPUT ;
    USE SIGNAL ;
    PORT
      LAYER M5 ;
        RECT  155.952 0 155.976 0.084 ;
    END
  END b1[40]
  PIN b1[41]
    DIRECTION INPUT ;
    USE SIGNAL ;
    PORT
      LAYER M5 ;
        RECT  156.096 0 156.12 0.084 ;
    END
  END b1[41]
  PIN b1[42]
    DIRECTION INPUT ;
    USE SIGNAL ;
    PORT
      LAYER M5 ;
        RECT  156.24 0 156.264 0.084 ;
    END
  END b1[42]
  PIN b1[43]
    DIRECTION INPUT ;
    USE SIGNAL ;
    PORT
      LAYER M5 ;
        RECT  156.384 0 156.408 0.084 ;
    END
  END b1[43]
  PIN b1[44]
    DIRECTION INPUT ;
    USE SIGNAL ;
    PORT
      LAYER M5 ;
        RECT  156.528 0 156.552 0.084 ;
    END
  END b1[44]
  PIN b1[45]
    DIRECTION INPUT ;
    USE SIGNAL ;
    PORT
      LAYER M5 ;
        RECT  156.672 0 156.696 0.084 ;
    END
  END b1[45]
  PIN b1[46]
    DIRECTION INPUT ;
    USE SIGNAL ;
    PORT
      LAYER M5 ;
        RECT  156.816 0 156.84 0.084 ;
    END
  END b1[46]
  PIN b1[47]
    DIRECTION INPUT ;
    USE SIGNAL ;
    PORT
      LAYER M5 ;
        RECT  156.96 0 156.984 0.084 ;
    END
  END b1[47]
  PIN b1[48]
    DIRECTION INPUT ;
    USE SIGNAL ;
    PORT
      LAYER M5 ;
        RECT  157.104 0 157.128 0.084 ;
    END
  END b1[48]
  PIN b1[49]
    DIRECTION INPUT ;
    USE SIGNAL ;
    PORT
      LAYER M5 ;
        RECT  157.248 0 157.272 0.084 ;
    END
  END b1[49]
  PIN b1[4]
    DIRECTION INPUT ;
    USE SIGNAL ;
    PORT
      LAYER M5 ;
        RECT  169.2 0 169.224 0.084 ;
    END
  END b1[4]
  PIN b1[50]
    DIRECTION INPUT ;
    USE SIGNAL ;
    PORT
      LAYER M5 ;
        RECT  157.392 0 157.416 0.084 ;
    END
  END b1[50]
  PIN b1[51]
    DIRECTION INPUT ;
    USE SIGNAL ;
    PORT
      LAYER M5 ;
        RECT  157.536 0 157.56 0.084 ;
    END
  END b1[51]
  PIN b1[52]
    DIRECTION INPUT ;
    USE SIGNAL ;
    PORT
      LAYER M5 ;
        RECT  157.68 0 157.704 0.084 ;
    END
  END b1[52]
  PIN b1[53]
    DIRECTION INPUT ;
    USE SIGNAL ;
    PORT
      LAYER M5 ;
        RECT  157.824 0 157.848 0.084 ;
    END
  END b1[53]
  PIN b1[54]
    DIRECTION INPUT ;
    USE SIGNAL ;
    PORT
      LAYER M5 ;
        RECT  157.968 0 157.992 0.084 ;
    END
  END b1[54]
  PIN b1[55]
    DIRECTION INPUT ;
    USE SIGNAL ;
    PORT
      LAYER M5 ;
        RECT  158.112 0 158.136 0.084 ;
    END
  END b1[55]
  PIN b1[56]
    DIRECTION INPUT ;
    USE SIGNAL ;
    PORT
      LAYER M5 ;
        RECT  158.256 0 158.28 0.084 ;
    END
  END b1[56]
  PIN b1[57]
    DIRECTION INPUT ;
    USE SIGNAL ;
    PORT
      LAYER M5 ;
        RECT  158.4 0 158.424 0.084 ;
    END
  END b1[57]
  PIN b1[58]
    DIRECTION INPUT ;
    USE SIGNAL ;
    PORT
      LAYER M5 ;
        RECT  144.72 0 144.744 0.084 ;
    END
  END b1[58]
  PIN b1[59]
    DIRECTION INPUT ;
    USE SIGNAL ;
    PORT
      LAYER M5 ;
        RECT  144.864 0 144.888 0.084 ;
    END
  END b1[59]
  PIN b1[5]
    DIRECTION INPUT ;
    USE SIGNAL ;
    PORT
      LAYER M5 ;
        RECT  169.344 0 169.368 0.084 ;
    END
  END b1[5]
  PIN b1[60]
    DIRECTION INPUT ;
    USE SIGNAL ;
    PORT
      LAYER M5 ;
        RECT  145.008 0 145.032 0.084 ;
    END
  END b1[60]
  PIN b1[61]
    DIRECTION INPUT ;
    USE SIGNAL ;
    PORT
      LAYER M5 ;
        RECT  145.152 0 145.176 0.084 ;
    END
  END b1[61]
  PIN b1[62]
    DIRECTION INPUT ;
    USE SIGNAL ;
    PORT
      LAYER M5 ;
        RECT  145.296 0 145.32 0.084 ;
    END
  END b1[62]
  PIN b1[63]
    DIRECTION INPUT ;
    USE SIGNAL ;
    PORT
      LAYER M5 ;
        RECT  145.44 0 145.464 0.084 ;
    END
  END b1[63]
  PIN b1[64]
    DIRECTION INPUT ;
    USE SIGNAL ;
    PORT
      LAYER M5 ;
        RECT  145.584 0 145.608 0.084 ;
    END
  END b1[64]
  PIN b1[65]
    DIRECTION INPUT ;
    USE SIGNAL ;
    PORT
      LAYER M5 ;
        RECT  145.728 0 145.752 0.084 ;
    END
  END b1[65]
  PIN b1[66]
    DIRECTION INPUT ;
    USE SIGNAL ;
    PORT
      LAYER M5 ;
        RECT  145.872 0 145.896 0.084 ;
    END
  END b1[66]
  PIN b1[67]
    DIRECTION INPUT ;
    USE SIGNAL ;
    PORT
      LAYER M5 ;
        RECT  146.016 0 146.04 0.084 ;
    END
  END b1[67]
  PIN b1[68]
    DIRECTION INPUT ;
    USE SIGNAL ;
    PORT
      LAYER M5 ;
        RECT  146.16 0 146.184 0.084 ;
    END
  END b1[68]
  PIN b1[69]
    DIRECTION INPUT ;
    USE SIGNAL ;
    PORT
      LAYER M5 ;
        RECT  146.304 0 146.328 0.084 ;
    END
  END b1[69]
  PIN b1[6]
    DIRECTION INPUT ;
    USE SIGNAL ;
    PORT
      LAYER M5 ;
        RECT  169.488 0 169.512 0.084 ;
    END
  END b1[6]
  PIN b1[70]
    DIRECTION INPUT ;
    USE SIGNAL ;
    PORT
      LAYER M5 ;
        RECT  146.448 0 146.472 0.084 ;
    END
  END b1[70]
  PIN b1[71]
    DIRECTION INPUT ;
    USE SIGNAL ;
    PORT
      LAYER M5 ;
        RECT  146.592 0 146.616 0.084 ;
    END
  END b1[71]
  PIN b1[72]
    DIRECTION INPUT ;
    USE SIGNAL ;
    PORT
      LAYER M5 ;
        RECT  146.736 0 146.76 0.084 ;
    END
  END b1[72]
  PIN b1[73]
    DIRECTION INPUT ;
    USE SIGNAL ;
    PORT
      LAYER M5 ;
        RECT  146.88 0 146.904 0.084 ;
    END
  END b1[73]
  PIN b1[74]
    DIRECTION INPUT ;
    USE SIGNAL ;
    PORT
      LAYER M5 ;
        RECT  147.024 0 147.048 0.084 ;
    END
  END b1[74]
  PIN b1[75]
    DIRECTION INPUT ;
    USE SIGNAL ;
    PORT
      LAYER M5 ;
        RECT  147.168 0 147.192 0.084 ;
    END
  END b1[75]
  PIN b1[76]
    DIRECTION INPUT ;
    USE SIGNAL ;
    PORT
      LAYER M5 ;
        RECT  147.312 0 147.336 0.084 ;
    END
  END b1[76]
  PIN b1[77]
    DIRECTION INPUT ;
    USE SIGNAL ;
    PORT
      LAYER M5 ;
        RECT  147.456 0 147.48 0.084 ;
    END
  END b1[77]
  PIN b1[78]
    DIRECTION INPUT ;
    USE SIGNAL ;
    PORT
      LAYER M5 ;
        RECT  147.6 0 147.624 0.084 ;
    END
  END b1[78]
  PIN b1[79]
    DIRECTION INPUT ;
    USE SIGNAL ;
    PORT
      LAYER M5 ;
        RECT  147.744 0 147.768 0.084 ;
    END
  END b1[79]
  PIN b1[7]
    DIRECTION INPUT ;
    USE SIGNAL ;
    PORT
      LAYER M5 ;
        RECT  169.632 0 169.656 0.084 ;
    END
  END b1[7]
  PIN b1[80]
    DIRECTION INPUT ;
    USE SIGNAL ;
    PORT
      LAYER M5 ;
        RECT  147.888 0 147.912 0.084 ;
    END
  END b1[80]
  PIN b1[81]
    DIRECTION INPUT ;
    USE SIGNAL ;
    PORT
      LAYER M5 ;
        RECT  148.032 0 148.056 0.084 ;
    END
  END b1[81]
  PIN b1[82]
    DIRECTION INPUT ;
    USE SIGNAL ;
    PORT
      LAYER M5 ;
        RECT  148.176 0 148.2 0.084 ;
    END
  END b1[82]
  PIN b1[83]
    DIRECTION INPUT ;
    USE SIGNAL ;
    PORT
      LAYER M5 ;
        RECT  148.32 0 148.344 0.084 ;
    END
  END b1[83]
  PIN b1[84]
    DIRECTION INPUT ;
    USE SIGNAL ;
    PORT
      LAYER M5 ;
        RECT  148.464 0 148.488 0.084 ;
    END
  END b1[84]
  PIN b1[85]
    DIRECTION INPUT ;
    USE SIGNAL ;
    PORT
      LAYER M5 ;
        RECT  148.608 0 148.632 0.084 ;
    END
  END b1[85]
  PIN b1[86]
    DIRECTION INPUT ;
    USE SIGNAL ;
    PORT
      LAYER M5 ;
        RECT  148.752 0 148.776 0.084 ;
    END
  END b1[86]
  PIN b1[87]
    DIRECTION INPUT ;
    USE SIGNAL ;
    PORT
      LAYER M5 ;
        RECT  148.896 0 148.92 0.084 ;
    END
  END b1[87]
  PIN b1[88]
    DIRECTION INPUT ;
    USE SIGNAL ;
    PORT
      LAYER M5 ;
        RECT  149.04 0 149.064 0.084 ;
    END
  END b1[88]
  PIN b1[89]
    DIRECTION INPUT ;
    USE SIGNAL ;
    PORT
      LAYER M5 ;
        RECT  149.184 0 149.208 0.084 ;
    END
  END b1[89]
  PIN b1[8]
    DIRECTION INPUT ;
    USE SIGNAL ;
    PORT
      LAYER M5 ;
        RECT  169.776 0 169.8 0.084 ;
    END
  END b1[8]
  PIN b1[90]
    DIRECTION INPUT ;
    USE SIGNAL ;
    PORT
      LAYER M5 ;
        RECT  163.152 0 163.176 0.084 ;
    END
  END b1[90]
  PIN b1[91]
    DIRECTION INPUT ;
    USE SIGNAL ;
    PORT
      LAYER M5 ;
        RECT  163.296 0 163.32 0.084 ;
    END
  END b1[91]
  PIN b1[92]
    DIRECTION INPUT ;
    USE SIGNAL ;
    PORT
      LAYER M5 ;
        RECT  163.44 0 163.464 0.084 ;
    END
  END b1[92]
  PIN b1[93]
    DIRECTION INPUT ;
    USE SIGNAL ;
    PORT
      LAYER M5 ;
        RECT  163.584 0 163.608 0.084 ;
    END
  END b1[93]
  PIN b1[94]
    DIRECTION INPUT ;
    USE SIGNAL ;
    PORT
      LAYER M5 ;
        RECT  163.728 0 163.752 0.084 ;
    END
  END b1[94]
  PIN b1[95]
    DIRECTION INPUT ;
    USE SIGNAL ;
    PORT
      LAYER M5 ;
        RECT  163.872 0 163.896 0.084 ;
    END
  END b1[95]
  PIN b1[96]
    DIRECTION INPUT ;
    USE SIGNAL ;
    PORT
      LAYER M5 ;
        RECT  164.016 0 164.04 0.084 ;
    END
  END b1[96]
  PIN b1[97]
    DIRECTION INPUT ;
    USE SIGNAL ;
    PORT
      LAYER M5 ;
        RECT  164.16 0 164.184 0.084 ;
    END
  END b1[97]
  PIN b1[98]
    DIRECTION INPUT ;
    USE SIGNAL ;
    PORT
      LAYER M5 ;
        RECT  164.304 0 164.328 0.084 ;
    END
  END b1[98]
  PIN b1[99]
    DIRECTION INPUT ;
    USE SIGNAL ;
    PORT
      LAYER M5 ;
        RECT  164.448 0 164.472 0.084 ;
    END
  END b1[99]
  PIN b1[9]
    DIRECTION INPUT ;
    USE SIGNAL ;
    PORT
      LAYER M5 ;
        RECT  169.92 0 169.944 0.084 ;
    END
  END b1[9]
  PIN ck
    DIRECTION INPUT ;
    USE SIGNAL ;
    PORT
      LAYER M4 ;
        RECT  0 22.896 0.084 22.92 ;
    END
  END ck
  PIN ep[0]
    DIRECTION INPUT ;
    USE SIGNAL ;
    PORT
      LAYER M5 ;
        RECT  127.152 43.116 127.176 43.2 ;
    END
  END ep[0]
  PIN ep[10]
    DIRECTION INPUT ;
    USE SIGNAL ;
    PORT
      LAYER M5 ;
        RECT  128.592 43.116 128.616 43.2 ;
    END
  END ep[10]
  PIN ep[11]
    DIRECTION INPUT ;
    USE SIGNAL ;
    PORT
      LAYER M5 ;
        RECT  128.736 43.116 128.76 43.2 ;
    END
  END ep[11]
  PIN ep[12]
    DIRECTION INPUT ;
    USE SIGNAL ;
    PORT
      LAYER M5 ;
        RECT  128.88 43.116 128.904 43.2 ;
    END
  END ep[12]
  PIN ep[13]
    DIRECTION INPUT ;
    USE SIGNAL ;
    PORT
      LAYER M5 ;
        RECT  129.024 43.116 129.048 43.2 ;
    END
  END ep[13]
  PIN ep[14]
    DIRECTION INPUT ;
    USE SIGNAL ;
    PORT
      LAYER M5 ;
        RECT  129.168 43.116 129.192 43.2 ;
    END
  END ep[14]
  PIN ep[15]
    DIRECTION INPUT ;
    USE SIGNAL ;
    PORT
      LAYER M5 ;
        RECT  129.312 43.116 129.336 43.2 ;
    END
  END ep[15]
  PIN ep[1]
    DIRECTION INPUT ;
    USE SIGNAL ;
    PORT
      LAYER M5 ;
        RECT  127.296 43.116 127.32 43.2 ;
    END
  END ep[1]
  PIN ep[2]
    DIRECTION INPUT ;
    USE SIGNAL ;
    PORT
      LAYER M5 ;
        RECT  127.44 43.116 127.464 43.2 ;
    END
  END ep[2]
  PIN ep[3]
    DIRECTION INPUT ;
    USE SIGNAL ;
    PORT
      LAYER M5 ;
        RECT  127.584 43.116 127.608 43.2 ;
    END
  END ep[3]
  PIN ep[4]
    DIRECTION INPUT ;
    USE SIGNAL ;
    PORT
      LAYER M5 ;
        RECT  127.728 43.116 127.752 43.2 ;
    END
  END ep[4]
  PIN ep[5]
    DIRECTION INPUT ;
    USE SIGNAL ;
    PORT
      LAYER M5 ;
        RECT  127.872 43.116 127.896 43.2 ;
    END
  END ep[5]
  PIN ep[6]
    DIRECTION INPUT ;
    USE SIGNAL ;
    PORT
      LAYER M5 ;
        RECT  128.016 43.116 128.04 43.2 ;
    END
  END ep[6]
  PIN ep[7]
    DIRECTION INPUT ;
    USE SIGNAL ;
    PORT
      LAYER M5 ;
        RECT  128.16 43.116 128.184 43.2 ;
    END
  END ep[7]
  PIN ep[8]
    DIRECTION INPUT ;
    USE SIGNAL ;
    PORT
      LAYER M5 ;
        RECT  128.304 43.116 128.328 43.2 ;
    END
  END ep[8]
  PIN ep[9]
    DIRECTION INPUT ;
    USE SIGNAL ;
    PORT
      LAYER M5 ;
        RECT  128.448 43.116 128.472 43.2 ;
    END
  END ep[9]
  PIN o_beat[0]
    DIRECTION OUTPUT ;
    USE SIGNAL ;
    PORT
      LAYER M5 ;
        RECT  129.456 43.116 129.48 43.2 ;
    END
  END o_beat[0]
  PIN o_beat[1]
    DIRECTION OUTPUT ;
    USE SIGNAL ;
    PORT
      LAYER M5 ;
        RECT  129.6 43.116 129.624 43.2 ;
    END
  END o_beat[1]
  PIN o_beat[2]
    DIRECTION OUTPUT ;
    USE SIGNAL ;
    PORT
      LAYER M5 ;
        RECT  129.744 43.116 129.768 43.2 ;
    END
  END o_beat[2]
  PIN o_beat[3]
    DIRECTION OUTPUT ;
    USE SIGNAL ;
    PORT
      LAYER M5 ;
        RECT  129.888 43.116 129.912 43.2 ;
    END
  END o_beat[3]
  PIN o_beat[4]
    DIRECTION OUTPUT ;
    USE SIGNAL ;
    PORT
      LAYER M5 ;
        RECT  130.032 43.116 130.056 43.2 ;
    END
  END o_beat[4]
  PIN o_data[0]
    DIRECTION OUTPUT ;
    USE SIGNAL ;
    PORT
      LAYER M5 ;
        RECT  130.176 43.116 130.2 43.2 ;
    END
  END o_data[0]
  PIN o_data[100]
    DIRECTION OUTPUT ;
    USE SIGNAL ;
    PORT
      LAYER M5 ;
        RECT  78.912 43.116 78.936 43.2 ;
    END
  END o_data[100]
  PIN o_data[101]
    DIRECTION OUTPUT ;
    USE SIGNAL ;
    PORT
      LAYER M5 ;
        RECT  79.056 43.116 79.08 43.2 ;
    END
  END o_data[101]
  PIN o_data[102]
    DIRECTION OUTPUT ;
    USE SIGNAL ;
    PORT
      LAYER M5 ;
        RECT  79.2 43.116 79.224 43.2 ;
    END
  END o_data[102]
  PIN o_data[103]
    DIRECTION OUTPUT ;
    USE SIGNAL ;
    PORT
      LAYER M5 ;
        RECT  79.344 43.116 79.368 43.2 ;
    END
  END o_data[103]
  PIN o_data[104]
    DIRECTION OUTPUT ;
    USE SIGNAL ;
    PORT
      LAYER M5 ;
        RECT  79.488 43.116 79.512 43.2 ;
    END
  END o_data[104]
  PIN o_data[105]
    DIRECTION OUTPUT ;
    USE SIGNAL ;
    PORT
      LAYER M5 ;
        RECT  79.632 43.116 79.656 43.2 ;
    END
  END o_data[105]
  PIN o_data[106]
    DIRECTION OUTPUT ;
    USE SIGNAL ;
    PORT
      LAYER M5 ;
        RECT  79.776 43.116 79.8 43.2 ;
    END
  END o_data[106]
  PIN o_data[107]
    DIRECTION OUTPUT ;
    USE SIGNAL ;
    PORT
      LAYER M5 ;
        RECT  84.528 43.116 84.552 43.2 ;
    END
  END o_data[107]
  PIN o_data[108]
    DIRECTION OUTPUT ;
    USE SIGNAL ;
    PORT
      LAYER M5 ;
        RECT  84.672 43.116 84.696 43.2 ;
    END
  END o_data[108]
  PIN o_data[109]
    DIRECTION OUTPUT ;
    USE SIGNAL ;
    PORT
      LAYER M5 ;
        RECT  84.816 43.116 84.84 43.2 ;
    END
  END o_data[109]
  PIN o_data[10]
    DIRECTION OUTPUT ;
    USE SIGNAL ;
    PORT
      LAYER M5 ;
        RECT  131.616 43.116 131.64 43.2 ;
    END
  END o_data[10]
  PIN o_data[110]
    DIRECTION OUTPUT ;
    USE SIGNAL ;
    PORT
      LAYER M5 ;
        RECT  84.96 43.116 84.984 43.2 ;
    END
  END o_data[110]
  PIN o_data[111]
    DIRECTION OUTPUT ;
    USE SIGNAL ;
    PORT
      LAYER M5 ;
        RECT  85.104 43.116 85.128 43.2 ;
    END
  END o_data[111]
  PIN o_data[112]
    DIRECTION OUTPUT ;
    USE SIGNAL ;
    PORT
      LAYER M5 ;
        RECT  85.248 43.116 85.272 43.2 ;
    END
  END o_data[112]
  PIN o_data[113]
    DIRECTION OUTPUT ;
    USE SIGNAL ;
    PORT
      LAYER M5 ;
        RECT  85.392 43.116 85.416 43.2 ;
    END
  END o_data[113]
  PIN o_data[114]
    DIRECTION OUTPUT ;
    USE SIGNAL ;
    PORT
      LAYER M5 ;
        RECT  85.536 43.116 85.56 43.2 ;
    END
  END o_data[114]
  PIN o_data[115]
    DIRECTION OUTPUT ;
    USE SIGNAL ;
    PORT
      LAYER M5 ;
        RECT  85.68 43.116 85.704 43.2 ;
    END
  END o_data[115]
  PIN o_data[116]
    DIRECTION OUTPUT ;
    USE SIGNAL ;
    PORT
      LAYER M5 ;
        RECT  85.824 43.116 85.848 43.2 ;
    END
  END o_data[116]
  PIN o_data[117]
    DIRECTION OUTPUT ;
    USE SIGNAL ;
    PORT
      LAYER M5 ;
        RECT  85.968 43.116 85.992 43.2 ;
    END
  END o_data[117]
  PIN o_data[118]
    DIRECTION OUTPUT ;
    USE SIGNAL ;
    PORT
      LAYER M5 ;
        RECT  86.112 43.116 86.136 43.2 ;
    END
  END o_data[118]
  PIN o_data[119]
    DIRECTION OUTPUT ;
    USE SIGNAL ;
    PORT
      LAYER M5 ;
        RECT  86.256 43.116 86.28 43.2 ;
    END
  END o_data[119]
  PIN o_data[11]
    DIRECTION OUTPUT ;
    USE SIGNAL ;
    PORT
      LAYER M5 ;
        RECT  98.352 43.116 98.376 43.2 ;
    END
  END o_data[11]
  PIN o_data[120]
    DIRECTION OUTPUT ;
    USE SIGNAL ;
    PORT
      LAYER M5 ;
        RECT  86.4 43.116 86.424 43.2 ;
    END
  END o_data[120]
  PIN o_data[121]
    DIRECTION OUTPUT ;
    USE SIGNAL ;
    PORT
      LAYER M5 ;
        RECT  86.544 43.116 86.568 43.2 ;
    END
  END o_data[121]
  PIN o_data[122]
    DIRECTION OUTPUT ;
    USE SIGNAL ;
    PORT
      LAYER M5 ;
        RECT  86.688 43.116 86.712 43.2 ;
    END
  END o_data[122]
  PIN o_data[123]
    DIRECTION OUTPUT ;
    USE SIGNAL ;
    PORT
      LAYER M5 ;
        RECT  86.832 43.116 86.856 43.2 ;
    END
  END o_data[123]
  PIN o_data[124]
    DIRECTION OUTPUT ;
    USE SIGNAL ;
    PORT
      LAYER M5 ;
        RECT  86.976 43.116 87 43.2 ;
    END
  END o_data[124]
  PIN o_data[125]
    DIRECTION OUTPUT ;
    USE SIGNAL ;
    PORT
      LAYER M5 ;
        RECT  87.12 43.116 87.144 43.2 ;
    END
  END o_data[125]
  PIN o_data[126]
    DIRECTION OUTPUT ;
    USE SIGNAL ;
    PORT
      LAYER M5 ;
        RECT  87.264 43.116 87.288 43.2 ;
    END
  END o_data[126]
  PIN o_data[127]
    DIRECTION OUTPUT ;
    USE SIGNAL ;
    PORT
      LAYER M5 ;
        RECT  87.408 43.116 87.432 43.2 ;
    END
  END o_data[127]
  PIN o_data[128]
    DIRECTION OUTPUT ;
    USE SIGNAL ;
    PORT
      LAYER M5 ;
        RECT  87.552 43.116 87.576 43.2 ;
    END
  END o_data[128]
  PIN o_data[129]
    DIRECTION OUTPUT ;
    USE SIGNAL ;
    PORT
      LAYER M5 ;
        RECT  87.696 43.116 87.72 43.2 ;
    END
  END o_data[129]
  PIN o_data[12]
    DIRECTION OUTPUT ;
    USE SIGNAL ;
    PORT
      LAYER M5 ;
        RECT  98.496 43.116 98.52 43.2 ;
    END
  END o_data[12]
  PIN o_data[130]
    DIRECTION OUTPUT ;
    USE SIGNAL ;
    PORT
      LAYER M5 ;
        RECT  87.84 43.116 87.864 43.2 ;
    END
  END o_data[130]
  PIN o_data[131]
    DIRECTION OUTPUT ;
    USE SIGNAL ;
    PORT
      LAYER M5 ;
        RECT  87.984 43.116 88.008 43.2 ;
    END
  END o_data[131]
  PIN o_data[132]
    DIRECTION OUTPUT ;
    USE SIGNAL ;
    PORT
      LAYER M5 ;
        RECT  88.128 43.116 88.152 43.2 ;
    END
  END o_data[132]
  PIN o_data[133]
    DIRECTION OUTPUT ;
    USE SIGNAL ;
    PORT
      LAYER M5 ;
        RECT  88.272 43.116 88.296 43.2 ;
    END
  END o_data[133]
  PIN o_data[134]
    DIRECTION OUTPUT ;
    USE SIGNAL ;
    PORT
      LAYER M5 ;
        RECT  88.416 43.116 88.44 43.2 ;
    END
  END o_data[134]
  PIN o_data[135]
    DIRECTION OUTPUT ;
    USE SIGNAL ;
    PORT
      LAYER M5 ;
        RECT  88.56 43.116 88.584 43.2 ;
    END
  END o_data[135]
  PIN o_data[136]
    DIRECTION OUTPUT ;
    USE SIGNAL ;
    PORT
      LAYER M5 ;
        RECT  88.704 43.116 88.728 43.2 ;
    END
  END o_data[136]
  PIN o_data[137]
    DIRECTION OUTPUT ;
    USE SIGNAL ;
    PORT
      LAYER M5 ;
        RECT  88.848 43.116 88.872 43.2 ;
    END
  END o_data[137]
  PIN o_data[138]
    DIRECTION OUTPUT ;
    USE SIGNAL ;
    PORT
      LAYER M5 ;
        RECT  88.992 43.116 89.016 43.2 ;
    END
  END o_data[138]
  PIN o_data[139]
    DIRECTION OUTPUT ;
    USE SIGNAL ;
    PORT
      LAYER M5 ;
        RECT  93.744 43.116 93.768 43.2 ;
    END
  END o_data[139]
  PIN o_data[13]
    DIRECTION OUTPUT ;
    USE SIGNAL ;
    PORT
      LAYER M5 ;
        RECT  98.64 43.116 98.664 43.2 ;
    END
  END o_data[13]
  PIN o_data[140]
    DIRECTION OUTPUT ;
    USE SIGNAL ;
    PORT
      LAYER M5 ;
        RECT  93.888 43.116 93.912 43.2 ;
    END
  END o_data[140]
  PIN o_data[141]
    DIRECTION OUTPUT ;
    USE SIGNAL ;
    PORT
      LAYER M5 ;
        RECT  94.032 43.116 94.056 43.2 ;
    END
  END o_data[141]
  PIN o_data[142]
    DIRECTION OUTPUT ;
    USE SIGNAL ;
    PORT
      LAYER M5 ;
        RECT  94.176 43.116 94.2 43.2 ;
    END
  END o_data[142]
  PIN o_data[143]
    DIRECTION OUTPUT ;
    USE SIGNAL ;
    PORT
      LAYER M5 ;
        RECT  94.32 43.116 94.344 43.2 ;
    END
  END o_data[143]
  PIN o_data[144]
    DIRECTION OUTPUT ;
    USE SIGNAL ;
    PORT
      LAYER M5 ;
        RECT  94.464 43.116 94.488 43.2 ;
    END
  END o_data[144]
  PIN o_data[145]
    DIRECTION OUTPUT ;
    USE SIGNAL ;
    PORT
      LAYER M5 ;
        RECT  94.608 43.116 94.632 43.2 ;
    END
  END o_data[145]
  PIN o_data[146]
    DIRECTION OUTPUT ;
    USE SIGNAL ;
    PORT
      LAYER M5 ;
        RECT  94.752 43.116 94.776 43.2 ;
    END
  END o_data[146]
  PIN o_data[147]
    DIRECTION OUTPUT ;
    USE SIGNAL ;
    PORT
      LAYER M5 ;
        RECT  94.896 43.116 94.92 43.2 ;
    END
  END o_data[147]
  PIN o_data[148]
    DIRECTION OUTPUT ;
    USE SIGNAL ;
    PORT
      LAYER M5 ;
        RECT  95.04 43.116 95.064 43.2 ;
    END
  END o_data[148]
  PIN o_data[149]
    DIRECTION OUTPUT ;
    USE SIGNAL ;
    PORT
      LAYER M5 ;
        RECT  95.184 43.116 95.208 43.2 ;
    END
  END o_data[149]
  PIN o_data[14]
    DIRECTION OUTPUT ;
    USE SIGNAL ;
    PORT
      LAYER M5 ;
        RECT  98.784 43.116 98.808 43.2 ;
    END
  END o_data[14]
  PIN o_data[150]
    DIRECTION OUTPUT ;
    USE SIGNAL ;
    PORT
      LAYER M5 ;
        RECT  95.328 43.116 95.352 43.2 ;
    END
  END o_data[150]
  PIN o_data[151]
    DIRECTION OUTPUT ;
    USE SIGNAL ;
    PORT
      LAYER M5 ;
        RECT  95.472 43.116 95.496 43.2 ;
    END
  END o_data[151]
  PIN o_data[152]
    DIRECTION OUTPUT ;
    USE SIGNAL ;
    PORT
      LAYER M5 ;
        RECT  95.616 43.116 95.64 43.2 ;
    END
  END o_data[152]
  PIN o_data[153]
    DIRECTION OUTPUT ;
    USE SIGNAL ;
    PORT
      LAYER M5 ;
        RECT  95.76 43.116 95.784 43.2 ;
    END
  END o_data[153]
  PIN o_data[154]
    DIRECTION OUTPUT ;
    USE SIGNAL ;
    PORT
      LAYER M5 ;
        RECT  95.904 43.116 95.928 43.2 ;
    END
  END o_data[154]
  PIN o_data[155]
    DIRECTION OUTPUT ;
    USE SIGNAL ;
    PORT
      LAYER M5 ;
        RECT  96.048 43.116 96.072 43.2 ;
    END
  END o_data[155]
  PIN o_data[156]
    DIRECTION OUTPUT ;
    USE SIGNAL ;
    PORT
      LAYER M5 ;
        RECT  96.192 43.116 96.216 43.2 ;
    END
  END o_data[156]
  PIN o_data[157]
    DIRECTION OUTPUT ;
    USE SIGNAL ;
    PORT
      LAYER M5 ;
        RECT  96.336 43.116 96.36 43.2 ;
    END
  END o_data[157]
  PIN o_data[158]
    DIRECTION OUTPUT ;
    USE SIGNAL ;
    PORT
      LAYER M5 ;
        RECT  96.48 43.116 96.504 43.2 ;
    END
  END o_data[158]
  PIN o_data[159]
    DIRECTION OUTPUT ;
    USE SIGNAL ;
    PORT
      LAYER M5 ;
        RECT  96.624 43.116 96.648 43.2 ;
    END
  END o_data[159]
  PIN o_data[15]
    DIRECTION OUTPUT ;
    USE SIGNAL ;
    PORT
      LAYER M5 ;
        RECT  98.928 43.116 98.952 43.2 ;
    END
  END o_data[15]
  PIN o_data[160]
    DIRECTION OUTPUT ;
    USE SIGNAL ;
    PORT
      LAYER M5 ;
        RECT  96.768 43.116 96.792 43.2 ;
    END
  END o_data[160]
  PIN o_data[161]
    DIRECTION OUTPUT ;
    USE SIGNAL ;
    PORT
      LAYER M5 ;
        RECT  96.912 43.116 96.936 43.2 ;
    END
  END o_data[161]
  PIN o_data[162]
    DIRECTION OUTPUT ;
    USE SIGNAL ;
    PORT
      LAYER M5 ;
        RECT  97.056 43.116 97.08 43.2 ;
    END
  END o_data[162]
  PIN o_data[163]
    DIRECTION OUTPUT ;
    USE SIGNAL ;
    PORT
      LAYER M5 ;
        RECT  97.2 43.116 97.224 43.2 ;
    END
  END o_data[163]
  PIN o_data[164]
    DIRECTION OUTPUT ;
    USE SIGNAL ;
    PORT
      LAYER M5 ;
        RECT  97.344 43.116 97.368 43.2 ;
    END
  END o_data[164]
  PIN o_data[165]
    DIRECTION OUTPUT ;
    USE SIGNAL ;
    PORT
      LAYER M5 ;
        RECT  97.488 43.116 97.512 43.2 ;
    END
  END o_data[165]
  PIN o_data[166]
    DIRECTION OUTPUT ;
    USE SIGNAL ;
    PORT
      LAYER M5 ;
        RECT  97.632 43.116 97.656 43.2 ;
    END
  END o_data[166]
  PIN o_data[167]
    DIRECTION OUTPUT ;
    USE SIGNAL ;
    PORT
      LAYER M5 ;
        RECT  97.776 43.116 97.8 43.2 ;
    END
  END o_data[167]
  PIN o_data[168]
    DIRECTION OUTPUT ;
    USE SIGNAL ;
    PORT
      LAYER M5 ;
        RECT  97.92 43.116 97.944 43.2 ;
    END
  END o_data[168]
  PIN o_data[169]
    DIRECTION OUTPUT ;
    USE SIGNAL ;
    PORT
      LAYER M5 ;
        RECT  98.064 43.116 98.088 43.2 ;
    END
  END o_data[169]
  PIN o_data[16]
    DIRECTION OUTPUT ;
    USE SIGNAL ;
    PORT
      LAYER M5 ;
        RECT  99.072 43.116 99.096 43.2 ;
    END
  END o_data[16]
  PIN o_data[170]
    DIRECTION OUTPUT ;
    USE SIGNAL ;
    PORT
      LAYER M5 ;
        RECT  98.208 43.116 98.232 43.2 ;
    END
  END o_data[170]
  PIN o_data[171]
    DIRECTION OUTPUT ;
    USE SIGNAL ;
    PORT
      LAYER M5 ;
        RECT  79.92 43.116 79.944 43.2 ;
    END
  END o_data[171]
  PIN o_data[172]
    DIRECTION OUTPUT ;
    USE SIGNAL ;
    PORT
      LAYER M5 ;
        RECT  80.064 43.116 80.088 43.2 ;
    END
  END o_data[172]
  PIN o_data[173]
    DIRECTION OUTPUT ;
    USE SIGNAL ;
    PORT
      LAYER M5 ;
        RECT  80.208 43.116 80.232 43.2 ;
    END
  END o_data[173]
  PIN o_data[174]
    DIRECTION OUTPUT ;
    USE SIGNAL ;
    PORT
      LAYER M5 ;
        RECT  80.352 43.116 80.376 43.2 ;
    END
  END o_data[174]
  PIN o_data[175]
    DIRECTION OUTPUT ;
    USE SIGNAL ;
    PORT
      LAYER M5 ;
        RECT  80.496 43.116 80.52 43.2 ;
    END
  END o_data[175]
  PIN o_data[176]
    DIRECTION OUTPUT ;
    USE SIGNAL ;
    PORT
      LAYER M5 ;
        RECT  80.64 43.116 80.664 43.2 ;
    END
  END o_data[176]
  PIN o_data[177]
    DIRECTION OUTPUT ;
    USE SIGNAL ;
    PORT
      LAYER M5 ;
        RECT  80.784 43.116 80.808 43.2 ;
    END
  END o_data[177]
  PIN o_data[178]
    DIRECTION OUTPUT ;
    USE SIGNAL ;
    PORT
      LAYER M5 ;
        RECT  80.928 43.116 80.952 43.2 ;
    END
  END o_data[178]
  PIN o_data[179]
    DIRECTION OUTPUT ;
    USE SIGNAL ;
    PORT
      LAYER M5 ;
        RECT  81.072 43.116 81.096 43.2 ;
    END
  END o_data[179]
  PIN o_data[17]
    DIRECTION OUTPUT ;
    USE SIGNAL ;
    PORT
      LAYER M5 ;
        RECT  99.216 43.116 99.24 43.2 ;
    END
  END o_data[17]
  PIN o_data[180]
    DIRECTION OUTPUT ;
    USE SIGNAL ;
    PORT
      LAYER M5 ;
        RECT  81.216 43.116 81.24 43.2 ;
    END
  END o_data[180]
  PIN o_data[181]
    DIRECTION OUTPUT ;
    USE SIGNAL ;
    PORT
      LAYER M5 ;
        RECT  81.36 43.116 81.384 43.2 ;
    END
  END o_data[181]
  PIN o_data[182]
    DIRECTION OUTPUT ;
    USE SIGNAL ;
    PORT
      LAYER M5 ;
        RECT  81.504 43.116 81.528 43.2 ;
    END
  END o_data[182]
  PIN o_data[183]
    DIRECTION OUTPUT ;
    USE SIGNAL ;
    PORT
      LAYER M5 ;
        RECT  81.648 43.116 81.672 43.2 ;
    END
  END o_data[183]
  PIN o_data[184]
    DIRECTION OUTPUT ;
    USE SIGNAL ;
    PORT
      LAYER M5 ;
        RECT  81.792 43.116 81.816 43.2 ;
    END
  END o_data[184]
  PIN o_data[185]
    DIRECTION OUTPUT ;
    USE SIGNAL ;
    PORT
      LAYER M5 ;
        RECT  81.936 43.116 81.96 43.2 ;
    END
  END o_data[185]
  PIN o_data[186]
    DIRECTION OUTPUT ;
    USE SIGNAL ;
    PORT
      LAYER M5 ;
        RECT  82.08 43.116 82.104 43.2 ;
    END
  END o_data[186]
  PIN o_data[187]
    DIRECTION OUTPUT ;
    USE SIGNAL ;
    PORT
      LAYER M5 ;
        RECT  82.224 43.116 82.248 43.2 ;
    END
  END o_data[187]
  PIN o_data[188]
    DIRECTION OUTPUT ;
    USE SIGNAL ;
    PORT
      LAYER M5 ;
        RECT  82.368 43.116 82.392 43.2 ;
    END
  END o_data[188]
  PIN o_data[189]
    DIRECTION OUTPUT ;
    USE SIGNAL ;
    PORT
      LAYER M5 ;
        RECT  82.512 43.116 82.536 43.2 ;
    END
  END o_data[189]
  PIN o_data[18]
    DIRECTION OUTPUT ;
    USE SIGNAL ;
    PORT
      LAYER M5 ;
        RECT  99.36 43.116 99.384 43.2 ;
    END
  END o_data[18]
  PIN o_data[190]
    DIRECTION OUTPUT ;
    USE SIGNAL ;
    PORT
      LAYER M5 ;
        RECT  82.656 43.116 82.68 43.2 ;
    END
  END o_data[190]
  PIN o_data[191]
    DIRECTION OUTPUT ;
    USE SIGNAL ;
    PORT
      LAYER M5 ;
        RECT  82.8 43.116 82.824 43.2 ;
    END
  END o_data[191]
  PIN o_data[192]
    DIRECTION OUTPUT ;
    USE SIGNAL ;
    PORT
      LAYER M5 ;
        RECT  82.944 43.116 82.968 43.2 ;
    END
  END o_data[192]
  PIN o_data[193]
    DIRECTION OUTPUT ;
    USE SIGNAL ;
    PORT
      LAYER M5 ;
        RECT  83.088 43.116 83.112 43.2 ;
    END
  END o_data[193]
  PIN o_data[194]
    DIRECTION OUTPUT ;
    USE SIGNAL ;
    PORT
      LAYER M5 ;
        RECT  83.232 43.116 83.256 43.2 ;
    END
  END o_data[194]
  PIN o_data[195]
    DIRECTION OUTPUT ;
    USE SIGNAL ;
    PORT
      LAYER M5 ;
        RECT  83.376 43.116 83.4 43.2 ;
    END
  END o_data[195]
  PIN o_data[196]
    DIRECTION OUTPUT ;
    USE SIGNAL ;
    PORT
      LAYER M5 ;
        RECT  83.52 43.116 83.544 43.2 ;
    END
  END o_data[196]
  PIN o_data[197]
    DIRECTION OUTPUT ;
    USE SIGNAL ;
    PORT
      LAYER M5 ;
        RECT  83.664 43.116 83.688 43.2 ;
    END
  END o_data[197]
  PIN o_data[198]
    DIRECTION OUTPUT ;
    USE SIGNAL ;
    PORT
      LAYER M5 ;
        RECT  83.808 43.116 83.832 43.2 ;
    END
  END o_data[198]
  PIN o_data[199]
    DIRECTION OUTPUT ;
    USE SIGNAL ;
    PORT
      LAYER M5 ;
        RECT  83.952 43.116 83.976 43.2 ;
    END
  END o_data[199]
  PIN o_data[19]
    DIRECTION OUTPUT ;
    USE SIGNAL ;
    PORT
      LAYER M5 ;
        RECT  99.504 43.116 99.528 43.2 ;
    END
  END o_data[19]
  PIN o_data[1]
    DIRECTION OUTPUT ;
    USE SIGNAL ;
    PORT
      LAYER M5 ;
        RECT  130.32 43.116 130.344 43.2 ;
    END
  END o_data[1]
  PIN o_data[200]
    DIRECTION OUTPUT ;
    USE SIGNAL ;
    PORT
      LAYER M5 ;
        RECT  84.096 43.116 84.12 43.2 ;
    END
  END o_data[200]
  PIN o_data[201]
    DIRECTION OUTPUT ;
    USE SIGNAL ;
    PORT
      LAYER M5 ;
        RECT  84.24 43.116 84.264 43.2 ;
    END
  END o_data[201]
  PIN o_data[202]
    DIRECTION OUTPUT ;
    USE SIGNAL ;
    PORT
      LAYER M5 ;
        RECT  84.384 43.116 84.408 43.2 ;
    END
  END o_data[202]
  PIN o_data[203]
    DIRECTION OUTPUT ;
    USE SIGNAL ;
    PORT
      LAYER M5 ;
        RECT  122.544 43.116 122.568 43.2 ;
    END
  END o_data[203]
  PIN o_data[204]
    DIRECTION OUTPUT ;
    USE SIGNAL ;
    PORT
      LAYER M5 ;
        RECT  122.688 43.116 122.712 43.2 ;
    END
  END o_data[204]
  PIN o_data[205]
    DIRECTION OUTPUT ;
    USE SIGNAL ;
    PORT
      LAYER M5 ;
        RECT  122.832 43.116 122.856 43.2 ;
    END
  END o_data[205]
  PIN o_data[206]
    DIRECTION OUTPUT ;
    USE SIGNAL ;
    PORT
      LAYER M5 ;
        RECT  122.976 43.116 123 43.2 ;
    END
  END o_data[206]
  PIN o_data[207]
    DIRECTION OUTPUT ;
    USE SIGNAL ;
    PORT
      LAYER M5 ;
        RECT  123.12 43.116 123.144 43.2 ;
    END
  END o_data[207]
  PIN o_data[208]
    DIRECTION OUTPUT ;
    USE SIGNAL ;
    PORT
      LAYER M5 ;
        RECT  123.264 43.116 123.288 43.2 ;
    END
  END o_data[208]
  PIN o_data[209]
    DIRECTION OUTPUT ;
    USE SIGNAL ;
    PORT
      LAYER M5 ;
        RECT  123.408 43.116 123.432 43.2 ;
    END
  END o_data[209]
  PIN o_data[20]
    DIRECTION OUTPUT ;
    USE SIGNAL ;
    PORT
      LAYER M5 ;
        RECT  99.648 43.116 99.672 43.2 ;
    END
  END o_data[20]
  PIN o_data[210]
    DIRECTION OUTPUT ;
    USE SIGNAL ;
    PORT
      LAYER M5 ;
        RECT  123.552 43.116 123.576 43.2 ;
    END
  END o_data[210]
  PIN o_data[211]
    DIRECTION OUTPUT ;
    USE SIGNAL ;
    PORT
      LAYER M5 ;
        RECT  123.696 43.116 123.72 43.2 ;
    END
  END o_data[211]
  PIN o_data[212]
    DIRECTION OUTPUT ;
    USE SIGNAL ;
    PORT
      LAYER M5 ;
        RECT  123.84 43.116 123.864 43.2 ;
    END
  END o_data[212]
  PIN o_data[213]
    DIRECTION OUTPUT ;
    USE SIGNAL ;
    PORT
      LAYER M5 ;
        RECT  123.984 43.116 124.008 43.2 ;
    END
  END o_data[213]
  PIN o_data[214]
    DIRECTION OUTPUT ;
    USE SIGNAL ;
    PORT
      LAYER M5 ;
        RECT  124.128 43.116 124.152 43.2 ;
    END
  END o_data[214]
  PIN o_data[215]
    DIRECTION OUTPUT ;
    USE SIGNAL ;
    PORT
      LAYER M5 ;
        RECT  124.272 43.116 124.296 43.2 ;
    END
  END o_data[215]
  PIN o_data[216]
    DIRECTION OUTPUT ;
    USE SIGNAL ;
    PORT
      LAYER M5 ;
        RECT  124.416 43.116 124.44 43.2 ;
    END
  END o_data[216]
  PIN o_data[217]
    DIRECTION OUTPUT ;
    USE SIGNAL ;
    PORT
      LAYER M5 ;
        RECT  124.56 43.116 124.584 43.2 ;
    END
  END o_data[217]
  PIN o_data[218]
    DIRECTION OUTPUT ;
    USE SIGNAL ;
    PORT
      LAYER M5 ;
        RECT  124.704 43.116 124.728 43.2 ;
    END
  END o_data[218]
  PIN o_data[219]
    DIRECTION OUTPUT ;
    USE SIGNAL ;
    PORT
      LAYER M5 ;
        RECT  124.848 43.116 124.872 43.2 ;
    END
  END o_data[219]
  PIN o_data[21]
    DIRECTION OUTPUT ;
    USE SIGNAL ;
    PORT
      LAYER M5 ;
        RECT  99.792 43.116 99.816 43.2 ;
    END
  END o_data[21]
  PIN o_data[220]
    DIRECTION OUTPUT ;
    USE SIGNAL ;
    PORT
      LAYER M5 ;
        RECT  124.992 43.116 125.016 43.2 ;
    END
  END o_data[220]
  PIN o_data[221]
    DIRECTION OUTPUT ;
    USE SIGNAL ;
    PORT
      LAYER M5 ;
        RECT  125.136 43.116 125.16 43.2 ;
    END
  END o_data[221]
  PIN o_data[222]
    DIRECTION OUTPUT ;
    USE SIGNAL ;
    PORT
      LAYER M5 ;
        RECT  125.28 43.116 125.304 43.2 ;
    END
  END o_data[222]
  PIN o_data[223]
    DIRECTION OUTPUT ;
    USE SIGNAL ;
    PORT
      LAYER M5 ;
        RECT  125.424 43.116 125.448 43.2 ;
    END
  END o_data[223]
  PIN o_data[224]
    DIRECTION OUTPUT ;
    USE SIGNAL ;
    PORT
      LAYER M5 ;
        RECT  125.568 43.116 125.592 43.2 ;
    END
  END o_data[224]
  PIN o_data[225]
    DIRECTION OUTPUT ;
    USE SIGNAL ;
    PORT
      LAYER M5 ;
        RECT  125.712 43.116 125.736 43.2 ;
    END
  END o_data[225]
  PIN o_data[226]
    DIRECTION OUTPUT ;
    USE SIGNAL ;
    PORT
      LAYER M5 ;
        RECT  125.856 43.116 125.88 43.2 ;
    END
  END o_data[226]
  PIN o_data[227]
    DIRECTION OUTPUT ;
    USE SIGNAL ;
    PORT
      LAYER M5 ;
        RECT  126 43.116 126.024 43.2 ;
    END
  END o_data[227]
  PIN o_data[228]
    DIRECTION OUTPUT ;
    USE SIGNAL ;
    PORT
      LAYER M5 ;
        RECT  126.144 43.116 126.168 43.2 ;
    END
  END o_data[228]
  PIN o_data[229]
    DIRECTION OUTPUT ;
    USE SIGNAL ;
    PORT
      LAYER M5 ;
        RECT  126.288 43.116 126.312 43.2 ;
    END
  END o_data[229]
  PIN o_data[22]
    DIRECTION OUTPUT ;
    USE SIGNAL ;
    PORT
      LAYER M5 ;
        RECT  99.936 43.116 99.96 43.2 ;
    END
  END o_data[22]
  PIN o_data[230]
    DIRECTION OUTPUT ;
    USE SIGNAL ;
    PORT
      LAYER M5 ;
        RECT  126.432 43.116 126.456 43.2 ;
    END
  END o_data[230]
  PIN o_data[231]
    DIRECTION OUTPUT ;
    USE SIGNAL ;
    PORT
      LAYER M5 ;
        RECT  126.576 43.116 126.6 43.2 ;
    END
  END o_data[231]
  PIN o_data[232]
    DIRECTION OUTPUT ;
    USE SIGNAL ;
    PORT
      LAYER M5 ;
        RECT  126.72 43.116 126.744 43.2 ;
    END
  END o_data[232]
  PIN o_data[233]
    DIRECTION OUTPUT ;
    USE SIGNAL ;
    PORT
      LAYER M5 ;
        RECT  126.864 43.116 126.888 43.2 ;
    END
  END o_data[233]
  PIN o_data[234]
    DIRECTION OUTPUT ;
    USE SIGNAL ;
    PORT
      LAYER M5 ;
        RECT  127.008 43.116 127.032 43.2 ;
    END
  END o_data[234]
  PIN o_data[235]
    DIRECTION OUTPUT ;
    USE SIGNAL ;
    PORT
      LAYER M5 ;
        RECT  108.72 43.116 108.744 43.2 ;
    END
  END o_data[235]
  PIN o_data[236]
    DIRECTION OUTPUT ;
    USE SIGNAL ;
    PORT
      LAYER M5 ;
        RECT  108.864 43.116 108.888 43.2 ;
    END
  END o_data[236]
  PIN o_data[237]
    DIRECTION OUTPUT ;
    USE SIGNAL ;
    PORT
      LAYER M5 ;
        RECT  109.008 43.116 109.032 43.2 ;
    END
  END o_data[237]
  PIN o_data[238]
    DIRECTION OUTPUT ;
    USE SIGNAL ;
    PORT
      LAYER M5 ;
        RECT  109.152 43.116 109.176 43.2 ;
    END
  END o_data[238]
  PIN o_data[239]
    DIRECTION OUTPUT ;
    USE SIGNAL ;
    PORT
      LAYER M5 ;
        RECT  109.296 43.116 109.32 43.2 ;
    END
  END o_data[239]
  PIN o_data[23]
    DIRECTION OUTPUT ;
    USE SIGNAL ;
    PORT
      LAYER M5 ;
        RECT  100.08 43.116 100.104 43.2 ;
    END
  END o_data[23]
  PIN o_data[240]
    DIRECTION OUTPUT ;
    USE SIGNAL ;
    PORT
      LAYER M5 ;
        RECT  109.44 43.116 109.464 43.2 ;
    END
  END o_data[240]
  PIN o_data[241]
    DIRECTION OUTPUT ;
    USE SIGNAL ;
    PORT
      LAYER M5 ;
        RECT  109.584 43.116 109.608 43.2 ;
    END
  END o_data[241]
  PIN o_data[242]
    DIRECTION OUTPUT ;
    USE SIGNAL ;
    PORT
      LAYER M5 ;
        RECT  109.728 43.116 109.752 43.2 ;
    END
  END o_data[242]
  PIN o_data[243]
    DIRECTION OUTPUT ;
    USE SIGNAL ;
    PORT
      LAYER M5 ;
        RECT  109.872 43.116 109.896 43.2 ;
    END
  END o_data[243]
  PIN o_data[244]
    DIRECTION OUTPUT ;
    USE SIGNAL ;
    PORT
      LAYER M5 ;
        RECT  110.016 43.116 110.04 43.2 ;
    END
  END o_data[244]
  PIN o_data[245]
    DIRECTION OUTPUT ;
    USE SIGNAL ;
    PORT
      LAYER M5 ;
        RECT  110.16 43.116 110.184 43.2 ;
    END
  END o_data[245]
  PIN o_data[246]
    DIRECTION OUTPUT ;
    USE SIGNAL ;
    PORT
      LAYER M5 ;
        RECT  110.304 43.116 110.328 43.2 ;
    END
  END o_data[246]
  PIN o_data[247]
    DIRECTION OUTPUT ;
    USE SIGNAL ;
    PORT
      LAYER M5 ;
        RECT  110.448 43.116 110.472 43.2 ;
    END
  END o_data[247]
  PIN o_data[248]
    DIRECTION OUTPUT ;
    USE SIGNAL ;
    PORT
      LAYER M5 ;
        RECT  110.592 43.116 110.616 43.2 ;
    END
  END o_data[248]
  PIN o_data[249]
    DIRECTION OUTPUT ;
    USE SIGNAL ;
    PORT
      LAYER M5 ;
        RECT  110.736 43.116 110.76 43.2 ;
    END
  END o_data[249]
  PIN o_data[24]
    DIRECTION OUTPUT ;
    USE SIGNAL ;
    PORT
      LAYER M5 ;
        RECT  100.224 43.116 100.248 43.2 ;
    END
  END o_data[24]
  PIN o_data[250]
    DIRECTION OUTPUT ;
    USE SIGNAL ;
    PORT
      LAYER M5 ;
        RECT  110.88 43.116 110.904 43.2 ;
    END
  END o_data[250]
  PIN o_data[251]
    DIRECTION OUTPUT ;
    USE SIGNAL ;
    PORT
      LAYER M5 ;
        RECT  111.024 43.116 111.048 43.2 ;
    END
  END o_data[251]
  PIN o_data[252]
    DIRECTION OUTPUT ;
    USE SIGNAL ;
    PORT
      LAYER M5 ;
        RECT  111.168 43.116 111.192 43.2 ;
    END
  END o_data[252]
  PIN o_data[253]
    DIRECTION OUTPUT ;
    USE SIGNAL ;
    PORT
      LAYER M5 ;
        RECT  111.312 43.116 111.336 43.2 ;
    END
  END o_data[253]
  PIN o_data[254]
    DIRECTION OUTPUT ;
    USE SIGNAL ;
    PORT
      LAYER M5 ;
        RECT  111.456 43.116 111.48 43.2 ;
    END
  END o_data[254]
  PIN o_data[255]
    DIRECTION OUTPUT ;
    USE SIGNAL ;
    PORT
      LAYER M5 ;
        RECT  111.6 43.116 111.624 43.2 ;
    END
  END o_data[255]
  PIN o_data[256]
    DIRECTION OUTPUT ;
    USE SIGNAL ;
    PORT
      LAYER M5 ;
        RECT  111.744 43.116 111.768 43.2 ;
    END
  END o_data[256]
  PIN o_data[257]
    DIRECTION OUTPUT ;
    USE SIGNAL ;
    PORT
      LAYER M5 ;
        RECT  111.888 43.116 111.912 43.2 ;
    END
  END o_data[257]
  PIN o_data[258]
    DIRECTION OUTPUT ;
    USE SIGNAL ;
    PORT
      LAYER M5 ;
        RECT  112.032 43.116 112.056 43.2 ;
    END
  END o_data[258]
  PIN o_data[259]
    DIRECTION OUTPUT ;
    USE SIGNAL ;
    PORT
      LAYER M5 ;
        RECT  112.176 43.116 112.2 43.2 ;
    END
  END o_data[259]
  PIN o_data[25]
    DIRECTION OUTPUT ;
    USE SIGNAL ;
    PORT
      LAYER M5 ;
        RECT  100.368 43.116 100.392 43.2 ;
    END
  END o_data[25]
  PIN o_data[260]
    DIRECTION OUTPUT ;
    USE SIGNAL ;
    PORT
      LAYER M5 ;
        RECT  112.32 43.116 112.344 43.2 ;
    END
  END o_data[260]
  PIN o_data[261]
    DIRECTION OUTPUT ;
    USE SIGNAL ;
    PORT
      LAYER M5 ;
        RECT  112.464 43.116 112.488 43.2 ;
    END
  END o_data[261]
  PIN o_data[262]
    DIRECTION OUTPUT ;
    USE SIGNAL ;
    PORT
      LAYER M5 ;
        RECT  112.608 43.116 112.632 43.2 ;
    END
  END o_data[262]
  PIN o_data[263]
    DIRECTION OUTPUT ;
    USE SIGNAL ;
    PORT
      LAYER M5 ;
        RECT  112.752 43.116 112.776 43.2 ;
    END
  END o_data[263]
  PIN o_data[264]
    DIRECTION OUTPUT ;
    USE SIGNAL ;
    PORT
      LAYER M5 ;
        RECT  112.896 43.116 112.92 43.2 ;
    END
  END o_data[264]
  PIN o_data[265]
    DIRECTION OUTPUT ;
    USE SIGNAL ;
    PORT
      LAYER M5 ;
        RECT  113.04 43.116 113.064 43.2 ;
    END
  END o_data[265]
  PIN o_data[266]
    DIRECTION OUTPUT ;
    USE SIGNAL ;
    PORT
      LAYER M5 ;
        RECT  113.184 43.116 113.208 43.2 ;
    END
  END o_data[266]
  PIN o_data[267]
    DIRECTION OUTPUT ;
    USE SIGNAL ;
    PORT
      LAYER M5 ;
        RECT  113.328 43.116 113.352 43.2 ;
    END
  END o_data[267]
  PIN o_data[268]
    DIRECTION OUTPUT ;
    USE SIGNAL ;
    PORT
      LAYER M5 ;
        RECT  113.472 43.116 113.496 43.2 ;
    END
  END o_data[268]
  PIN o_data[269]
    DIRECTION OUTPUT ;
    USE SIGNAL ;
    PORT
      LAYER M5 ;
        RECT  113.616 43.116 113.64 43.2 ;
    END
  END o_data[269]
  PIN o_data[26]
    DIRECTION OUTPUT ;
    USE SIGNAL ;
    PORT
      LAYER M5 ;
        RECT  100.512 43.116 100.536 43.2 ;
    END
  END o_data[26]
  PIN o_data[270]
    DIRECTION OUTPUT ;
    USE SIGNAL ;
    PORT
      LAYER M5 ;
        RECT  113.76 43.116 113.784 43.2 ;
    END
  END o_data[270]
  PIN o_data[271]
    DIRECTION OUTPUT ;
    USE SIGNAL ;
    PORT
      LAYER M5 ;
        RECT  113.904 43.116 113.928 43.2 ;
    END
  END o_data[271]
  PIN o_data[272]
    DIRECTION OUTPUT ;
    USE SIGNAL ;
    PORT
      LAYER M5 ;
        RECT  114.048 43.116 114.072 43.2 ;
    END
  END o_data[272]
  PIN o_data[273]
    DIRECTION OUTPUT ;
    USE SIGNAL ;
    PORT
      LAYER M5 ;
        RECT  114.192 43.116 114.216 43.2 ;
    END
  END o_data[273]
  PIN o_data[274]
    DIRECTION OUTPUT ;
    USE SIGNAL ;
    PORT
      LAYER M5 ;
        RECT  114.336 43.116 114.36 43.2 ;
    END
  END o_data[274]
  PIN o_data[275]
    DIRECTION OUTPUT ;
    USE SIGNAL ;
    PORT
      LAYER M5 ;
        RECT  114.48 43.116 114.504 43.2 ;
    END
  END o_data[275]
  PIN o_data[276]
    DIRECTION OUTPUT ;
    USE SIGNAL ;
    PORT
      LAYER M5 ;
        RECT  114.624 43.116 114.648 43.2 ;
    END
  END o_data[276]
  PIN o_data[277]
    DIRECTION OUTPUT ;
    USE SIGNAL ;
    PORT
      LAYER M5 ;
        RECT  114.768 43.116 114.792 43.2 ;
    END
  END o_data[277]
  PIN o_data[278]
    DIRECTION OUTPUT ;
    USE SIGNAL ;
    PORT
      LAYER M5 ;
        RECT  114.912 43.116 114.936 43.2 ;
    END
  END o_data[278]
  PIN o_data[279]
    DIRECTION OUTPUT ;
    USE SIGNAL ;
    PORT
      LAYER M5 ;
        RECT  115.056 43.116 115.08 43.2 ;
    END
  END o_data[279]
  PIN o_data[27]
    DIRECTION OUTPUT ;
    USE SIGNAL ;
    PORT
      LAYER M5 ;
        RECT  100.656 43.116 100.68 43.2 ;
    END
  END o_data[27]
  PIN o_data[280]
    DIRECTION OUTPUT ;
    USE SIGNAL ;
    PORT
      LAYER M5 ;
        RECT  115.2 43.116 115.224 43.2 ;
    END
  END o_data[280]
  PIN o_data[281]
    DIRECTION OUTPUT ;
    USE SIGNAL ;
    PORT
      LAYER M5 ;
        RECT  115.344 43.116 115.368 43.2 ;
    END
  END o_data[281]
  PIN o_data[282]
    DIRECTION OUTPUT ;
    USE SIGNAL ;
    PORT
      LAYER M5 ;
        RECT  115.488 43.116 115.512 43.2 ;
    END
  END o_data[282]
  PIN o_data[283]
    DIRECTION OUTPUT ;
    USE SIGNAL ;
    PORT
      LAYER M5 ;
        RECT  115.632 43.116 115.656 43.2 ;
    END
  END o_data[283]
  PIN o_data[284]
    DIRECTION OUTPUT ;
    USE SIGNAL ;
    PORT
      LAYER M5 ;
        RECT  115.776 43.116 115.8 43.2 ;
    END
  END o_data[284]
  PIN o_data[285]
    DIRECTION OUTPUT ;
    USE SIGNAL ;
    PORT
      LAYER M5 ;
        RECT  115.92 43.116 115.944 43.2 ;
    END
  END o_data[285]
  PIN o_data[286]
    DIRECTION OUTPUT ;
    USE SIGNAL ;
    PORT
      LAYER M5 ;
        RECT  116.064 43.116 116.088 43.2 ;
    END
  END o_data[286]
  PIN o_data[287]
    DIRECTION OUTPUT ;
    USE SIGNAL ;
    PORT
      LAYER M5 ;
        RECT  116.208 43.116 116.232 43.2 ;
    END
  END o_data[287]
  PIN o_data[288]
    DIRECTION OUTPUT ;
    USE SIGNAL ;
    PORT
      LAYER M5 ;
        RECT  116.352 43.116 116.376 43.2 ;
    END
  END o_data[288]
  PIN o_data[289]
    DIRECTION OUTPUT ;
    USE SIGNAL ;
    PORT
      LAYER M5 ;
        RECT  116.496 43.116 116.52 43.2 ;
    END
  END o_data[289]
  PIN o_data[28]
    DIRECTION OUTPUT ;
    USE SIGNAL ;
    PORT
      LAYER M5 ;
        RECT  100.8 43.116 100.824 43.2 ;
    END
  END o_data[28]
  PIN o_data[290]
    DIRECTION OUTPUT ;
    USE SIGNAL ;
    PORT
      LAYER M5 ;
        RECT  116.64 43.116 116.664 43.2 ;
    END
  END o_data[290]
  PIN o_data[291]
    DIRECTION OUTPUT ;
    USE SIGNAL ;
    PORT
      LAYER M5 ;
        RECT  116.784 43.116 116.808 43.2 ;
    END
  END o_data[291]
  PIN o_data[292]
    DIRECTION OUTPUT ;
    USE SIGNAL ;
    PORT
      LAYER M5 ;
        RECT  116.928 43.116 116.952 43.2 ;
    END
  END o_data[292]
  PIN o_data[293]
    DIRECTION OUTPUT ;
    USE SIGNAL ;
    PORT
      LAYER M5 ;
        RECT  117.072 43.116 117.096 43.2 ;
    END
  END o_data[293]
  PIN o_data[294]
    DIRECTION OUTPUT ;
    USE SIGNAL ;
    PORT
      LAYER M5 ;
        RECT  117.216 43.116 117.24 43.2 ;
    END
  END o_data[294]
  PIN o_data[295]
    DIRECTION OUTPUT ;
    USE SIGNAL ;
    PORT
      LAYER M5 ;
        RECT  117.36 43.116 117.384 43.2 ;
    END
  END o_data[295]
  PIN o_data[296]
    DIRECTION OUTPUT ;
    USE SIGNAL ;
    PORT
      LAYER M5 ;
        RECT  117.504 43.116 117.528 43.2 ;
    END
  END o_data[296]
  PIN o_data[297]
    DIRECTION OUTPUT ;
    USE SIGNAL ;
    PORT
      LAYER M5 ;
        RECT  117.648 43.116 117.672 43.2 ;
    END
  END o_data[297]
  PIN o_data[298]
    DIRECTION OUTPUT ;
    USE SIGNAL ;
    PORT
      LAYER M5 ;
        RECT  117.792 43.116 117.816 43.2 ;
    END
  END o_data[298]
  PIN o_data[299]
    DIRECTION OUTPUT ;
    USE SIGNAL ;
    PORT
      LAYER M5 ;
        RECT  104.112 43.116 104.136 43.2 ;
    END
  END o_data[299]
  PIN o_data[29]
    DIRECTION OUTPUT ;
    USE SIGNAL ;
    PORT
      LAYER M5 ;
        RECT  100.944 43.116 100.968 43.2 ;
    END
  END o_data[29]
  PIN o_data[2]
    DIRECTION OUTPUT ;
    USE SIGNAL ;
    PORT
      LAYER M5 ;
        RECT  130.464 43.116 130.488 43.2 ;
    END
  END o_data[2]
  PIN o_data[300]
    DIRECTION OUTPUT ;
    USE SIGNAL ;
    PORT
      LAYER M5 ;
        RECT  104.256 43.116 104.28 43.2 ;
    END
  END o_data[300]
  PIN o_data[301]
    DIRECTION OUTPUT ;
    USE SIGNAL ;
    PORT
      LAYER M5 ;
        RECT  104.4 43.116 104.424 43.2 ;
    END
  END o_data[301]
  PIN o_data[302]
    DIRECTION OUTPUT ;
    USE SIGNAL ;
    PORT
      LAYER M5 ;
        RECT  104.544 43.116 104.568 43.2 ;
    END
  END o_data[302]
  PIN o_data[303]
    DIRECTION OUTPUT ;
    USE SIGNAL ;
    PORT
      LAYER M5 ;
        RECT  104.688 43.116 104.712 43.2 ;
    END
  END o_data[303]
  PIN o_data[304]
    DIRECTION OUTPUT ;
    USE SIGNAL ;
    PORT
      LAYER M5 ;
        RECT  104.832 43.116 104.856 43.2 ;
    END
  END o_data[304]
  PIN o_data[305]
    DIRECTION OUTPUT ;
    USE SIGNAL ;
    PORT
      LAYER M5 ;
        RECT  104.976 43.116 105 43.2 ;
    END
  END o_data[305]
  PIN o_data[306]
    DIRECTION OUTPUT ;
    USE SIGNAL ;
    PORT
      LAYER M5 ;
        RECT  105.12 43.116 105.144 43.2 ;
    END
  END o_data[306]
  PIN o_data[307]
    DIRECTION OUTPUT ;
    USE SIGNAL ;
    PORT
      LAYER M5 ;
        RECT  105.264 43.116 105.288 43.2 ;
    END
  END o_data[307]
  PIN o_data[308]
    DIRECTION OUTPUT ;
    USE SIGNAL ;
    PORT
      LAYER M5 ;
        RECT  105.408 43.116 105.432 43.2 ;
    END
  END o_data[308]
  PIN o_data[309]
    DIRECTION OUTPUT ;
    USE SIGNAL ;
    PORT
      LAYER M5 ;
        RECT  105.552 43.116 105.576 43.2 ;
    END
  END o_data[309]
  PIN o_data[30]
    DIRECTION OUTPUT ;
    USE SIGNAL ;
    PORT
      LAYER M5 ;
        RECT  101.088 43.116 101.112 43.2 ;
    END
  END o_data[30]
  PIN o_data[310]
    DIRECTION OUTPUT ;
    USE SIGNAL ;
    PORT
      LAYER M5 ;
        RECT  105.696 43.116 105.72 43.2 ;
    END
  END o_data[310]
  PIN o_data[311]
    DIRECTION OUTPUT ;
    USE SIGNAL ;
    PORT
      LAYER M5 ;
        RECT  105.84 43.116 105.864 43.2 ;
    END
  END o_data[311]
  PIN o_data[312]
    DIRECTION OUTPUT ;
    USE SIGNAL ;
    PORT
      LAYER M5 ;
        RECT  105.984 43.116 106.008 43.2 ;
    END
  END o_data[312]
  PIN o_data[313]
    DIRECTION OUTPUT ;
    USE SIGNAL ;
    PORT
      LAYER M5 ;
        RECT  106.128 43.116 106.152 43.2 ;
    END
  END o_data[313]
  PIN o_data[314]
    DIRECTION OUTPUT ;
    USE SIGNAL ;
    PORT
      LAYER M5 ;
        RECT  106.272 43.116 106.296 43.2 ;
    END
  END o_data[314]
  PIN o_data[315]
    DIRECTION OUTPUT ;
    USE SIGNAL ;
    PORT
      LAYER M5 ;
        RECT  106.416 43.116 106.44 43.2 ;
    END
  END o_data[315]
  PIN o_data[316]
    DIRECTION OUTPUT ;
    USE SIGNAL ;
    PORT
      LAYER M5 ;
        RECT  106.56 43.116 106.584 43.2 ;
    END
  END o_data[316]
  PIN o_data[317]
    DIRECTION OUTPUT ;
    USE SIGNAL ;
    PORT
      LAYER M5 ;
        RECT  106.704 43.116 106.728 43.2 ;
    END
  END o_data[317]
  PIN o_data[318]
    DIRECTION OUTPUT ;
    USE SIGNAL ;
    PORT
      LAYER M5 ;
        RECT  106.848 43.116 106.872 43.2 ;
    END
  END o_data[318]
  PIN o_data[319]
    DIRECTION OUTPUT ;
    USE SIGNAL ;
    PORT
      LAYER M5 ;
        RECT  106.992 43.116 107.016 43.2 ;
    END
  END o_data[319]
  PIN o_data[31]
    DIRECTION OUTPUT ;
    USE SIGNAL ;
    PORT
      LAYER M5 ;
        RECT  101.232 43.116 101.256 43.2 ;
    END
  END o_data[31]
  PIN o_data[320]
    DIRECTION OUTPUT ;
    USE SIGNAL ;
    PORT
      LAYER M5 ;
        RECT  107.136 43.116 107.16 43.2 ;
    END
  END o_data[320]
  PIN o_data[321]
    DIRECTION OUTPUT ;
    USE SIGNAL ;
    PORT
      LAYER M5 ;
        RECT  107.28 43.116 107.304 43.2 ;
    END
  END o_data[321]
  PIN o_data[322]
    DIRECTION OUTPUT ;
    USE SIGNAL ;
    PORT
      LAYER M5 ;
        RECT  107.424 43.116 107.448 43.2 ;
    END
  END o_data[322]
  PIN o_data[323]
    DIRECTION OUTPUT ;
    USE SIGNAL ;
    PORT
      LAYER M5 ;
        RECT  107.568 43.116 107.592 43.2 ;
    END
  END o_data[323]
  PIN o_data[324]
    DIRECTION OUTPUT ;
    USE SIGNAL ;
    PORT
      LAYER M5 ;
        RECT  107.712 43.116 107.736 43.2 ;
    END
  END o_data[324]
  PIN o_data[325]
    DIRECTION OUTPUT ;
    USE SIGNAL ;
    PORT
      LAYER M5 ;
        RECT  107.856 43.116 107.88 43.2 ;
    END
  END o_data[325]
  PIN o_data[326]
    DIRECTION OUTPUT ;
    USE SIGNAL ;
    PORT
      LAYER M5 ;
        RECT  108 43.116 108.024 43.2 ;
    END
  END o_data[326]
  PIN o_data[327]
    DIRECTION OUTPUT ;
    USE SIGNAL ;
    PORT
      LAYER M5 ;
        RECT  108.144 43.116 108.168 43.2 ;
    END
  END o_data[327]
  PIN o_data[328]
    DIRECTION OUTPUT ;
    USE SIGNAL ;
    PORT
      LAYER M5 ;
        RECT  108.288 43.116 108.312 43.2 ;
    END
  END o_data[328]
  PIN o_data[329]
    DIRECTION OUTPUT ;
    USE SIGNAL ;
    PORT
      LAYER M5 ;
        RECT  108.432 43.116 108.456 43.2 ;
    END
  END o_data[329]
  PIN o_data[32]
    DIRECTION OUTPUT ;
    USE SIGNAL ;
    PORT
      LAYER M5 ;
        RECT  101.376 43.116 101.4 43.2 ;
    END
  END o_data[32]
  PIN o_data[330]
    DIRECTION OUTPUT ;
    USE SIGNAL ;
    PORT
      LAYER M5 ;
        RECT  108.576 43.116 108.6 43.2 ;
    END
  END o_data[330]
  PIN o_data[331]
    DIRECTION OUTPUT ;
    USE SIGNAL ;
    PORT
      LAYER M5 ;
        RECT  117.936 43.116 117.96 43.2 ;
    END
  END o_data[331]
  PIN o_data[332]
    DIRECTION OUTPUT ;
    USE SIGNAL ;
    PORT
      LAYER M5 ;
        RECT  118.08 43.116 118.104 43.2 ;
    END
  END o_data[332]
  PIN o_data[333]
    DIRECTION OUTPUT ;
    USE SIGNAL ;
    PORT
      LAYER M5 ;
        RECT  118.224 43.116 118.248 43.2 ;
    END
  END o_data[333]
  PIN o_data[334]
    DIRECTION OUTPUT ;
    USE SIGNAL ;
    PORT
      LAYER M5 ;
        RECT  118.368 43.116 118.392 43.2 ;
    END
  END o_data[334]
  PIN o_data[335]
    DIRECTION OUTPUT ;
    USE SIGNAL ;
    PORT
      LAYER M5 ;
        RECT  118.512 43.116 118.536 43.2 ;
    END
  END o_data[335]
  PIN o_data[336]
    DIRECTION OUTPUT ;
    USE SIGNAL ;
    PORT
      LAYER M5 ;
        RECT  118.656 43.116 118.68 43.2 ;
    END
  END o_data[336]
  PIN o_data[337]
    DIRECTION OUTPUT ;
    USE SIGNAL ;
    PORT
      LAYER M5 ;
        RECT  118.8 43.116 118.824 43.2 ;
    END
  END o_data[337]
  PIN o_data[338]
    DIRECTION OUTPUT ;
    USE SIGNAL ;
    PORT
      LAYER M5 ;
        RECT  118.944 43.116 118.968 43.2 ;
    END
  END o_data[338]
  PIN o_data[339]
    DIRECTION OUTPUT ;
    USE SIGNAL ;
    PORT
      LAYER M5 ;
        RECT  119.088 43.116 119.112 43.2 ;
    END
  END o_data[339]
  PIN o_data[33]
    DIRECTION OUTPUT ;
    USE SIGNAL ;
    PORT
      LAYER M5 ;
        RECT  101.52 43.116 101.544 43.2 ;
    END
  END o_data[33]
  PIN o_data[340]
    DIRECTION OUTPUT ;
    USE SIGNAL ;
    PORT
      LAYER M5 ;
        RECT  119.232 43.116 119.256 43.2 ;
    END
  END o_data[340]
  PIN o_data[341]
    DIRECTION OUTPUT ;
    USE SIGNAL ;
    PORT
      LAYER M5 ;
        RECT  119.376 43.116 119.4 43.2 ;
    END
  END o_data[341]
  PIN o_data[342]
    DIRECTION OUTPUT ;
    USE SIGNAL ;
    PORT
      LAYER M5 ;
        RECT  119.52 43.116 119.544 43.2 ;
    END
  END o_data[342]
  PIN o_data[343]
    DIRECTION OUTPUT ;
    USE SIGNAL ;
    PORT
      LAYER M5 ;
        RECT  119.664 43.116 119.688 43.2 ;
    END
  END o_data[343]
  PIN o_data[344]
    DIRECTION OUTPUT ;
    USE SIGNAL ;
    PORT
      LAYER M5 ;
        RECT  119.808 43.116 119.832 43.2 ;
    END
  END o_data[344]
  PIN o_data[345]
    DIRECTION OUTPUT ;
    USE SIGNAL ;
    PORT
      LAYER M5 ;
        RECT  119.952 43.116 119.976 43.2 ;
    END
  END o_data[345]
  PIN o_data[346]
    DIRECTION OUTPUT ;
    USE SIGNAL ;
    PORT
      LAYER M5 ;
        RECT  120.096 43.116 120.12 43.2 ;
    END
  END o_data[346]
  PIN o_data[347]
    DIRECTION OUTPUT ;
    USE SIGNAL ;
    PORT
      LAYER M5 ;
        RECT  120.24 43.116 120.264 43.2 ;
    END
  END o_data[347]
  PIN o_data[348]
    DIRECTION OUTPUT ;
    USE SIGNAL ;
    PORT
      LAYER M5 ;
        RECT  120.384 43.116 120.408 43.2 ;
    END
  END o_data[348]
  PIN o_data[349]
    DIRECTION OUTPUT ;
    USE SIGNAL ;
    PORT
      LAYER M5 ;
        RECT  120.528 43.116 120.552 43.2 ;
    END
  END o_data[349]
  PIN o_data[34]
    DIRECTION OUTPUT ;
    USE SIGNAL ;
    PORT
      LAYER M5 ;
        RECT  101.664 43.116 101.688 43.2 ;
    END
  END o_data[34]
  PIN o_data[350]
    DIRECTION OUTPUT ;
    USE SIGNAL ;
    PORT
      LAYER M5 ;
        RECT  120.672 43.116 120.696 43.2 ;
    END
  END o_data[350]
  PIN o_data[351]
    DIRECTION OUTPUT ;
    USE SIGNAL ;
    PORT
      LAYER M5 ;
        RECT  120.816 43.116 120.84 43.2 ;
    END
  END o_data[351]
  PIN o_data[352]
    DIRECTION OUTPUT ;
    USE SIGNAL ;
    PORT
      LAYER M5 ;
        RECT  120.96 43.116 120.984 43.2 ;
    END
  END o_data[352]
  PIN o_data[353]
    DIRECTION OUTPUT ;
    USE SIGNAL ;
    PORT
      LAYER M5 ;
        RECT  121.104 43.116 121.128 43.2 ;
    END
  END o_data[353]
  PIN o_data[354]
    DIRECTION OUTPUT ;
    USE SIGNAL ;
    PORT
      LAYER M5 ;
        RECT  121.248 43.116 121.272 43.2 ;
    END
  END o_data[354]
  PIN o_data[355]
    DIRECTION OUTPUT ;
    USE SIGNAL ;
    PORT
      LAYER M5 ;
        RECT  121.392 43.116 121.416 43.2 ;
    END
  END o_data[355]
  PIN o_data[356]
    DIRECTION OUTPUT ;
    USE SIGNAL ;
    PORT
      LAYER M5 ;
        RECT  121.536 43.116 121.56 43.2 ;
    END
  END o_data[356]
  PIN o_data[357]
    DIRECTION OUTPUT ;
    USE SIGNAL ;
    PORT
      LAYER M5 ;
        RECT  121.68 43.116 121.704 43.2 ;
    END
  END o_data[357]
  PIN o_data[358]
    DIRECTION OUTPUT ;
    USE SIGNAL ;
    PORT
      LAYER M5 ;
        RECT  121.824 43.116 121.848 43.2 ;
    END
  END o_data[358]
  PIN o_data[359]
    DIRECTION OUTPUT ;
    USE SIGNAL ;
    PORT
      LAYER M5 ;
        RECT  121.968 43.116 121.992 43.2 ;
    END
  END o_data[359]
  PIN o_data[35]
    DIRECTION OUTPUT ;
    USE SIGNAL ;
    PORT
      LAYER M5 ;
        RECT  101.808 43.116 101.832 43.2 ;
    END
  END o_data[35]
  PIN o_data[360]
    DIRECTION OUTPUT ;
    USE SIGNAL ;
    PORT
      LAYER M5 ;
        RECT  122.112 43.116 122.136 43.2 ;
    END
  END o_data[360]
  PIN o_data[361]
    DIRECTION OUTPUT ;
    USE SIGNAL ;
    PORT
      LAYER M5 ;
        RECT  122.256 43.116 122.28 43.2 ;
    END
  END o_data[361]
  PIN o_data[362]
    DIRECTION OUTPUT ;
    USE SIGNAL ;
    PORT
      LAYER M5 ;
        RECT  122.4 43.116 122.424 43.2 ;
    END
  END o_data[362]
  PIN o_data[363]
    DIRECTION OUTPUT ;
    USE SIGNAL ;
    PORT
      LAYER M5 ;
        RECT  60.336 43.116 60.36 43.2 ;
    END
  END o_data[363]
  PIN o_data[364]
    DIRECTION OUTPUT ;
    USE SIGNAL ;
    PORT
      LAYER M5 ;
        RECT  60.48 43.116 60.504 43.2 ;
    END
  END o_data[364]
  PIN o_data[365]
    DIRECTION OUTPUT ;
    USE SIGNAL ;
    PORT
      LAYER M5 ;
        RECT  60.624 43.116 60.648 43.2 ;
    END
  END o_data[365]
  PIN o_data[366]
    DIRECTION OUTPUT ;
    USE SIGNAL ;
    PORT
      LAYER M5 ;
        RECT  60.768 43.116 60.792 43.2 ;
    END
  END o_data[366]
  PIN o_data[367]
    DIRECTION OUTPUT ;
    USE SIGNAL ;
    PORT
      LAYER M5 ;
        RECT  60.912 43.116 60.936 43.2 ;
    END
  END o_data[367]
  PIN o_data[368]
    DIRECTION OUTPUT ;
    USE SIGNAL ;
    PORT
      LAYER M5 ;
        RECT  61.056 43.116 61.08 43.2 ;
    END
  END o_data[368]
  PIN o_data[369]
    DIRECTION OUTPUT ;
    USE SIGNAL ;
    PORT
      LAYER M5 ;
        RECT  61.2 43.116 61.224 43.2 ;
    END
  END o_data[369]
  PIN o_data[36]
    DIRECTION OUTPUT ;
    USE SIGNAL ;
    PORT
      LAYER M5 ;
        RECT  101.952 43.116 101.976 43.2 ;
    END
  END o_data[36]
  PIN o_data[370]
    DIRECTION OUTPUT ;
    USE SIGNAL ;
    PORT
      LAYER M5 ;
        RECT  61.344 43.116 61.368 43.2 ;
    END
  END o_data[370]
  PIN o_data[371]
    DIRECTION OUTPUT ;
    USE SIGNAL ;
    PORT
      LAYER M5 ;
        RECT  61.488 43.116 61.512 43.2 ;
    END
  END o_data[371]
  PIN o_data[372]
    DIRECTION OUTPUT ;
    USE SIGNAL ;
    PORT
      LAYER M5 ;
        RECT  61.632 43.116 61.656 43.2 ;
    END
  END o_data[372]
  PIN o_data[373]
    DIRECTION OUTPUT ;
    USE SIGNAL ;
    PORT
      LAYER M5 ;
        RECT  61.776 43.116 61.8 43.2 ;
    END
  END o_data[373]
  PIN o_data[374]
    DIRECTION OUTPUT ;
    USE SIGNAL ;
    PORT
      LAYER M5 ;
        RECT  61.92 43.116 61.944 43.2 ;
    END
  END o_data[374]
  PIN o_data[375]
    DIRECTION OUTPUT ;
    USE SIGNAL ;
    PORT
      LAYER M5 ;
        RECT  62.064 43.116 62.088 43.2 ;
    END
  END o_data[375]
  PIN o_data[376]
    DIRECTION OUTPUT ;
    USE SIGNAL ;
    PORT
      LAYER M5 ;
        RECT  62.208 43.116 62.232 43.2 ;
    END
  END o_data[376]
  PIN o_data[377]
    DIRECTION OUTPUT ;
    USE SIGNAL ;
    PORT
      LAYER M5 ;
        RECT  62.352 43.116 62.376 43.2 ;
    END
  END o_data[377]
  PIN o_data[378]
    DIRECTION OUTPUT ;
    USE SIGNAL ;
    PORT
      LAYER M5 ;
        RECT  62.496 43.116 62.52 43.2 ;
    END
  END o_data[378]
  PIN o_data[379]
    DIRECTION OUTPUT ;
    USE SIGNAL ;
    PORT
      LAYER M5 ;
        RECT  62.64 43.116 62.664 43.2 ;
    END
  END o_data[379]
  PIN o_data[37]
    DIRECTION OUTPUT ;
    USE SIGNAL ;
    PORT
      LAYER M5 ;
        RECT  102.096 43.116 102.12 43.2 ;
    END
  END o_data[37]
  PIN o_data[380]
    DIRECTION OUTPUT ;
    USE SIGNAL ;
    PORT
      LAYER M5 ;
        RECT  62.784 43.116 62.808 43.2 ;
    END
  END o_data[380]
  PIN o_data[381]
    DIRECTION OUTPUT ;
    USE SIGNAL ;
    PORT
      LAYER M5 ;
        RECT  62.928 43.116 62.952 43.2 ;
    END
  END o_data[381]
  PIN o_data[382]
    DIRECTION OUTPUT ;
    USE SIGNAL ;
    PORT
      LAYER M5 ;
        RECT  63.072 43.116 63.096 43.2 ;
    END
  END o_data[382]
  PIN o_data[383]
    DIRECTION OUTPUT ;
    USE SIGNAL ;
    PORT
      LAYER M5 ;
        RECT  63.216 43.116 63.24 43.2 ;
    END
  END o_data[383]
  PIN o_data[384]
    DIRECTION OUTPUT ;
    USE SIGNAL ;
    PORT
      LAYER M5 ;
        RECT  63.36 43.116 63.384 43.2 ;
    END
  END o_data[384]
  PIN o_data[385]
    DIRECTION OUTPUT ;
    USE SIGNAL ;
    PORT
      LAYER M5 ;
        RECT  63.504 43.116 63.528 43.2 ;
    END
  END o_data[385]
  PIN o_data[386]
    DIRECTION OUTPUT ;
    USE SIGNAL ;
    PORT
      LAYER M5 ;
        RECT  63.648 43.116 63.672 43.2 ;
    END
  END o_data[386]
  PIN o_data[387]
    DIRECTION OUTPUT ;
    USE SIGNAL ;
    PORT
      LAYER M5 ;
        RECT  63.792 43.116 63.816 43.2 ;
    END
  END o_data[387]
  PIN o_data[388]
    DIRECTION OUTPUT ;
    USE SIGNAL ;
    PORT
      LAYER M5 ;
        RECT  63.936 43.116 63.96 43.2 ;
    END
  END o_data[388]
  PIN o_data[389]
    DIRECTION OUTPUT ;
    USE SIGNAL ;
    PORT
      LAYER M5 ;
        RECT  64.08 43.116 64.104 43.2 ;
    END
  END o_data[389]
  PIN o_data[38]
    DIRECTION OUTPUT ;
    USE SIGNAL ;
    PORT
      LAYER M5 ;
        RECT  102.24 43.116 102.264 43.2 ;
    END
  END o_data[38]
  PIN o_data[390]
    DIRECTION OUTPUT ;
    USE SIGNAL ;
    PORT
      LAYER M5 ;
        RECT  64.224 43.116 64.248 43.2 ;
    END
  END o_data[390]
  PIN o_data[391]
    DIRECTION OUTPUT ;
    USE SIGNAL ;
    PORT
      LAYER M5 ;
        RECT  64.368 43.116 64.392 43.2 ;
    END
  END o_data[391]
  PIN o_data[392]
    DIRECTION OUTPUT ;
    USE SIGNAL ;
    PORT
      LAYER M5 ;
        RECT  64.512 43.116 64.536 43.2 ;
    END
  END o_data[392]
  PIN o_data[393]
    DIRECTION OUTPUT ;
    USE SIGNAL ;
    PORT
      LAYER M5 ;
        RECT  64.656 43.116 64.68 43.2 ;
    END
  END o_data[393]
  PIN o_data[394]
    DIRECTION OUTPUT ;
    USE SIGNAL ;
    PORT
      LAYER M5 ;
        RECT  64.8 43.116 64.824 43.2 ;
    END
  END o_data[394]
  PIN o_data[395]
    DIRECTION OUTPUT ;
    USE SIGNAL ;
    PORT
      LAYER M5 ;
        RECT  55.728 43.116 55.752 43.2 ;
    END
  END o_data[395]
  PIN o_data[396]
    DIRECTION OUTPUT ;
    USE SIGNAL ;
    PORT
      LAYER M5 ;
        RECT  55.872 43.116 55.896 43.2 ;
    END
  END o_data[396]
  PIN o_data[397]
    DIRECTION OUTPUT ;
    USE SIGNAL ;
    PORT
      LAYER M5 ;
        RECT  56.016 43.116 56.04 43.2 ;
    END
  END o_data[397]
  PIN o_data[398]
    DIRECTION OUTPUT ;
    USE SIGNAL ;
    PORT
      LAYER M5 ;
        RECT  56.16 43.116 56.184 43.2 ;
    END
  END o_data[398]
  PIN o_data[399]
    DIRECTION OUTPUT ;
    USE SIGNAL ;
    PORT
      LAYER M5 ;
        RECT  56.304 43.116 56.328 43.2 ;
    END
  END o_data[399]
  PIN o_data[39]
    DIRECTION OUTPUT ;
    USE SIGNAL ;
    PORT
      LAYER M5 ;
        RECT  102.384 43.116 102.408 43.2 ;
    END
  END o_data[39]
  PIN o_data[3]
    DIRECTION OUTPUT ;
    USE SIGNAL ;
    PORT
      LAYER M5 ;
        RECT  130.608 43.116 130.632 43.2 ;
    END
  END o_data[3]
  PIN o_data[400]
    DIRECTION OUTPUT ;
    USE SIGNAL ;
    PORT
      LAYER M5 ;
        RECT  56.448 43.116 56.472 43.2 ;
    END
  END o_data[400]
  PIN o_data[401]
    DIRECTION OUTPUT ;
    USE SIGNAL ;
    PORT
      LAYER M5 ;
        RECT  56.592 43.116 56.616 43.2 ;
    END
  END o_data[401]
  PIN o_data[402]
    DIRECTION OUTPUT ;
    USE SIGNAL ;
    PORT
      LAYER M5 ;
        RECT  56.736 43.116 56.76 43.2 ;
    END
  END o_data[402]
  PIN o_data[403]
    DIRECTION OUTPUT ;
    USE SIGNAL ;
    PORT
      LAYER M5 ;
        RECT  56.88 43.116 56.904 43.2 ;
    END
  END o_data[403]
  PIN o_data[404]
    DIRECTION OUTPUT ;
    USE SIGNAL ;
    PORT
      LAYER M5 ;
        RECT  57.024 43.116 57.048 43.2 ;
    END
  END o_data[404]
  PIN o_data[405]
    DIRECTION OUTPUT ;
    USE SIGNAL ;
    PORT
      LAYER M5 ;
        RECT  57.168 43.116 57.192 43.2 ;
    END
  END o_data[405]
  PIN o_data[406]
    DIRECTION OUTPUT ;
    USE SIGNAL ;
    PORT
      LAYER M5 ;
        RECT  57.312 43.116 57.336 43.2 ;
    END
  END o_data[406]
  PIN o_data[407]
    DIRECTION OUTPUT ;
    USE SIGNAL ;
    PORT
      LAYER M5 ;
        RECT  57.456 43.116 57.48 43.2 ;
    END
  END o_data[407]
  PIN o_data[408]
    DIRECTION OUTPUT ;
    USE SIGNAL ;
    PORT
      LAYER M5 ;
        RECT  57.6 43.116 57.624 43.2 ;
    END
  END o_data[408]
  PIN o_data[409]
    DIRECTION OUTPUT ;
    USE SIGNAL ;
    PORT
      LAYER M5 ;
        RECT  57.744 43.116 57.768 43.2 ;
    END
  END o_data[409]
  PIN o_data[40]
    DIRECTION OUTPUT ;
    USE SIGNAL ;
    PORT
      LAYER M5 ;
        RECT  102.528 43.116 102.552 43.2 ;
    END
  END o_data[40]
  PIN o_data[410]
    DIRECTION OUTPUT ;
    USE SIGNAL ;
    PORT
      LAYER M5 ;
        RECT  57.888 43.116 57.912 43.2 ;
    END
  END o_data[410]
  PIN o_data[411]
    DIRECTION OUTPUT ;
    USE SIGNAL ;
    PORT
      LAYER M5 ;
        RECT  58.032 43.116 58.056 43.2 ;
    END
  END o_data[411]
  PIN o_data[412]
    DIRECTION OUTPUT ;
    USE SIGNAL ;
    PORT
      LAYER M5 ;
        RECT  58.176 43.116 58.2 43.2 ;
    END
  END o_data[412]
  PIN o_data[413]
    DIRECTION OUTPUT ;
    USE SIGNAL ;
    PORT
      LAYER M5 ;
        RECT  58.32 43.116 58.344 43.2 ;
    END
  END o_data[413]
  PIN o_data[414]
    DIRECTION OUTPUT ;
    USE SIGNAL ;
    PORT
      LAYER M5 ;
        RECT  58.464 43.116 58.488 43.2 ;
    END
  END o_data[414]
  PIN o_data[415]
    DIRECTION OUTPUT ;
    USE SIGNAL ;
    PORT
      LAYER M5 ;
        RECT  58.608 43.116 58.632 43.2 ;
    END
  END o_data[415]
  PIN o_data[416]
    DIRECTION OUTPUT ;
    USE SIGNAL ;
    PORT
      LAYER M5 ;
        RECT  58.752 43.116 58.776 43.2 ;
    END
  END o_data[416]
  PIN o_data[417]
    DIRECTION OUTPUT ;
    USE SIGNAL ;
    PORT
      LAYER M5 ;
        RECT  58.896 43.116 58.92 43.2 ;
    END
  END o_data[417]
  PIN o_data[418]
    DIRECTION OUTPUT ;
    USE SIGNAL ;
    PORT
      LAYER M5 ;
        RECT  59.04 43.116 59.064 43.2 ;
    END
  END o_data[418]
  PIN o_data[419]
    DIRECTION OUTPUT ;
    USE SIGNAL ;
    PORT
      LAYER M5 ;
        RECT  59.184 43.116 59.208 43.2 ;
    END
  END o_data[419]
  PIN o_data[41]
    DIRECTION OUTPUT ;
    USE SIGNAL ;
    PORT
      LAYER M5 ;
        RECT  102.672 43.116 102.696 43.2 ;
    END
  END o_data[41]
  PIN o_data[420]
    DIRECTION OUTPUT ;
    USE SIGNAL ;
    PORT
      LAYER M5 ;
        RECT  59.328 43.116 59.352 43.2 ;
    END
  END o_data[420]
  PIN o_data[421]
    DIRECTION OUTPUT ;
    USE SIGNAL ;
    PORT
      LAYER M5 ;
        RECT  59.472 43.116 59.496 43.2 ;
    END
  END o_data[421]
  PIN o_data[422]
    DIRECTION OUTPUT ;
    USE SIGNAL ;
    PORT
      LAYER M5 ;
        RECT  59.616 43.116 59.64 43.2 ;
    END
  END o_data[422]
  PIN o_data[423]
    DIRECTION OUTPUT ;
    USE SIGNAL ;
    PORT
      LAYER M5 ;
        RECT  59.76 43.116 59.784 43.2 ;
    END
  END o_data[423]
  PIN o_data[424]
    DIRECTION OUTPUT ;
    USE SIGNAL ;
    PORT
      LAYER M5 ;
        RECT  59.904 43.116 59.928 43.2 ;
    END
  END o_data[424]
  PIN o_data[425]
    DIRECTION OUTPUT ;
    USE SIGNAL ;
    PORT
      LAYER M5 ;
        RECT  60.048 43.116 60.072 43.2 ;
    END
  END o_data[425]
  PIN o_data[426]
    DIRECTION OUTPUT ;
    USE SIGNAL ;
    PORT
      LAYER M5 ;
        RECT  60.192 43.116 60.216 43.2 ;
    END
  END o_data[426]
  PIN o_data[427]
    DIRECTION OUTPUT ;
    USE SIGNAL ;
    PORT
      LAYER M5 ;
        RECT  132.912 43.116 132.936 43.2 ;
    END
  END o_data[427]
  PIN o_data[428]
    DIRECTION OUTPUT ;
    USE SIGNAL ;
    PORT
      LAYER M5 ;
        RECT  133.056 43.116 133.08 43.2 ;
    END
  END o_data[428]
  PIN o_data[429]
    DIRECTION OUTPUT ;
    USE SIGNAL ;
    PORT
      LAYER M5 ;
        RECT  133.2 43.116 133.224 43.2 ;
    END
  END o_data[429]
  PIN o_data[42]
    DIRECTION OUTPUT ;
    USE SIGNAL ;
    PORT
      LAYER M5 ;
        RECT  102.816 43.116 102.84 43.2 ;
    END
  END o_data[42]
  PIN o_data[430]
    DIRECTION OUTPUT ;
    USE SIGNAL ;
    PORT
      LAYER M5 ;
        RECT  133.344 43.116 133.368 43.2 ;
    END
  END o_data[430]
  PIN o_data[431]
    DIRECTION OUTPUT ;
    USE SIGNAL ;
    PORT
      LAYER M5 ;
        RECT  133.488 43.116 133.512 43.2 ;
    END
  END o_data[431]
  PIN o_data[432]
    DIRECTION OUTPUT ;
    USE SIGNAL ;
    PORT
      LAYER M5 ;
        RECT  133.632 43.116 133.656 43.2 ;
    END
  END o_data[432]
  PIN o_data[433]
    DIRECTION OUTPUT ;
    USE SIGNAL ;
    PORT
      LAYER M5 ;
        RECT  133.776 43.116 133.8 43.2 ;
    END
  END o_data[433]
  PIN o_data[434]
    DIRECTION OUTPUT ;
    USE SIGNAL ;
    PORT
      LAYER M5 ;
        RECT  133.92 43.116 133.944 43.2 ;
    END
  END o_data[434]
  PIN o_data[435]
    DIRECTION OUTPUT ;
    USE SIGNAL ;
    PORT
      LAYER M5 ;
        RECT  134.064 43.116 134.088 43.2 ;
    END
  END o_data[435]
  PIN o_data[436]
    DIRECTION OUTPUT ;
    USE SIGNAL ;
    PORT
      LAYER M5 ;
        RECT  134.208 43.116 134.232 43.2 ;
    END
  END o_data[436]
  PIN o_data[437]
    DIRECTION OUTPUT ;
    USE SIGNAL ;
    PORT
      LAYER M5 ;
        RECT  134.352 43.116 134.376 43.2 ;
    END
  END o_data[437]
  PIN o_data[438]
    DIRECTION OUTPUT ;
    USE SIGNAL ;
    PORT
      LAYER M5 ;
        RECT  134.496 43.116 134.52 43.2 ;
    END
  END o_data[438]
  PIN o_data[439]
    DIRECTION OUTPUT ;
    USE SIGNAL ;
    PORT
      LAYER M5 ;
        RECT  134.64 43.116 134.664 43.2 ;
    END
  END o_data[439]
  PIN o_data[43]
    DIRECTION OUTPUT ;
    USE SIGNAL ;
    PORT
      LAYER M5 ;
        RECT  89.136 43.116 89.16 43.2 ;
    END
  END o_data[43]
  PIN o_data[440]
    DIRECTION OUTPUT ;
    USE SIGNAL ;
    PORT
      LAYER M5 ;
        RECT  134.784 43.116 134.808 43.2 ;
    END
  END o_data[440]
  PIN o_data[441]
    DIRECTION OUTPUT ;
    USE SIGNAL ;
    PORT
      LAYER M5 ;
        RECT  134.928 43.116 134.952 43.2 ;
    END
  END o_data[441]
  PIN o_data[442]
    DIRECTION OUTPUT ;
    USE SIGNAL ;
    PORT
      LAYER M5 ;
        RECT  135.072 43.116 135.096 43.2 ;
    END
  END o_data[442]
  PIN o_data[443]
    DIRECTION OUTPUT ;
    USE SIGNAL ;
    PORT
      LAYER M5 ;
        RECT  135.216 43.116 135.24 43.2 ;
    END
  END o_data[443]
  PIN o_data[444]
    DIRECTION OUTPUT ;
    USE SIGNAL ;
    PORT
      LAYER M5 ;
        RECT  135.36 43.116 135.384 43.2 ;
    END
  END o_data[444]
  PIN o_data[445]
    DIRECTION OUTPUT ;
    USE SIGNAL ;
    PORT
      LAYER M5 ;
        RECT  135.504 43.116 135.528 43.2 ;
    END
  END o_data[445]
  PIN o_data[446]
    DIRECTION OUTPUT ;
    USE SIGNAL ;
    PORT
      LAYER M5 ;
        RECT  135.648 43.116 135.672 43.2 ;
    END
  END o_data[446]
  PIN o_data[447]
    DIRECTION OUTPUT ;
    USE SIGNAL ;
    PORT
      LAYER M5 ;
        RECT  135.792 43.116 135.816 43.2 ;
    END
  END o_data[447]
  PIN o_data[448]
    DIRECTION OUTPUT ;
    USE SIGNAL ;
    PORT
      LAYER M5 ;
        RECT  135.936 43.116 135.96 43.2 ;
    END
  END o_data[448]
  PIN o_data[449]
    DIRECTION OUTPUT ;
    USE SIGNAL ;
    PORT
      LAYER M5 ;
        RECT  136.08 43.116 136.104 43.2 ;
    END
  END o_data[449]
  PIN o_data[44]
    DIRECTION OUTPUT ;
    USE SIGNAL ;
    PORT
      LAYER M5 ;
        RECT  89.28 43.116 89.304 43.2 ;
    END
  END o_data[44]
  PIN o_data[450]
    DIRECTION OUTPUT ;
    USE SIGNAL ;
    PORT
      LAYER M5 ;
        RECT  136.224 43.116 136.248 43.2 ;
    END
  END o_data[450]
  PIN o_data[451]
    DIRECTION OUTPUT ;
    USE SIGNAL ;
    PORT
      LAYER M5 ;
        RECT  136.368 43.116 136.392 43.2 ;
    END
  END o_data[451]
  PIN o_data[452]
    DIRECTION OUTPUT ;
    USE SIGNAL ;
    PORT
      LAYER M5 ;
        RECT  136.512 43.116 136.536 43.2 ;
    END
  END o_data[452]
  PIN o_data[453]
    DIRECTION OUTPUT ;
    USE SIGNAL ;
    PORT
      LAYER M5 ;
        RECT  136.656 43.116 136.68 43.2 ;
    END
  END o_data[453]
  PIN o_data[454]
    DIRECTION OUTPUT ;
    USE SIGNAL ;
    PORT
      LAYER M5 ;
        RECT  136.8 43.116 136.824 43.2 ;
    END
  END o_data[454]
  PIN o_data[455]
    DIRECTION OUTPUT ;
    USE SIGNAL ;
    PORT
      LAYER M5 ;
        RECT  136.944 43.116 136.968 43.2 ;
    END
  END o_data[455]
  PIN o_data[456]
    DIRECTION OUTPUT ;
    USE SIGNAL ;
    PORT
      LAYER M5 ;
        RECT  137.088 43.116 137.112 43.2 ;
    END
  END o_data[456]
  PIN o_data[457]
    DIRECTION OUTPUT ;
    USE SIGNAL ;
    PORT
      LAYER M5 ;
        RECT  137.232 43.116 137.256 43.2 ;
    END
  END o_data[457]
  PIN o_data[458]
    DIRECTION OUTPUT ;
    USE SIGNAL ;
    PORT
      LAYER M5 ;
        RECT  137.376 43.116 137.4 43.2 ;
    END
  END o_data[458]
  PIN o_data[459]
    DIRECTION OUTPUT ;
    USE SIGNAL ;
    PORT
      LAYER M5 ;
        RECT  64.944 43.116 64.968 43.2 ;
    END
  END o_data[459]
  PIN o_data[45]
    DIRECTION OUTPUT ;
    USE SIGNAL ;
    PORT
      LAYER M5 ;
        RECT  89.424 43.116 89.448 43.2 ;
    END
  END o_data[45]
  PIN o_data[460]
    DIRECTION OUTPUT ;
    USE SIGNAL ;
    PORT
      LAYER M5 ;
        RECT  65.088 43.116 65.112 43.2 ;
    END
  END o_data[460]
  PIN o_data[461]
    DIRECTION OUTPUT ;
    USE SIGNAL ;
    PORT
      LAYER M5 ;
        RECT  65.232 43.116 65.256 43.2 ;
    END
  END o_data[461]
  PIN o_data[462]
    DIRECTION OUTPUT ;
    USE SIGNAL ;
    PORT
      LAYER M5 ;
        RECT  65.376 43.116 65.4 43.2 ;
    END
  END o_data[462]
  PIN o_data[463]
    DIRECTION OUTPUT ;
    USE SIGNAL ;
    PORT
      LAYER M5 ;
        RECT  65.52 43.116 65.544 43.2 ;
    END
  END o_data[463]
  PIN o_data[464]
    DIRECTION OUTPUT ;
    USE SIGNAL ;
    PORT
      LAYER M5 ;
        RECT  65.664 43.116 65.688 43.2 ;
    END
  END o_data[464]
  PIN o_data[465]
    DIRECTION OUTPUT ;
    USE SIGNAL ;
    PORT
      LAYER M5 ;
        RECT  65.808 43.116 65.832 43.2 ;
    END
  END o_data[465]
  PIN o_data[466]
    DIRECTION OUTPUT ;
    USE SIGNAL ;
    PORT
      LAYER M5 ;
        RECT  65.952 43.116 65.976 43.2 ;
    END
  END o_data[466]
  PIN o_data[467]
    DIRECTION OUTPUT ;
    USE SIGNAL ;
    PORT
      LAYER M5 ;
        RECT  66.096 43.116 66.12 43.2 ;
    END
  END o_data[467]
  PIN o_data[468]
    DIRECTION OUTPUT ;
    USE SIGNAL ;
    PORT
      LAYER M5 ;
        RECT  66.24 43.116 66.264 43.2 ;
    END
  END o_data[468]
  PIN o_data[469]
    DIRECTION OUTPUT ;
    USE SIGNAL ;
    PORT
      LAYER M5 ;
        RECT  66.384 43.116 66.408 43.2 ;
    END
  END o_data[469]
  PIN o_data[46]
    DIRECTION OUTPUT ;
    USE SIGNAL ;
    PORT
      LAYER M5 ;
        RECT  89.568 43.116 89.592 43.2 ;
    END
  END o_data[46]
  PIN o_data[470]
    DIRECTION OUTPUT ;
    USE SIGNAL ;
    PORT
      LAYER M5 ;
        RECT  66.528 43.116 66.552 43.2 ;
    END
  END o_data[470]
  PIN o_data[471]
    DIRECTION OUTPUT ;
    USE SIGNAL ;
    PORT
      LAYER M5 ;
        RECT  66.672 43.116 66.696 43.2 ;
    END
  END o_data[471]
  PIN o_data[472]
    DIRECTION OUTPUT ;
    USE SIGNAL ;
    PORT
      LAYER M5 ;
        RECT  66.816 43.116 66.84 43.2 ;
    END
  END o_data[472]
  PIN o_data[473]
    DIRECTION OUTPUT ;
    USE SIGNAL ;
    PORT
      LAYER M5 ;
        RECT  66.96 43.116 66.984 43.2 ;
    END
  END o_data[473]
  PIN o_data[474]
    DIRECTION OUTPUT ;
    USE SIGNAL ;
    PORT
      LAYER M5 ;
        RECT  67.104 43.116 67.128 43.2 ;
    END
  END o_data[474]
  PIN o_data[475]
    DIRECTION OUTPUT ;
    USE SIGNAL ;
    PORT
      LAYER M5 ;
        RECT  67.248 43.116 67.272 43.2 ;
    END
  END o_data[475]
  PIN o_data[476]
    DIRECTION OUTPUT ;
    USE SIGNAL ;
    PORT
      LAYER M5 ;
        RECT  67.392 43.116 67.416 43.2 ;
    END
  END o_data[476]
  PIN o_data[477]
    DIRECTION OUTPUT ;
    USE SIGNAL ;
    PORT
      LAYER M5 ;
        RECT  67.536 43.116 67.56 43.2 ;
    END
  END o_data[477]
  PIN o_data[478]
    DIRECTION OUTPUT ;
    USE SIGNAL ;
    PORT
      LAYER M5 ;
        RECT  67.68 43.116 67.704 43.2 ;
    END
  END o_data[478]
  PIN o_data[479]
    DIRECTION OUTPUT ;
    USE SIGNAL ;
    PORT
      LAYER M5 ;
        RECT  67.824 43.116 67.848 43.2 ;
    END
  END o_data[479]
  PIN o_data[47]
    DIRECTION OUTPUT ;
    USE SIGNAL ;
    PORT
      LAYER M5 ;
        RECT  89.712 43.116 89.736 43.2 ;
    END
  END o_data[47]
  PIN o_data[480]
    DIRECTION OUTPUT ;
    USE SIGNAL ;
    PORT
      LAYER M5 ;
        RECT  67.968 43.116 67.992 43.2 ;
    END
  END o_data[480]
  PIN o_data[481]
    DIRECTION OUTPUT ;
    USE SIGNAL ;
    PORT
      LAYER M5 ;
        RECT  68.112 43.116 68.136 43.2 ;
    END
  END o_data[481]
  PIN o_data[482]
    DIRECTION OUTPUT ;
    USE SIGNAL ;
    PORT
      LAYER M5 ;
        RECT  68.256 43.116 68.28 43.2 ;
    END
  END o_data[482]
  PIN o_data[483]
    DIRECTION OUTPUT ;
    USE SIGNAL ;
    PORT
      LAYER M5 ;
        RECT  68.4 43.116 68.424 43.2 ;
    END
  END o_data[483]
  PIN o_data[484]
    DIRECTION OUTPUT ;
    USE SIGNAL ;
    PORT
      LAYER M5 ;
        RECT  68.544 43.116 68.568 43.2 ;
    END
  END o_data[484]
  PIN o_data[485]
    DIRECTION OUTPUT ;
    USE SIGNAL ;
    PORT
      LAYER M5 ;
        RECT  68.688 43.116 68.712 43.2 ;
    END
  END o_data[485]
  PIN o_data[486]
    DIRECTION OUTPUT ;
    USE SIGNAL ;
    PORT
      LAYER M5 ;
        RECT  68.832 43.116 68.856 43.2 ;
    END
  END o_data[486]
  PIN o_data[487]
    DIRECTION OUTPUT ;
    USE SIGNAL ;
    PORT
      LAYER M5 ;
        RECT  68.976 43.116 69 43.2 ;
    END
  END o_data[487]
  PIN o_data[488]
    DIRECTION OUTPUT ;
    USE SIGNAL ;
    PORT
      LAYER M5 ;
        RECT  69.12 43.116 69.144 43.2 ;
    END
  END o_data[488]
  PIN o_data[489]
    DIRECTION OUTPUT ;
    USE SIGNAL ;
    PORT
      LAYER M5 ;
        RECT  69.264 43.116 69.288 43.2 ;
    END
  END o_data[489]
  PIN o_data[48]
    DIRECTION OUTPUT ;
    USE SIGNAL ;
    PORT
      LAYER M5 ;
        RECT  89.856 43.116 89.88 43.2 ;
    END
  END o_data[48]
  PIN o_data[490]
    DIRECTION OUTPUT ;
    USE SIGNAL ;
    PORT
      LAYER M5 ;
        RECT  69.408 43.116 69.432 43.2 ;
    END
  END o_data[490]
  PIN o_data[491]
    DIRECTION OUTPUT ;
    USE SIGNAL ;
    PORT
      LAYER M5 ;
        RECT  69.552 43.116 69.576 43.2 ;
    END
  END o_data[491]
  PIN o_data[492]
    DIRECTION OUTPUT ;
    USE SIGNAL ;
    PORT
      LAYER M5 ;
        RECT  69.696 43.116 69.72 43.2 ;
    END
  END o_data[492]
  PIN o_data[493]
    DIRECTION OUTPUT ;
    USE SIGNAL ;
    PORT
      LAYER M5 ;
        RECT  69.84 43.116 69.864 43.2 ;
    END
  END o_data[493]
  PIN o_data[494]
    DIRECTION OUTPUT ;
    USE SIGNAL ;
    PORT
      LAYER M5 ;
        RECT  69.984 43.116 70.008 43.2 ;
    END
  END o_data[494]
  PIN o_data[495]
    DIRECTION OUTPUT ;
    USE SIGNAL ;
    PORT
      LAYER M5 ;
        RECT  70.128 43.116 70.152 43.2 ;
    END
  END o_data[495]
  PIN o_data[496]
    DIRECTION OUTPUT ;
    USE SIGNAL ;
    PORT
      LAYER M5 ;
        RECT  70.272 43.116 70.296 43.2 ;
    END
  END o_data[496]
  PIN o_data[497]
    DIRECTION OUTPUT ;
    USE SIGNAL ;
    PORT
      LAYER M5 ;
        RECT  70.416 43.116 70.44 43.2 ;
    END
  END o_data[497]
  PIN o_data[498]
    DIRECTION OUTPUT ;
    USE SIGNAL ;
    PORT
      LAYER M5 ;
        RECT  70.56 43.116 70.584 43.2 ;
    END
  END o_data[498]
  PIN o_data[499]
    DIRECTION OUTPUT ;
    USE SIGNAL ;
    PORT
      LAYER M5 ;
        RECT  70.704 43.116 70.728 43.2 ;
    END
  END o_data[499]
  PIN o_data[49]
    DIRECTION OUTPUT ;
    USE SIGNAL ;
    PORT
      LAYER M5 ;
        RECT  90 43.116 90.024 43.2 ;
    END
  END o_data[49]
  PIN o_data[4]
    DIRECTION OUTPUT ;
    USE SIGNAL ;
    PORT
      LAYER M5 ;
        RECT  130.752 43.116 130.776 43.2 ;
    END
  END o_data[4]
  PIN o_data[500]
    DIRECTION OUTPUT ;
    USE SIGNAL ;
    PORT
      LAYER M5 ;
        RECT  70.848 43.116 70.872 43.2 ;
    END
  END o_data[500]
  PIN o_data[501]
    DIRECTION OUTPUT ;
    USE SIGNAL ;
    PORT
      LAYER M5 ;
        RECT  70.992 43.116 71.016 43.2 ;
    END
  END o_data[501]
  PIN o_data[502]
    DIRECTION OUTPUT ;
    USE SIGNAL ;
    PORT
      LAYER M5 ;
        RECT  71.136 43.116 71.16 43.2 ;
    END
  END o_data[502]
  PIN o_data[503]
    DIRECTION OUTPUT ;
    USE SIGNAL ;
    PORT
      LAYER M5 ;
        RECT  71.28 43.116 71.304 43.2 ;
    END
  END o_data[503]
  PIN o_data[504]
    DIRECTION OUTPUT ;
    USE SIGNAL ;
    PORT
      LAYER M5 ;
        RECT  71.424 43.116 71.448 43.2 ;
    END
  END o_data[504]
  PIN o_data[505]
    DIRECTION OUTPUT ;
    USE SIGNAL ;
    PORT
      LAYER M5 ;
        RECT  71.568 43.116 71.592 43.2 ;
    END
  END o_data[505]
  PIN o_data[506]
    DIRECTION OUTPUT ;
    USE SIGNAL ;
    PORT
      LAYER M5 ;
        RECT  71.712 43.116 71.736 43.2 ;
    END
  END o_data[506]
  PIN o_data[507]
    DIRECTION OUTPUT ;
    USE SIGNAL ;
    PORT
      LAYER M5 ;
        RECT  71.856 43.116 71.88 43.2 ;
    END
  END o_data[507]
  PIN o_data[508]
    DIRECTION OUTPUT ;
    USE SIGNAL ;
    PORT
      LAYER M5 ;
        RECT  72 43.116 72.024 43.2 ;
    END
  END o_data[508]
  PIN o_data[509]
    DIRECTION OUTPUT ;
    USE SIGNAL ;
    PORT
      LAYER M5 ;
        RECT  72.144 43.116 72.168 43.2 ;
    END
  END o_data[509]
  PIN o_data[50]
    DIRECTION OUTPUT ;
    USE SIGNAL ;
    PORT
      LAYER M5 ;
        RECT  90.144 43.116 90.168 43.2 ;
    END
  END o_data[50]
  PIN o_data[510]
    DIRECTION OUTPUT ;
    USE SIGNAL ;
    PORT
      LAYER M5 ;
        RECT  72.288 43.116 72.312 43.2 ;
    END
  END o_data[510]
  PIN o_data[511]
    DIRECTION OUTPUT ;
    USE SIGNAL ;
    PORT
      LAYER M5 ;
        RECT  72.432 43.116 72.456 43.2 ;
    END
  END o_data[511]
  PIN o_data[51]
    DIRECTION OUTPUT ;
    USE SIGNAL ;
    PORT
      LAYER M5 ;
        RECT  90.288 43.116 90.312 43.2 ;
    END
  END o_data[51]
  PIN o_data[52]
    DIRECTION OUTPUT ;
    USE SIGNAL ;
    PORT
      LAYER M5 ;
        RECT  90.432 43.116 90.456 43.2 ;
    END
  END o_data[52]
  PIN o_data[53]
    DIRECTION OUTPUT ;
    USE SIGNAL ;
    PORT
      LAYER M5 ;
        RECT  90.576 43.116 90.6 43.2 ;
    END
  END o_data[53]
  PIN o_data[54]
    DIRECTION OUTPUT ;
    USE SIGNAL ;
    PORT
      LAYER M5 ;
        RECT  90.72 43.116 90.744 43.2 ;
    END
  END o_data[54]
  PIN o_data[55]
    DIRECTION OUTPUT ;
    USE SIGNAL ;
    PORT
      LAYER M5 ;
        RECT  90.864 43.116 90.888 43.2 ;
    END
  END o_data[55]
  PIN o_data[56]
    DIRECTION OUTPUT ;
    USE SIGNAL ;
    PORT
      LAYER M5 ;
        RECT  91.008 43.116 91.032 43.2 ;
    END
  END o_data[56]
  PIN o_data[57]
    DIRECTION OUTPUT ;
    USE SIGNAL ;
    PORT
      LAYER M5 ;
        RECT  91.152 43.116 91.176 43.2 ;
    END
  END o_data[57]
  PIN o_data[58]
    DIRECTION OUTPUT ;
    USE SIGNAL ;
    PORT
      LAYER M5 ;
        RECT  91.296 43.116 91.32 43.2 ;
    END
  END o_data[58]
  PIN o_data[59]
    DIRECTION OUTPUT ;
    USE SIGNAL ;
    PORT
      LAYER M5 ;
        RECT  91.44 43.116 91.464 43.2 ;
    END
  END o_data[59]
  PIN o_data[5]
    DIRECTION OUTPUT ;
    USE SIGNAL ;
    PORT
      LAYER M5 ;
        RECT  130.896 43.116 130.92 43.2 ;
    END
  END o_data[5]
  PIN o_data[60]
    DIRECTION OUTPUT ;
    USE SIGNAL ;
    PORT
      LAYER M5 ;
        RECT  91.584 43.116 91.608 43.2 ;
    END
  END o_data[60]
  PIN o_data[61]
    DIRECTION OUTPUT ;
    USE SIGNAL ;
    PORT
      LAYER M5 ;
        RECT  91.728 43.116 91.752 43.2 ;
    END
  END o_data[61]
  PIN o_data[62]
    DIRECTION OUTPUT ;
    USE SIGNAL ;
    PORT
      LAYER M5 ;
        RECT  91.872 43.116 91.896 43.2 ;
    END
  END o_data[62]
  PIN o_data[63]
    DIRECTION OUTPUT ;
    USE SIGNAL ;
    PORT
      LAYER M5 ;
        RECT  92.016 43.116 92.04 43.2 ;
    END
  END o_data[63]
  PIN o_data[64]
    DIRECTION OUTPUT ;
    USE SIGNAL ;
    PORT
      LAYER M5 ;
        RECT  92.16 43.116 92.184 43.2 ;
    END
  END o_data[64]
  PIN o_data[65]
    DIRECTION OUTPUT ;
    USE SIGNAL ;
    PORT
      LAYER M5 ;
        RECT  92.304 43.116 92.328 43.2 ;
    END
  END o_data[65]
  PIN o_data[66]
    DIRECTION OUTPUT ;
    USE SIGNAL ;
    PORT
      LAYER M5 ;
        RECT  92.448 43.116 92.472 43.2 ;
    END
  END o_data[66]
  PIN o_data[67]
    DIRECTION OUTPUT ;
    USE SIGNAL ;
    PORT
      LAYER M5 ;
        RECT  92.592 43.116 92.616 43.2 ;
    END
  END o_data[67]
  PIN o_data[68]
    DIRECTION OUTPUT ;
    USE SIGNAL ;
    PORT
      LAYER M5 ;
        RECT  92.736 43.116 92.76 43.2 ;
    END
  END o_data[68]
  PIN o_data[69]
    DIRECTION OUTPUT ;
    USE SIGNAL ;
    PORT
      LAYER M5 ;
        RECT  92.88 43.116 92.904 43.2 ;
    END
  END o_data[69]
  PIN o_data[6]
    DIRECTION OUTPUT ;
    USE SIGNAL ;
    PORT
      LAYER M5 ;
        RECT  131.04 43.116 131.064 43.2 ;
    END
  END o_data[6]
  PIN o_data[70]
    DIRECTION OUTPUT ;
    USE SIGNAL ;
    PORT
      LAYER M5 ;
        RECT  93.024 43.116 93.048 43.2 ;
    END
  END o_data[70]
  PIN o_data[71]
    DIRECTION OUTPUT ;
    USE SIGNAL ;
    PORT
      LAYER M5 ;
        RECT  93.168 43.116 93.192 43.2 ;
    END
  END o_data[71]
  PIN o_data[72]
    DIRECTION OUTPUT ;
    USE SIGNAL ;
    PORT
      LAYER M5 ;
        RECT  93.312 43.116 93.336 43.2 ;
    END
  END o_data[72]
  PIN o_data[73]
    DIRECTION OUTPUT ;
    USE SIGNAL ;
    PORT
      LAYER M5 ;
        RECT  93.456 43.116 93.48 43.2 ;
    END
  END o_data[73]
  PIN o_data[74]
    DIRECTION OUTPUT ;
    USE SIGNAL ;
    PORT
      LAYER M5 ;
        RECT  93.6 43.116 93.624 43.2 ;
    END
  END o_data[74]
  PIN o_data[75]
    DIRECTION OUTPUT ;
    USE SIGNAL ;
    PORT
      LAYER M5 ;
        RECT  75.312 43.116 75.336 43.2 ;
    END
  END o_data[75]
  PIN o_data[76]
    DIRECTION OUTPUT ;
    USE SIGNAL ;
    PORT
      LAYER M5 ;
        RECT  75.456 43.116 75.48 43.2 ;
    END
  END o_data[76]
  PIN o_data[77]
    DIRECTION OUTPUT ;
    USE SIGNAL ;
    PORT
      LAYER M5 ;
        RECT  75.6 43.116 75.624 43.2 ;
    END
  END o_data[77]
  PIN o_data[78]
    DIRECTION OUTPUT ;
    USE SIGNAL ;
    PORT
      LAYER M5 ;
        RECT  75.744 43.116 75.768 43.2 ;
    END
  END o_data[78]
  PIN o_data[79]
    DIRECTION OUTPUT ;
    USE SIGNAL ;
    PORT
      LAYER M5 ;
        RECT  75.888 43.116 75.912 43.2 ;
    END
  END o_data[79]
  PIN o_data[7]
    DIRECTION OUTPUT ;
    USE SIGNAL ;
    PORT
      LAYER M5 ;
        RECT  131.184 43.116 131.208 43.2 ;
    END
  END o_data[7]
  PIN o_data[80]
    DIRECTION OUTPUT ;
    USE SIGNAL ;
    PORT
      LAYER M5 ;
        RECT  76.032 43.116 76.056 43.2 ;
    END
  END o_data[80]
  PIN o_data[81]
    DIRECTION OUTPUT ;
    USE SIGNAL ;
    PORT
      LAYER M5 ;
        RECT  76.176 43.116 76.2 43.2 ;
    END
  END o_data[81]
  PIN o_data[82]
    DIRECTION OUTPUT ;
    USE SIGNAL ;
    PORT
      LAYER M5 ;
        RECT  76.32 43.116 76.344 43.2 ;
    END
  END o_data[82]
  PIN o_data[83]
    DIRECTION OUTPUT ;
    USE SIGNAL ;
    PORT
      LAYER M5 ;
        RECT  76.464 43.116 76.488 43.2 ;
    END
  END o_data[83]
  PIN o_data[84]
    DIRECTION OUTPUT ;
    USE SIGNAL ;
    PORT
      LAYER M5 ;
        RECT  76.608 43.116 76.632 43.2 ;
    END
  END o_data[84]
  PIN o_data[85]
    DIRECTION OUTPUT ;
    USE SIGNAL ;
    PORT
      LAYER M5 ;
        RECT  76.752 43.116 76.776 43.2 ;
    END
  END o_data[85]
  PIN o_data[86]
    DIRECTION OUTPUT ;
    USE SIGNAL ;
    PORT
      LAYER M5 ;
        RECT  76.896 43.116 76.92 43.2 ;
    END
  END o_data[86]
  PIN o_data[87]
    DIRECTION OUTPUT ;
    USE SIGNAL ;
    PORT
      LAYER M5 ;
        RECT  77.04 43.116 77.064 43.2 ;
    END
  END o_data[87]
  PIN o_data[88]
    DIRECTION OUTPUT ;
    USE SIGNAL ;
    PORT
      LAYER M5 ;
        RECT  77.184 43.116 77.208 43.2 ;
    END
  END o_data[88]
  PIN o_data[89]
    DIRECTION OUTPUT ;
    USE SIGNAL ;
    PORT
      LAYER M5 ;
        RECT  77.328 43.116 77.352 43.2 ;
    END
  END o_data[89]
  PIN o_data[8]
    DIRECTION OUTPUT ;
    USE SIGNAL ;
    PORT
      LAYER M5 ;
        RECT  131.328 43.116 131.352 43.2 ;
    END
  END o_data[8]
  PIN o_data[90]
    DIRECTION OUTPUT ;
    USE SIGNAL ;
    PORT
      LAYER M5 ;
        RECT  77.472 43.116 77.496 43.2 ;
    END
  END o_data[90]
  PIN o_data[91]
    DIRECTION OUTPUT ;
    USE SIGNAL ;
    PORT
      LAYER M5 ;
        RECT  77.616 43.116 77.64 43.2 ;
    END
  END o_data[91]
  PIN o_data[92]
    DIRECTION OUTPUT ;
    USE SIGNAL ;
    PORT
      LAYER M5 ;
        RECT  77.76 43.116 77.784 43.2 ;
    END
  END o_data[92]
  PIN o_data[93]
    DIRECTION OUTPUT ;
    USE SIGNAL ;
    PORT
      LAYER M5 ;
        RECT  77.904 43.116 77.928 43.2 ;
    END
  END o_data[93]
  PIN o_data[94]
    DIRECTION OUTPUT ;
    USE SIGNAL ;
    PORT
      LAYER M5 ;
        RECT  78.048 43.116 78.072 43.2 ;
    END
  END o_data[94]
  PIN o_data[95]
    DIRECTION OUTPUT ;
    USE SIGNAL ;
    PORT
      LAYER M5 ;
        RECT  78.192 43.116 78.216 43.2 ;
    END
  END o_data[95]
  PIN o_data[96]
    DIRECTION OUTPUT ;
    USE SIGNAL ;
    PORT
      LAYER M5 ;
        RECT  78.336 43.116 78.36 43.2 ;
    END
  END o_data[96]
  PIN o_data[97]
    DIRECTION OUTPUT ;
    USE SIGNAL ;
    PORT
      LAYER M5 ;
        RECT  78.48 43.116 78.504 43.2 ;
    END
  END o_data[97]
  PIN o_data[98]
    DIRECTION OUTPUT ;
    USE SIGNAL ;
    PORT
      LAYER M5 ;
        RECT  78.624 43.116 78.648 43.2 ;
    END
  END o_data[98]
  PIN o_data[99]
    DIRECTION OUTPUT ;
    USE SIGNAL ;
    PORT
      LAYER M5 ;
        RECT  78.768 43.116 78.792 43.2 ;
    END
  END o_data[99]
  PIN o_data[9]
    DIRECTION OUTPUT ;
    USE SIGNAL ;
    PORT
      LAYER M5 ;
        RECT  131.472 43.116 131.496 43.2 ;
    END
  END o_data[9]
  PIN o_epoch[0]
    DIRECTION OUTPUT ;
    USE SIGNAL ;
    PORT
      LAYER M5 ;
        RECT  72.576 43.116 72.6 43.2 ;
    END
  END o_epoch[0]
  PIN o_epoch[10]
    DIRECTION OUTPUT ;
    USE SIGNAL ;
    PORT
      LAYER M5 ;
        RECT  74.016 43.116 74.04 43.2 ;
    END
  END o_epoch[10]
  PIN o_epoch[11]
    DIRECTION OUTPUT ;
    USE SIGNAL ;
    PORT
      LAYER M5 ;
        RECT  103.248 43.116 103.272 43.2 ;
    END
  END o_epoch[11]
  PIN o_epoch[12]
    DIRECTION OUTPUT ;
    USE SIGNAL ;
    PORT
      LAYER M5 ;
        RECT  103.392 43.116 103.416 43.2 ;
    END
  END o_epoch[12]
  PIN o_epoch[13]
    DIRECTION OUTPUT ;
    USE SIGNAL ;
    PORT
      LAYER M5 ;
        RECT  103.536 43.116 103.56 43.2 ;
    END
  END o_epoch[13]
  PIN o_epoch[14]
    DIRECTION OUTPUT ;
    USE SIGNAL ;
    PORT
      LAYER M5 ;
        RECT  103.68 43.116 103.704 43.2 ;
    END
  END o_epoch[14]
  PIN o_epoch[15]
    DIRECTION OUTPUT ;
    USE SIGNAL ;
    PORT
      LAYER M5 ;
        RECT  103.824 43.116 103.848 43.2 ;
    END
  END o_epoch[15]
  PIN o_epoch[1]
    DIRECTION OUTPUT ;
    USE SIGNAL ;
    PORT
      LAYER M5 ;
        RECT  72.72 43.116 72.744 43.2 ;
    END
  END o_epoch[1]
  PIN o_epoch[2]
    DIRECTION OUTPUT ;
    USE SIGNAL ;
    PORT
      LAYER M5 ;
        RECT  72.864 43.116 72.888 43.2 ;
    END
  END o_epoch[2]
  PIN o_epoch[3]
    DIRECTION OUTPUT ;
    USE SIGNAL ;
    PORT
      LAYER M5 ;
        RECT  73.008 43.116 73.032 43.2 ;
    END
  END o_epoch[3]
  PIN o_epoch[4]
    DIRECTION OUTPUT ;
    USE SIGNAL ;
    PORT
      LAYER M5 ;
        RECT  73.152 43.116 73.176 43.2 ;
    END
  END o_epoch[4]
  PIN o_epoch[5]
    DIRECTION OUTPUT ;
    USE SIGNAL ;
    PORT
      LAYER M5 ;
        RECT  73.296 43.116 73.32 43.2 ;
    END
  END o_epoch[5]
  PIN o_epoch[6]
    DIRECTION OUTPUT ;
    USE SIGNAL ;
    PORT
      LAYER M5 ;
        RECT  73.44 43.116 73.464 43.2 ;
    END
  END o_epoch[6]
  PIN o_epoch[7]
    DIRECTION OUTPUT ;
    USE SIGNAL ;
    PORT
      LAYER M5 ;
        RECT  73.584 43.116 73.608 43.2 ;
    END
  END o_epoch[7]
  PIN o_epoch[8]
    DIRECTION OUTPUT ;
    USE SIGNAL ;
    PORT
      LAYER M5 ;
        RECT  73.728 43.116 73.752 43.2 ;
    END
  END o_epoch[8]
  PIN o_epoch[9]
    DIRECTION OUTPUT ;
    USE SIGNAL ;
    PORT
      LAYER M5 ;
        RECT  73.872 43.116 73.896 43.2 ;
    END
  END o_epoch[9]
  PIN o_valid
    DIRECTION OUTPUT ;
    USE SIGNAL ;
    PORT
      LAYER M5 ;
        RECT  103.968 43.116 103.992 43.2 ;
    END
  END o_valid
  PIN VDD
    DIRECTION INOUT ;
    USE POWER ;
    PORT
      LAYER M5 ;
        RECT  186.192 2.151 186.312 41.049 ;
        RECT  183.492 2.151 183.612 41.049 ;
        RECT  180.792 2.151 180.912 41.049 ;
        RECT  178.092 2.151 178.212 41.049 ;
        RECT  175.392 2.151 175.512 41.049 ;
        RECT  172.692 2.151 172.812 41.049 ;
        RECT  169.992 2.151 170.112 41.049 ;
        RECT  167.292 2.151 167.412 41.049 ;
        RECT  164.592 2.151 164.712 41.049 ;
        RECT  161.892 2.151 162.012 41.049 ;
        RECT  159.192 2.151 159.312 41.049 ;
        RECT  156.492 2.151 156.612 41.049 ;
        RECT  153.792 2.151 153.912 41.049 ;
        RECT  151.092 2.151 151.212 41.049 ;
        RECT  148.392 2.151 148.512 41.049 ;
        RECT  145.692 2.151 145.812 41.049 ;
        RECT  142.992 2.151 143.112 41.049 ;
        RECT  140.292 2.151 140.412 41.049 ;
        RECT  137.592 2.151 137.712 41.049 ;
        RECT  134.892 2.151 135.012 41.049 ;
        RECT  132.192 2.151 132.312 41.049 ;
        RECT  129.492 2.151 129.612 41.049 ;
        RECT  126.792 2.151 126.912 41.049 ;
        RECT  124.092 2.151 124.212 41.049 ;
        RECT  121.392 2.151 121.512 41.049 ;
        RECT  118.692 2.151 118.812 41.049 ;
        RECT  115.992 2.151 116.112 41.049 ;
        RECT  113.292 2.151 113.412 41.049 ;
        RECT  110.592 2.151 110.712 41.049 ;
        RECT  107.892 2.151 108.012 41.049 ;
        RECT  105.192 2.151 105.312 41.049 ;
        RECT  102.492 2.151 102.612 41.049 ;
        RECT  99.792 2.151 99.912 41.049 ;
        RECT  97.092 2.151 97.212 41.049 ;
        RECT  94.392 2.151 94.512 41.049 ;
        RECT  91.692 2.151 91.812 41.049 ;
        RECT  88.992 2.151 89.112 41.049 ;
        RECT  86.292 2.151 86.412 41.049 ;
        RECT  83.592 2.151 83.712 41.049 ;
        RECT  80.892 2.151 81.012 41.049 ;
        RECT  78.192 2.151 78.312 41.049 ;
        RECT  75.492 2.151 75.612 41.049 ;
        RECT  72.792 2.151 72.912 41.049 ;
        RECT  70.092 2.151 70.212 41.049 ;
        RECT  67.392 2.151 67.512 41.049 ;
        RECT  64.692 2.151 64.812 41.049 ;
        RECT  61.992 2.151 62.112 41.049 ;
        RECT  59.292 2.151 59.412 41.049 ;
        RECT  56.592 2.151 56.712 41.049 ;
        RECT  53.892 2.151 54.012 41.049 ;
        RECT  51.192 2.151 51.312 41.049 ;
        RECT  48.492 2.151 48.612 41.049 ;
        RECT  45.792 2.151 45.912 41.049 ;
        RECT  43.092 2.151 43.212 41.049 ;
        RECT  40.392 2.151 40.512 41.049 ;
        RECT  37.692 2.151 37.812 41.049 ;
        RECT  34.992 2.151 35.112 41.049 ;
        RECT  32.292 2.151 32.412 41.049 ;
        RECT  29.592 2.151 29.712 41.049 ;
        RECT  26.892 2.151 27.012 41.049 ;
        RECT  24.192 2.151 24.312 41.049 ;
        RECT  21.492 2.151 21.612 41.049 ;
        RECT  18.792 2.151 18.912 41.049 ;
        RECT  16.092 2.151 16.212 41.049 ;
        RECT  13.392 2.151 13.512 41.049 ;
        RECT  10.692 2.151 10.812 41.049 ;
        RECT  7.992 2.151 8.112 41.049 ;
        RECT  5.292 2.151 5.412 41.049 ;
        RECT  2.592 2.151 2.712 41.049 ;
    END
  END VDD
  PIN VSS
    DIRECTION INOUT ;
    USE GROUND ;
    PORT
      LAYER M5 ;
        RECT  186 2.137 186.12 41.063 ;
        RECT  183.3 2.137 183.42 41.063 ;
        RECT  180.6 2.137 180.72 41.063 ;
        RECT  177.9 2.137 178.02 41.063 ;
        RECT  175.2 2.137 175.32 41.063 ;
        RECT  172.5 2.137 172.62 41.063 ;
        RECT  169.8 2.137 169.92 41.063 ;
        RECT  167.1 2.137 167.22 41.063 ;
        RECT  164.4 2.137 164.52 41.063 ;
        RECT  161.7 2.137 161.82 41.063 ;
        RECT  159 2.137 159.12 41.063 ;
        RECT  156.3 2.137 156.42 41.063 ;
        RECT  153.6 2.137 153.72 41.063 ;
        RECT  150.9 2.137 151.02 41.063 ;
        RECT  148.2 2.137 148.32 41.063 ;
        RECT  145.5 2.137 145.62 41.063 ;
        RECT  142.8 2.137 142.92 41.063 ;
        RECT  140.1 2.137 140.22 41.063 ;
        RECT  137.4 2.137 137.52 41.063 ;
        RECT  134.7 2.137 134.82 41.063 ;
        RECT  132 2.137 132.12 41.063 ;
        RECT  129.3 2.137 129.42 41.063 ;
        RECT  126.6 2.137 126.72 41.063 ;
        RECT  123.9 2.137 124.02 41.063 ;
        RECT  121.2 2.137 121.32 41.063 ;
        RECT  118.5 2.137 118.62 41.063 ;
        RECT  115.8 2.137 115.92 41.063 ;
        RECT  113.1 2.137 113.22 41.063 ;
        RECT  110.4 2.137 110.52 41.063 ;
        RECT  107.7 2.137 107.82 41.063 ;
        RECT  105 2.137 105.12 41.063 ;
        RECT  102.3 2.137 102.42 41.063 ;
        RECT  99.6 2.137 99.72 41.063 ;
        RECT  96.9 2.137 97.02 41.063 ;
        RECT  94.2 2.137 94.32 41.063 ;
        RECT  91.5 2.137 91.62 41.063 ;
        RECT  88.8 2.137 88.92 41.063 ;
        RECT  86.1 2.137 86.22 41.063 ;
        RECT  83.4 2.137 83.52 41.063 ;
        RECT  80.7 2.137 80.82 41.063 ;
        RECT  78 2.137 78.12 41.063 ;
        RECT  75.3 2.137 75.42 41.063 ;
        RECT  72.6 2.137 72.72 41.063 ;
        RECT  69.9 2.137 70.02 41.063 ;
        RECT  67.2 2.137 67.32 41.063 ;
        RECT  64.5 2.137 64.62 41.063 ;
        RECT  61.8 2.137 61.92 41.063 ;
        RECT  59.1 2.137 59.22 41.063 ;
        RECT  56.4 2.137 56.52 41.063 ;
        RECT  53.7 2.137 53.82 41.063 ;
        RECT  51 2.137 51.12 41.063 ;
        RECT  48.3 2.137 48.42 41.063 ;
        RECT  45.6 2.137 45.72 41.063 ;
        RECT  42.9 2.137 43.02 41.063 ;
        RECT  40.2 2.137 40.32 41.063 ;
        RECT  37.5 2.137 37.62 41.063 ;
        RECT  34.8 2.137 34.92 41.063 ;
        RECT  32.1 2.137 32.22 41.063 ;
        RECT  29.4 2.137 29.52 41.063 ;
        RECT  26.7 2.137 26.82 41.063 ;
        RECT  24 2.137 24.12 41.063 ;
        RECT  21.3 2.137 21.42 41.063 ;
        RECT  18.6 2.137 18.72 41.063 ;
        RECT  15.9 2.137 16.02 41.063 ;
        RECT  13.2 2.137 13.32 41.063 ;
        RECT  10.5 2.137 10.62 41.063 ;
        RECT  7.8 2.137 7.92 41.063 ;
        RECT  5.1 2.137 5.22 41.063 ;
        RECT  2.4 2.137 2.52 41.063 ;
    END
  END VSS
  OBS
    LAYER RVTN ;
     RECT  2.16 2.16 187.92 2.295 ;
     RECT  2.16 2.565 187.92 2.835 ;
     RECT  2.16 3.105 187.92 3.375 ;
     RECT  2.16 3.645 187.92 3.915 ;
     RECT  2.16 4.185 187.92 4.455 ;
     RECT  2.16 4.725 187.92 4.995 ;
     RECT  2.16 5.265 187.92 5.535 ;
     RECT  2.16 5.805 187.92 6.075 ;
     RECT  2.16 6.345 187.92 6.615 ;
     RECT  2.16 6.885 187.92 7.155 ;
     RECT  2.16 7.425 187.92 7.695 ;
     RECT  2.16 7.965 187.92 8.235 ;
     RECT  2.16 8.505 187.92 8.775 ;
     RECT  2.16 9.045 187.92 9.315 ;
     RECT  2.16 9.585 187.92 9.855 ;
     RECT  2.16 10.125 187.92 10.395 ;
     RECT  2.16 10.665 187.92 10.935 ;
     RECT  2.16 11.205 187.92 11.475 ;
     RECT  2.16 11.745 187.92 12.015 ;
     RECT  2.16 12.285 187.92 12.555 ;
     RECT  2.16 12.825 187.92 13.095 ;
     RECT  2.16 13.365 187.92 13.635 ;
     RECT  2.16 13.905 187.92 14.175 ;
     RECT  2.16 14.445 187.92 14.715 ;
     RECT  2.16 14.985 187.92 15.255 ;
     RECT  2.16 15.525 187.92 15.795 ;
     RECT  2.16 16.065 187.92 16.335 ;
     RECT  2.16 16.605 187.92 16.875 ;
     RECT  2.16 17.145 187.92 17.415 ;
     RECT  2.16 17.685 187.92 17.955 ;
     RECT  2.16 18.225 187.92 18.495 ;
     RECT  2.16 18.765 187.92 19.035 ;
     RECT  2.16 19.305 187.92 19.575 ;
     RECT  2.16 19.845 187.92 20.115 ;
     RECT  2.16 20.385 187.92 20.655 ;
     RECT  2.16 20.925 187.92 21.195 ;
     RECT  2.16 21.465 187.92 21.735 ;
     RECT  2.16 22.005 187.92 22.275 ;
     RECT  2.16 22.545 187.92 22.815 ;
     RECT  2.16 23.085 187.92 23.355 ;
     RECT  2.16 23.625 187.92 23.895 ;
     RECT  2.16 24.165 187.92 24.435 ;
     RECT  2.16 24.705 187.92 24.975 ;
     RECT  2.16 25.245 187.92 25.515 ;
     RECT  2.16 25.785 187.92 26.055 ;
     RECT  2.16 26.325 187.92 26.595 ;
     RECT  2.16 26.865 187.92 27.135 ;
     RECT  2.16 27.405 187.92 27.675 ;
     RECT  2.16 27.945 187.92 28.215 ;
     RECT  2.16 28.485 187.92 28.755 ;
     RECT  2.16 29.025 187.92 29.295 ;
     RECT  2.16 29.565 187.92 29.835 ;
     RECT  2.16 30.105 187.92 30.375 ;
     RECT  2.16 30.645 187.92 30.915 ;
     RECT  2.16 31.185 187.92 31.455 ;
     RECT  2.16 31.725 187.92 31.995 ;
     RECT  2.16 32.265 187.92 32.535 ;
     RECT  2.16 32.805 187.92 33.075 ;
     RECT  2.16 33.345 187.92 33.615 ;
     RECT  2.16 33.885 187.92 34.155 ;
     RECT  2.16 34.425 187.92 34.695 ;
     RECT  2.16 34.965 187.92 35.235 ;
     RECT  2.16 35.505 187.92 35.775 ;
     RECT  2.16 36.045 187.92 36.315 ;
     RECT  2.16 36.585 187.92 36.855 ;
     RECT  2.16 37.125 187.92 37.395 ;
     RECT  2.16 37.665 187.92 37.935 ;
     RECT  2.16 38.205 187.92 38.475 ;
     RECT  2.16 38.745 187.92 39.015 ;
     RECT  2.16 39.285 187.92 39.555 ;
     RECT  2.16 39.825 187.92 40.095 ;
     RECT  2.16 40.365 187.92 40.635 ;
     RECT  2.16 40.905 187.92 41.04 ;
    LAYER RVTP ;
     RECT  2.16 2.295 187.92 2.565 ;
     RECT  2.16 2.835 187.92 3.105 ;
     RECT  2.16 3.375 187.92 3.645 ;
     RECT  2.16 3.915 187.92 4.185 ;
     RECT  2.16 4.455 187.92 4.725 ;
     RECT  2.16 4.995 187.92 5.265 ;
     RECT  2.16 5.535 187.92 5.805 ;
     RECT  2.16 6.075 187.92 6.345 ;
     RECT  2.16 6.615 187.92 6.885 ;
     RECT  2.16 7.155 187.92 7.425 ;
     RECT  2.16 7.695 187.92 7.965 ;
     RECT  2.16 8.235 187.92 8.505 ;
     RECT  2.16 8.775 187.92 9.045 ;
     RECT  2.16 9.315 187.92 9.585 ;
     RECT  2.16 9.855 187.92 10.125 ;
     RECT  2.16 10.395 187.92 10.665 ;
     RECT  2.16 10.935 187.92 11.205 ;
     RECT  2.16 11.475 187.92 11.745 ;
     RECT  2.16 12.015 187.92 12.285 ;
     RECT  2.16 12.555 187.92 12.825 ;
     RECT  2.16 13.095 187.92 13.365 ;
     RECT  2.16 13.635 187.92 13.905 ;
     RECT  2.16 14.175 187.92 14.445 ;
     RECT  2.16 14.715 187.92 14.985 ;
     RECT  2.16 15.255 187.92 15.525 ;
     RECT  2.16 15.795 187.92 16.065 ;
     RECT  2.16 16.335 187.92 16.605 ;
     RECT  2.16 16.875 187.92 17.145 ;
     RECT  2.16 17.415 187.92 17.685 ;
     RECT  2.16 17.955 187.92 18.225 ;
     RECT  2.16 18.495 187.92 18.765 ;
     RECT  2.16 19.035 187.92 19.305 ;
     RECT  2.16 19.575 187.92 19.845 ;
     RECT  2.16 20.115 187.92 20.385 ;
     RECT  2.16 20.655 187.92 20.925 ;
     RECT  2.16 21.195 187.92 21.465 ;
     RECT  2.16 21.735 187.92 22.005 ;
     RECT  2.16 22.275 187.92 22.545 ;
     RECT  2.16 22.815 187.92 23.085 ;
     RECT  2.16 23.355 187.92 23.625 ;
     RECT  2.16 23.895 187.92 24.165 ;
     RECT  2.16 24.435 187.92 24.705 ;
     RECT  2.16 24.975 187.92 25.245 ;
     RECT  2.16 25.515 187.92 25.785 ;
     RECT  2.16 26.055 187.92 26.325 ;
     RECT  2.16 26.595 187.92 26.865 ;
     RECT  2.16 27.135 187.92 27.405 ;
     RECT  2.16 27.675 187.92 27.945 ;
     RECT  2.16 28.215 187.92 28.485 ;
     RECT  2.16 28.755 187.92 29.025 ;
     RECT  2.16 29.295 187.92 29.565 ;
     RECT  2.16 29.835 187.92 30.105 ;
     RECT  2.16 30.375 187.92 30.645 ;
     RECT  2.16 30.915 187.92 31.185 ;
     RECT  2.16 31.455 187.92 31.725 ;
     RECT  2.16 31.995 187.92 32.265 ;
     RECT  2.16 32.535 187.92 32.805 ;
     RECT  2.16 33.075 187.92 33.345 ;
     RECT  2.16 33.615 187.92 33.885 ;
     RECT  2.16 34.155 187.92 34.425 ;
     RECT  2.16 34.695 187.92 34.965 ;
     RECT  2.16 35.235 187.92 35.505 ;
     RECT  2.16 35.775 187.92 36.045 ;
     RECT  2.16 36.315 187.92 36.585 ;
     RECT  2.16 36.855 187.92 37.125 ;
     RECT  2.16 37.395 187.92 37.665 ;
     RECT  2.16 37.935 187.92 38.205 ;
     RECT  2.16 38.475 187.92 38.745 ;
     RECT  2.16 39.015 187.92 39.285 ;
     RECT  2.16 39.555 187.92 39.825 ;
     RECT  2.16 40.095 187.92 40.365 ;
     RECT  2.16 40.635 187.92 40.905 ;
    LAYER M1 ;
     RECT  2.16 2.151 187.92 41.049 ;
    LAYER M2 ;
     RECT  26.239 0.846 29.083 0.864 ;
     RECT  29.083 0.414 29.155 0.864 ;
     RECT  29.155 0.216 29.327 0.864 ;
     RECT  29.327 0.846 32.287 0.864 ;
     RECT  32.287 0.216 32.431 0.864 ;
     RECT  32.431 0.216 32.719 0.9 ;
     RECT  2.16 2.151 32.719 41.049 ;
     RECT  32.719 0.216 33.007 41.049 ;
     RECT  33.007 0.108 33.151 41.049 ;
     RECT  33.151 0.072 33.439 41.049 ;
     RECT  33.439 0.036 82.103 41.049 ;
     RECT  82.103 0.108 84.487 41.049 ;
     RECT  84.487 0.072 88.879 41.049 ;
     RECT  88.879 0.036 133.655 41.049 ;
     RECT  133.655 0.072 137.839 41.049 ;
     RECT  137.839 0.036 168.647 41.049 ;
     RECT  168.647 0.036 170.879 0.054 ;
     RECT  168.647 0.846 171.239 41.049 ;
     RECT  171.239 1.926 173.255 41.049 ;
     RECT  173.255 1.998 180.743 41.049 ;
     RECT  171.239 0.846 181.031 0.864 ;
     RECT  180.743 2.151 187.92 41.049 ;
    LAYER M3 ;
     RECT  33.444 0.031 33.462 0.067 ;
     RECT  55.476 0.043 55.494 0.067 ;
     RECT  79.812 0.043 79.83 0.067 ;
     RECT  161.82 0.043 162.486 0.067 ;
     RECT  26.82 0.043 26.838 0.091 ;
     RECT  33.156 0.067 33.462 0.091 ;
     RECT  38.088 0.043 38.106 0.091 ;
     RECT  43.524 0.043 43.542 0.091 ;
     RECT  47.304 0.043 47.43 0.091 ;
     RECT  49.104 0.043 49.122 0.091 ;
     RECT  54.828 0.067 55.494 0.091 ;
     RECT  56.34 0.067 56.358 0.091 ;
     RECT  58.86 0.043 58.878 0.091 ;
     RECT  62.784 0.043 62.802 0.091 ;
     RECT  74.7 0.043 74.718 0.091 ;
     RECT  77.004 0.043 77.382 0.091 ;
     RECT  79.812 0.067 80.478 0.091 ;
     RECT  88.884 0.031 88.902 0.091 ;
     RECT  110.88 0.043 111.006 0.091 ;
     RECT  133.632 0.031 133.65 0.091 ;
     RECT  137.844 0.031 137.862 0.091 ;
     RECT  146.556 0.067 146.574 0.091 ;
     RECT  148.176 0.043 148.194 0.091 ;
     RECT  150.624 0.043 150.642 0.091 ;
     RECT  153.756 0.043 153.774 0.091 ;
     RECT  154.548 0.043 154.566 0.091 ;
     RECT  161.82 0.067 163.17 0.091 ;
     RECT  164.7 0.043 164.718 0.091 ;
     RECT  166.464 0.043 166.482 0.091 ;
     RECT  170.856 0.031 170.874 0.091 ;
     RECT  75.888 0.091 78.462 0.103 ;
     RECT  79.812 0.091 81.198 0.103 ;
     RECT  133.632 0.091 134.19 0.103 ;
     RECT  158.256 0.043 158.49 0.103 ;
     RECT  161.388 0.091 164.718 0.103 ;
     RECT  32.796 0.091 33.462 0.125 ;
     RECT  120.384 0.067 120.942 0.125 ;
     RECT  133.632 0.103 134.55 0.125 ;
     RECT  124.416 0.091 124.434 0.133 ;
     RECT  26.244 0.091 26.838 0.139 ;
     RECT  30.456 0.091 30.87 0.139 ;
     RECT  37.764 0.091 38.79 0.139 ;
     RECT  48.708 0.091 49.554 0.139 ;
     RECT  53.892 0.091 53.91 0.139 ;
     RECT  75.888 0.103 78.786 0.139 ;
     RECT  82.08 0.031 82.098 0.139 ;
     RECT  107.388 0.043 107.514 0.139 ;
     RECT  122.976 0.103 122.994 0.139 ;
     RECT  123.948 0.133 124.434 0.139 ;
     RECT  142.632 0.067 142.65 0.139 ;
     RECT  146.556 0.091 147.042 0.139 ;
     RECT  158.256 0.103 158.526 0.139 ;
     RECT  160.092 0.091 160.11 0.139 ;
     RECT  167.76 0.091 170.946 0.139 ;
     RECT  37.764 0.139 39.222 0.167 ;
     RECT  62.784 0.091 63.27 0.167 ;
     RECT  25.668 0.139 26.838 0.173 ;
     RECT  37.908 0.167 39.222 0.173 ;
     RECT  42.912 0.091 43.542 0.173 ;
     RECT  70.416 0.043 70.83 0.173 ;
     RECT  161.28 0.103 164.718 0.173 ;
     RECT  175.68 0.043 175.698 0.173 ;
     RECT  84.492 0.067 84.51 0.175 ;
     RECT  32.796 0.125 33.318 0.187 ;
     RECT  86.652 0.091 86.67 0.187 ;
     RECT  89.82 0.091 89.838 0.187 ;
     RECT  108.324 0.175 108.342 0.187 ;
     RECT  126.828 0.139 126.846 0.187 ;
     RECT  129.888 0.139 129.906 0.187 ;
     RECT  159.804 0.139 160.11 0.187 ;
     RECT  166.464 0.091 166.806 0.187 ;
     RECT  167.76 0.139 171.234 0.187 ;
     RECT  173.196 0.043 173.214 0.187 ;
     RECT  161.28 0.173 161.478 0.203 ;
     RECT  29.16 0.187 29.286 0.211 ;
     RECT  48.708 0.139 50.202 0.211 ;
     RECT  109.44 0.175 109.458 0.211 ;
     RECT  110.736 0.091 111.006 0.211 ;
     RECT  54.72 0.091 56.358 0.221 ;
     RECT  137.268 0.091 138.546 0.221 ;
     RECT  179.028 0.091 179.19 0.221 ;
     RECT  35.928 0.187 35.946 0.235 ;
     RECT  45.612 0.091 45.63 0.235 ;
     RECT  46.836 0.091 47.43 0.235 ;
     RECT  58.572 0.091 59.274 0.235 ;
     RECT  62.784 0.167 63.126 0.235 ;
     RECT  89.82 0.187 89.946 0.235 ;
     RECT  90.828 0.139 90.846 0.235 ;
     RECT  94.572 0.139 94.59 0.235 ;
     RECT  98.712 0.139 98.73 0.235 ;
     RECT  129.816 0.187 129.906 0.235 ;
     RECT  148.176 0.091 148.662 0.235 ;
     RECT  149.868 0.091 150.642 0.235 ;
     RECT  151.596 0.091 152.478 0.235 ;
     RECT  32.292 0.187 33.318 0.239 ;
     RECT  45.612 0.235 47.43 0.239 ;
     RECT  60.876 0.067 60.966 0.239 ;
     RECT  62.712 0.235 63.126 0.239 ;
     RECT  84.492 0.175 84.906 0.256 ;
     RECT  97.488 0.091 97.506 0.256 ;
     RECT  37.908 0.173 38.034 0.269 ;
     RECT  109.44 0.211 111.006 0.269 ;
     RECT  119.016 0.091 119.034 0.269 ;
     RECT  122.976 0.139 124.578 0.269 ;
     RECT  126.756 0.187 126.846 0.269 ;
     RECT  34.308 0.091 34.722 0.283 ;
     RECT  35.604 0.235 35.946 0.283 ;
     RECT  64.836 0.091 66.582 0.283 ;
     RECT  94.572 0.235 95.022 0.283 ;
     RECT  96.084 0.139 96.102 0.283 ;
     RECT  108.288 0.187 108.342 0.283 ;
     RECT  110.88 0.269 111.006 0.283 ;
     RECT  112.248 0.091 112.266 0.283 ;
     RECT  126.756 0.269 126.774 0.283 ;
     RECT  133.776 0.125 134.55 0.283 ;
     RECT  144.684 0.139 144.702 0.283 ;
     RECT  68.58 0.091 68.598 0.284 ;
     RECT  162.72 0.173 164.718 0.284 ;
     RECT  84.492 0.256 85.158 0.301 ;
     RECT  132.3 0.091 132.318 0.301 ;
     RECT  158.256 0.139 158.598 0.301 ;
     RECT  24.48 0.187 24.498 0.317 ;
     RECT  29.16 0.211 29.322 0.317 ;
     RECT  46.116 0.239 47.43 0.317 ;
     RECT  116.964 0.091 117.09 0.317 ;
     RECT  126.252 0.283 126.774 0.317 ;
     RECT  38.772 0.173 39.222 0.329 ;
     RECT  42.912 0.173 42.93 0.331 ;
     RECT  84.42 0.301 85.158 0.331 ;
     RECT  110.88 0.283 112.266 0.331 ;
     RECT  137.268 0.221 138.51 0.331 ;
     RECT  146.412 0.139 147.042 0.331 ;
     RECT  148.176 0.235 148.734 0.331 ;
     RECT  149.868 0.235 152.478 0.331 ;
     RECT  158.112 0.301 158.598 0.331 ;
     RECT  163.836 0.284 164.718 0.331 ;
     RECT  129.744 0.235 130.626 0.337 ;
     RECT  42.768 0.331 42.93 0.365 ;
     RECT  46.116 0.317 46.854 0.365 ;
     RECT  58.572 0.235 59.31 0.365 ;
     RECT  84.384 0.331 85.158 0.365 ;
     RECT  98.712 0.235 98.874 0.365 ;
     RECT  122.976 0.269 122.994 0.373 ;
     RECT  40.428 0.091 41.166 0.379 ;
     RECT  48.456 0.211 50.202 0.379 ;
     RECT  58.572 0.365 59.274 0.379 ;
     RECT  64.476 0.283 66.582 0.379 ;
     RECT  82.08 0.139 82.89 0.379 ;
     RECT  89.82 0.235 90.846 0.379 ;
     RECT  98.712 0.365 98.73 0.379 ;
     RECT  133.776 0.283 135.198 0.379 ;
     RECT  142.56 0.139 142.65 0.379 ;
     RECT  146.412 0.331 148.734 0.379 ;
     RECT  156.708 0.091 156.726 0.379 ;
     RECT  166.464 0.187 171.234 0.379 ;
     RECT  29.16 0.317 29.286 0.409 ;
     RECT  144.684 0.283 144.81 0.409 ;
     RECT  75.888 0.139 78.858 0.413 ;
     RECT  44.568 0.379 44.586 0.427 ;
     RECT  57.384 0.283 57.402 0.427 ;
     RECT  62.712 0.239 62.802 0.427 ;
     RECT  73.548 0.043 73.566 0.427 ;
     RECT  106.74 0.139 107.514 0.427 ;
     RECT  159.588 0.187 160.11 0.427 ;
     RECT  29.088 0.409 29.286 0.437 ;
     RECT  75.888 0.413 78.822 0.437 ;
     RECT  89.82 0.379 91.422 0.437 ;
     RECT  70.416 0.173 70.722 0.445 ;
     RECT  29.088 0.437 29.106 0.461 ;
     RECT  34.308 0.283 35.946 0.461 ;
     RECT  78.768 0.437 78.822 0.461 ;
     RECT  57.312 0.427 57.402 0.475 ;
     RECT  58.5 0.379 59.274 0.475 ;
     RECT  106.272 0.427 107.514 0.475 ;
     RECT  34.308 0.461 34.794 0.509 ;
     RECT  38.772 0.329 38.934 0.509 ;
     RECT  51.408 0.379 51.426 0.509 ;
     RECT  57.312 0.475 59.274 0.52 ;
     RECT  129.348 0.337 130.626 0.52 ;
     RECT  56.196 0.221 56.358 0.523 ;
     RECT  57.132 0.52 59.274 0.523 ;
     RECT  92.052 0.475 92.07 0.523 ;
     RECT  106.2 0.475 107.514 0.523 ;
     RECT  110.88 0.331 112.806 0.523 ;
     RECT  113.652 0.091 114.174 0.523 ;
     RECT  120.852 0.125 120.942 0.523 ;
     RECT  122.436 0.373 122.994 0.523 ;
     RECT  127.692 0.103 127.71 0.523 ;
     RECT  144.072 0.409 144.81 0.523 ;
     RECT  145.944 0.379 148.734 0.523 ;
     RECT  149.868 0.331 152.802 0.523 ;
     RECT  173.196 0.187 173.286 0.523 ;
     RECT  174.384 0.187 174.402 0.523 ;
     RECT  177.516 0.475 177.534 0.523 ;
     RECT  179.172 0.221 179.19 0.523 ;
     RECT  129.168 0.52 130.626 0.554 ;
     RECT  44.136 0.427 44.586 0.557 ;
     RECT  46.116 0.365 46.458 0.557 ;
     RECT  70.164 0.445 70.722 0.557 ;
     RECT  143.532 0.523 152.802 0.557 ;
     RECT  159.588 0.427 160.398 0.557 ;
     RECT  74.7 0.091 75.042 0.571 ;
     RECT  75.888 0.437 77.814 0.571 ;
     RECT  82.08 0.379 83.214 0.571 ;
     RECT  84.384 0.365 84.726 0.571 ;
     RECT  85.932 0.187 86.67 0.571 ;
     RECT  88.308 0.091 88.902 0.571 ;
     RECT  92.052 0.523 92.61 0.571 ;
     RECT  142.524 0.379 142.65 0.571 ;
     RECT  156.132 0.379 156.726 0.571 ;
     RECT  173.196 0.523 174.402 0.571 ;
     RECT  180.72 0.091 181.026 0.571 ;
     RECT  104.328 0.211 104.346 0.599 ;
     RECT  97.488 0.256 97.542 0.619 ;
     RECT  105.876 0.523 107.514 0.619 ;
     RECT  108.288 0.283 108.594 0.619 ;
     RECT  157.824 0.331 158.598 0.619 ;
     RECT  159.588 0.557 160.146 0.619 ;
     RECT  85.932 0.571 86.778 0.667 ;
     RECT  105.876 0.619 108.594 0.667 ;
     RECT  109.44 0.269 110.034 0.667 ;
     RECT  132.3 0.301 132.822 0.667 ;
     RECT  139.824 0.523 139.842 0.667 ;
     RECT  45.036 0.619 45.054 0.671 ;
     RECT  166.14 0.379 171.234 0.707 ;
     RECT  35.604 0.461 35.946 0.715 ;
     RECT  74.7 0.571 77.814 0.715 ;
     RECT  133.776 0.379 135.81 0.715 ;
     RECT  153.756 0.091 154.566 0.715 ;
     RECT  147.564 0.557 152.802 0.743 ;
     RECT  47.808 0.379 50.202 0.749 ;
     RECT  142.524 0.571 142.686 0.749 ;
     RECT  79.812 0.103 81.27 0.751 ;
     RECT  82.08 0.571 84.726 0.751 ;
     RECT  53.604 0.139 53.91 0.811 ;
     RECT  54.72 0.221 55.35 0.811 ;
     RECT  126.252 0.317 126.738 0.859 ;
     RECT  25.668 0.173 26.262 0.869 ;
     RECT  133.776 0.715 136.206 0.869 ;
     RECT  101.196 0.523 101.214 0.877 ;
     RECT  153.756 0.715 154.782 0.893 ;
     RECT  32.436 0.239 33.318 0.905 ;
     RECT  67.68 0.841 67.698 0.907 ;
     RECT  88.272 0.571 88.902 0.907 ;
     RECT  89.82 0.437 91.314 0.907 ;
     RECT  129.168 0.554 129.294 0.907 ;
     RECT  53.604 0.811 55.35 0.941 ;
     RECT  73.224 0.427 73.566 0.955 ;
     RECT  74.664 0.715 77.814 0.955 ;
     RECT  139.608 0.667 139.842 0.955 ;
     RECT  140.616 0.091 140.634 0.955 ;
     RECT  73.224 0.955 77.814 0.977 ;
     RECT  110.88 0.523 114.174 0.985 ;
     RECT  120.852 0.523 120.978 0.985 ;
     RECT  62.244 0.427 62.802 1.003 ;
     RECT  39.924 0.379 41.166 1.013 ;
     RECT  34.308 0.509 34.614 1.049 ;
     RECT  92.052 0.571 92.898 1.051 ;
     RECT  180.54 0.571 181.026 1.051 ;
     RECT  42.768 0.365 42.786 1.099 ;
     RECT  72.144 1.051 72.162 1.099 ;
     RECT  97.488 0.619 97.758 1.099 ;
     RECT  100.728 0.877 101.214 1.099 ;
     RECT  103.032 0.475 103.05 1.099 ;
     RECT  121.932 0.523 122.994 1.099 ;
     RECT  127.584 0.523 127.71 1.099 ;
     RECT  161.28 0.203 161.298 1.099 ;
     RECT  173.196 0.571 174.834 1.099 ;
     RECT  180.54 1.051 181.242 1.099 ;
     RECT  130.248 0.554 130.626 1.111 ;
     RECT  88.272 0.907 91.314 1.139 ;
     RECT  129.096 0.907 129.294 1.139 ;
     RECT  47.808 0.749 47.826 1.147 ;
     RECT  55.296 0.941 55.35 1.147 ;
     RECT  56.196 0.523 59.274 1.147 ;
     RECT  60.876 0.239 60.894 1.147 ;
     RECT  79.812 0.751 84.726 1.147 ;
     RECT  105.876 0.667 110.034 1.147 ;
     RECT  110.88 0.985 114.678 1.147 ;
     RECT  123.84 0.269 124.578 1.147 ;
     RECT  129.096 1.139 129.114 1.147 ;
     RECT  142.524 0.749 142.65 1.147 ;
     RECT  149.256 0.743 152.802 1.147 ;
     RECT  155.52 0.571 156.726 1.147 ;
     RECT  157.824 0.619 160.146 1.147 ;
     RECT  173.196 1.099 174.906 1.147 ;
     RECT  175.896 0.523 175.914 1.147 ;
     RECT  67.68 0.907 68.094 1.195 ;
     RECT  103.032 1.099 103.446 1.195 ;
     RECT  180.108 1.099 181.242 1.195 ;
     RECT  143.532 0.557 146.574 1.211 ;
     RECT  71.244 1.099 72.162 1.219 ;
     RECT  120.492 0.985 120.978 1.219 ;
     RECT  121.752 1.099 122.994 1.219 ;
     RECT  133.848 0.869 136.206 1.243 ;
     RECT  137.052 0.331 138.51 1.243 ;
     RECT  46.152 0.557 46.314 1.291 ;
     RECT  79.812 1.147 85.014 1.291 ;
     RECT  85.932 0.667 87.246 1.291 ;
     RECT  100.728 1.099 101.502 1.291 ;
     RECT  143.532 1.211 145.998 1.291 ;
     RECT  118.548 1.183 118.566 1.336 ;
     RECT  32.724 0.905 33.318 1.339 ;
     RECT  52.848 0.619 52.866 1.339 ;
     RECT  62.244 1.003 63.378 1.339 ;
     RECT  97.272 1.099 97.758 1.339 ;
     RECT  98.604 0.379 98.73 1.339 ;
     RECT  133.848 1.243 138.51 1.339 ;
     RECT  139.608 0.955 140.634 1.339 ;
     RECT  176.976 0.523 177.534 1.387 ;
     RECT  100.368 1.291 101.502 1.435 ;
     RECT  127.548 1.099 127.71 1.435 ;
     RECT  128.844 1.147 129.114 1.435 ;
     RECT  78.804 0.461 78.822 1.453 ;
     RECT  51.3 1.147 51.318 1.483 ;
     RECT  94.572 0.283 96.102 1.483 ;
     RECT  105.876 1.147 114.678 1.483 ;
     RECT  51.3 1.483 51.354 1.489 ;
     RECT  52.128 1.339 52.866 1.489 ;
     RECT  70.056 0.796 70.074 1.489 ;
     RECT  71.244 1.219 72.414 1.489 ;
     RECT  123.84 1.147 124.83 1.489 ;
     RECT  125.856 0.859 126.738 1.489 ;
     RECT  69.516 1.489 70.074 1.525 ;
     RECT  104.724 1.531 104.742 1.561 ;
     RECT  55.296 1.147 59.274 1.579 ;
     RECT  118.368 1.336 118.566 1.579 ;
     RECT  102.276 0.091 102.294 1.606 ;
     RECT  103.032 1.195 103.77 1.606 ;
     RECT  133.848 1.339 140.634 1.606 ;
     RECT  141.948 1.147 142.65 1.606 ;
     RECT  143.496 1.291 145.998 1.606 ;
     RECT  48.672 0.749 50.202 1.651 ;
     RECT  51.3 1.489 52.866 1.651 ;
     RECT  132.264 0.667 132.822 1.651 ;
     RECT  133.848 1.606 141.03 1.651 ;
     RECT  38.88 0.509 38.898 1.675 ;
     RECT  91.116 1.139 91.314 1.675 ;
     RECT  92.052 1.051 93.186 1.675 ;
     RECT  99.936 1.435 101.502 1.675 ;
     RECT  102.276 1.606 103.77 1.675 ;
     RECT  115.452 1.099 115.47 1.675 ;
     RECT  44.136 0.557 44.154 1.687 ;
     RECT  44.928 1.579 44.946 1.687 ;
     RECT  45.756 1.291 46.314 1.687 ;
     RECT  155.52 1.147 160.146 1.709 ;
     RECT  22.5 0.139 22.518 1.723 ;
     RECT  47.304 1.147 47.826 1.723 ;
     RECT  48.6 1.651 52.866 1.723 ;
     RECT  53.604 0.941 54.234 1.723 ;
     RECT  55.296 1.579 59.598 1.723 ;
     RECT  60.624 1.147 60.894 1.723 ;
     RECT  67.68 1.195 68.13 1.723 ;
     RECT  68.976 1.525 70.074 1.723 ;
     RECT  71.244 1.489 72.45 1.723 ;
     RECT  91.116 1.675 93.186 1.723 ;
     RECT  94.176 1.483 96.102 1.723 ;
     RECT  97.272 1.339 98.73 1.723 ;
     RECT  99.936 1.675 103.77 1.723 ;
     RECT  123.84 1.489 126.738 1.723 ;
     RECT  127.548 1.435 129.114 1.723 ;
     RECT  132.264 1.651 141.03 1.723 ;
     RECT  141.948 1.606 145.998 1.723 ;
     RECT  147.564 0.743 148.194 1.723 ;
     RECT  162.72 0.284 163.026 1.723 ;
     RECT  47.304 1.723 47.862 1.759 ;
     RECT  48.6 1.723 54.234 1.759 ;
     RECT  119.736 1.483 119.754 1.759 ;
     RECT  120.492 1.219 122.994 1.759 ;
     RECT  55.296 1.723 60.894 1.771 ;
     RECT  62.244 1.339 63.738 1.771 ;
     RECT  97.272 1.723 103.77 1.771 ;
     RECT  104.724 1.561 104.994 1.771 ;
     RECT  105.732 1.483 114.678 1.771 ;
     RECT  116.964 0.317 116.982 1.771 ;
     RECT  118.368 1.579 118.71 1.771 ;
     RECT  131.472 0.256 131.49 1.771 ;
     RECT  132.264 1.723 145.998 1.771 ;
     RECT  147.024 1.723 148.194 1.771 ;
     RECT  149.256 1.147 152.838 1.771 ;
     RECT  179.172 0.523 179.262 1.771 ;
     RECT  180.072 1.195 181.242 1.771 ;
     RECT  116.784 1.771 118.71 1.795 ;
     RECT  119.736 1.759 122.994 1.795 ;
     RECT  38.88 1.675 39.042 1.819 ;
     RECT  42.768 1.099 43.398 1.819 ;
     RECT  47.304 1.759 54.234 1.831 ;
     RECT  55.296 1.771 63.738 1.831 ;
     RECT  67.68 1.723 72.45 1.831 ;
     RECT  73.224 0.977 77.742 1.831 ;
     RECT  79.812 1.291 87.246 1.831 ;
     RECT  34.308 1.049 34.326 1.867 ;
     RECT  130.248 1.111 130.698 1.867 ;
     RECT  131.472 1.771 145.998 1.867 ;
     RECT  115.452 1.675 115.974 1.876 ;
     RECT  116.784 1.795 122.994 1.876 ;
     RECT  30.276 0.139 31.05 1.915 ;
     RECT  64.476 0.379 66.726 1.921 ;
     RECT  130.248 1.867 145.998 1.949 ;
     RECT  42.372 1.819 43.398 1.957 ;
     RECT  44.136 1.687 46.314 1.957 ;
     RECT  78.66 1.453 78.822 1.957 ;
     RECT  79.704 1.831 87.246 1.957 ;
     RECT  47.304 1.831 63.738 1.963 ;
     RECT  64.476 1.921 66.762 1.963 ;
     RECT  35.604 0.715 36.558 1.985 ;
     RECT  168.732 0.707 171.234 1.985 ;
     RECT  104.724 1.771 114.678 1.993 ;
     RECT  115.452 1.876 122.994 1.993 ;
     RECT  21.96 1.723 22.518 2.011 ;
     RECT  40.608 1.013 41.166 2.011 ;
     RECT  78.66 1.957 87.354 2.011 ;
     RECT  88.272 1.139 90.342 2.011 ;
     RECT  153.756 0.893 154.566 2.011 ;
     RECT  160.992 1.099 161.298 2.011 ;
     RECT  162.468 1.723 163.026 2.011 ;
     RECT  153.756 2.011 154.602 2.029 ;
     RECT  155.52 1.709 157.842 2.029 ;
     RECT  38.808 1.819 39.15 2.045 ;
     RECT  29.7 1.915 31.05 2.059 ;
     RECT  38.808 2.045 39.042 2.059 ;
     RECT  91.116 1.723 96.102 2.059 ;
     RECT  96.876 1.771 103.77 2.059 ;
     RECT  166.14 0.707 167.562 2.059 ;
     RECT  176.688 1.387 177.534 2.059 ;
     RECT  47.304 1.963 66.762 2.065 ;
     RECT  67.68 1.831 77.742 2.065 ;
     RECT  166.14 2.059 167.706 2.099 ;
     RECT  91.116 2.059 103.77 2.101 ;
     RECT  104.724 1.993 122.994 2.101 ;
     RECT  171.324 2.065 171.342 2.101 ;
     RECT  172.116 0.139 172.134 2.101 ;
     RECT  47.304 2.065 77.742 2.107 ;
     RECT  34.2 1.867 34.326 2.129 ;
     RECT  21.636 2.011 22.518 2.143 ;
     RECT  23.364 1.723 23.382 2.143 ;
     RECT  29.592 2.059 31.05 2.143 ;
     RECT  32.724 1.339 33.354 2.143 ;
     RECT  35.604 1.985 35.622 2.143 ;
     RECT  37.692 2.059 37.818 2.143 ;
     RECT  40.536 2.011 41.166 2.143 ;
     RECT  47.304 2.107 77.778 2.143 ;
     RECT  78.66 2.011 90.342 2.143 ;
     RECT  123.84 1.723 129.114 2.143 ;
     RECT  153.756 2.029 157.842 2.143 ;
     RECT  171.324 2.101 172.134 2.143 ;
     RECT  173.196 1.147 175.914 2.143 ;
     RECT  176.688 2.059 177.57 2.143 ;
     RECT  40.215 2.143 41.166 2.155 ;
     RECT  47.304 2.143 90.342 2.191 ;
     RECT  91.116 2.101 122.994 2.191 ;
     RECT  123.84 2.143 129.405 2.191 ;
     RECT  171.324 2.143 175.914 2.219 ;
     RECT  179.172 1.771 181.242 2.219 ;
     RECT  147.024 1.771 152.838 2.227 ;
     RECT  153.615 2.143 157.842 2.227 ;
     RECT  160.992 2.011 163.026 2.237 ;
     RECT  176.688 2.143 178.005 2.251 ;
     RECT  171.324 2.219 171.342 2.255 ;
     RECT  179.172 2.219 179.298 2.255 ;
     RECT  42.372 1.957 46.314 2.263 ;
     RECT  162.72 2.237 163.026 2.263 ;
     RECT  163.836 0.331 165.006 2.263 ;
     RECT  172.116 2.219 175.914 2.327 ;
     RECT  147.024 2.227 157.842 2.363 ;
     RECT  37.515 2.143 37.818 2.371 ;
     RECT  47.304 2.191 122.994 2.381 ;
     RECT  40.032 2.155 41.166 2.395 ;
     RECT  2.415 2.143 2.505 2.413 ;
     RECT  5.115 2.143 5.205 2.413 ;
     RECT  7.815 2.143 7.905 2.413 ;
     RECT  10.515 2.143 10.605 2.413 ;
     RECT  13.215 2.143 13.305 2.413 ;
     RECT  15.915 2.143 16.005 2.413 ;
     RECT  18.615 2.143 18.705 2.413 ;
     RECT  23.364 2.143 24.105 2.413 ;
     RECT  26.715 2.143 26.805 2.413 ;
     RECT  123.84 2.191 129.51 2.413 ;
     RECT  130.248 1.949 145.962 2.413 ;
     RECT  183.315 2.143 183.405 2.413 ;
     RECT  186.015 2.143 186.105 2.413 ;
     RECT  26.715 2.413 26.997 2.443 ;
     RECT  37.515 2.371 37.89 2.443 ;
     RECT  38.772 2.059 39.042 2.443 ;
     RECT  41.976 2.263 46.314 2.443 ;
     RECT  47.304 2.381 70.578 2.443 ;
     RECT  159.012 1.709 160.146 2.461 ;
     RECT  39.924 2.395 41.166 2.491 ;
     RECT  41.976 2.443 70.578 2.491 ;
     RECT  71.424 2.381 122.994 2.497 ;
     RECT  123.84 2.413 145.962 2.497 ;
     RECT  162.72 2.263 165.006 2.525 ;
     RECT  21.315 2.143 22.518 2.539 ;
     RECT  23.364 2.413 24.297 2.539 ;
     RECT  26.715 2.443 27.09 2.539 ;
     RECT  36.504 1.985 36.558 2.597 ;
     RECT  172.515 2.327 175.914 2.597 ;
     RECT  71.424 2.497 145.962 2.621 ;
     RECT  21.315 2.539 24.297 2.669 ;
     RECT  26.604 2.539 27.09 2.669 ;
     RECT  71.424 2.621 78.714 2.669 ;
     RECT  36.54 2.597 36.558 2.731 ;
     RECT  37.515 2.443 39.042 2.731 ;
     RECT  158.976 2.461 160.146 2.731 ;
     RECT  160.992 2.237 161.997 2.731 ;
     RECT  39.924 2.491 70.578 2.765 ;
     RECT  36.54 2.731 39.042 2.768 ;
     RECT  42.372 2.765 70.578 2.795 ;
     RECT  182.448 1.147 182.466 2.795 ;
     RECT  26.676 2.669 27.09 2.861 ;
     RECT  79.524 2.621 145.962 2.861 ;
     RECT  158.976 2.731 161.997 2.875 ;
     RECT  42.768 2.795 70.578 2.939 ;
     RECT  163.512 2.525 165.006 3.005 ;
     RECT  26.715 2.861 27.09 3.029 ;
     RECT  158.544 2.875 161.997 3.037 ;
     RECT  162.72 2.525 162.738 3.037 ;
     RECT  42.768 2.939 43.398 3.065 ;
     RECT  180.072 2.219 181.242 3.065 ;
     RECT  171.108 3.037 171.126 3.073 ;
     RECT  147.024 2.363 157.41 3.101 ;
     RECT  168.732 1.985 170.262 3.115 ;
     RECT  171.036 3.073 171.126 3.115 ;
     RECT  168.732 3.115 171.126 3.137 ;
     RECT  44.136 2.939 70.578 3.145 ;
     RECT  71.424 2.669 78.678 3.145 ;
     RECT  44.136 3.145 78.678 3.173 ;
     RECT  173.808 2.597 175.914 3.173 ;
     RECT  158.544 3.037 162.738 3.181 ;
     RECT  155.52 3.101 157.41 3.259 ;
     RECT  79.524 2.861 145.926 3.293 ;
     RECT  79.74 3.293 145.926 3.335 ;
     RECT  174.096 3.173 175.914 3.335 ;
     RECT  36.54 2.768 36.558 3.341 ;
     RECT  79.776 3.335 145.926 3.341 ;
     RECT  155.52 3.259 157.446 3.389 ;
     RECT  168.732 3.137 171.054 3.389 ;
     RECT  25.668 0.869 25.686 3.403 ;
     RECT  42.768 3.065 43.362 3.407 ;
     RECT  44.136 3.173 55.314 3.407 ;
     RECT  56.304 3.173 78.678 3.415 ;
     RECT  147.024 3.101 154.782 3.479 ;
     RECT  180.108 3.065 181.242 3.479 ;
     RECT  47.088 3.407 55.314 3.485 ;
     RECT  39.924 2.765 41.634 3.541 ;
     RECT  34.815 2.143 35.622 3.547 ;
     RECT  147.024 3.479 147.078 3.604 ;
     RECT  39.924 3.541 41.814 3.641 ;
     RECT  56.304 3.415 78.894 3.641 ;
     RECT  25.092 3.403 25.686 3.677 ;
     RECT  168.732 3.389 170.982 3.677 ;
     RECT  158.436 3.181 162.738 3.685 ;
     RECT  37.515 2.768 39.042 3.691 ;
     RECT  39.924 3.641 41.634 3.691 ;
     RECT  44.136 3.407 46.35 3.713 ;
     RECT  176.688 2.251 178.434 3.713 ;
     RECT  42.804 3.407 43.362 3.839 ;
     RECT  148.215 3.479 154.782 3.847 ;
     RECT  155.52 3.389 157.122 3.847 ;
     RECT  146.988 3.604 147.078 3.875 ;
     RECT  158.256 3.685 162.738 3.875 ;
     RECT  180.615 3.479 181.242 3.875 ;
     RECT  23.364 2.669 24.297 3.917 ;
     RECT  158.364 3.875 162.738 3.947 ;
     RECT  34.776 3.547 35.622 3.965 ;
     RECT  47.16 3.485 55.314 3.979 ;
     RECT  56.304 3.641 78.606 3.979 ;
     RECT  47.16 3.979 78.606 3.983 ;
     RECT  21.315 2.669 22.518 4.081 ;
     RECT  79.776 3.341 145.89 4.117 ;
     RECT  19.908 1.771 19.926 4.145 ;
     RECT  37.515 3.691 41.634 4.145 ;
     RECT  148.215 3.847 157.122 4.145 ;
     RECT  181.728 3.979 181.818 4.145 ;
     RECT  32.115 2.143 33.354 4.157 ;
     RECT  174.096 3.335 174.438 4.157 ;
     RECT  79.776 4.117 145.962 4.181 ;
     RECT  25.092 3.677 25.11 4.205 ;
     RECT  92.88 4.181 145.962 4.252 ;
     RECT  37.515 4.145 40.59 4.253 ;
     RECT  147.06 3.875 147.078 4.261 ;
     RECT  147.06 4.261 147.438 4.267 ;
     RECT  148.215 4.145 151.326 4.267 ;
     RECT  21.315 4.081 22.842 4.289 ;
     RECT  90.036 4.181 92.07 4.289 ;
     RECT  168.984 3.677 170.982 4.289 ;
     RECT  147.06 4.267 151.326 4.379 ;
     RECT  41.616 4.145 41.634 4.415 ;
     RECT  47.304 3.983 78.606 4.415 ;
     RECT  181.8 4.145 181.818 4.415 ;
     RECT  55.836 4.415 78.606 4.451 ;
     RECT  92.88 4.252 145.998 4.451 ;
     RECT  56.304 4.451 78.606 4.459 ;
     RECT  79.776 4.181 89.262 4.459 ;
     RECT  47.304 4.415 54.882 4.493 ;
     RECT  147.06 4.379 147.474 4.523 ;
     RECT  42.915 3.839 43.362 4.531 ;
     RECT  147.06 4.523 147.402 4.541 ;
     RECT  29.415 2.143 31.05 4.555 ;
     RECT  32.115 4.157 32.886 4.555 ;
     RECT  147.384 4.541 147.402 4.559 ;
     RECT  42.915 4.531 43.398 4.603 ;
     RECT  44.136 3.713 46.314 4.649 ;
     RECT  152.172 4.145 157.122 4.649 ;
     RECT  34.815 3.965 35.622 4.699 ;
     RECT  44.784 4.649 46.314 4.721 ;
     RECT  39.816 4.253 40.59 4.733 ;
     RECT  39.816 4.733 40.497 4.757 ;
     RECT  42.768 4.603 43.398 4.781 ;
     RECT  56.304 4.459 89.262 4.829 ;
     RECT  168.984 4.289 170.442 4.829 ;
     RECT  148.215 4.379 151.326 4.891 ;
     RECT  152.172 4.649 156.597 4.891 ;
     RECT  36.756 4.555 36.774 4.939 ;
     RECT  47.304 4.493 51.57 4.987 ;
     RECT  163.836 3.005 165.006 4.987 ;
     RECT  42.915 4.781 43.398 4.991 ;
     RECT  159.015 3.947 162.738 5.021 ;
     RECT  148.215 4.891 156.597 5.063 ;
     RECT  90.216 4.289 92.07 5.083 ;
     RECT  92.88 4.451 145.797 5.083 ;
     RECT  21.315 4.289 21.978 5.131 ;
     RECT  56.415 4.829 89.262 5.161 ;
     RECT  90.216 5.083 145.797 5.161 ;
     RECT  42.915 4.991 43.362 5.165 ;
     RECT  34.776 4.699 35.622 5.179 ;
     RECT  56.415 5.161 145.797 5.197 ;
     RECT  148.215 5.063 152.19 5.297 ;
     RECT  36.504 4.939 36.774 5.309 ;
     RECT  56.415 5.197 146.502 5.309 ;
     RECT  37.515 4.253 38.79 5.323 ;
     RECT  46.944 4.987 51.57 5.323 ;
     RECT  52.488 4.493 54.882 5.323 ;
     RECT  22.824 4.289 22.842 5.357 ;
     RECT  20.808 5.131 21.978 5.495 ;
     RECT  168.984 4.829 170.262 5.495 ;
     RECT  46.944 5.323 54.954 5.501 ;
     RECT  42.915 5.165 43.29 5.503 ;
     RECT  29.415 4.555 32.886 5.567 ;
     RECT  159.015 5.021 161.997 5.567 ;
     RECT  179.172 2.255 179.262 5.603 ;
     RECT  42.768 5.503 43.29 5.639 ;
     RECT  40.215 4.757 40.497 5.659 ;
     RECT  163.836 4.987 165.33 5.659 ;
     RECT  166.14 2.099 167.397 5.659 ;
     RECT  40.215 5.659 40.59 5.729 ;
     RECT  44.784 4.721 45.99 5.729 ;
     RECT  37.515 5.323 38.898 5.765 ;
     RECT  36.756 5.309 36.774 5.8 ;
     RECT  37.515 5.765 37.998 5.8 ;
     RECT  29.415 5.567 32.814 5.801 ;
     RECT  42.84 5.639 43.29 5.801 ;
     RECT  152.172 5.297 152.19 5.801 ;
     RECT  66.384 5.309 146.502 5.809 ;
     RECT  36.756 5.8 37.998 5.837 ;
     RECT  38.772 5.765 38.898 5.837 ;
     RECT  47.376 5.501 54.918 5.837 ;
     RECT  37.515 5.837 37.998 5.843 ;
     RECT  47.376 5.837 53.997 5.873 ;
     RECT  66.384 5.809 147.042 5.873 ;
     RECT  159.015 5.567 159.786 5.873 ;
     RECT  56.415 5.309 65.538 5.881 ;
     RECT  153.288 5.063 156.597 5.909 ;
     RECT  54.72 5.837 54.882 5.933 ;
     RECT  56.304 5.881 65.538 5.933 ;
     RECT  56.415 5.933 65.538 6.035 ;
     RECT  21.315 5.495 21.978 6.077 ;
     RECT  34.2 5.179 35.622 6.143 ;
     RECT  38.772 5.837 38.862 6.179 ;
     RECT  57.564 6.035 65.538 6.179 ;
     RECT  66.384 5.873 145.797 6.221 ;
     RECT  40.215 5.729 40.497 6.283 ;
     RECT  42.915 5.801 43.29 6.283 ;
     RECT  42.915 6.283 43.362 6.331 ;
     RECT  29.415 5.801 32.778 6.341 ;
     RECT  147.024 5.873 147.042 6.377 ;
     RECT  160.992 5.567 161.997 6.379 ;
     RECT  162.72 5.021 162.738 6.379 ;
     RECT  148.215 5.297 151.326 6.449 ;
     RECT  66.384 6.221 86.397 6.575 ;
     RECT  42.915 6.331 43.722 6.619 ;
     RECT  169.815 5.495 170.262 6.619 ;
     RECT  38.772 6.179 38.79 6.653 ;
     RECT  159.015 5.873 159.714 6.667 ;
     RECT  160.992 6.379 162.738 6.667 ;
     RECT  29.415 6.341 32.397 6.683 ;
     RECT  155.052 5.909 156.597 6.691 ;
     RECT  176.976 3.713 178.434 6.809 ;
     RECT  149.22 6.449 151.326 6.844 ;
     RECT  152.208 6.781 152.226 6.844 ;
     RECT  52.488 5.873 53.997 6.853 ;
     RECT  54.864 5.933 54.882 6.853 ;
     RECT  37.515 5.843 37.797 6.859 ;
     RECT  153.288 5.909 153.897 6.859 ;
     RECT  154.98 6.691 156.597 6.859 ;
     RECT  47.376 5.873 51.57 6.893 ;
     RECT  153.288 6.859 156.597 6.907 ;
     RECT  174.096 4.157 174.114 6.907 ;
     RECT  175.215 3.335 175.914 6.907 ;
     RECT  149.22 6.844 152.226 6.917 ;
     RECT  148.215 6.449 148.497 6.961 ;
     RECT  47.376 6.893 49.266 7.051 ;
     RECT  40.104 6.283 40.497 7.115 ;
     RECT  84.528 6.575 86.397 7.123 ;
     RECT  87.12 6.221 145.797 7.123 ;
     RECT  174.096 6.907 175.914 7.133 ;
     RECT  60.12 6.179 65.538 7.147 ;
     RECT  153.252 6.907 156.597 7.147 ;
     RECT  46.656 7.051 49.266 7.151 ;
     RECT  149.904 6.917 152.226 7.151 ;
     RECT  174.096 7.133 175.497 7.181 ;
     RECT  44.784 5.729 45.897 7.187 ;
     RECT  157.32 4.987 157.338 7.195 ;
     RECT  152.964 7.147 156.597 7.231 ;
     RECT  157.32 7.195 157.374 7.231 ;
     RECT  159.015 6.667 162.738 7.243 ;
     RECT  84.528 7.123 145.797 7.321 ;
     RECT  163.836 5.659 167.397 7.373 ;
     RECT  66.384 6.575 83.79 7.385 ;
     RECT  158.472 7.243 162.738 7.421 ;
     RECT  148.176 6.961 148.497 7.429 ;
     RECT  37.515 6.859 38.106 7.435 ;
     RECT  66.708 7.385 83.79 7.435 ;
     RECT  84.528 7.321 146.502 7.435 ;
     RECT  152.964 7.231 157.374 7.435 ;
     RECT  66.708 7.435 146.502 7.457 ;
     RECT  169.815 6.619 170.982 7.457 ;
     RECT  130.716 7.457 146.502 7.483 ;
     RECT  158.544 7.421 162.738 7.493 ;
     RECT  130.716 7.483 146.61 7.501 ;
     RECT  160.416 7.493 162.738 7.529 ;
     RECT  148.176 7.429 148.59 7.579 ;
     RECT  42.192 6.619 43.722 7.591 ;
     RECT  130.716 7.501 146.646 7.591 ;
     RECT  148.104 7.579 148.59 7.619 ;
     RECT  37.515 7.435 38.646 7.655 ;
     RECT  152.964 7.435 157.482 7.655 ;
     RECT  153.072 7.655 157.482 7.661 ;
     RECT  174.096 7.181 174.114 7.661 ;
     RECT  179.244 5.603 179.262 7.709 ;
     RECT  130.716 7.591 146.718 7.727 ;
     RECT  149.904 7.151 151.794 7.727 ;
     RECT  153.072 7.661 156.69 7.727 ;
     RECT  160.416 7.529 162.558 7.757 ;
     RECT  176.976 6.809 178.197 7.757 ;
     RECT  42.192 7.591 43.902 7.861 ;
     RECT  148.215 7.619 148.59 7.889 ;
     RECT  150.48 7.727 151.794 7.889 ;
     RECT  156.315 7.727 156.69 7.889 ;
     RECT  37.515 7.655 38.106 7.925 ;
     RECT  57.564 6.179 59.397 7.925 ;
     RECT  60.12 7.147 65.574 7.949 ;
     RECT  130.716 7.727 146.682 7.949 ;
     RECT  42.192 7.861 43.938 7.961 ;
     RECT  60.12 7.949 65.538 7.997 ;
     RECT  44.784 7.187 44.802 8.155 ;
     RECT  45.615 7.187 45.897 8.155 ;
     RECT  66.708 7.457 129.978 8.159 ;
     RECT  42.228 7.961 43.938 8.231 ;
     RECT  153.072 7.727 155.394 8.231 ;
     RECT  158.544 7.493 159.297 8.251 ;
     RECT  150.915 7.889 151.614 8.267 ;
     RECT  153.072 8.231 155.07 8.303 ;
     RECT  130.716 7.949 146.61 8.333 ;
     RECT  84.564 8.159 129.978 8.401 ;
     RECT  130.716 8.333 146.502 8.401 ;
     RECT  37.515 7.925 37.89 8.465 ;
     RECT  44.784 8.155 45.897 8.477 ;
     RECT  50.184 6.893 51.57 8.525 ;
     RECT  36.756 5.837 36.774 8.539 ;
     RECT  37.515 8.465 37.797 8.539 ;
     RECT  66.708 8.159 83.79 8.573 ;
     RECT  163.836 7.373 165.69 8.699 ;
     RECT  42.228 8.231 43.902 8.735 ;
     RECT  42.915 8.735 43.902 8.771 ;
     RECT  160.416 7.757 161.997 8.813 ;
     RECT  58.14 7.925 59.397 8.827 ;
     RECT  47.376 7.151 49.266 8.851 ;
     RECT  84.564 8.401 146.502 8.879 ;
     RECT  158.436 8.251 159.297 8.879 ;
     RECT  74.376 8.573 83.79 8.941 ;
     RECT  84.564 8.879 92.25 8.941 ;
     RECT  92.988 8.879 146.502 8.969 ;
     RECT  60.12 7.997 65.43 9.005 ;
     RECT  153.252 8.303 155.07 9.053 ;
     RECT  66.708 8.573 73.53 9.077 ;
     RECT  66.744 9.077 73.53 9.113 ;
     RECT  93.06 8.969 146.502 9.113 ;
     RECT  166.716 7.373 167.397 9.113 ;
     RECT  160.992 8.813 161.997 9.115 ;
     RECT  169.815 7.457 170.262 9.115 ;
     RECT  93.456 9.113 146.502 9.293 ;
     RECT  153.252 9.053 154.494 9.293 ;
     RECT  169.815 9.115 170.442 9.293 ;
     RECT  93.456 9.293 145.797 9.347 ;
     RECT  176.976 7.757 176.994 9.383 ;
     RECT  153.252 9.293 153.897 9.419 ;
     RECT  45.615 8.477 45.897 9.481 ;
     RECT  46.728 8.851 49.266 9.481 ;
     RECT  36.756 8.539 37.797 9.545 ;
     RECT  45.615 9.481 49.266 9.617 ;
     RECT  160.992 9.115 162.486 9.689 ;
     RECT  74.376 8.941 92.25 9.859 ;
     RECT  93.456 9.347 103.014 9.859 ;
     RECT  45.615 9.617 46.206 9.887 ;
     RECT  163.836 8.699 165.006 9.887 ;
     RECT  103.932 9.347 145.797 10.027 ;
     RECT  153.615 9.419 153.897 10.027 ;
     RECT  74.376 9.859 103.014 10.049 ;
     RECT  161.715 9.689 162.486 10.061 ;
     RECT  103.932 10.027 146.502 10.085 ;
     RECT  30.456 6.683 32.397 10.109 ;
     RECT  104.148 10.085 146.502 10.157 ;
     RECT  153.615 10.027 154.494 10.157 ;
     RECT  161.715 10.061 162.09 10.157 ;
     RECT  129.315 10.157 146.502 10.363 ;
     RECT  67.032 9.113 73.53 10.399 ;
     RECT  66.744 10.399 73.53 10.411 ;
     RECT  57.564 8.827 59.397 10.427 ;
     RECT  42.915 8.771 43.722 10.463 ;
     RECT  169.815 9.293 170.262 10.463 ;
     RECT  129.315 10.363 146.61 10.493 ;
     RECT  93.384 10.049 103.014 10.499 ;
     RECT  163.836 9.887 164.697 10.589 ;
     RECT  66.708 10.411 73.53 10.685 ;
     RECT  129.315 10.493 146.502 10.685 ;
     RECT  93.564 10.499 103.014 10.733 ;
     RECT  47.376 9.617 49.266 10.843 ;
     RECT  168.984 5.495 169.002 10.859 ;
     RECT  44.784 8.477 44.802 10.967 ;
     RECT  38.772 10.843 38.79 10.973 ;
     RECT  46.764 10.843 49.266 10.973 ;
     RECT  74.376 10.049 92.25 11.165 ;
     RECT  36.756 9.545 36.774 11.237 ;
     RECT  93.924 10.733 103.014 11.281 ;
     RECT  104.148 10.157 128.214 11.281 ;
     RECT  84.564 11.165 92.25 12.829 ;
     RECT  30.456 10.109 31.05 13.127 ;
     RECT  30.456 13.127 30.474 13.163 ;
     RECT  34.815 6.143 35.622 13.199 ;
     RECT  129.315 10.685 145.797 13.289 ;
     RECT  74.376 11.165 83.697 13.981 ;
     RECT  84.564 12.829 92.502 13.981 ;
     RECT  67.032 10.685 73.53 14.521 ;
     RECT  58.176 10.427 59.397 15.061 ;
     RECT  60.228 9.005 65.43 15.061 ;
     RECT  74.376 13.981 92.502 15.187 ;
     RECT  58.176 15.061 65.43 15.691 ;
     RECT  57.816 15.691 65.43 16.267 ;
     RECT  66.672 14.521 73.53 16.267 ;
     RECT  139.356 13.289 145.797 17.411 ;
     RECT  50.184 8.525 51.426 17.951 ;
     RECT  56.415 6.035 56.697 18.499 ;
     RECT  57.816 16.267 73.53 18.499 ;
     RECT  52.488 6.853 54.882 21.965 ;
     RECT  129.315 13.289 138.366 21.965 ;
     RECT  74.376 15.187 93.114 22.009 ;
     RECT  140.115 17.411 145.797 24.233 ;
     RECT  47.376 10.973 49.266 24.359 ;
     RECT  53.715 21.965 54.882 24.781 ;
     RECT  140.115 24.233 143.658 24.809 ;
     RECT  74.376 22.009 93.186 24.907 ;
     RECT  93.924 11.281 128.214 24.907 ;
     RECT  48.315 24.359 49.266 24.935 ;
     RECT  141.912 24.809 143.658 25.349 ;
     RECT  53.715 24.781 55.386 25.951 ;
     RECT  56.415 18.499 73.53 25.951 ;
     RECT  144.684 24.233 145.797 26.519 ;
     RECT  144.684 26.519 144.702 27.095 ;
     RECT  74.376 24.907 128.214 27.167 ;
     RECT  74.376 27.167 123.066 28.219 ;
     RECT  123.915 27.167 128.214 28.219 ;
     RECT  50.22 17.951 51.426 28.319 ;
     RECT  53.715 25.951 73.53 28.787 ;
     RECT  141.912 25.349 141.93 28.787 ;
     RECT  74.376 28.219 128.214 28.823 ;
     RECT  47.376 24.359 47.502 30.029 ;
     RECT  74.376 28.823 127.89 30.479 ;
     RECT  55.368 28.787 73.53 30.839 ;
     RECT  50.328 28.319 51.426 31.181 ;
     RECT  140.115 24.809 141.03 32.225 ;
     RECT  52.488 21.965 52.722 32.909 ;
     RECT  74.376 30.479 127.602 33.341 ;
     RECT  52.56 32.909 52.722 33.539 ;
     RECT  128.556 33.511 128.574 33.583 ;
     RECT  103.932 33.341 127.602 33.691 ;
     RECT  128.448 33.583 128.574 33.691 ;
     RECT  129.315 21.965 137.754 33.691 ;
     RECT  55.368 30.839 73.386 33.817 ;
     RECT  47.484 30.029 47.502 33.953 ;
     RECT  50.328 31.181 51.297 33.989 ;
     RECT  74.376 33.341 103.014 34.075 ;
     RECT  52.704 33.539 52.722 34.115 ;
     RECT  55.368 33.817 73.53 34.195 ;
     RECT  74.34 34.075 103.014 34.195 ;
     RECT  103.932 33.691 137.754 34.195 ;
     RECT  139.356 17.411 139.374 34.259 ;
     RECT  55.368 34.195 137.754 34.771 ;
     RECT  142.815 25.349 143.658 34.799 ;
     RECT  55.368 34.771 137.898 34.931 ;
     RECT  50.544 33.989 51.297 34.997 ;
     RECT  133.236 34.931 137.898 35.041 ;
     RECT  53.715 28.787 54.486 35.537 ;
     RECT  133.236 35.041 138.006 35.581 ;
     RECT  53.715 35.537 54.414 35.609 ;
     RECT  55.368 34.931 132.498 35.969 ;
     RECT  55.368 35.969 128.214 36.859 ;
     RECT  128.952 35.969 132.498 36.859 ;
     RECT  55.368 36.859 132.498 37.021 ;
     RECT  133.236 35.581 138.402 37.021 ;
     RECT  55.368 37.021 138.402 37.319 ;
     RECT  55.368 37.319 128.43 37.625 ;
     RECT  129.204 37.319 138.402 37.895 ;
     RECT  129.315 37.895 138.402 38.011 ;
     RECT  55.368 37.625 55.386 38.155 ;
     RECT  55.224 38.155 55.386 38.435 ;
     RECT  56.304 37.625 128.43 38.551 ;
     RECT  56.16 38.551 128.43 38.821 ;
     RECT  55.728 38.821 128.43 39.559 ;
     RECT  129.315 38.011 138.618 39.865 ;
     RECT  129.315 39.865 138.798 39.991 ;
     RECT  129.276 39.991 138.798 40.441 ;
     RECT  55.26 39.559 128.43 40.559 ;
     RECT  129.276 40.441 139.122 40.559 ;
     RECT  55.26 40.559 74.25 40.595 ;
     RECT  55.26 40.595 74.142 40.675 ;
     RECT  104.688 40.559 128.43 40.711 ;
     RECT  129.276 40.559 138.69 40.711 ;
     RECT  2.415 2.413 2.697 40.787 ;
     RECT  5.115 2.413 5.397 40.787 ;
     RECT  7.815 2.413 8.097 40.787 ;
     RECT  10.515 2.413 10.797 40.787 ;
     RECT  13.215 2.413 13.497 40.787 ;
     RECT  15.915 2.413 16.197 40.787 ;
     RECT  18.615 2.413 18.897 40.787 ;
     RECT  21.315 6.077 21.597 40.787 ;
     RECT  24.015 3.917 24.297 40.787 ;
     RECT  26.715 3.029 26.997 40.787 ;
     RECT  29.415 6.683 29.697 40.787 ;
     RECT  32.115 10.109 32.397 40.787 ;
     RECT  34.815 13.199 35.097 40.787 ;
     RECT  37.515 9.545 37.797 40.787 ;
     RECT  40.215 7.115 40.497 40.787 ;
     RECT  42.915 10.463 43.197 40.787 ;
     RECT  45.615 9.887 45.897 40.787 ;
     RECT  48.315 24.935 48.597 40.787 ;
     RECT  51.015 34.997 51.297 40.787 ;
     RECT  53.715 35.609 53.997 40.787 ;
     RECT  140.115 32.225 140.397 40.787 ;
     RECT  142.815 34.799 143.097 40.787 ;
     RECT  145.515 26.519 145.797 40.787 ;
     RECT  148.215 7.889 148.497 40.787 ;
     RECT  150.915 8.267 151.197 40.787 ;
     RECT  153.615 10.157 153.897 40.787 ;
     RECT  156.315 7.889 156.597 40.787 ;
     RECT  159.015 8.879 159.297 40.787 ;
     RECT  161.715 10.157 161.997 40.787 ;
     RECT  164.415 10.589 164.697 40.787 ;
     RECT  167.115 9.113 167.397 40.787 ;
     RECT  169.815 10.463 170.097 40.787 ;
     RECT  172.515 2.597 172.797 40.787 ;
     RECT  175.215 7.181 175.497 40.787 ;
     RECT  177.915 7.757 178.197 40.787 ;
     RECT  180.615 3.875 180.897 40.787 ;
     RECT  183.315 2.413 183.597 40.787 ;
     RECT  186.015 2.413 186.297 40.787 ;
     RECT  55.152 40.675 74.142 40.829 ;
     RECT  75.204 40.559 103.914 40.829 ;
     RECT  104.688 40.711 138.69 40.829 ;
     RECT  123.696 40.829 136.422 40.865 ;
     RECT  55.152 40.829 59.706 40.901 ;
     RECT  91.188 40.829 91.605 40.901 ;
     RECT  101.7 40.829 103.914 40.901 ;
     RECT  107.676 40.829 111.474 40.901 ;
     RECT  115.164 40.829 115.974 40.901 ;
     RECT  123.696 40.865 128.466 40.901 ;
     RECT  137.376 40.829 138.402 40.901 ;
     RECT  97.884 40.829 100.71 40.925 ;
     RECT  129.276 40.865 136.422 40.925 ;
     RECT  75.24 40.829 82.206 40.973 ;
     RECT  138.276 40.901 138.402 40.973 ;
     RECT  55.368 40.901 59.706 41.009 ;
     RECT  60.48 40.829 63.054 41.009 ;
     RECT  65.808 40.829 65.826 41.009 ;
     RECT  67.176 40.829 73.818 41.009 ;
     RECT  75.24 40.973 81.198 41.009 ;
     RECT  83.196 40.829 84.114 41.009 ;
     RECT  85.356 40.829 86.958 41.009 ;
     RECT  87.732 40.829 88.905 41.009 ;
     RECT  89.928 40.829 90.198 41.009 ;
     RECT  100.692 40.925 100.71 41.009 ;
     RECT  101.844 40.901 103.914 41.009 ;
     RECT  106.596 40.829 106.614 41.009 ;
     RECT  110.415 40.901 111.474 41.009 ;
     RECT  115.164 40.901 115.905 41.009 ;
     RECT  116.856 40.829 117.306 41.009 ;
     RECT  118.368 40.829 118.605 41.009 ;
     RECT  119.556 40.829 121.554 41.009 ;
     RECT  123.696 40.901 124.29 41.009 ;
     RECT  125.064 40.901 128.466 41.009 ;
     RECT  138.384 40.973 138.402 41.009 ;
     RECT  60.732 41.009 62.586 41.021 ;
     RECT  67.215 41.009 67.734 41.021 ;
     RECT  69.336 41.009 72.99 41.021 ;
     RECT  73.8 41.009 73.818 41.021 ;
     RECT  78.015 41.009 81.198 41.021 ;
     RECT  82.188 40.973 82.206 41.021 ;
     RECT  83.196 41.009 83.97 41.021 ;
     RECT  87.732 41.009 87.75 41.021 ;
     RECT  90.18 41.009 90.198 41.021 ;
     RECT  93.888 40.829 97.005 41.021 ;
     RECT  97.884 40.925 99.705 41.021 ;
     RECT  101.844 41.009 103.734 41.021 ;
     RECT  107.715 40.901 109.422 41.021 ;
     RECT  114.372 40.829 114.426 41.021 ;
     RECT  119.556 41.009 120.474 41.021 ;
     RECT  125.604 41.009 128.466 41.021 ;
     RECT  129.276 40.925 132.105 41.021 ;
     RECT  133.02 40.925 136.422 41.021 ;
     RECT  2.415 40.787 2.505 41.057 ;
     RECT  5.115 40.787 5.205 41.057 ;
     RECT  7.815 40.787 7.905 41.057 ;
     RECT  10.515 40.787 10.605 41.057 ;
     RECT  13.215 40.787 13.305 41.057 ;
     RECT  15.915 40.787 16.005 41.057 ;
     RECT  18.615 40.787 18.705 41.057 ;
     RECT  21.315 40.787 21.405 41.057 ;
     RECT  24.015 40.787 24.105 41.057 ;
     RECT  26.715 40.787 26.805 41.057 ;
     RECT  29.415 40.787 29.505 41.057 ;
     RECT  32.115 40.787 32.205 41.057 ;
     RECT  34.815 40.787 34.905 41.057 ;
     RECT  37.515 40.787 37.605 41.057 ;
     RECT  40.215 40.787 40.305 41.057 ;
     RECT  42.915 40.787 43.005 41.057 ;
     RECT  45.615 40.787 45.705 41.057 ;
     RECT  48.315 40.787 48.405 41.057 ;
     RECT  51.015 40.787 51.105 41.057 ;
     RECT  53.715 40.787 53.805 41.057 ;
     RECT  63.972 40.829 64.605 41.057 ;
     RECT  67.215 41.021 67.305 41.057 ;
     RECT  72.615 41.021 72.99 41.057 ;
     RECT  78.015 41.021 79.614 41.057 ;
     RECT  80.715 41.021 81.198 41.057 ;
     RECT  86.115 41.009 86.562 41.057 ;
     RECT  88.776 41.009 88.905 41.057 ;
     RECT  91.515 40.901 91.605 41.057 ;
     RECT  96.915 41.021 97.005 41.057 ;
     RECT  98.712 41.021 99.705 41.057 ;
     RECT  102.132 41.021 103.734 41.057 ;
     RECT  107.715 41.021 108.99 41.057 ;
     RECT  110.415 41.009 110.826 41.057 ;
     RECT  112.896 40.829 113.205 41.057 ;
     RECT  115.776 41.009 115.905 41.057 ;
     RECT  118.44 41.009 118.605 41.057 ;
     RECT  121.215 41.009 121.554 41.057 ;
     RECT  126.144 41.021 128.07 41.057 ;
     RECT  132.015 41.021 132.105 41.057 ;
     RECT  137.376 40.901 137.505 41.057 ;
     RECT  140.115 40.787 140.205 41.057 ;
     RECT  142.815 40.787 142.905 41.057 ;
     RECT  145.515 40.787 145.605 41.057 ;
     RECT  148.215 40.787 148.305 41.057 ;
     RECT  150.915 40.787 151.005 41.057 ;
     RECT  153.615 40.787 153.705 41.057 ;
     RECT  156.315 40.787 156.405 41.057 ;
     RECT  159.015 40.787 159.105 41.057 ;
     RECT  161.715 40.787 161.805 41.057 ;
     RECT  164.415 40.787 164.505 41.057 ;
     RECT  167.115 40.787 167.205 41.057 ;
     RECT  169.815 40.787 169.905 41.057 ;
     RECT  172.515 40.787 172.605 41.057 ;
     RECT  175.215 40.787 175.305 41.057 ;
     RECT  177.915 40.787 178.005 41.057 ;
     RECT  180.615 40.787 180.705 41.057 ;
     RECT  183.315 40.787 183.405 41.057 ;
     RECT  186.015 40.787 186.105 41.057 ;
     RECT  55.476 41.009 59.706 41.069 ;
     RECT  83.304 41.021 83.97 41.069 ;
     RECT  93.888 41.021 96.138 41.069 ;
     RECT  126.144 41.057 126.162 41.069 ;
     RECT  72.756 41.057 72.99 41.165 ;
     RECT  75.24 41.009 77.094 41.165 ;
     RECT  78.444 41.057 79.614 41.165 ;
     RECT  80.892 41.057 81.198 41.165 ;
     RECT  83.304 41.069 83.574 41.165 ;
     RECT  86.472 41.057 86.562 41.165 ;
     RECT  93.888 41.069 95.13 41.165 ;
     RECT  80.892 41.165 80.91 41.213 ;
     RECT  83.556 41.165 83.574 41.213 ;
     RECT  88.776 41.057 88.794 41.213 ;
     RECT  102.132 41.057 102.15 41.213 ;
     RECT  112.896 41.057 113.058 41.213 ;
     RECT  115.776 41.057 115.794 41.213 ;
     RECT  123.804 41.009 124.29 41.213 ;
     RECT  126.936 41.057 128.07 41.213 ;
     RECT  137.376 41.057 137.394 41.213 ;
     RECT  112.896 41.213 112.914 41.309 ;
     RECT  121.536 41.057 121.554 41.309 ;
     RECT  124.272 41.213 124.29 41.357 ;
     RECT  102.888 41.057 103.734 41.549 ;
     RECT  108.18 41.057 108.99 41.549 ;
     RECT  133.02 41.021 133.866 41.549 ;
     RECT  55.476 41.069 56.574 41.597 ;
     RECT  60.732 41.021 62.226 41.597 ;
     RECT  69.84 41.021 70.614 41.597 ;
     RECT  72.756 41.165 72.774 41.597 ;
     RECT  75.456 41.165 77.094 41.597 ;
     RECT  78.912 41.165 79.614 41.597 ;
     RECT  85.356 41.009 85.374 41.597 ;
     RECT  98.712 41.057 99.342 41.597 ;
     RECT  103.392 41.549 103.734 41.597 ;
     RECT  104.796 40.829 105.714 41.597 ;
     RECT  108.18 41.549 108.522 41.597 ;
     RECT  119.556 41.021 119.574 41.597 ;
     RECT  133.092 41.549 133.866 41.597 ;
     RECT  134.676 41.021 136.134 41.597 ;
     RECT  61.38 41.597 62.226 41.645 ;
     RECT  129.276 41.021 130.95 41.645 ;
     RECT  108.324 41.597 108.342 41.885 ;
     RECT  129.888 41.645 130.95 42.125 ;
     RECT  118.44 41.057 118.458 42.139 ;
     RECT  55.476 41.597 56.25 42.173 ;
     RECT  57.672 41.069 59.706 42.173 ;
     RECT  63.972 41.057 63.99 42.173 ;
     RECT  75.456 41.597 76.878 42.173 ;
     RECT  79.596 41.597 79.614 42.173 ;
     RECT  86.544 41.165 86.562 42.173 ;
     RECT  93.888 41.165 93.906 42.173 ;
     RECT  94.644 41.165 95.13 42.173 ;
     RECT  98.82 41.597 98.838 42.173 ;
     RECT  114.372 41.021 114.39 42.173 ;
     RECT  118.44 42.139 119.106 42.173 ;
     RECT  120.456 41.021 120.474 42.173 ;
     RECT  129.888 42.125 130.77 42.173 ;
     RECT  133.344 41.597 133.866 42.173 ;
     RECT  134.676 41.597 135.198 42.173 ;
     RECT  135.972 41.597 135.99 42.173 ;
     RECT  103.716 41.597 103.734 42.221 ;
     RECT  127.152 41.213 128.07 42.221 ;
     RECT  129.888 42.173 130.05 42.221 ;
     RECT  135.18 42.173 135.198 42.221 ;
     RECT  127.368 42.221 128.07 42.317 ;
     RECT  94.644 42.173 94.662 42.893 ;
     RECT  59.544 42.173 59.706 43.037 ;
     RECT  76.104 42.173 76.302 43.037 ;
     RECT  55.476 42.173 55.494 43.085 ;
     RECT  56.232 42.173 56.25 43.085 ;
     RECT  59.544 43.037 59.562 43.085 ;
     RECT  61.38 41.645 61.794 43.085 ;
     RECT  69.84 41.597 69.858 43.085 ;
     RECT  76.104 43.037 76.122 43.085 ;
     RECT  96.12 41.069 96.138 43.085 ;
     RECT  97.884 41.021 97.902 43.085 ;
     RECT  105.696 41.597 105.714 43.085 ;
     RECT  110.808 41.057 110.826 43.085 ;
     RECT  113.76 42.859 113.778 43.085 ;
     RECT  117.288 41.009 117.306 43.085 ;
     RECT  119.088 42.173 119.106 43.085 ;
     RECT  128.052 42.317 128.07 43.085 ;
     RECT  129.888 42.221 129.906 43.085 ;
     RECT  133.848 42.173 133.866 43.085 ;
    LAYER M4 ;
     RECT  0.06 22.896 0.227 22.92 ;
     RECT  0.181 36.576 2.408 36.6 ;
     RECT  2.408 2.148 2.512 41.052 ;
     RECT  2.512 2.418 2.704 40.782 ;
     RECT  2.704 36.576 5.108 36.6 ;
     RECT  5.108 2.148 5.212 41.052 ;
     RECT  5.212 2.418 5.404 40.782 ;
     RECT  5.404 36.576 7.808 36.6 ;
     RECT  7.808 2.148 7.912 41.052 ;
     RECT  7.912 2.418 8.104 40.782 ;
     RECT  8.104 36.576 10.508 36.6 ;
     RECT  10.508 2.148 10.612 41.052 ;
     RECT  10.612 2.418 10.804 40.782 ;
     RECT  10.804 36.576 13.208 36.6 ;
     RECT  13.208 2.148 13.312 41.052 ;
     RECT  13.312 2.418 13.504 40.782 ;
     RECT  13.504 36.576 15.908 36.6 ;
     RECT  15.908 2.148 16.012 41.052 ;
     RECT  16.012 2.418 16.204 40.782 ;
     RECT  16.204 36.576 18.608 36.6 ;
     RECT  18.608 2.148 18.712 41.052 ;
     RECT  18.712 2.148 18.904 40.782 ;
     RECT  18.904 2.148 19.285 2.616 ;
     RECT  19.285 1.728 19.573 2.616 ;
     RECT  19.573 0.912 19.717 2.616 ;
     RECT  19.717 0.816 20.149 2.616 ;
     RECT  20.149 0.816 20.293 2.808 ;
     RECT  20.293 0.096 21.013 2.808 ;
     RECT  21.013 0.096 21.308 3.384 ;
     RECT  18.904 5.136 21.308 5.16 ;
     RECT  18.904 36.576 21.308 36.6 ;
     RECT  21.308 0.096 21.412 41.052 ;
     RECT  21.412 0.096 21.604 40.782 ;
     RECT  21.604 5.328 22.813 6.072 ;
     RECT  21.604 0.096 23.353 3.384 ;
     RECT  22.813 4.704 23.353 6.072 ;
     RECT  23.353 0.096 24.008 6.072 ;
     RECT  21.604 36.576 24.008 36.6 ;
     RECT  24.008 0.096 24.112 41.052 ;
     RECT  24.112 0.096 24.304 40.782 ;
     RECT  24.304 0.096 26.708 6.072 ;
     RECT  24.304 36.576 26.708 36.6 ;
     RECT  26.708 0.096 26.809 41.052 ;
     RECT  26.809 0.048 26.812 41.052 ;
     RECT  26.812 0.048 27.004 40.782 ;
     RECT  27.004 0.048 29.408 6.072 ;
     RECT  27.004 36.576 29.408 36.6 ;
     RECT  29.408 0.048 29.512 41.052 ;
     RECT  29.512 0.048 29.704 40.782 ;
     RECT  29.704 9.072 31.093 9.096 ;
     RECT  29.704 0.048 31.381 6.072 ;
     RECT  29.704 7.152 31.381 7.416 ;
     RECT  31.093 9.072 31.597 9.816 ;
     RECT  30.949 10.944 31.597 10.968 ;
     RECT  31.381 0.048 32.108 7.416 ;
     RECT  31.597 9.072 32.108 10.968 ;
     RECT  29.704 36.576 32.108 36.6 ;
     RECT  32.108 0.048 32.212 41.052 ;
     RECT  32.212 0.048 32.404 40.782 ;
     RECT  32.404 0.048 33.829 7.416 ;
     RECT  32.404 9.072 33.829 10.968 ;
     RECT  33.829 0.048 34.808 10.968 ;
     RECT  32.404 36.576 34.808 36.6 ;
     RECT  34.808 0.048 34.912 41.052 ;
     RECT  34.912 0.048 35.104 40.782 ;
     RECT  35.104 0.048 37.508 10.968 ;
     RECT  35.104 13.104 37.508 13.128 ;
     RECT  35.104 36.576 37.508 36.6 ;
     RECT  37.508 0.048 37.612 41.052 ;
     RECT  37.612 0.048 37.804 40.782 ;
     RECT  37.804 0.048 38.117 10.968 ;
     RECT  38.117 0.096 40.208 10.968 ;
     RECT  37.804 13.104 40.208 13.128 ;
     RECT  37.804 36.576 40.208 36.6 ;
     RECT  40.208 0.096 40.312 41.052 ;
     RECT  40.312 0.096 40.504 40.782 ;
     RECT  40.504 0.096 42.908 10.968 ;
     RECT  40.504 13.104 42.908 13.128 ;
     RECT  40.504 36.576 42.908 36.6 ;
     RECT  42.908 0.096 43.012 41.052 ;
     RECT  43.012 0.096 43.204 40.782 ;
     RECT  43.204 0.096 43.513 10.968 ;
     RECT  43.513 0.048 45.608 10.968 ;
     RECT  43.204 13.104 45.608 13.128 ;
     RECT  43.204 36.576 45.608 36.6 ;
     RECT  45.608 0.048 45.712 41.052 ;
     RECT  45.712 0.048 45.904 40.782 ;
     RECT  45.904 0.048 48.308 10.968 ;
     RECT  45.904 13.104 48.308 13.128 ;
     RECT  45.904 36.576 48.308 36.6 ;
     RECT  48.308 0.048 48.412 41.052 ;
     RECT  48.412 0.048 48.604 40.782 ;
     RECT  48.604 0.048 49.133 10.968 ;
     RECT  49.133 0.096 49.609 10.968 ;
     RECT  49.609 0.144 50.213 10.968 ;
     RECT  50.213 0.192 51.008 10.968 ;
     RECT  48.604 13.104 51.008 13.128 ;
     RECT  48.604 36.576 51.008 36.6 ;
     RECT  51.008 0.192 51.112 41.052 ;
     RECT  51.112 0.192 51.253 40.782 ;
     RECT  51.253 0.096 51.304 40.782 ;
     RECT  51.304 0.096 53.708 10.968 ;
     RECT  51.304 13.104 53.708 13.128 ;
     RECT  51.304 36.576 53.708 36.6 ;
     RECT  53.708 0.096 53.812 41.052 ;
     RECT  53.812 0.096 54.004 40.782 ;
     RECT  54.004 0.096 55.465 10.968 ;
     RECT  55.213 38.16 55.645 38.184 ;
     RECT  55.465 43.056 55.825 43.08 ;
     RECT  55.676 41.04 55.897 41.064 ;
     RECT  55.825 42.144 55.897 43.08 ;
     RECT  55.897 41.04 56.051 43.08 ;
     RECT  56.051 43.056 56.261 43.08 ;
     RECT  55.465 0.048 56.408 10.968 ;
     RECT  54.004 13.104 56.408 13.128 ;
     RECT  54.004 36.576 56.408 36.6 ;
     RECT  55.645 37.584 56.408 38.184 ;
     RECT  56.051 41.04 56.408 41.592 ;
     RECT  56.408 0.048 56.704 41.592 ;
     RECT  56.704 40.992 57.203 41.592 ;
     RECT  56.704 37.584 57.557 38.712 ;
     RECT  56.704 35.328 57.769 36.6 ;
     RECT  57.557 37.584 57.769 38.184 ;
     RECT  57.203 40.992 57.805 41.016 ;
     RECT  57.589 42.096 57.809 42.168 ;
     RECT  57.805 40.464 57.953 41.016 ;
     RECT  57.769 35.328 58.273 38.184 ;
     RECT  58.129 39.36 58.556 39.48 ;
     RECT  57.953 40.464 58.556 40.584 ;
     RECT  58.273 34.704 58.561 38.184 ;
     RECT  58.556 39.36 58.561 40.584 ;
     RECT  57.809 42.144 58.844 42.168 ;
     RECT  56.704 0.048 58.889 10.968 ;
     RECT  58.561 34.704 58.981 40.584 ;
     RECT  58.844 41.616 58.981 42.168 ;
     RECT  58.981 34.704 59.105 42.168 ;
     RECT  58.889 0.096 59.108 10.968 ;
     RECT  56.704 13.104 59.108 13.128 ;
     RECT  58.597 17.424 59.108 17.448 ;
     RECT  59.105 34.704 59.108 41.208 ;
     RECT  59.108 0.096 59.219 41.208 ;
     RECT  59.219 0.096 59.363 40.782 ;
     RECT  59.363 0.192 59.404 40.782 ;
     RECT  59.317 43.008 59.573 43.08 ;
     RECT  59.573 43.008 59.717 43.032 ;
     RECT  59.404 34.368 60.221 39.336 ;
     RECT  60.221 35.424 60.469 39.336 ;
     RECT  60.469 35.424 60.553 39.384 ;
     RECT  60.469 41.568 60.977 41.592 ;
     RECT  60.613 40.416 61.081 40.44 ;
     RECT  61.081 39.888 61.477 40.44 ;
     RECT  59.404 0.192 61.669 10.968 ;
     RECT  61.189 43.056 61.669 43.08 ;
     RECT  61.669 0.144 61.808 10.968 ;
     RECT  59.404 13.104 61.808 13.128 ;
     RECT  59.404 14.112 61.808 14.136 ;
     RECT  59.404 17.424 61.808 17.448 ;
     RECT  60.221 34.368 61.808 34.392 ;
     RECT  60.553 35.424 61.808 38.808 ;
     RECT  61.477 39.888 61.808 41.052 ;
     RECT  61.669 43.008 61.849 43.08 ;
     RECT  61.849 43.008 61.955 43.032 ;
     RECT  61.808 0.144 62.053 41.052 ;
     RECT  62.053 0.144 62.104 41.16 ;
     RECT  62.104 40.944 62.156 41.16 ;
     RECT  62.156 40.944 62.165 41.64 ;
     RECT  62.165 40.992 62.243 41.64 ;
     RECT  62.104 0.144 62.773 10.968 ;
     RECT  62.104 17.328 62.885 17.448 ;
     RECT  62.243 40.992 63.251 41.016 ;
     RECT  62.104 34.368 63.313 39.912 ;
     RECT  63.445 43.008 63.827 43.032 ;
     RECT  63.917 42.144 64.001 42.84 ;
     RECT  63.313 34.368 64.213 40.488 ;
     RECT  64.213 34.368 64.261 40.68 ;
     RECT  62.773 0.048 64.508 10.968 ;
     RECT  62.104 12.048 64.508 12.072 ;
     RECT  62.104 13.104 64.508 13.128 ;
     RECT  62.104 14.112 64.508 14.136 ;
     RECT  62.885 17.424 64.508 17.448 ;
     RECT  64.261 34.368 64.508 41.208 ;
     RECT  64.508 0.048 64.547 41.208 ;
     RECT  64.547 0.048 64.612 41.052 ;
     RECT  64.001 42.816 64.789 42.84 ;
     RECT  64.612 0.048 64.804 41.016 ;
     RECT  64.789 42.816 64.933 42.984 ;
     RECT  64.804 34.176 64.945 41.016 ;
     RECT  64.933 42.816 64.979 43.032 ;
     RECT  64.979 42.864 65.075 43.032 ;
     RECT  64.945 34.464 65.261 41.016 ;
     RECT  65.075 42.864 65.315 42.984 ;
     RECT  65.315 42.96 65.363 42.984 ;
     RECT  65.261 36.048 65.555 41.016 ;
     RECT  65.261 34.464 66.197 34.872 ;
     RECT  66.197 34.464 66.445 34.776 ;
     RECT  64.804 12.048 66.661 13.128 ;
     RECT  64.804 0.048 67.208 10.968 ;
     RECT  66.661 12 67.208 13.128 ;
     RECT  64.804 14.112 67.208 14.136 ;
     RECT  64.804 17.424 67.208 17.448 ;
     RECT  66.445 34.368 67.208 34.776 ;
     RECT  65.555 36.048 67.208 40.632 ;
     RECT  67.208 0.048 67.312 41.052 ;
     RECT  67.237 43.008 67.381 43.032 ;
     RECT  67.312 0.048 67.504 41.016 ;
     RECT  67.381 42.96 67.525 43.032 ;
     RECT  67.504 34.656 67.645 41.016 ;
     RECT  67.645 36.288 67.745 41.016 ;
     RECT  67.525 42.864 67.811 43.032 ;
     RECT  67.745 36.288 68.147 40.488 ;
     RECT  67.811 43.008 68.195 43.032 ;
     RECT  68.147 40.464 68.885 40.488 ;
     RECT  68.885 40.464 68.965 40.824 ;
     RECT  67.645 34.656 69.037 34.776 ;
     RECT  68.147 36.288 69.037 39.48 ;
     RECT  69.037 34.656 69.205 39.48 ;
     RECT  68.965 40.464 69.205 41.016 ;
     RECT  69.397 43.008 69.829 43.032 ;
     RECT  67.504 0.048 69.908 13.128 ;
     RECT  67.504 14.112 69.908 14.136 ;
     RECT  67.504 17.424 69.908 17.448 ;
     RECT  69.205 34.656 69.908 41.016 ;
     RECT  69.829 43.008 69.913 43.08 ;
     RECT  69.908 0.048 70.117 41.052 ;
     RECT  70.117 0.048 70.204 41.592 ;
     RECT  69.913 43.008 70.499 43.032 ;
     RECT  70.204 34.464 70.625 41.592 ;
     RECT  70.204 17.328 70.733 17.448 ;
     RECT  70.204 0.048 71.557 13.128 ;
     RECT  70.204 14.112 71.557 14.136 ;
     RECT  70.733 17.424 72.277 17.448 ;
     RECT  70.625 34.464 72.493 41.016 ;
     RECT  72.493 34.08 72.565 41.016 ;
     RECT  71.557 0.048 72.608 14.136 ;
     RECT  72.277 16.848 72.608 17.448 ;
     RECT  72.421 32.496 72.608 32.52 ;
     RECT  72.565 34.08 72.608 41.592 ;
     RECT  72.181 43.008 72.755 43.032 ;
     RECT  72.608 0.048 72.785 41.592 ;
     RECT  72.785 0.048 72.904 41.16 ;
     RECT  72.904 34.08 73.001 41.16 ;
     RECT  73.001 34.08 73.253 41.016 ;
     RECT  73.253 38.736 73.289 41.016 ;
     RECT  72.904 0.048 73.577 14.136 ;
     RECT  73.289 39.216 73.613 41.016 ;
     RECT  73.613 39.888 73.829 41.016 ;
     RECT  73.829 39.888 74.117 40.776 ;
     RECT  73.577 0.096 74.689 14.136 ;
     RECT  73.253 34.08 74.876 37.608 ;
     RECT  74.117 39.888 75.124 40.488 ;
     RECT  75.124 39.84 75.229 40.488 ;
     RECT  74.689 0.048 75.308 14.136 ;
     RECT  72.904 16.848 75.308 17.448 ;
     RECT  74.876 33.36 75.308 37.608 ;
     RECT  75.229 39.84 75.308 41.16 ;
     RECT  75.308 0.048 75.445 41.16 ;
     RECT  75.301 42.144 75.445 42.168 ;
     RECT  75.445 0.048 75.485 42.168 ;
     RECT  75.485 0.048 75.604 41.64 ;
     RECT  75.604 34.08 75.773 35.4 ;
     RECT  75.604 40.464 75.779 41.64 ;
     RECT  75.877 43.008 76.133 43.08 ;
     RECT  75.779 40.464 76.211 41.016 ;
     RECT  76.133 43.008 76.313 43.032 ;
     RECT  75.604 39.312 76.385 39.336 ;
     RECT  76.849 42.144 76.933 42.168 ;
     RECT  75.773 34.128 76.957 35.4 ;
     RECT  75.604 36.576 76.957 38.28 ;
     RECT  76.211 40.944 76.993 41.016 ;
     RECT  76.993 40.944 77.021 41.064 ;
     RECT  77.021 40.944 77.105 41.592 ;
     RECT  76.957 34.128 77.281 38.28 ;
     RECT  77.281 34.128 77.461 38.808 ;
     RECT  77.461 34.128 77.677 39.336 ;
     RECT  77.677 34.128 77.845 39.912 ;
     RECT  77.105 40.944 77.845 41.208 ;
     RECT  75.604 0.048 78.008 14.136 ;
     RECT  75.604 16.848 78.008 17.448 ;
     RECT  77.845 34.128 78.008 41.208 ;
     RECT  78.008 0.048 78.304 41.208 ;
     RECT  78.181 43.008 78.419 43.032 ;
     RECT  78.304 40.464 78.473 41.208 ;
     RECT  78.304 34.368 78.761 38.856 ;
     RECT  78.473 40.464 79.085 40.488 ;
     RECT  78.901 41.568 79.121 41.592 ;
     RECT  78.761 36.288 79.333 38.856 ;
     RECT  79.477 42.144 79.625 42.168 ;
     RECT  78.761 34.368 79.765 35.304 ;
     RECT  79.333 36.288 79.765 39.144 ;
     RECT  78.304 0.048 79.841 14.136 ;
     RECT  79.765 34.368 80.549 39.144 ;
     RECT  79.765 40.752 80.549 41.016 ;
     RECT  79.841 0.096 80.708 14.136 ;
     RECT  78.304 16.848 80.708 17.448 ;
     RECT  80.549 34.176 80.708 39.144 ;
     RECT  80.549 40.464 80.708 41.016 ;
     RECT  80.708 0.096 80.773 41.052 ;
     RECT  80.773 0.096 80.921 41.208 ;
     RECT  80.921 0.096 81.004 41.16 ;
     RECT  81.004 0.096 81.157 14.136 ;
     RECT  80.533 43.008 81.203 43.032 ;
     RECT  81.004 34.368 81.209 41.16 ;
     RECT  81.209 34.368 81.299 41.016 ;
     RECT  81.299 40.896 81.433 41.016 ;
     RECT  81.433 40.944 81.677 41.016 ;
     RECT  81.299 34.368 82.741 39.912 ;
     RECT  81.677 40.992 82.741 41.016 ;
     RECT  82.741 34.368 83.269 41.016 ;
     RECT  81.157 0.048 83.408 14.136 ;
     RECT  81.004 16.848 83.408 17.448 ;
     RECT  83.269 34.368 83.408 41.208 ;
     RECT  83.408 0.048 83.585 41.208 ;
     RECT  83.585 0.048 83.699 41.16 ;
     RECT  83.699 0.048 83.704 41.064 ;
     RECT  83.704 34.32 83.873 41.064 ;
     RECT  83.873 35.712 84.275 41.064 ;
     RECT  84.275 35.712 85.381 40.488 ;
     RECT  85.093 41.568 85.381 41.592 ;
     RECT  85.381 35.712 85.385 41.592 ;
     RECT  83.704 0.048 86.108 14.136 ;
     RECT  83.704 16.848 86.108 17.448 ;
     RECT  83.873 34.32 86.108 34.488 ;
     RECT  85.385 35.712 86.108 41.052 ;
     RECT  86.101 42.816 86.245 42.84 ;
     RECT  86.108 0.048 86.404 41.052 ;
     RECT  86.404 40.464 86.417 41.052 ;
     RECT  86.404 34.176 86.429 34.488 ;
     RECT  86.245 42.144 86.437 42.84 ;
     RECT  86.417 40.464 86.501 41.16 ;
     RECT  86.437 42.144 86.573 43.032 ;
     RECT  86.573 42.72 86.579 43.032 ;
     RECT  86.429 34.176 86.716 34.44 ;
     RECT  86.404 35.712 86.819 39.48 ;
     RECT  86.716 34.224 87.433 34.44 ;
     RECT  86.819 35.712 87.589 39.384 ;
     RECT  87.433 34.224 87.613 34.488 ;
     RECT  87.589 35.472 87.613 39.384 ;
     RECT  87.613 34.224 87.781 39.384 ;
     RECT  87.781 34.224 88.213 39.432 ;
     RECT  86.501 40.464 88.213 41.016 ;
     RECT  88.213 34.224 88.261 41.016 ;
     RECT  88.261 34.176 88.765 41.016 ;
     RECT  86.404 0.048 88.808 14.136 ;
     RECT  86.404 16.848 88.808 17.448 ;
     RECT  88.765 34.176 88.808 41.208 ;
     RECT  88.808 0.048 88.883 41.208 ;
     RECT  88.883 0.048 88.912 41.052 ;
     RECT  88.912 0.048 89.104 41.016 ;
     RECT  87.973 43.008 89.125 43.032 ;
     RECT  89.125 42.912 89.219 43.032 ;
     RECT  89.219 42.912 89.363 42.936 ;
     RECT  89.104 34.224 90.209 34.488 ;
     RECT  89.104 35.712 90.209 41.016 ;
     RECT  90.209 35.712 90.709 40.632 ;
     RECT  91.189 42.96 91.285 42.984 ;
     RECT  89.104 0.048 91.508 14.136 ;
     RECT  89.104 16.848 91.508 17.448 ;
     RECT  90.209 34.224 91.508 34.392 ;
     RECT  90.709 35.424 91.508 40.632 ;
     RECT  91.508 0.048 91.612 41.052 ;
     RECT  91.285 42.864 91.717 43.032 ;
     RECT  91.612 0.048 91.804 40.782 ;
     RECT  91.717 42.144 92.099 43.032 ;
     RECT  92.099 42.144 92.147 42.936 ;
     RECT  91.804 35.424 92.405 40.056 ;
     RECT  92.147 42.144 92.435 42.168 ;
     RECT  92.405 35.52 93.473 39.48 ;
     RECT  92.797 40.464 93.473 40.488 ;
     RECT  93.589 43.008 93.733 43.032 ;
     RECT  91.804 34.368 93.877 34.392 ;
     RECT  93.473 35.52 93.877 40.488 ;
     RECT  93.877 34.368 94.165 41.016 ;
     RECT  91.804 0.048 94.208 14.136 ;
     RECT  91.804 16.848 94.208 17.448 ;
     RECT  94.165 34.368 94.208 41.16 ;
     RECT  94.208 0.048 94.499 41.16 ;
     RECT  94.499 0.048 94.504 41.016 ;
     RECT  93.733 42.144 94.739 43.032 ;
     RECT  94.504 36.432 95.141 39.384 ;
     RECT  94.739 42.144 95.141 42.168 ;
     RECT  95.141 36.576 95.213 39.384 ;
     RECT  94.504 40.464 95.785 41.016 ;
     RECT  95.213 38.16 95.857 39.384 ;
     RECT  95.785 40.464 95.857 41.064 ;
     RECT  95.749 43.056 96.149 43.08 ;
     RECT  95.857 38.16 96.227 41.064 ;
     RECT  95.213 36.576 96.361 36.984 ;
     RECT  94.504 34.368 96.433 35.352 ;
     RECT  96.361 36.576 96.433 37.128 ;
     RECT  96.433 34.368 96.613 37.128 ;
     RECT  96.227 38.16 96.613 41.052 ;
     RECT  94.504 0.048 96.908 14.136 ;
     RECT  94.504 16.848 96.908 17.352 ;
     RECT  96.613 34.368 96.908 41.052 ;
     RECT  96.908 0.048 97.012 41.052 ;
     RECT  96.901 43.008 97.045 43.032 ;
     RECT  97.045 42.96 97.189 43.032 ;
     RECT  97.012 0.048 97.204 40.782 ;
     RECT  97.189 42.912 97.475 43.032 ;
     RECT  97.475 43.008 97.477 43.032 ;
     RECT  97.204 35.232 97.481 39.24 ;
     RECT  97.477 43.008 97.913 43.08 ;
     RECT  97.913 43.008 98.195 43.032 ;
     RECT  97.204 16.848 98.593 17.352 ;
     RECT  98.477 40.992 98.629 41.016 ;
     RECT  97.481 35.28 98.633 39.24 ;
     RECT  98.629 40.992 98.765 41.592 ;
     RECT  98.765 40.992 98.849 42.168 ;
     RECT  98.849 40.992 99.061 41.592 ;
     RECT  98.633 35.28 99.133 39.096 ;
     RECT  99.061 40.944 99.353 41.592 ;
     RECT  99.353 40.944 99.485 41.052 ;
     RECT  99.485 40.896 99.493 41.052 ;
     RECT  97.204 0.048 99.608 14.136 ;
     RECT  98.593 16.848 99.608 17.448 ;
     RECT  99.133 34.896 99.608 39.096 ;
     RECT  99.493 40.56 99.608 41.052 ;
     RECT  99.608 0.048 99.712 41.052 ;
     RECT  99.712 0.048 99.904 41.016 ;
     RECT  99.445 43.008 99.925 43.032 ;
     RECT  99.925 42.912 100.019 43.032 ;
     RECT  100.019 42.912 100.067 42.936 ;
     RECT  99.904 34.896 100.613 41.016 ;
     RECT  100.613 36 100.721 41.016 ;
     RECT  100.721 36 101.689 39.336 ;
     RECT  100.721 40.464 101.689 41.016 ;
     RECT  101.689 36 102.121 41.016 ;
     RECT  102.133 43.008 102.181 43.032 ;
     RECT  99.904 0.048 102.308 14.136 ;
     RECT  99.904 17.424 102.308 17.448 ;
     RECT  100.613 34.896 102.308 34.92 ;
     RECT  102.121 36 102.308 41.208 ;
     RECT  102.181 42.912 102.419 43.032 ;
     RECT  102.419 42.912 102.563 42.936 ;
     RECT  102.308 0.048 102.604 41.208 ;
     RECT  102.604 34.224 102.661 41.208 ;
     RECT  102.661 34.224 102.845 41.544 ;
     RECT  102.845 41.52 102.917 41.544 ;
     RECT  102.845 34.224 103.097 40.488 ;
     RECT  103.237 41.568 103.421 41.592 ;
     RECT  103.097 34.224 103.921 39.912 ;
     RECT  103.705 42.192 104.147 42.216 ;
     RECT  103.921 34.176 104.461 39.912 ;
     RECT  104.461 34.176 104.677 40.536 ;
     RECT  104.389 41.568 104.677 41.592 ;
     RECT  104.677 34.176 104.857 41.592 ;
     RECT  102.604 0.048 105.008 14.136 ;
     RECT  102.604 17.328 105.008 17.352 ;
     RECT  104.857 34.128 105.008 41.592 ;
     RECT  105.008 0.048 105.304 41.592 ;
     RECT  105.304 33.552 105.365 41.592 ;
     RECT  105.365 33.552 105.401 41.16 ;
     RECT  105.401 33.552 105.484 40.584 ;
     RECT  104.965 43.008 105.491 43.032 ;
     RECT  105.484 33.552 105.539 40.488 ;
     RECT  105.541 43.056 105.725 43.08 ;
     RECT  105.539 33.552 106.589 39.48 ;
     RECT  106.589 33.552 106.661 39.288 ;
     RECT  105.539 40.464 106.693 40.488 ;
     RECT  106.693 40.416 106.837 40.488 ;
     RECT  106.837 40.416 107.365 40.968 ;
     RECT  105.304 17.328 107.557 17.352 ;
     RECT  105.304 0.048 107.708 12.84 ;
     RECT  105.304 14.112 107.708 14.136 ;
     RECT  107.557 17.184 107.708 17.352 ;
     RECT  106.661 33.888 107.708 39.288 ;
     RECT  107.365 40.416 107.708 41.016 ;
     RECT  107.708 0.048 107.845 41.052 ;
     RECT  107.845 0.048 108.004 41.592 ;
     RECT  108.004 34.896 108.173 41.592 ;
     RECT  108.173 41.52 108.313 41.592 ;
     RECT  108.173 34.896 108.857 40.488 ;
     RECT  108.857 34.896 109.033 39.912 ;
     RECT  108.313 41.52 109.141 41.88 ;
     RECT  109.033 34.752 109.237 39.912 ;
     RECT  107.461 43.008 109.283 43.032 ;
     RECT  109.237 34.512 109.325 39.912 ;
     RECT  108.004 0.048 110.408 12.84 ;
     RECT  108.004 14.112 110.408 14.136 ;
     RECT  108.004 17.184 110.408 17.208 ;
     RECT  109.325 34.752 110.408 39.912 ;
     RECT  109.141 40.944 110.408 41.88 ;
     RECT  110.408 0.048 110.621 41.88 ;
     RECT  110.621 0.048 110.704 40.782 ;
     RECT  110.245 43.008 110.725 43.032 ;
     RECT  110.725 43.008 110.837 43.08 ;
     RECT  110.837 43.008 110.963 43.032 ;
     RECT  110.704 34.512 112.204 40.488 ;
     RECT  112.204 34.512 112.844 40.536 ;
     RECT  110.621 41.856 112.844 41.88 ;
     RECT  110.704 0.048 113.108 12.84 ;
     RECT  110.704 14.112 113.108 14.136 ;
     RECT  110.704 17.424 113.108 17.448 ;
     RECT  112.844 34.512 113.108 41.88 ;
     RECT  113.108 0.048 113.219 41.88 ;
     RECT  113.219 41.856 113.317 41.88 ;
     RECT  113.219 0.048 113.404 40.782 ;
     RECT  113.317 41.856 113.461 42.792 ;
     RECT  113.461 41.856 113.605 42.888 ;
     RECT  113.605 41.856 113.698 42.984 ;
     RECT  113.404 0.048 113.753 12.84 ;
     RECT  113.698 41.856 113.795 43.08 ;
     RECT  113.404 34.992 114.325 40.782 ;
     RECT  113.795 41.856 114.325 43.032 ;
     RECT  114.325 34.992 114.401 43.032 ;
     RECT  114.401 34.992 114.437 41.88 ;
     RECT  113.753 0.048 114.473 12.552 ;
     RECT  114.473 0.048 114.545 12.024 ;
     RECT  113.404 17.328 114.577 17.352 ;
     RECT  114.577 17.328 114.617 17.448 ;
     RECT  114.545 12 114.761 12.024 ;
     RECT  114.401 43.008 115.091 43.032 ;
     RECT  114.437 34.992 115.153 40.776 ;
     RECT  115.153 34.464 115.765 40.776 ;
     RECT  114.437 41.856 115.765 41.88 ;
     RECT  114.545 0.048 115.808 10.92 ;
     RECT  113.404 14.112 115.808 14.136 ;
     RECT  114.617 17.424 115.808 17.448 ;
     RECT  115.765 34.464 115.808 41.88 ;
     RECT  115.808 0.048 115.955 41.88 ;
     RECT  115.765 42.864 116.053 42.888 ;
     RECT  115.955 0.048 116.104 40.782 ;
     RECT  116.053 42.864 116.197 42.984 ;
     RECT  116.197 42.864 116.243 43.032 ;
     RECT  116.243 42.96 116.579 43.032 ;
     RECT  116.104 34.464 116.957 40.536 ;
     RECT  116.957 34.464 117.065 40.488 ;
     RECT  116.917 43.056 117.317 43.08 ;
     RECT  117.065 35.712 118.357 40.488 ;
     RECT  115.955 41.856 118.357 41.88 ;
     RECT  117.925 43.008 118.357 43.032 ;
     RECT  116.104 0.048 118.508 10.728 ;
     RECT  116.104 14.112 118.508 14.136 ;
     RECT  116.104 16.272 118.508 16.296 ;
     RECT  116.104 17.424 118.508 17.448 ;
     RECT  117.065 34.464 118.508 34.68 ;
     RECT  118.357 35.712 118.508 43.032 ;
     RECT  118.508 0.048 118.804 43.032 ;
     RECT  118.804 35.664 119.077 43.032 ;
     RECT  119.077 35.664 119.161 43.08 ;
     RECT  119.161 35.664 119.363 42.936 ;
     RECT  119.363 35.664 120.485 42.168 ;
     RECT  118.804 34.656 120.62 34.68 ;
     RECT  120.485 35.664 120.62 41.88 ;
     RECT  118.804 14.112 121.085 14.136 ;
     RECT  118.804 0.048 121.208 10.728 ;
     RECT  121.085 13.68 121.208 14.136 ;
     RECT  118.804 16.272 121.208 16.296 ;
     RECT  118.804 17.424 121.208 17.448 ;
     RECT  120.62 34.656 121.208 41.88 ;
     RECT  121.208 0.048 121.504 41.88 ;
     RECT  120.709 42.96 121.667 43.032 ;
     RECT  121.667 43.008 122.483 43.032 ;
     RECT  121.504 17.328 122.569 17.352 ;
     RECT  122.569 17.328 122.609 17.448 ;
     RECT  121.504 34.608 122.645 41.88 ;
     RECT  122.645 34.608 122.753 35.448 ;
     RECT  123.541 43.008 123.733 43.032 ;
     RECT  122.753 34.8 123.901 35.448 ;
     RECT  122.645 36.432 123.901 41.88 ;
     RECT  121.504 0.048 123.908 10.728 ;
     RECT  122.609 17.424 123.908 17.448 ;
     RECT  123.901 34.8 123.908 41.88 ;
     RECT  123.733 42.912 124.163 43.032 ;
     RECT  123.908 0.048 124.204 41.88 ;
     RECT  124.204 0.048 124.985 10.728 ;
     RECT  124.163 43.008 125.123 43.032 ;
     RECT  124.985 0.048 125.417 10.68 ;
     RECT  124.204 17.424 125.693 17.448 ;
     RECT  125.417 0.048 126.529 10.632 ;
     RECT  124.204 34.896 126.565 41.88 ;
     RECT  126.529 0.048 126.608 10.68 ;
     RECT  125.693 17.088 126.608 17.448 ;
     RECT  126.565 34.896 126.608 42.84 ;
     RECT  126.608 0.048 126.853 42.84 ;
     RECT  126.853 0.048 126.901 42.936 ;
     RECT  126.901 0.048 126.904 43.032 ;
     RECT  126.904 33.936 127.043 39.336 ;
     RECT  127.043 33.936 127.331 39.288 ;
     RECT  127.331 38.976 127.763 39.288 ;
     RECT  126.904 40.56 127.997 43.032 ;
     RECT  127.997 40.56 128.081 43.08 ;
     RECT  128.081 40.56 128.113 42.312 ;
     RECT  128.113 40.464 128.195 42.312 ;
     RECT  127.763 39.264 128.221 39.288 ;
     RECT  128.195 40.464 128.221 42.216 ;
     RECT  128.221 39.264 128.339 42.216 ;
     RECT  127.331 33.936 128.545 37.992 ;
     RECT  126.904 0.048 129.308 10.68 ;
     RECT  128.545 33.6 129.308 37.992 ;
     RECT  128.339 39.888 129.308 42.216 ;
     RECT  129.308 0.048 129.604 42.216 ;
     RECT  129.604 40.464 129.635 42.216 ;
     RECT  129.604 37.056 129.665 37.992 ;
     RECT  129.635 42.192 129.733 42.216 ;
     RECT  129.733 42.192 129.917 43.08 ;
     RECT  129.635 40.464 129.923 41.064 ;
     RECT  129.917 42.192 130.067 42.216 ;
     RECT  129.604 34.176 130.313 36.072 ;
     RECT  129.665 37.872 130.313 37.992 ;
     RECT  130.597 42.144 130.741 42.168 ;
     RECT  130.741 42.096 130.781 42.168 ;
     RECT  130.313 34.896 130.885 36.072 ;
     RECT  130.313 37.872 130.885 37.896 ;
     RECT  130.781 42.096 130.961 42.12 ;
     RECT  129.923 40.464 131.317 41.016 ;
     RECT  129.604 0.048 132.008 10.68 ;
     RECT  130.885 34.896 132.008 37.896 ;
     RECT  131.317 39.744 132.008 41.016 ;
     RECT  132.008 0.048 132.304 41.052 ;
     RECT  132.304 39.744 132.365 39.768 ;
     RECT  132.304 40.896 132.833 41.052 ;
     RECT  132.833 40.992 132.901 41.052 ;
     RECT  132.901 40.992 133.121 41.592 ;
     RECT  132.304 36.912 133.229 38.184 ;
     RECT  133.333 42.144 133.621 42.168 ;
     RECT  133.621 42.144 133.877 43.08 ;
     RECT  133.121 40.992 134.053 41.016 ;
     RECT  133.229 36.912 134.269 36.936 ;
     RECT  132.304 34.752 134.305 35.736 ;
     RECT  134.269 36.912 134.305 37.08 ;
     RECT  133.909 39.888 134.341 39.912 ;
     RECT  134.053 40.944 134.341 41.016 ;
     RECT  133.229 38.16 134.485 38.184 ;
     RECT  134.485 38.16 134.533 38.664 ;
     RECT  134.341 39.888 134.533 41.016 ;
     RECT  132.304 0.048 134.708 10.68 ;
     RECT  134.305 34.752 134.708 37.08 ;
     RECT  134.533 38.16 134.708 41.016 ;
     RECT  133.877 42.144 134.819 43.032 ;
     RECT  134.819 42.144 134.963 42.936 ;
     RECT  134.708 0.048 135.004 41.052 ;
     RECT  135.004 40.944 135.061 41.052 ;
     RECT  135.004 34.512 135.065 39.912 ;
     RECT  135.065 35.712 135.173 39.912 ;
     RECT  134.963 42.144 135.251 42.216 ;
     RECT  135.061 40.944 135.353 41.16 ;
     RECT  135.173 37.632 135.469 39.912 ;
     RECT  135.251 42.144 135.485 42.168 ;
     RECT  135.469 37.632 135.541 39.816 ;
     RECT  135.173 35.712 135.713 36.552 ;
     RECT  135.713 35.712 135.965 36.504 ;
     RECT  135.485 41.568 136.001 42.168 ;
     RECT  136.001 41.568 136.145 41.592 ;
     RECT  135.541 38.016 136.325 39.816 ;
     RECT  136.349 40.992 136.789 41.016 ;
     RECT  136.325 38.016 137.18 39.384 ;
     RECT  136.789 40.464 137.365 41.016 ;
     RECT  135.004 0.048 137.408 10.68 ;
     RECT  135.065 34.512 137.408 34.536 ;
     RECT  135.965 35.712 137.408 35.736 ;
     RECT  137.18 37.632 137.408 39.384 ;
     RECT  137.365 40.464 137.408 41.208 ;
     RECT  137.408 0.048 137.449 41.208 ;
     RECT  137.449 0.048 137.512 41.052 ;
     RECT  137.512 0.048 137.704 40.968 ;
     RECT  137.704 40.944 138.305 40.968 ;
     RECT  137.704 0.048 140.108 10.68 ;
     RECT  140.108 0.048 140.212 41.052 ;
     RECT  140.212 0.048 140.404 40.782 ;
     RECT  140.404 0.048 142.808 10.68 ;
     RECT  142.808 0.048 142.912 41.052 ;
     RECT  142.912 0.048 143.104 40.782 ;
     RECT  143.104 0.048 145.508 10.68 ;
     RECT  145.508 0.048 145.612 41.052 ;
     RECT  145.612 0.048 145.804 40.782 ;
     RECT  145.804 0.048 146.819 10.68 ;
     RECT  146.819 0.096 147.097 10.68 ;
     RECT  147.097 0.144 148.165 10.68 ;
     RECT  148.165 0.048 148.208 10.68 ;
     RECT  148.208 0.048 148.312 41.052 ;
     RECT  148.312 0.048 148.504 40.782 ;
     RECT  148.504 0.048 150.908 10.68 ;
     RECT  150.908 0.048 151.012 41.052 ;
     RECT  151.012 0.048 151.204 40.782 ;
     RECT  151.204 0.048 153.608 10.68 ;
     RECT  153.608 0.048 153.712 41.052 ;
     RECT  153.712 0.048 153.904 40.782 ;
     RECT  153.904 0.048 154.835 10.68 ;
     RECT  154.835 0.048 156.308 10.632 ;
     RECT  156.308 0.048 156.412 41.052 ;
     RECT  156.412 0.048 156.604 40.782 ;
     RECT  156.604 0.048 159.008 10.632 ;
     RECT  159.008 0.048 159.112 41.052 ;
     RECT  159.112 0.048 159.304 40.782 ;
     RECT  159.304 0.048 161.708 10.632 ;
     RECT  161.708 0.048 161.812 41.052 ;
     RECT  161.812 0.048 162.004 40.782 ;
     RECT  162.004 0.048 164.408 10.632 ;
     RECT  164.408 0.048 164.512 41.052 ;
     RECT  164.512 0.048 164.704 40.782 ;
     RECT  164.704 0.048 164.729 10.632 ;
     RECT  164.729 0.144 166.067 10.632 ;
     RECT  166.067 0.144 166.453 10.344 ;
     RECT  166.453 0.048 167.108 10.344 ;
     RECT  167.108 0.048 167.212 41.052 ;
     RECT  167.212 0.048 167.404 40.782 ;
     RECT  167.404 0.048 169.808 9.816 ;
     RECT  169.808 0.048 169.912 41.052 ;
     RECT  169.912 0.048 170.104 40.782 ;
     RECT  170.104 0.048 172.508 9.816 ;
     RECT  172.508 0.048 172.612 41.052 ;
     RECT  172.612 0.048 172.804 40.782 ;
     RECT  172.804 0.048 175.208 9.816 ;
     RECT  175.208 0.048 175.312 41.052 ;
     RECT  175.312 0.048 175.504 40.782 ;
     RECT  175.504 0.048 175.709 9.816 ;
     RECT  175.709 0.096 177.908 9.816 ;
     RECT  177.908 0.096 178.012 41.052 ;
     RECT  178.012 0.096 178.163 40.782 ;
     RECT  178.163 1.392 178.204 40.782 ;
     RECT  178.204 1.392 178.451 7.704 ;
     RECT  178.451 1.392 178.739 6.024 ;
     RECT  178.163 0.096 179.201 0.216 ;
     RECT  179.201 0.192 179.233 0.216 ;
     RECT  178.739 1.392 179.233 5.88 ;
     RECT  178.451 7.68 179.273 7.704 ;
     RECT  179.233 0.192 179.315 5.88 ;
     RECT  179.315 0.192 179.597 4.488 ;
     RECT  179.597 0.192 180.565 1.464 ;
     RECT  179.597 2.544 180.565 4.488 ;
     RECT  180.565 0.192 180.608 4.488 ;
     RECT  179.315 5.856 180.608 5.88 ;
     RECT  178.204 9.12 180.608 9.816 ;
     RECT  180.608 0.192 180.709 41.052 ;
     RECT  180.709 0.096 180.712 41.052 ;
     RECT  180.712 0.096 180.899 40.782 ;
     RECT  180.899 2.418 180.904 40.782 ;
     RECT  180.899 0.096 181.081 1.416 ;
     RECT  181.081 0.576 181.187 1.416 ;
     RECT  180.904 2.544 181.331 4.056 ;
     RECT  181.187 1.056 181.475 1.416 ;
     RECT  181.331 2.544 181.619 2.568 ;
     RECT  181.475 1.056 181.907 1.224 ;
     RECT  181.331 3.6 182.195 4.056 ;
     RECT  182.195 4.032 182.339 4.056 ;
     RECT  181.907 1.152 182.521 1.224 ;
     RECT  182.521 1.2 182.627 1.224 ;
     RECT  183.308 2.148 183.412 41.052 ;
     RECT  183.412 2.418 183.604 40.782 ;
     RECT  186.008 2.148 186.112 41.052 ;
     RECT  186.112 2.418 186.304 40.782 ;
    LAYER M5 ;
     RECT  144.72 0.016 172.248 0.037 ;
     RECT  29.52 0.016 57.048 0.085 ;
     RECT  58.32 0.016 114.648 0.085 ;
     RECT  115.92 0.016 143.448 0.085 ;
     RECT  144.72 0.037 172.344 0.085 ;
     RECT  29.52 0.085 114.648 0.131 ;
     RECT  115.824 0.085 172.344 0.227 ;
     RECT  19.152 0.016 28.248 0.277 ;
     RECT  29.52 0.131 114.504 0.277 ;
     RECT  19.152 0.277 114.504 0.371 ;
     RECT  19.152 0.371 65.688 0.419 ;
     RECT  19.152 0.419 32.568 0.467 ;
     RECT  66.672 0.371 114.504 0.899 ;
     RECT  115.824 0.227 172.104 0.995 ;
     RECT  138.096 0.995 172.104 1.091 ;
     RECT  115.824 0.995 137.112 1.139 ;
     RECT  33.552 0.419 65.688 1.187 ;
     RECT  173.52 0.016 182.616 1.235 ;
     RECT  81.36 0.899 114.504 1.379 ;
     RECT  90.288 1.379 114.504 1.427 ;
     RECT  33.552 1.187 65.4 1.475 ;
     RECT  160.128 1.091 172.104 1.523 ;
     RECT  173.52 1.235 182.328 1.715 ;
     RECT  33.552 1.475 57.048 1.763 ;
     RECT  90.432 1.427 114.504 1.763 ;
     RECT  50.4 1.763 57.048 1.811 ;
     RECT  19.152 0.467 28.104 1.859 ;
     RECT  50.544 1.811 57.048 1.859 ;
     RECT  116.208 1.139 137.112 1.859 ;
     RECT  19.152 1.859 27.672 1.907 ;
     RECT  50.736 1.859 57.048 1.907 ;
     RECT  138.096 1.091 158.712 1.907 ;
     RECT  29.664 0.467 32.568 1.955 ;
     RECT  19.152 1.907 27.24 2.137 ;
     RECT  29.664 1.955 32.412 2.137 ;
     RECT  66.672 0.899 80.376 2.137 ;
     RECT  81.36 1.379 89.304 2.137 ;
     RECT  116.208 1.859 133.368 2.137 ;
     RECT  134.352 1.859 137.112 2.137 ;
     RECT  138.096 1.907 146.328 2.137 ;
     RECT  147.6 1.907 158.712 2.137 ;
     RECT  163.44 1.523 172.104 2.137 ;
     RECT  173.52 1.715 173.976 2.137 ;
     RECT  2.4 2.137 2.52 2.151 ;
     RECT  5.1 2.137 5.22 2.151 ;
     RECT  7.8 2.137 7.92 2.151 ;
     RECT  10.5 2.137 10.62 2.151 ;
     RECT  13.2 2.137 13.32 2.151 ;
     RECT  15.9 2.137 16.02 2.151 ;
     RECT  147.6 2.137 159.12 2.151 ;
     RECT  160.128 1.523 162.456 2.151 ;
     RECT  183.3 2.137 183.42 2.151 ;
     RECT  186 2.137 186.12 2.151 ;
     RECT  56.4 1.907 57.048 2.291 ;
     RECT  90.432 1.763 114.216 2.291 ;
     RECT  107.28 2.291 114.216 2.339 ;
     RECT  134.352 2.137 146.328 2.339 ;
     RECT  147.6 2.151 162.456 2.387 ;
     RECT  163.44 2.137 173.976 2.387 ;
     RECT  107.376 2.339 114.216 2.435 ;
     RECT  155.808 2.387 162.456 2.483 ;
     RECT  33.552 1.763 49.416 2.531 ;
     RECT  156.096 2.483 162.456 2.531 ;
     RECT  173.952 2.387 173.976 2.579 ;
     RECT  18.6 2.137 27.24 2.627 ;
     RECT  50.736 1.907 55.32 2.771 ;
     RECT  20.16 2.627 27.24 2.819 ;
     RECT  90.432 2.291 106.152 2.819 ;
     RECT  156.192 2.531 162.456 2.819 ;
     RECT  147.6 2.387 154.824 2.867 ;
     RECT  33.552 2.531 46.824 2.915 ;
     RECT  51 2.771 55.32 2.915 ;
     RECT  175.2 1.715 182.328 2.915 ;
     RECT  33.552 2.915 46.488 2.963 ;
     RECT  58.128 1.475 65.4 2.963 ;
     RECT  160.704 2.819 162.456 2.965 ;
     RECT  163.44 2.387 172.812 2.965 ;
     RECT  21.024 2.819 27.24 3.059 ;
     RECT  39.6 2.963 46.488 3.059 ;
     RECT  21.024 3.059 24.408 3.107 ;
     RECT  160.704 2.965 172.812 3.107 ;
     RECT  21.024 3.107 22.488 3.155 ;
     RECT  51 2.915 54.6 3.155 ;
     RECT  23.472 3.107 24.408 3.347 ;
     RECT  56.4 2.291 57 3.349 ;
     RECT  21.024 3.155 22.2 3.395 ;
     RECT  134.352 2.339 143.256 3.397 ;
     RECT  144.288 2.339 146.328 3.397 ;
     RECT  23.472 3.347 24.312 3.443 ;
     RECT  33.552 2.963 38.472 3.443 ;
     RECT  58.608 2.963 65.4 3.443 ;
     RECT  107.7 2.435 114.216 3.443 ;
     RECT  115.8 2.137 133.368 3.443 ;
     RECT  39.6 3.059 43.656 3.491 ;
     RECT  131.184 3.443 133.368 3.491 ;
     RECT  131.472 3.491 133.368 3.539 ;
     RECT  131.616 3.539 133.368 3.587 ;
     RECT  90.432 2.819 92.616 3.635 ;
     RECT  58.608 3.443 59.544 3.683 ;
     RECT  66.672 2.137 89.304 3.683 ;
     RECT  48.3 2.531 49.416 3.781 ;
     RECT  51 3.155 51.72 3.781 ;
     RECT  25.776 3.059 27.24 3.875 ;
     RECT  44.784 3.059 46.488 3.875 ;
     RECT  93.6 2.819 106.152 3.923 ;
     RECT  93.984 3.923 106.152 3.971 ;
     RECT  112.176 3.443 114.216 3.971 ;
     RECT  134.352 3.397 146.328 3.971 ;
     RECT  182.016 2.915 182.328 4.019 ;
     RECT  48.3 3.781 49.512 4.067 ;
     RECT  182.304 4.019 182.328 4.067 ;
     RECT  33.696 3.443 38.472 4.069 ;
     RECT  39.6 3.491 40.512 4.069 ;
     RECT  56.4 3.349 57.576 4.069 ;
     RECT  58.608 3.683 59.412 4.069 ;
     RECT  23.616 3.443 24.312 4.163 ;
     RECT  50.88 3.781 51.72 4.163 ;
     RECT  66.672 3.683 68.856 4.211 ;
     RECT  139.392 3.971 146.328 4.213 ;
     RECT  147.6 2.867 152.232 4.213 ;
     RECT  33.696 4.069 40.512 4.259 ;
     RECT  115.8 3.443 129.912 4.259 ;
     RECT  139.392 4.213 152.232 4.307 ;
     RECT  50.88 4.163 51.312 4.357 ;
     RECT  52.704 3.155 54.6 4.357 ;
     RECT  26.064 3.875 27.24 4.451 ;
     RECT  26.7 4.451 27.24 4.499 ;
     RECT  39.744 4.259 40.512 4.499 ;
     RECT  50.352 4.357 51.312 4.499 ;
     RECT  113.1 3.971 114.216 4.499 ;
     RECT  56.4 4.069 59.412 4.501 ;
     RECT  60.624 3.443 65.4 4.501 ;
     RECT  69.9 3.683 89.304 4.547 ;
     RECT  113.1 4.499 114.072 4.547 ;
     RECT  115.8 4.259 125.304 4.547 ;
     RECT  139.392 4.307 151.32 4.547 ;
     RECT  153.456 2.867 154.824 4.547 ;
     RECT  33.696 4.259 38.472 4.595 ;
     RECT  90.576 3.635 92.616 4.595 ;
     RECT  107.7 3.443 110.712 4.595 ;
     RECT  126.432 4.259 129.912 4.595 ;
     RECT  93.984 3.971 105.96 4.691 ;
     RECT  175.2 2.915 180.912 4.739 ;
     RECT  93.984 4.691 105.432 4.787 ;
     RECT  139.392 4.547 146.328 4.883 ;
     RECT  45.072 3.875 46.488 4.885 ;
     RECT  45.072 4.885 47.064 4.931 ;
     RECT  56.304 4.501 59.412 4.931 ;
     RECT  131.664 3.587 133.368 4.931 ;
     RECT  139.392 4.883 146.184 4.931 ;
     RECT  152.304 4.741 152.328 4.931 ;
     RECT  47.04 4.931 47.064 5.027 ;
     RECT  163.44 3.107 170.664 5.027 ;
     RECT  60.624 4.501 65.544 5.075 ;
     RECT  69.9 4.547 72.912 5.075 ;
     RECT  93.984 4.787 98.52 5.075 ;
     RECT  148.2 4.547 151.32 5.075 ;
     RECT  171.648 3.107 172.812 5.075 ;
     RECT  91.5 4.595 92.616 5.123 ;
     RECT  45.072 4.931 45.912 5.125 ;
     RECT  18.6 2.627 19.176 5.171 ;
     RECT  60.624 5.075 63.384 5.171 ;
     RECT  109.44 4.595 110.712 5.171 ;
     RECT  117.504 4.547 125.304 5.171 ;
     RECT  139.392 4.931 144.312 5.171 ;
     RECT  148.2 5.075 151.212 5.171 ;
     RECT  74.016 4.547 89.304 5.219 ;
     RECT  163.44 5.027 168.792 5.219 ;
     RECT  41.76 3.491 43.656 5.267 ;
     RECT  60.912 5.171 63.384 5.267 ;
     RECT  118.5 5.171 121.512 5.267 ;
     RECT  176.544 4.739 180.912 5.267 ;
     RECT  45.024 5.125 45.912 5.315 ;
     RECT  145.392 4.931 146.184 5.315 ;
     RECT  163.44 5.219 168.36 5.315 ;
     RECT  21.3 3.395 22.2 5.363 ;
     RECT  122.544 5.171 125.304 5.363 ;
     RECT  139.92 5.171 144.312 5.459 ;
     RECT  52.704 4.357 54.648 5.461 ;
     RECT  118.5 5.267 119.256 5.507 ;
     RECT  134.352 3.971 138.408 5.507 ;
     RECT  176.544 5.267 178.728 5.555 ;
     RECT  33.696 4.595 38.04 5.603 ;
     RECT  52.704 5.461 54.84 5.603 ;
     RECT  92.928 5.605 93 5.747 ;
     RECT  109.872 5.171 110.712 5.747 ;
     RECT  126.6 4.595 129.912 5.747 ;
     RECT  131.856 4.931 133.368 5.747 ;
     RECT  139.92 5.459 143.112 5.747 ;
     RECT  94.032 5.075 98.52 5.749 ;
     RECT  99.6 4.787 105.432 5.749 ;
     RECT  126.6 5.747 129.612 5.749 ;
     RECT  94.032 5.749 105.432 5.795 ;
     RECT  74.016 5.219 89.112 5.843 ;
     RECT  82.992 5.843 89.112 5.891 ;
     RECT  99.072 5.795 105.432 5.891 ;
     RECT  122.832 5.363 125.304 5.893 ;
     RECT  126.384 5.749 129.612 5.893 ;
     RECT  92.928 5.747 92.952 5.939 ;
     RECT  176.832 5.555 178.728 6.035 ;
     RECT  82.992 5.891 84.552 6.083 ;
     RECT  120.24 5.267 121.512 6.131 ;
     RECT  156.192 2.819 159.312 6.131 ;
     RECT  122.832 5.893 129.612 6.179 ;
     RECT  144.192 5.459 144.312 6.179 ;
     RECT  99.168 5.891 105.432 6.275 ;
     RECT  39.984 4.499 40.512 6.323 ;
     RECT  42.048 5.267 43.656 6.323 ;
     RECT  99.6 6.275 105.432 6.323 ;
     RECT  122.832 6.179 126.912 6.323 ;
     RECT  45.072 5.315 45.912 6.371 ;
     RECT  74.016 5.843 81.528 6.371 ;
     RECT  150.048 5.171 151.212 6.371 ;
     RECT  50.88 4.499 51.312 6.419 ;
     RECT  144.192 6.179 144.264 6.419 ;
     RECT  74.448 6.371 81.528 6.515 ;
     RECT  122.928 6.323 126.912 6.515 ;
     RECT  115.8 4.547 116.52 6.517 ;
     RECT  117.504 5.171 117.528 6.517 ;
     RECT  42.048 6.323 43.368 6.611 ;
     RECT  85.728 5.891 89.112 6.613 ;
     RECT  56.4 4.931 59.412 6.659 ;
     RECT  83.04 6.083 84.552 6.659 ;
     RECT  144.192 6.419 144.216 6.659 ;
     RECT  71.28 5.075 72.912 6.709 ;
     RECT  131.904 5.747 133.368 6.755 ;
     RECT  142.032 5.747 143.112 6.755 ;
     RECT  139.92 5.747 140.808 6.757 ;
     RECT  71.28 6.709 73.032 6.851 ;
     RECT  83.4 6.659 84.552 6.851 ;
     RECT  115.8 6.517 117.528 6.851 ;
     RECT  136.512 5.507 138.408 6.851 ;
     RECT  145.392 5.315 145.812 6.851 ;
     RECT  42.048 6.611 43.212 6.899 ;
     RECT  76.896 6.515 81.528 6.899 ;
     RECT  134.352 5.507 135.528 6.899 ;
     RECT  176.832 6.035 178.44 6.899 ;
     RECT  118.5 5.507 118.812 6.901 ;
     RECT  175.2 4.739 175.512 6.901 ;
     RECT  29.4 2.137 32.412 6.947 ;
     RECT  94.032 5.795 98.088 6.947 ;
     RECT  99.6 6.323 105.312 6.947 ;
     RECT  176.976 6.899 178.44 6.947 ;
     RECT  64.368 5.075 65.544 7.139 ;
     RECT  85.728 6.613 89.544 7.139 ;
     RECT  136.512 6.851 137.712 7.139 ;
     RECT  66.672 4.211 68.424 7.141 ;
     RECT  69.9 5.075 70.212 7.141 ;
     RECT  160.704 3.107 162.456 7.141 ;
     RECT  136.656 7.139 137.712 7.187 ;
     RECT  139.92 6.757 141.336 7.187 ;
     RECT  117.504 6.851 117.528 7.235 ;
     RECT  156.3 6.131 159.312 7.235 ;
     RECT  169.8 5.027 170.664 7.235 ;
     RECT  174.432 6.901 175.512 7.235 ;
     RECT  176.976 6.947 178.212 7.235 ;
     RECT  88.8 7.139 89.544 7.283 ;
     RECT  74.448 6.515 75.72 7.331 ;
     RECT  123.12 6.515 126.912 7.379 ;
     RECT  177.264 7.235 178.212 7.379 ;
     RECT  29.4 6.947 31.128 7.427 ;
     RECT  66.672 7.141 70.212 7.427 ;
     RECT  94.032 6.947 97.212 7.427 ;
     RECT  160.704 7.141 162.504 7.427 ;
     RECT  91.5 5.123 91.812 7.429 ;
     RECT  118.5 6.901 118.92 7.429 ;
     RECT  33.84 5.603 38.04 7.475 ;
     RECT  77.904 6.899 81.528 7.475 ;
     RECT  83.4 6.851 84.12 7.475 ;
     RECT  123.12 7.379 124.212 7.475 ;
     RECT  125.28 7.379 126.912 7.475 ;
     RECT  128.016 6.179 129.612 7.475 ;
     RECT  142.704 6.755 143.112 7.475 ;
     RECT  121.104 6.131 121.512 7.477 ;
     RECT  145.5 6.851 145.812 7.573 ;
     RECT  123.792 7.475 124.212 7.619 ;
     RECT  64.5 7.139 65.544 7.667 ;
     RECT  120.864 7.477 121.512 7.667 ;
     RECT  85.728 7.139 87.816 7.717 ;
     RECT  160.704 7.427 162.456 7.763 ;
     RECT  118.5 7.429 118.968 7.811 ;
     RECT  91.5 7.429 92.328 7.813 ;
     RECT  118.5 7.811 118.92 7.907 ;
     RECT  85.44 7.717 87.816 7.955 ;
     RECT  88.8 7.283 89.208 7.955 ;
     RECT  102.144 6.947 105.312 7.955 ;
     RECT  145.5 7.573 146.52 7.955 ;
     RECT  160.704 7.763 162.312 7.955 ;
     RECT  33.84 7.475 37.944 8.003 ;
     RECT  86.1 7.955 87.816 8.003 ;
     RECT  91.5 7.813 92.424 8.003 ;
     RECT  104.4 7.955 105.312 8.003 ;
     RECT  128.016 7.475 128.04 8.003 ;
     RECT  76.896 6.899 76.92 8.051 ;
     RECT  86.1 8.003 87.288 8.099 ;
     RECT  139.92 7.187 140.412 8.099 ;
     RECT  33.84 8.003 37.812 8.243 ;
     RECT  160.704 7.955 162.012 8.243 ;
     RECT  164.4 5.315 168.36 8.243 ;
     RECT  34.704 8.243 37.812 8.291 ;
     RECT  177.408 7.379 178.212 8.291 ;
     RECT  52.704 5.603 54.648 8.483 ;
     RECT  83.4 7.475 83.976 8.483 ;
     RECT  145.5 7.955 145.992 8.483 ;
     RECT  134.496 6.899 135.528 8.531 ;
     RECT  34.8 8.291 37.812 8.579 ;
     RECT  52.704 8.483 54.012 8.579 ;
     RECT  66.672 7.427 68.424 8.579 ;
     RECT  74.448 7.331 75.612 8.579 ;
     RECT  157.968 7.235 159.312 8.579 ;
     RECT  78 7.475 81.528 8.723 ;
     RECT  74.592 8.579 75.612 8.771 ;
     RECT  160.704 8.243 160.728 8.771 ;
     RECT  99.6 6.947 100.824 8.821 ;
     RECT  52.848 8.579 54.012 8.867 ;
     RECT  177.552 8.291 178.212 8.867 ;
     RECT  91.5 8.003 91.812 8.869 ;
     RECT  99.6 8.821 100.92 8.963 ;
     RECT  102.144 7.955 103.128 8.963 ;
     RECT  29.4 7.427 29.832 9.107 ;
     RECT  94.032 7.427 94.512 9.155 ;
     RECT  102.3 8.963 103.128 9.155 ;
     RECT  179.712 5.267 180.912 9.155 ;
     RECT  132 6.755 133.368 9.203 ;
     RECT  34.8 8.579 36.024 9.395 ;
     RECT  132 9.203 132.648 9.539 ;
     RECT  78 8.723 81.192 9.731 ;
     RECT  96.48 7.427 97.212 9.731 ;
     RECT  99.6 8.963 100.536 9.731 ;
     RECT  30.96 7.427 31.128 9.827 ;
     RECT  180.288 9.155 180.912 9.827 ;
     RECT  157.968 8.579 157.992 9.875 ;
     RECT  156.3 7.235 156.984 9.923 ;
     RECT  164.4 8.243 167.412 9.923 ;
     RECT  86.1 8.099 86.412 10.021 ;
     RECT  137.4 7.187 137.712 10.021 ;
     RECT  90.624 8.869 91.812 10.163 ;
     RECT  166.032 9.923 167.412 10.355 ;
     RECT  86.1 10.021 86.52 10.357 ;
     RECT  121.104 7.667 121.512 10.357 ;
     RECT  137.4 10.021 137.832 10.357 ;
     RECT  145.5 8.483 145.812 10.357 ;
     RECT  99.6 9.731 100.392 10.499 ;
     RECT  121.104 10.357 121.608 10.499 ;
     RECT  58.176 6.659 59.412 10.643 ;
     RECT  99.6 10.499 100.008 10.643 ;
     RECT  115.8 6.851 116.52 10.643 ;
     RECT  166.032 10.355 166.056 10.643 ;
     RECT  61.8 5.267 63.384 10.691 ;
     RECT  137.4 10.357 137.928 10.691 ;
     RECT  145.5 10.357 145.992 10.691 ;
     RECT  153.6 4.547 154.824 10.691 ;
     RECT  86.1 10.357 86.616 10.787 ;
     RECT  30.96 9.827 30.984 10.979 ;
     RECT  66.672 8.579 67.656 11.459 ;
     RECT  66.672 11.459 67.608 12.035 ;
     RECT  61.8 10.691 62.952 12.083 ;
     RECT  86.1 10.787 86.412 12.181 ;
     RECT  86.1 12.181 86.52 12.277 ;
     RECT  78 9.731 81.012 12.323 ;
     RECT  79.776 12.323 81.012 12.515 ;
     RECT  66.96 12.035 67.608 12.563 ;
     RECT  99.6 10.643 99.912 12.613 ;
     RECT  64.5 7.667 65.4 12.803 ;
     RECT  67.104 12.563 67.608 12.851 ;
     RECT  71.28 6.851 72.912 12.851 ;
     RECT  99.6 12.613 100.008 12.899 ;
     RECT  86.1 12.277 86.616 13.091 ;
     RECT  34.8 9.395 35.88 13.139 ;
     RECT  71.568 12.851 72.912 13.187 ;
     RECT  121.104 10.499 121.512 13.715 ;
     RECT  59.1 10.643 59.412 14.101 ;
     RECT  115.8 10.643 116.376 16.307 ;
     RECT  72.288 13.187 72.912 16.883 ;
     RECT  125.712 7.475 126.912 17.123 ;
     RECT  107.7 4.595 108.012 17.173 ;
     RECT  107.568 17.173 108.012 17.363 ;
     RECT  59.1 14.101 59.736 17.413 ;
     RECT  72.432 16.883 72.912 32.531 ;
     RECT  75.3 8.771 75.612 33.349 ;
     RECT  129.3 7.475 129.612 33.589 ;
     RECT  78 12.323 78.312 34.117 ;
     RECT  64.5 12.803 64.812 34.165 ;
     RECT  80.7 12.515 81.012 34.165 ;
     RECT  86.1 13.091 86.412 34.165 ;
     RECT  88.8 7.955 89.112 34.165 ;
     RECT  105 8.003 105.312 34.165 ;
     RECT  74.928 33.349 75.612 34.357 ;
     RECT  69.9 7.427 70.212 34.453 ;
     RECT  74.688 34.357 75.612 34.499 ;
     RECT  77.808 34.117 78.312 34.499 ;
     RECT  80.592 34.165 81.012 34.645 ;
     RECT  67.2 12.851 67.608 34.693 ;
     RECT  72.6 32.531 72.912 34.693 ;
     RECT  105 34.165 105.576 34.885 ;
     RECT  115.8 16.307 116.112 34.885 ;
     RECT  121.2 13.715 121.512 34.885 ;
     RECT  96.9 9.731 97.212 35.221 ;
     RECT  113.1 4.547 113.412 35.221 ;
     RECT  104.16 34.885 105.576 35.269 ;
     RECT  80.592 34.645 81.192 35.315 ;
     RECT  80.7 35.315 81.192 35.317 ;
     RECT  94.2 9.155 94.512 35.317 ;
     RECT  112.8 35.221 113.412 35.317 ;
     RECT  66.24 34.693 67.608 35.363 ;
     RECT  80.7 35.317 81.72 35.365 ;
     RECT  109.248 34.501 109.272 35.459 ;
     RECT  78 34.499 78.312 35.461 ;
     RECT  86.1 34.165 86.664 35.461 ;
     RECT  88.272 34.165 89.112 35.461 ;
     RECT  104.016 35.269 105.576 35.605 ;
     RECT  112.416 35.317 113.412 35.605 ;
     RECT  86.1 35.461 89.112 35.747 ;
     RECT  83.4 8.483 83.712 35.749 ;
     RECT  83.4 35.749 84.216 35.845 ;
     RECT  110.4 5.747 110.712 35.845 ;
     RECT  86.1 35.747 86.412 35.893 ;
     RECT  122.592 35.845 122.616 35.893 ;
     RECT  58.608 17.413 59.736 35.939 ;
     RECT  107.7 17.363 108.012 35.941 ;
     RECT  66.24 35.363 67.512 36.083 ;
     RECT  71.856 34.693 72.912 36.083 ;
     RECT  91.5 10.163 91.812 36.085 ;
     RECT  61.8 12.083 62.112 36.133 ;
     RECT  87.6 35.747 89.112 36.133 ;
     RECT  110.4 35.845 110.856 36.133 ;
     RECT  112.08 35.605 113.412 36.133 ;
     RECT  99.6 12.899 99.912 36.229 ;
     RECT  115.584 34.885 116.112 36.277 ;
     RECT  80.7 35.365 81.912 36.325 ;
     RECT  83.4 35.845 84.552 36.325 ;
     RECT  66.288 36.083 67.512 36.421 ;
     RECT  91.392 36.085 91.812 36.421 ;
     RECT  93.888 35.317 94.512 36.421 ;
     RECT  77.616 35.461 78.312 36.467 ;
     RECT  58.608 35.939 59.412 36.469 ;
     RECT  64.5 34.165 64.92 36.469 ;
     RECT  66.288 36.421 68.424 36.469 ;
     RECT  110.4 36.133 113.412 36.469 ;
     RECT  120.672 34.885 121.512 36.469 ;
     RECT  122.496 35.893 122.616 36.469 ;
     RECT  134.7 8.531 135.528 36.469 ;
     RECT  120.288 36.469 122.616 36.517 ;
     RECT  123.9 7.619 124.212 36.517 ;
     RECT  0.192 22.885 0.216 36.611 ;
     RECT  78 36.467 78.312 36.661 ;
     RECT  91.392 36.421 92.04 36.661 ;
     RECT  85.728 35.893 86.412 36.709 ;
     RECT  87.6 36.133 89.544 36.709 ;
     RECT  99.6 36.229 100.008 36.805 ;
     RECT  63.936 36.469 64.92 36.853 ;
     RECT  110.112 36.469 113.928 36.853 ;
     RECT  128.592 33.589 129.612 36.899 ;
     RECT  109.728 36.853 113.928 36.901 ;
     RECT  61.8 36.133 62.904 36.949 ;
     RECT  63.936 36.853 64.968 36.949 ;
     RECT  69.9 34.453 70.392 36.949 ;
     RECT  80.7 36.325 84.552 36.949 ;
     RECT  85.728 36.709 89.544 36.949 ;
     RECT  93.888 36.421 95.112 36.949 ;
     RECT  61.8 36.949 64.968 36.997 ;
     RECT  96.432 35.221 97.212 36.997 ;
     RECT  115.584 36.277 116.28 36.997 ;
     RECT  60.48 36.997 60.504 37.045 ;
     RECT  61.584 36.997 64.968 37.045 ;
     RECT  72.48 36.083 72.912 37.045 ;
     RECT  91.344 36.661 92.04 37.045 ;
     RECT  101.28 36.469 101.304 37.045 ;
     RECT  102.3 9.155 102.612 37.045 ;
     RECT  109.44 36.901 113.928 37.045 ;
     RECT  117.264 36.853 117.288 37.045 ;
     RECT  118.5 7.907 118.812 37.045 ;
     RECT  120.288 36.517 124.212 37.045 ;
     RECT  99.504 36.805 100.008 37.091 ;
     RECT  128.928 36.899 129.612 37.091 ;
     RECT  71.904 37.045 72.912 37.093 ;
     RECT  115.104 36.997 116.28 37.093 ;
     RECT  69.744 36.949 70.392 37.141 ;
     RECT  119.952 37.045 124.212 37.141 ;
     RECT  69.648 37.141 70.392 37.189 ;
     RECT  71.376 37.093 72.912 37.189 ;
     RECT  107.7 35.941 108.312 37.237 ;
     RECT  115.008 37.093 116.28 37.285 ;
     RECT  117.264 37.045 118.812 37.285 ;
     RECT  80.7 36.949 89.544 37.381 ;
     RECT  107.568 37.237 108.312 37.381 ;
     RECT  107.472 37.381 108.312 37.429 ;
     RECT  78 36.661 78.936 37.525 ;
     RECT  80.592 37.381 89.544 37.525 ;
     RECT  107.376 37.429 108.312 37.525 ;
     RECT  109.44 37.045 114.024 37.525 ;
     RECT  115.008 37.285 118.812 37.525 ;
     RECT  58.272 36.469 59.412 37.573 ;
     RECT  60.48 37.045 64.968 37.573 ;
     RECT  66.288 36.469 68.568 37.573 ;
     RECT  78 37.525 89.544 37.573 ;
     RECT  90.912 37.045 92.04 37.573 ;
     RECT  93.168 36.949 95.112 37.573 ;
     RECT  77.328 37.573 89.544 37.621 ;
     RECT  90.912 37.573 95.112 37.621 ;
     RECT  109.44 37.525 118.812 37.621 ;
     RECT  119.904 37.141 124.212 37.621 ;
     RECT  137.4 10.691 137.712 37.621 ;
     RECT  60.48 37.573 68.568 37.669 ;
     RECT  69.648 37.189 72.912 37.669 ;
     RECT  129.168 37.091 129.612 37.859 ;
     RECT  57.84 37.573 59.412 37.909 ;
     RECT  60.48 37.669 72.912 37.909 ;
     RECT  96.432 36.997 97.416 38.101 ;
     RECT  99.6 37.091 100.008 38.101 ;
     RECT  101.28 37.045 102.612 38.101 ;
     RECT  107.28 37.525 108.312 38.101 ;
     RECT  77.328 37.621 95.112 38.149 ;
     RECT  96.432 38.101 97.944 38.149 ;
     RECT  99.6 38.101 102.612 38.245 ;
     RECT  103.632 35.605 105.576 38.245 ;
     RECT  77.328 38.149 97.944 38.485 ;
     RECT  126.6 17.123 126.912 38.485 ;
     RECT  99.6 38.245 105.576 38.629 ;
     RECT  107.28 38.101 108.456 38.629 ;
     RECT  109.44 37.621 125.016 38.629 ;
     RECT  134.7 36.469 135.768 38.629 ;
     RECT  56.4 6.659 56.712 38.677 ;
     RECT  57.84 37.909 72.912 38.677 ;
     RECT  99.6 38.629 105.72 38.677 ;
     RECT  107.28 38.629 125.016 38.677 ;
     RECT  56.4 38.677 72.912 38.725 ;
     RECT  77.328 38.485 98.232 38.725 ;
     RECT  99.6 38.677 125.112 38.725 ;
     RECT  134.496 38.629 135.768 38.725 ;
     RECT  137.232 37.621 137.712 38.725 ;
     RECT  126.6 38.485 127.176 38.773 ;
     RECT  126.6 38.773 127.32 38.965 ;
     RECT  99.36 38.725 125.112 39.013 ;
     RECT  99.36 39.013 125.16 39.061 ;
     RECT  126.6 38.965 127.752 39.253 ;
     RECT  56.4 38.725 73.176 39.301 ;
     RECT  75.3 34.499 75.612 39.301 ;
     RECT  99.36 39.061 125.352 39.301 ;
     RECT  126.6 39.253 128.328 39.301 ;
     RECT  132 9.539 132.312 39.733 ;
     RECT  56.4 39.301 73.32 39.877 ;
     RECT  99.36 39.301 128.328 39.877 ;
     RECT  129.3 37.859 129.612 39.877 ;
     RECT  134.496 38.725 137.712 39.877 ;
     RECT  99.36 39.877 129.612 40.453 ;
     RECT  131.328 39.733 132.312 40.453 ;
     RECT  56.4 39.877 73.752 40.645 ;
     RECT  56.4 40.645 73.896 40.741 ;
     RECT  75.3 39.301 76.344 40.933 ;
     RECT  77.328 38.725 98.376 40.933 ;
     RECT  99.36 40.453 132.312 40.933 ;
     RECT  75.3 40.933 132.312 40.981 ;
     RECT  133.92 39.877 137.712 40.981 ;
     RECT  56.4 40.741 74.04 41.029 ;
     RECT  2.4 2.151 2.712 41.049 ;
     RECT  5.1 2.151 5.412 41.049 ;
     RECT  7.8 2.151 8.112 41.049 ;
     RECT  10.5 2.151 10.812 41.049 ;
     RECT  13.2 2.151 13.512 41.049 ;
     RECT  15.9 2.151 16.212 41.049 ;
     RECT  18.6 5.171 18.912 41.049 ;
     RECT  21.3 5.363 21.612 41.049 ;
     RECT  24 4.163 24.312 41.049 ;
     RECT  26.7 4.499 27.012 41.049 ;
     RECT  29.4 9.107 29.712 41.049 ;
     RECT  32.1 6.947 32.412 41.049 ;
     RECT  34.8 13.139 35.112 41.049 ;
     RECT  37.5 8.579 37.812 41.049 ;
     RECT  40.2 6.323 40.512 41.049 ;
     RECT  42.9 6.899 43.212 41.049 ;
     RECT  45.6 6.371 45.912 41.049 ;
     RECT  48.3 4.067 48.612 41.049 ;
     RECT  51 6.419 51.312 41.049 ;
     RECT  53.7 8.867 54.012 41.049 ;
     RECT  75.3 40.981 137.712 41.049 ;
     RECT  140.1 8.099 140.412 41.049 ;
     RECT  142.8 7.475 143.112 41.049 ;
     RECT  145.5 10.691 145.812 41.049 ;
     RECT  148.2 5.171 148.512 41.049 ;
     RECT  150.9 6.371 151.212 41.049 ;
     RECT  153.6 10.691 153.912 41.049 ;
     RECT  156.3 9.923 156.612 41.049 ;
     RECT  159 8.579 159.312 41.049 ;
     RECT  161.7 8.243 162.012 41.049 ;
     RECT  164.4 9.923 164.712 41.049 ;
     RECT  167.1 10.355 167.412 41.049 ;
     RECT  169.8 7.235 170.112 41.049 ;
     RECT  172.5 5.075 172.812 41.049 ;
     RECT  175.2 7.235 175.512 41.049 ;
     RECT  177.9 8.867 178.212 41.049 ;
     RECT  180.6 9.827 180.912 41.049 ;
     RECT  183.3 2.151 183.612 41.049 ;
     RECT  186 2.151 186.312 41.049 ;
     RECT  2.4 41.049 2.52 41.063 ;
     RECT  5.1 41.049 5.22 41.063 ;
     RECT  7.8 41.049 7.92 41.063 ;
     RECT  10.5 41.049 10.62 41.063 ;
     RECT  13.2 41.049 13.32 41.063 ;
     RECT  15.9 41.049 16.02 41.063 ;
     RECT  18.6 41.049 18.72 41.063 ;
     RECT  21.3 41.049 21.42 41.063 ;
     RECT  24 41.049 24.12 41.063 ;
     RECT  26.7 41.049 26.82 41.063 ;
     RECT  29.4 41.049 29.52 41.063 ;
     RECT  32.1 41.049 32.22 41.063 ;
     RECT  34.8 41.049 34.92 41.063 ;
     RECT  37.5 41.049 37.62 41.063 ;
     RECT  40.2 41.049 40.32 41.063 ;
     RECT  42.9 41.049 43.02 41.063 ;
     RECT  45.6 41.049 45.72 41.063 ;
     RECT  48.3 41.049 48.42 41.063 ;
     RECT  51 41.049 51.12 41.063 ;
     RECT  53.7 41.049 53.82 41.063 ;
     RECT  75.3 41.049 137.52 41.063 ;
     RECT  140.1 41.049 140.22 41.063 ;
     RECT  142.8 41.049 142.92 41.063 ;
     RECT  145.5 41.049 145.62 41.063 ;
     RECT  148.2 41.049 148.32 41.063 ;
     RECT  150.9 41.049 151.02 41.063 ;
     RECT  153.6 41.049 153.72 41.063 ;
     RECT  156.3 41.049 156.42 41.063 ;
     RECT  159 41.049 159.12 41.063 ;
     RECT  161.7 41.049 161.82 41.063 ;
     RECT  164.4 41.049 164.52 41.063 ;
     RECT  167.1 41.049 167.22 41.063 ;
     RECT  169.8 41.049 169.92 41.063 ;
     RECT  172.5 41.049 172.62 41.063 ;
     RECT  175.2 41.049 175.32 41.063 ;
     RECT  177.9 41.049 178.02 41.063 ;
     RECT  180.6 41.049 180.72 41.063 ;
     RECT  183.3 41.049 183.42 41.063 ;
     RECT  186 41.049 186.12 41.063 ;
     RECT  75.456 41.063 131.64 42.133 ;
     RECT  55.728 41.029 74.04 43.152 ;
     RECT  75.312 42.133 131.64 43.152 ;
     RECT  132.912 41.063 137.4 43.152 ;
  END
END qkd_pv_rs_hd_f
END LIBRARY
